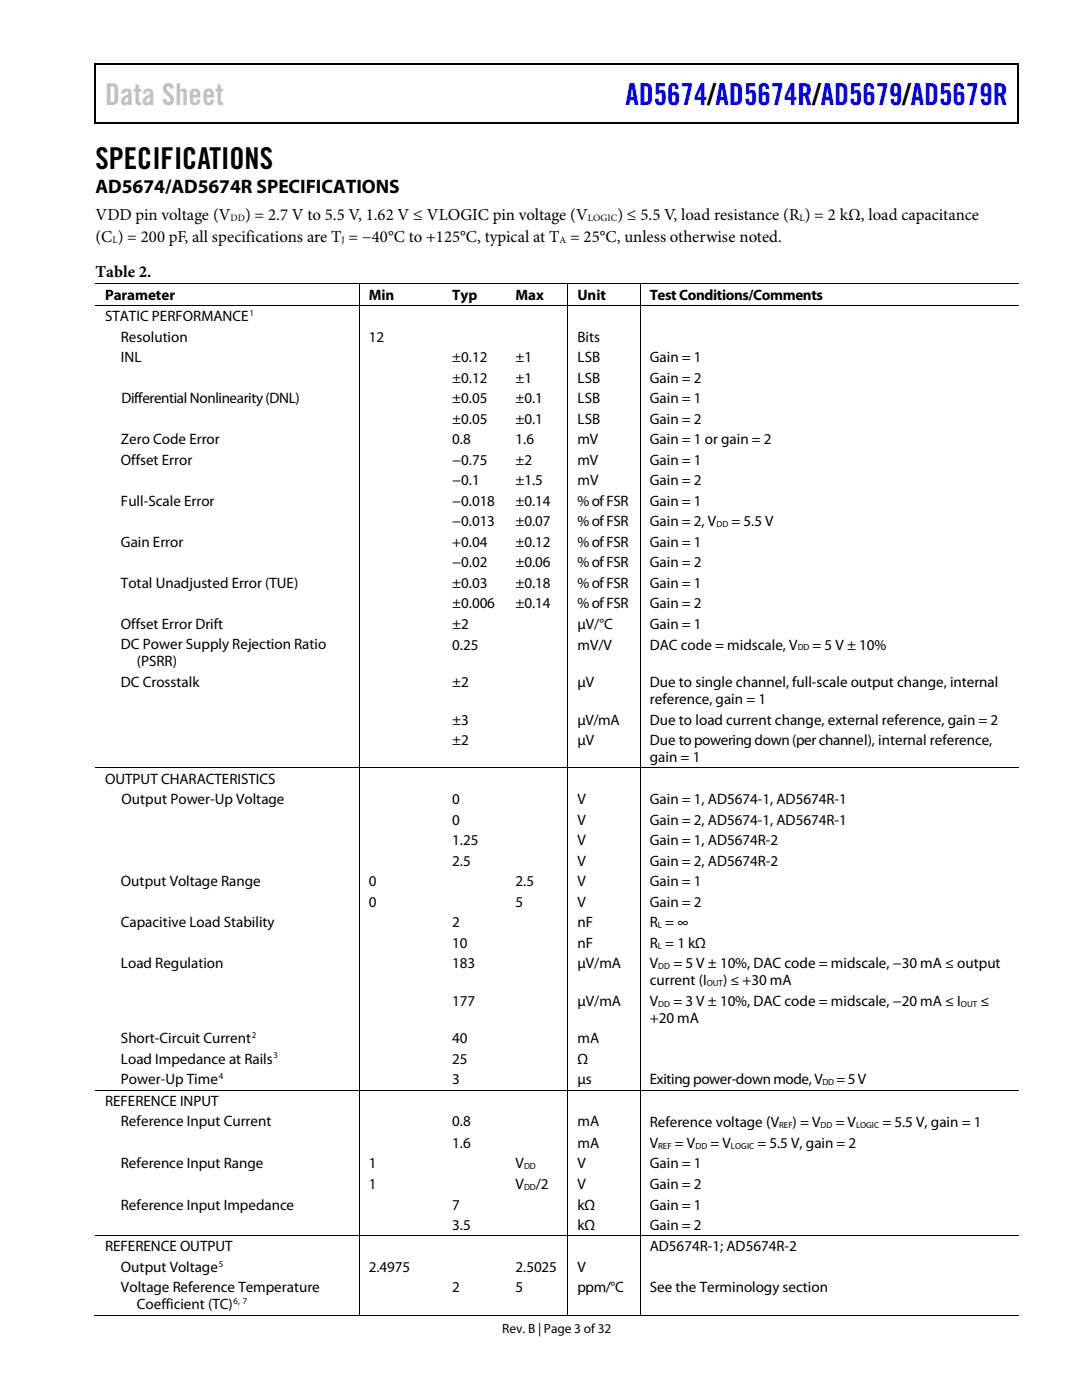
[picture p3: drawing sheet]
<svg xmlns="http://www.w3.org/2000/svg" width="216mm" height="279mm" viewBox="0 0 216 279" stroke-linecap="round" stroke-linejoin="round" font-family="sans-serif">
<defs><g id="words">
<text font-size="6" fill="#c1c1c1" x="21" y="21">Data Sheet</text>
<text font-size="6" fill="#00f" x="124.8" y="21">AD5674/AD5674R/AD5679/AD5679R</text>
<text font-size="6" x="19" y="33.7">SPECIFICATIONS</text>
<text font-size="3.9" x="19" y="38.5">AD5674/AD5674R SPECIFICATIONS</text>
<g font-size="3.3">
<text x="19" y="44">VDD pin voltage (V</text>
<text x="48.9" y="44">) = 2.7 V to 5.5 V, 1.62 V ≤ VLOGIC pin voltage (V</text>
<text x="123.2" y="44">) ≤ 5.5 V, load resistance (R ) = 2 kΩ, load capacitance</text>
<text x="19.1" y="48.3">(C ) = 200 pF, all specifications are T = −40°C to +125°C, typical at T = 25°C, unless otherwise noted.</text>
<text x="19.1" y="55.4">Table 2.</text>
</g>
<g font-size="3">
<text x="21" y="59.8">Parameter</text>
<text x="73.6" y="59.8">Min</text>
<text x="90.3" y="59.8">Typ</text>
<text x="102.9" y="59.8">Max</text>
<text x="115.2" y="59.8">Unit</text>
<text x="129.7" y="59.8">Test Conditions/Comments</text>
<text x="21" y="64.1">STATIC PERFORMANCE</text>
<text x="24.1" y="68.2">Resolution</text>
<text x="73.6" y="68.2">12</text>
<text x="115.2" y="68.2">Bits</text>
<text x="24.1" y="72.3">INL</text>
<text x="90.3" y="76.4">±0.12</text>
<text x="90.3" y="72.3">±0.12</text>
<text x="102.9" y="76.4">±1</text>
<text x="102.9" y="72.3">±1</text>
<text x="115.2" y="76.4">LSB</text>
<text x="115.2" y="72.3">LSB</text>
<text x="129.7" y="76.4">Gain = 2</text>
<text x="129.7" y="72.3">Gain = 1</text>
<text x="24.3" y="80.5">Differential Nonlinearity (DNL)</text>
<text x="90.3" y="80.5">±0.05</text>
<text x="102.9" y="80.5">±0.1</text>
<text x="115.2" y="80.5">LSB</text>
<text x="129.7" y="80.5">Gain = 1</text>
<text x="24.1" y="88.6">Zero Code Error</text>
<text x="90.3" y="88.6">0.8</text>
<text x="90.3" y="84.5">±0.05</text>
<text x="102.9" y="88.6">1.6</text>
<text x="102.9" y="84.5">±0.1</text>
<text x="115.2" y="88.6">mV</text>
<text x="115.2" y="84.5">LSB</text>
<text x="129.7" y="88.6">Gain = 1 or gain = 2</text>
<text x="129.7" y="84.5">Gain = 2</text>
<text x="24.1" y="92.8">Offset Error</text>
<text x="90.3" y="92.8">−0.75</text>
<text x="102.9" y="92.8">±2</text>
<text x="115.2" y="92.8">mV</text>
<text x="129.7" y="92.8">Gain = 1</text>
<text x="24.1" y="101">Full-Scale Error</text>
<text x="90.3" y="96.9">−0.1</text>
<text x="90.3" y="101">−0.018</text>
<text x="102.9" y="96.9">±1.5</text>
<text x="102.9" y="101">±0.14</text>
<text x="115.2" y="96.9">mV</text>
<text x="115.2" y="101">% of FSR</text>
<text x="129.7" y="96.9">Gain = 2</text>
<text x="129.7" y="101">Gain = 1</text>
<text x="90.3" y="105">−0.013</text>
<text x="102.9" y="105">±0.07</text>
<text x="115.2" y="105">% of FSR</text>
<text x="129.7" y="105">Gain = 2, V</text>
<text x="146" y="105">= 5.5 V</text>
<text x="24.1" y="109.1">Gain Error</text>
<text x="90.3" y="109.1">+0.04</text>
<text x="90.3" y="113.2">−0.02</text>
<text x="102.9" y="109.1">±0.12</text>
<text x="102.9" y="113.2">±0.06</text>
<text x="115.2" y="109.1">% of FSR</text>
<text x="115.2" y="113.2">% of FSR</text>
<text x="129.7" y="109.1">Gain = 1</text>
<text x="129.7" y="113.2">Gain = 2</text>
<text x="24.1" y="117.3">Total Unadjusted Error (TUE)</text>
<text x="90.3" y="117.3">±0.03</text>
<text x="102.9" y="117.3">±0.18</text>
<text x="115.2" y="117.3">% of FSR</text>
<text x="129.7" y="117.3">Gain = 1</text>
<text x="24.1" y="125.5">Offset Error Drift</text>
<text x="90.3" y="121.4">±0.006</text>
<text x="90.3" y="125.5">±2</text>
<text x="102.9" y="121.4">±0.14</text>
<text x="115.2" y="121.4">% of FSR</text>
<text x="115.2" y="125.5">µV/°C</text>
<text x="129.7" y="125.5">Gain = 1</text>
<text x="129.7" y="121.4">Gain = 2</text>
<text x="24.1" y="129.6">DC Power Supply Rejection Ratio</text>
<text x="90.3" y="129.6">0.25</text>
<text x="115.2" y="129.6">mV/V</text>
<text x="129.7" y="129.6">DAC code = midscale, V</text>
<text x="162.1" y="129.6">= 5 V ± 10%</text>
<text x="24.1" y="137.1">DC Crosstalk</text>
<text x="27.3" y="133">(PSRR)</text>
<text x="90.3" y="137.1">±2</text>
<text x="115.2" y="137.1">µV</text>
<text x="129.7" y="137.1">Due to single channel, full-scale output change, internal</text>
<text x="129.7" y="140.5">reference, gain = 1</text>
<text x="90.3" y="144.6">±3</text>
<text x="90.3" y="148.7">±2</text>
<text x="115.2" y="148.7">µV</text>
<text x="115.2" y="144.6">µV/mA</text>
<text x="129.7" y="148.7">Due to powering down (per channel), internal reference,</text>
<text x="129.7" y="144.6">Due to load current change, external reference, gain = 2</text>
<text x="129.7" y="152.1">gain = 1</text>
<text x="21" y="156.4">OUTPUT CHARACTERISTICS</text>
<text x="24.3" y="160.4">Output Power-Up Voltage</text>
<text x="90.3" y="160.4">0</text>
<text x="115.2" y="160.4">V</text>
<text x="129.7" y="160.4">Gain = 1, AD5674-1, AD5674R-1</text>
<text x="90.3" y="164.5">0</text>
<text x="115.2" y="164.5">V</text>
<text x="129.7" y="164.5">Gain = 2, AD5674-1, AD5674R-1</text>
<text x="90.3" y="168.7">1.25</text>
<text x="90.3" y="172.8">2.5</text>
<text x="115.2" y="168.7">V</text>
<text x="115.2" y="172.8">V</text>
<text x="129.7" y="168.7">Gain = 1, AD5674R-2</text>
<text x="129.7" y="172.8">Gain = 2, AD5674R-2</text>
<text x="24.1" y="176.9">Output Voltage Range</text>
<text x="73.6" y="176.9">0</text>
<text x="102.9" y="176.9">2.5</text>
<text x="115.2" y="176.9">V</text>
<text x="129.7" y="176.9">Gain = 1</text>
<text x="24.1" y="185">Capacitive Load Stability</text>
<text x="73.6" y="180.9">0</text>
<text x="90.3" y="185">2</text>
<text x="102.9" y="180.9">5</text>
<text x="115.2" y="180.9">V</text>
<text x="115.2" y="185">nF</text>
<text x="129.7" y="180.9">Gain = 2</text>
<text x="129.7" y="185">R = ∞</text>
<text x="90.3" y="189.1">10</text>
<text x="115.2" y="189.1">nF</text>
<text x="129.7" y="189.1">R = 1 kΩ</text>
<text x="24.1" y="193.3">Load Regulation</text>
<text x="90.3" y="193.3">183</text>
<text x="115.2" y="193.3">µV/mA</text>
<text x="129.7" y="196.6">current (I</text>
<text x="129.7" y="193.2">V</text>
<text x="134.4" y="193.2">= 5 V ± 10%, DAC code = midscale, −30 mA ≤ output</text>
<text x="144.3" y="196.6">) ≤ +30 mA</text>
<text x="90.3" y="200.7">177</text>
<text x="115.2" y="200.7">µV/mA</text>
<text x="129.7" y="200.7">V</text>
<text x="134.4" y="200.7">= 3 V ± 10%, DAC code = midscale, −20 mA ≤ I</text>
<text x="195.6" y="200.7">≤</text>
<text x="24.1" y="208.2">Short-Circuit Current</text>
<text x="90.3" y="208.2">40</text>
<text x="115.2" y="208.2">mA</text>
<text x="129.7" y="204.1">+20 mA</text>
<text x="24.1" y="212.3">Load Impedance at Rails</text>
<text x="90.3" y="212.3">25</text>
<text x="115.2" y="212.3">Ω</text>
<text x="21" y="220.7">REFERENCE INPUT</text>
<text x="24.1" y="216.4">Power-Up Time</text>
<text x="90.3" y="216.4">3</text>
<text x="115.2" y="216.4">µs</text>
<text x="129.7" y="216.4">Exiting power-down mode, V</text>
<text x="166.9" y="216.4">= 5 V</text>
<text x="24.1" y="224.8">Reference Input Current</text>
<text x="90.3" y="224.8">0.8</text>
<text x="115.2" y="224.8">mA</text>
<text x="129.7" y="224.9">Reference voltage (V</text>
<text x="158.2" y="224.9">) = V</text>
<text x="166.8" y="224.9">= V</text>
<text x="176.1" y="224.9">= 5.5 V, gain = 1</text>
<text x="24.1" y="233.2">Reference Input Range</text>
<text x="73.6" y="233.2">1</text>
<text x="90.3" y="229.1">1.6</text>
<text x="102.9" y="233.2">V</text>
<text x="115.2" y="229.1">mA</text>
<text x="115.2" y="233.2">V</text>
<text x="129.7" y="233.2">Gain = 1</text>
<text x="129.7" y="229.1">V</text>
<text x="134.7" y="229.1">= V</text>
<text x="141.8" y="229.1">= V</text>
<text x="151.1" y="229.1">= 5.5 V, gain = 2</text>
<text x="73.6" y="237.3">1</text>
<text x="102.9" y="237.3">V</text>
<text x="106.9" y="237.3">/2</text>
<text x="115.2" y="237.3">V</text>
<text x="129.7" y="237.3">Gain = 2</text>
<text x="24.1" y="241.4">Reference Input Impedance</text>
<text x="90.3" y="241.4">7</text>
<text x="90.3" y="245.4">3.5</text>
<text x="115.2" y="241.4">kΩ</text>
<text x="115.2" y="245.4">kΩ</text>
<text x="129.7" y="241.4">Gain = 1</text>
<text x="129.7" y="245.4">Gain = 2</text>
<text x="21" y="249.7">REFERENCE OUTPUT</text>
<text x="129.7" y="249.7">AD5674R-1; AD5674R-2</text>
<text x="24.1" y="253.8">Output Voltage</text>
<text x="24.1" y="257.9">Voltage Reference Temperature</text>
<text x="73.6" y="253.8">2.4975</text>
<text x="90.3" y="257.9">2</text>
<text x="102.9" y="257.9">5</text>
<text x="102.9" y="253.8">2.5025</text>
<text x="115.2" y="257.9">ppm/°C</text>
<text x="115.2" y="253.8">V</text>
<text x="129.7" y="257.9">See the Terminology section</text>
<text x="27.3" y="261.3">Coefficient (TC)</text>
</g>
<text font-size="2.7" x="100.2" y="266">Rev. B | Page 3 of32</text>
<g font-size="1.9">
<text x="46" y="44.2">DD</text>
<text x="117.3" y="44.2">LOGIC</text>
<text x="159.5" y="44.2">L</text>
<text x="22.4" y="48.4">L</text>
<text x="68.2" y="48.4">J</text>
<text x="111.6" y="48.4">A</text>
</g>
<g font-size="1.8">
<text x="49.8" y="63">1</text>
<text x="143" y="105.2">DD</text>
<text x="159.2" y="129.8">DD</text>
<text x="131.3" y="185.2">L</text>
<text x="131.3" y="189.3">L</text>
<text x="131.4" y="193.4">DD</text>
<text x="141" y="196.8">OUT</text>
<text x="131.4" y="200.9">DD</text>
<text x="191.7" y="200.9">OUT</text>
<text x="50.2" y="207.1">2</text>
<text x="43.6" y="215.3">4</text>
<text x="54.6" y="211.2">3</text>
<text x="164.1" y="216.6">DD</text>
<text x="155.4" y="225.1">REF</text>
<text x="163.7" y="225.1">DD</text>
<text x="170.8" y="225.1">LOGIC</text>
<text x="104.6" y="233.3">DD</text>
<text x="131.4" y="229.2">REF</text>
<text x="138.8" y="229.2">DD</text>
<text x="145.8" y="229.2">LOGIC</text>
<text x="104.6" y="237.4">DD</text>
<text x="43.6" y="252.8">5</text>
<text x="46.6" y="260.2">6, 7</text>
</g>
</g></defs>
<g fill="#000">
<path d="M18.9 12.7h.3v1h-.3zM18.9 12.7h.3v.3h-.3zM83.1 12.7h.3v.3h-.3zM202.9 12.7h.3v1h-.3zM202.9 12.7h.3v.3h-.3zM18.9 24.4h.3v.2h-.3zM82.9 24.4h.2v.2h-.2zM202.9 24.4h.3v.2h-.3zM71.6 56.6h.2v.1h-.2zM88.3 56.6h.2v.1h-.2zM101 56.6h.1v.1h-.1zM113.2 56.6h.2v.1h-.2z"/>
<path d="M127.7 56.6h.1v.1h-.1zM71.6 60.9h.2v.1h-.2zM88.3 60.9h.2v.1h-.2zM101 60.9h.1v.1h-.1zM113.2 60.9h.2v.1h-.2zM127.7 60.9h.1v.1h-.1zM71.6 153.2h.2v.1h-.2zM88.3 153.2h.2v.1h-.2zM101 153.2h.1v.1h-.1zM113.2 153.2h.2v.1h-.2zM127.7 153.2h.1v.1h-.1zM71.6 217.5h.2v.2h-.2z"/>
<path d="M88.3 217.5h.2v.2h-.2zM101 217.5h.1v.2h-.1zM113.2 217.5h.2v.2h-.2zM127.7 217.5h.1v.2h-.1zM71.6 246.5h.2v.2h-.2zM88.3 246.5h.2v.2h-.2zM101 246.5h.1v.2h-.1zM113.2 246.5h.2v.2h-.2zM127.7 246.5h.1v.2h-.1zM71.6 262.4h.2v.2h-.2zM88.1 262.4h.2v.2h-.2zM100.7 262.4h.2v.2h-.2z"/>
<path d="M113.2 262.4h.2v.2h-.2zM127.7 262.4h.1v.2h-.1z"/>
</g>
<path d="M19 13.7v10.7M19.2 12.8h63.9M83.4 12.8h119.5M203 13.7v10.7M19.2 24.5h183.7" fill="none" stroke="#000" stroke-width=".25"/>
<g fill="none" stroke="#000" stroke-width=".2">
<path d="M19 56.6h52.6M71.7 56.7v4.2M71.8 56.6h16.5M88.5 56.6h12.5M101.1 56.6h12.1M113.3 56.7v4.2M113.4 56.6h14.3M127.8 56.7v4.2M127.8 56.6h75.4M19 61h52.6M71.7 61v92.2M71.8 61h16.5"/>
<path d="M88.5 61h12.5M101.1 61h12.1M113.3 61v92.2M113.4 61h14.3M127.8 61v92.2M127.8 61h75.4M19 153.2h52.6M71.7 153.3v64.2M71.8 153.2h16.5M88.5 153.2h12.5M101.1 153.2h12.1M113.3 153.3v64.2"/>
<path d="M113.4 153.2h14.3M127.8 153.3v64.2M127.8 153.2h75.4M19 217.6h52.6M71.7 217.7v28.8M71.8 217.6h16.5M88.5 217.6h12.5M101.1 217.6h12.1M113.3 217.7v28.8M113.4 217.6h14.3M127.8 217.7v28.8M127.8 217.6h75.4"/>
<path d="M19 246.6h52.6M71.7 246.7v15.7M71.8 246.6h16.5M88.5 246.6h12.5M101.1 246.6h12.1M113.3 246.7v15.7M113.4 246.6h14.3M127.8 246.7v15.7M127.8 246.6h75.4M18.8 262.5h52.8M71.8 262.5h41.4M113.4 262.5h14.3"/>
<path d="M127.8 262.5h75.4"/>
</g>
<use href="#words"/>
</svg>
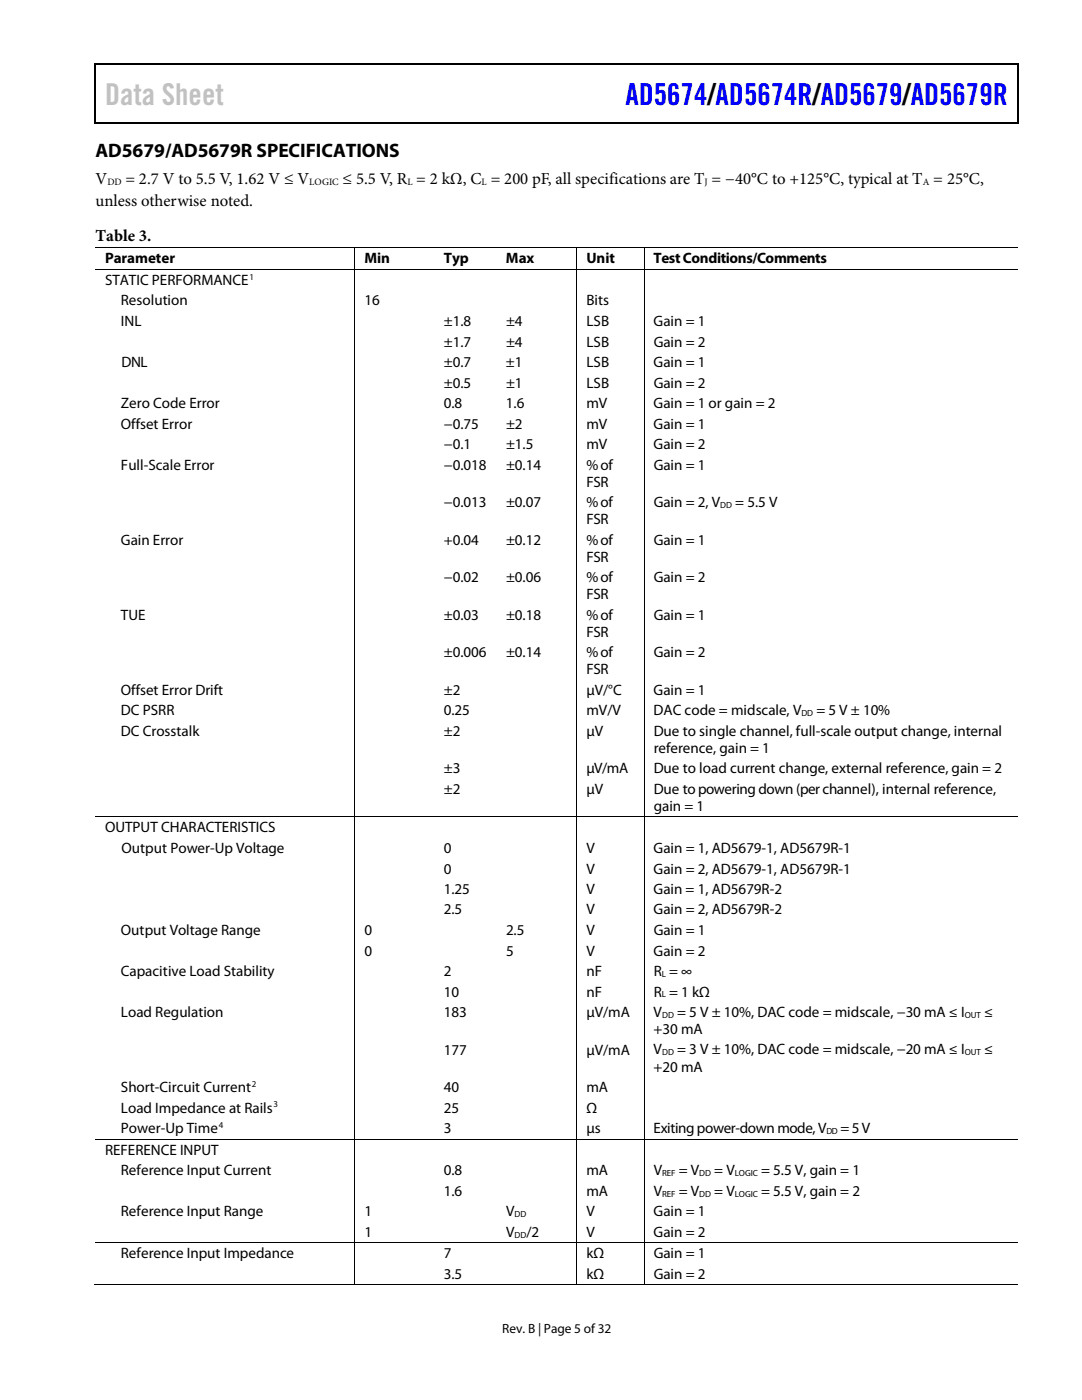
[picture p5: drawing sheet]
<svg xmlns="http://www.w3.org/2000/svg" width="216mm" height="279mm" viewBox="0 0 216 279" stroke-linecap="round" stroke-linejoin="round" font-family="sans-serif">
<defs><g id="words">
<text font-size="6" fill="#c1c1c1" x="21" y="21">Data Sheet</text>
<text font-size="6" fill="#00f" x="124.8" y="21">AD5674/AD5674R/AD5679/AD5679R</text>
<text font-size="3.9" x="19" y="31.3">AD5679/AD5679R SPECIFICATIONS</text>
<g font-size="3.3">
<text x="19" y="36.8">V</text>
<text x="19.1" y="41.1">unless otherwise noted.</text>
<text x="25.1" y="36.8">= 2.7 V to 5.5 V, 1.62 V ≤ V</text>
<text x="68.4" y="36.8">≤ 5.5 V, R = 2 kΩ, C = 200 pF, all specifications are T = −40°C to +125°C, typical at T = 25°C,</text>
<text x="19.1" y="48.2">Table 3.</text>
</g>
<g font-size="3">
<text x="21" y="52.6">Parameter</text>
<text x="72.7" y="52.6">Min</text>
<text x="88.6" y="52.6">Typ</text>
<text x="101" y="52.6">Max</text>
<text x="117" y="52.6">Unit</text>
<text x="130.4" y="52.6">Test Conditions/Comments</text>
<text x="21" y="56.9">STATIC PERFORMANCE</text>
<text x="24.1" y="61">Resolution</text>
<text x="24.1" y="65.1">INL</text>
<text x="72.7" y="61">16</text>
<text x="88.6" y="65.1">±1.8</text>
<text x="101" y="65.1">±4</text>
<text x="117" y="61">Bits</text>
<text x="117" y="65.1">LSB</text>
<text x="130.4" y="65.1">Gain = 1</text>
<text x="88.6" y="69.2">±1.7</text>
<text x="101" y="69.2">±4</text>
<text x="117" y="69.2">LSB</text>
<text x="130.4" y="69.2">Gain = 2</text>
<text x="24.3" y="73.3">DNL</text>
<text x="88.6" y="73.3">±0.7</text>
<text x="88.6" y="77.3">±0.5</text>
<text x="101" y="73.3">±1</text>
<text x="101" y="77.3">±1</text>
<text x="117" y="73.3">LSB</text>
<text x="117" y="77.3">LSB</text>
<text x="130.4" y="73.3">Gain = 1</text>
<text x="130.4" y="77.3">Gain = 2</text>
<text x="24.1" y="81.4">Zero Code Error</text>
<text x="88.6" y="81.4">0.8</text>
<text x="101" y="81.4">1.6</text>
<text x="117" y="81.4">mV</text>
<text x="130.4" y="81.4">Gain = 1 or gain = 2</text>
<text x="24.1" y="85.6">Offset Error</text>
<text x="88.6" y="85.6">−0.75</text>
<text x="88.6" y="89.7">−0.1</text>
<text x="101" y="85.6">±2</text>
<text x="101" y="89.7">±1.5</text>
<text x="117" y="89.7">mV</text>
<text x="117" y="85.6">mV</text>
<text x="130.4" y="89.7">Gain = 2</text>
<text x="130.4" y="85.6">Gain = 1</text>
<text x="24.1" y="93.8">Full-Scale Error</text>
<text x="88.6" y="93.8">−0.018</text>
<text x="101" y="93.8">±0.14</text>
<text x="117" y="93.7">% of</text>
<text x="130.4" y="93.8">Gain = 1</text>
<text x="88.6" y="101.2">−0.013</text>
<text x="101" y="101.2">±0.07</text>
<text x="117" y="97.1">FSR</text>
<text x="117" y="101.2">% of</text>
<text x="130.4" y="101.2">Gain = 2, V</text>
<text x="146.7" y="101.2">= 5.5 V</text>
<text x="117" y="104.6">FSR</text>
<text x="24.1" y="108.7">Gain Error</text>
<text x="88.6" y="108.7">+0.04</text>
<text x="101" y="108.7">±0.12</text>
<text x="117" y="108.7">% of</text>
<text x="117" y="112.1">FSR</text>
<text x="130.4" y="108.7">Gain = 1</text>
<text x="88.6" y="116.2">−0.02</text>
<text x="101" y="116.2">±0.06</text>
<text x="117" y="116.2">% of</text>
<text x="117" y="119.6">FSR</text>
<text x="130.4" y="116.2">Gain = 2</text>
<text x="24.1" y="123.7">TUE</text>
<text x="88.6" y="123.7">±0.03</text>
<text x="101" y="123.7">±0.18</text>
<text x="117" y="123.7">% of</text>
<text x="130.4" y="123.7">Gain = 1</text>
<text x="88.6" y="131.2">±0.006</text>
<text x="101" y="131.2">±0.14</text>
<text x="117" y="127.1">FSR</text>
<text x="117" y="131.1">% of</text>
<text x="130.4" y="131.2">Gain = 2</text>
<text x="117" y="134.5">FSR</text>
<text x="24.1" y="138.7">Offset Error Drift</text>
<text x="24.1" y="142.8">DC PSRR</text>
<text x="88.6" y="138.7">±2</text>
<text x="88.6" y="142.8">0.25</text>
<text x="117" y="142.8">mV/V</text>
<text x="117" y="138.7">µV/°C</text>
<text x="130.4" y="142.8">DAC code = midscale, V</text>
<text x="130.4" y="138.7">Gain = 1</text>
<text x="162.9" y="142.8">= 5 V ± 10%</text>
<text x="24.1" y="146.9">DC Crosstalk</text>
<text x="88.6" y="146.9">±2</text>
<text x="117" y="146.9">µV</text>
<text x="130.4" y="146.8">Due to single channel, full-scale output change, internal</text>
<text x="88.6" y="154.3">±3</text>
<text x="117" y="154.3">µV/mA</text>
<text x="130.4" y="154.3">Due to load current change, external reference, gain = 2</text>
<text x="130.4" y="150.2">reference, gain = 1</text>
<text x="88.6" y="158.5">±2</text>
<text x="117" y="158.5">µV</text>
<text x="130.4" y="158.4">Due to powering down (per channel), internal reference,</text>
<text x="130.4" y="161.8">gain = 1</text>
<text x="21" y="166.1">OUTPUT CHARACTERISTICS</text>
<text x="24.3" y="170.2">Output Power-Up Voltage</text>
<text x="88.6" y="170.2">0</text>
<text x="117" y="170.2">V</text>
<text x="130.4" y="170.2">Gain = 1, AD5679-1, AD5679R-1</text>
<text x="88.6" y="174.3">0</text>
<text x="88.6" y="178.4">1.25</text>
<text x="117" y="178.4">V</text>
<text x="117" y="174.3">V</text>
<text x="130.4" y="178.4">Gain = 1, AD5679R-2</text>
<text x="130.4" y="174.3">Gain = 2, AD5679-1, AD5679R-1</text>
<text x="88.6" y="182.5">2.5</text>
<text x="117" y="182.5">V</text>
<text x="130.4" y="182.5">Gain = 2, AD5679R-2</text>
<text x="24.1" y="186.6">Output Voltage Range</text>
<text x="72.7" y="186.6">0</text>
<text x="72.7" y="190.7">0</text>
<text x="101" y="186.6">2.5</text>
<text x="101" y="190.7">5</text>
<text x="117" y="186.6">V</text>
<text x="117" y="190.7">V</text>
<text x="130.4" y="190.7">Gain = 2</text>
<text x="130.4" y="186.6">Gain = 1</text>
<text x="24.1" y="194.8">Capacitive Load Stability</text>
<text x="88.6" y="194.8">2</text>
<text x="117" y="194.8">nF</text>
<text x="130.4" y="194.8">R = ∞</text>
<text x="24.1" y="203">Load Regulation</text>
<text x="88.6" y="198.9">10</text>
<text x="88.6" y="203">183</text>
<text x="117" y="198.9">nF</text>
<text x="117" y="203">µV/mA</text>
<text x="130.4" y="202.9">V</text>
<text x="130.4" y="198.9">R = 1 kΩ</text>
<text x="135.1" y="202.9">= 5 V ± 10%, DAC code = midscale, −30 mA ≤ I</text>
<text x="196.4" y="202.9">≤</text>
<text x="130.4" y="206.4">+30 mA</text>
<text x="88.6" y="210.5">177</text>
<text x="117" y="210.5">µV/mA</text>
<text x="130.4" y="213.9">+20 mA</text>
<text x="130.4" y="210.4">V</text>
<text x="135.1" y="210.4">= 3 V ± 10%, DAC code = midscale, −20 mA ≤ I</text>
<text x="196.4" y="210.4">≤</text>
<text x="24.1" y="218">Short-Circuit Current</text>
<text x="88.6" y="218">40</text>
<text x="117" y="218">mA</text>
<text x="24.1" y="222.1">Load Impedance at Rails</text>
<text x="24.1" y="226.2">Power-Up Time</text>
<text x="88.6" y="222.1">25</text>
<text x="88.6" y="226.2">3</text>
<text x="117" y="222.1">Ω</text>
<text x="117" y="226.2">µs</text>
<text x="130.4" y="226.2">Exiting power-down mode, V</text>
<text x="167.7" y="226.2">= 5 V</text>
<text x="21" y="230.5">REFERENCE INPUT</text>
<text x="24.1" y="234.5">Reference Input Current</text>
<text x="88.6" y="234.5">0.8</text>
<text x="88.6" y="238.6">1.6</text>
<text x="117" y="234.5">mA</text>
<text x="117" y="238.6">mA</text>
<text x="130.4" y="234.5">V</text>
<text x="130.4" y="238.6">V</text>
<text x="135.4" y="234.5">= V</text>
<text x="135.4" y="238.6">= V</text>
<text x="142.5" y="234.5">= V</text>
<text x="142.5" y="238.6">= V</text>
<text x="151.9" y="234.5">= 5.5 V, gain = 1</text>
<text x="151.9" y="238.6">= 5.5 V, gain = 2</text>
<text x="24.1" y="242.7">Reference Input Range</text>
<text x="72.7" y="242.7">1</text>
<text x="101" y="242.7">V</text>
<text x="117" y="242.7">V</text>
<text x="130.4" y="242.7">Gain = 1</text>
<text x="24.1" y="251.1">Reference Input Impedance</text>
<text x="72.7" y="246.8">1</text>
<text x="88.6" y="251.1">7</text>
<text x="101" y="246.8">V</text>
<text x="105" y="246.8">/2</text>
<text x="117" y="246.8">V</text>
<text x="117" y="251.1">kΩ</text>
<text x="130.4" y="246.8">Gain = 2</text>
<text x="130.4" y="251.1">Gain = 1</text>
<text x="88.6" y="255.2">3.5</text>
<text x="117" y="255.2">kΩ</text>
<text x="130.4" y="255.2">Gain = 2</text>
</g>
<text font-size="2.7" x="100.2" y="266">Rev. B | Page 5 of32</text>
<g font-size="1.9">
<text x="21.4" y="37">DD</text>
<text x="61.7" y="37">LOGIC</text>
<text x="81.3" y="37">L</text>
<text x="96.1" y="37">L</text>
<text x="140.6" y="37">J</text>
<text x="184.1" y="37">A</text>
</g>
<g font-size="1.8">
<text x="49.8" y="55.8">1</text>
<text x="143.7" y="101.4">DD</text>
<text x="159.9" y="143">DD</text>
<text x="132" y="195">L</text>
<text x="132" y="199.1">L</text>
<text x="132.1" y="203.1">DD</text>
<text x="192.5" y="203.1">OUT</text>
<text x="132.1" y="210.6">DD</text>
<text x="192.5" y="210.6">OUT</text>
<text x="50.2" y="216.9">2</text>
<text x="54.6" y="221">3</text>
<text x="43.6" y="225.1">4</text>
<text x="164.9" y="226.4">DD</text>
<text x="132.1" y="234.7">REF</text>
<text x="132.1" y="238.8">REF</text>
<text x="139.5" y="234.7">DD</text>
<text x="139.5" y="238.8">DD</text>
<text x="146.6" y="234.7">LOGIC</text>
<text x="146.6" y="238.8">LOGIC</text>
<text x="102.7" y="242.9">DD</text>
<text x="102.7" y="247">DD</text>
</g>
</g></defs>
<g fill="#000">
<path d="M18.9 12.7h.3v1h-.3zM18.9 12.7h.3v.3h-.3zM83.1 12.7h.3v.3h-.3zM202.9 12.7h.3v1h-.3zM202.9 12.7h.3v.3h-.3zM18.9 24.4h.3v.2h-.3zM82.9 24.4h.2v.2h-.2zM202.9 24.4h.3v.2h-.3zM70.7 49.4h.2v.1h-.2zM70.7 53.7h.2v.1h-.2zM86.7 49.4h.2v.1h-.2zM86.7 53.7h.2v.1h-.2z"/>
<path d="M99.1 49.4h.1v.1h-.1zM99.1 53.7h.1v.1h-.1zM115 49.4h.2v.1h-.2zM115 53.7h.2v.1h-.2zM128.4 49.4h.2v.1h-.2zM128.4 53.7h.2v.1h-.2zM70.7 162.9h.2v.2h-.2zM86.7 162.9h.2v.2h-.2zM99.1 162.9h.1v.2h-.1zM115 162.9h.2v.2h-.2zM128.4 162.9h.2v.2h-.2zM70.7 227.2h.2v.2h-.2z"/>
<path d="M86.7 227.2h.2v.2h-.2zM99.1 227.2h.1v.2h-.1zM115 227.2h.2v.2h-.2zM128.4 227.2h.2v.2h-.2zM70.7 247.9h.2v.2h-.2zM70.7 256.3h.2v.2h-.2zM86.4 256.3h.2v.2h-.2zM86.7 247.9h.2v.2h-.2zM98.8 256.3h.2v.2h-.2zM99.1 247.9h.1v.2h-.1zM115 247.9h.2v.2h-.2zM115 256.3h.2v.2h-.2z"/>
<path d="M128.4 247.9h.2v.2h-.2zM128.4 256.3h.2v.2h-.2z"/>
</g>
<path d="M19 13.7v10.7M19.2 12.8h63.9M83.4 12.8h119.5M203 13.7v10.7M19.2 24.5h183.7" fill="none" stroke="#000" stroke-width=".25"/>
<g fill="none" stroke="#000" stroke-width=".2">
<path d="M19 49.4h51.7M19 53.8h51.7M70.8 49.5v4.2M70.8 53.8v109.1M70.9 49.4h15.8M70.9 53.8h15.8M86.9 49.4h12.2M86.9 53.8h12.2M99.2 49.4h15.8M99.2 53.8h15.8M115.1 49.5v4.2M115.1 53.8v109.1"/>
<path d="M115.2 49.4h13.2M115.2 53.8h13.2M128.5 49.5v4.2M128.5 53.8v109.1M128.6 49.4h74.6M128.6 53.8h74.6M19 163h51.7M70.8 163.1v64.1M70.9 163h15.8M86.9 163h12.2M99.2 163h15.8M115.1 163.1v64.1"/>
<path d="M115.2 163h13.2M128.5 163.1v64.1M128.6 163h74.6M19 227.3h51.7M70.8 227.4v20.5M70.9 227.3h15.8M86.9 227.3h12.2M99.2 227.3h15.8M115.1 227.4v20.5M115.2 227.3h13.2M128.5 227.4v20.5M128.6 227.3h74.6"/>
<path d="M18.8 256.4h51.9M19 248h51.7M70.8 248.1v8.2M70.9 248h15.8M70.9 256.4h44.1M86.9 248h12.2M99.2 248h15.8M115.1 248.1v8.2M115.2 248h13.2M115.2 256.4h13.2M128.5 248.1v8.2M128.6 248h74.6"/>
<path d="M128.6 256.4h74.6"/>
</g>
<use href="#words"/>
</svg>
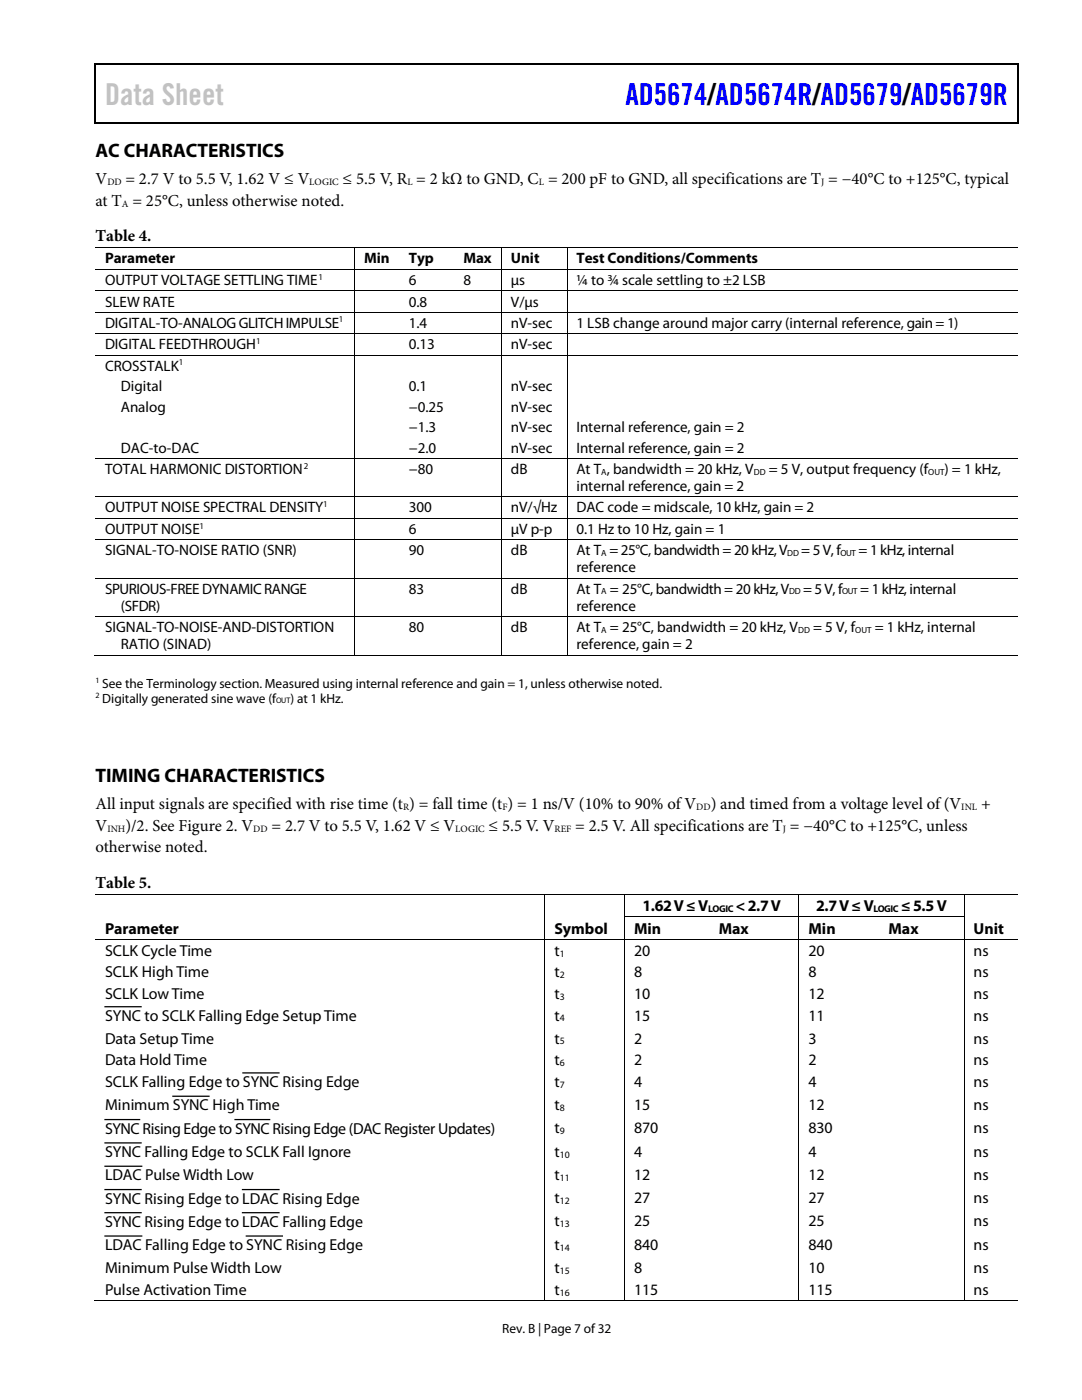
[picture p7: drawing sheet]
<svg xmlns="http://www.w3.org/2000/svg" width="216mm" height="279mm" viewBox="0 0 216 279" stroke-linecap="round" stroke-linejoin="round" font-family="sans-serif">
<defs><g id="words">
<text font-size="6" fill="#c1c1c1" x="21" y="21">Data Sheet</text>
<text font-size="6" fill="#00f" x="124.8" y="21">AD5674/AD5674R/AD5679/AD5679R</text>
<g font-size="3.9">
<text x="19" y="31.3">AC CHARACTERISTICS</text>
<text x="19" y="156.1">TIMING CHARACTERISTICS</text>
</g>
<g font-size="3.3">
<text x="19" y="36.8">V</text>
<text x="19.1" y="41.1">at T = 25°C, unless otherwise noted.</text>
<text x="25.1" y="36.8">= 2.7 V to 5.5 V, 1.62 V ≤ V</text>
<text x="68.4" y="36.8">≤ 5.5 V, R = 2 kΩ to GND, C = 200 pF to GND, all specifications are T = −40°C to +125°C, typical</text>
<text x="19" y="48.2">Table 4.</text>
<text x="19" y="161.5">All input signals are specified with rise time (t ) = fall time (t ) = 1 ns/V (10% to 90% of V</text>
<text x="141.8" y="161.5">) and timed from a voltage level of (V</text>
<text x="195.7" y="161.5">+</text>
<text x="19.1" y="165.8">V</text>
<text x="25" y="165.8">)/2. See Figure 2. V</text>
<text x="54.2" y="165.8">= 2.7 V to 5.5 V, 1.62 V ≤ V</text>
<text x="97.5" y="165.8">≤ 5.5 V. V</text>
<text x="114.8" y="165.8">= 2.5 V. All specifications are T = −40°C to +125°C, unless</text>
<text x="19.1" y="170.1">otherwise noted.</text>
<text x="19.1" y="177.2">Table 5.</text>
</g>
<g font-size="3.2">
<text x="128.2" y="181.8">1.62 V≤ V</text>
<text x="146.9" y="181.8">&lt;2.7 V</text>
<text x="162.9" y="181.8">2.7 V≤ V</text>
<text x="179.8" y="181.8">≤5.5V</text>
<text x="21" y="186.3">Parameter</text>
<text x="21" y="190.8">SCLK Cycle Time</text>
<text x="110.6" y="186.3">Symbol</text>
<text x="110.6" y="190.8">t</text>
<text x="126.5" y="186.3">Min</text>
<text x="126.5" y="190.8">20</text>
<text x="143.4" y="186.3">Max</text>
<text x="161.3" y="190.8">20</text>
<text x="161.3" y="186.3">Min</text>
<text x="177.3" y="186.3">Max</text>
<text x="194.3" y="186.3">Unit</text>
<text x="194.3" y="190.8">ns</text>
<text x="21" y="195.1">SCLK High Time</text>
<text x="110.6" y="195.1">t</text>
<text x="126.5" y="195.1">8</text>
<text x="161.3" y="195.1">8</text>
<text x="194.3" y="195.1">ns</text>
<text x="21" y="199.3">SCLK Low Time</text>
<text x="21" y="203.8">SYNC to SCLK Falling Edge Setup Time</text>
<text x="110.6" y="203.7">t</text>
<text x="110.6" y="199.3">t</text>
<text x="126.5" y="199.3">10</text>
<text x="126.5" y="203.7">15</text>
<text x="161.3" y="199.3">12</text>
<text x="161.3" y="203.7">11</text>
<text x="194.3" y="199.3">ns</text>
<text x="194.3" y="203.7">ns</text>
<text x="21" y="208.3">Data Setup Time</text>
<text x="110.6" y="208.3">t</text>
<text x="126.5" y="208.3">2</text>
<text x="161.3" y="208.3">3</text>
<text x="194.3" y="208.3">ns</text>
<text x="21" y="212.6">Data Hold Time</text>
<text x="110.6" y="212.6">t</text>
<text x="126.5" y="212.6">2</text>
<text x="161.3" y="212.6">2</text>
<text x="194.3" y="212.6">ns</text>
<text x="21" y="216.9">SCLK Falling Edge to SYNC Rising Edge</text>
<text x="21" y="221.6">Minimum SYNC High Time</text>
<text x="110.6" y="216.9">t</text>
<text x="110.6" y="221.5">t</text>
<text x="126.5" y="216.9">4</text>
<text x="126.5" y="221.5">15</text>
<text x="161.3" y="216.9">4</text>
<text x="161.3" y="221.5">12</text>
<text x="194.3" y="216.9">ns</text>
<text x="194.3" y="221.5">ns</text>
<text x="21" y="226.3">SYNC Rising Edge to SYNC Rising Edge (DAC Register Updates)</text>
<text x="110.6" y="226.2">t</text>
<text x="126.5" y="226.2">870</text>
<text x="161.3" y="226.2">830</text>
<text x="194.3" y="226.2">ns</text>
<text x="21" y="230.9">SYNC Falling Edge to SCLK Fall Ignore</text>
<text x="110.6" y="230.8">t</text>
<text x="126.5" y="230.8">4</text>
<text x="161.3" y="230.8">4</text>
<text x="194.3" y="230.8">ns</text>
<text x="21" y="235.6">LDAC Pulse Width Low</text>
<text x="110.6" y="235.5">t</text>
<text x="126.5" y="235.5">12</text>
<text x="161.3" y="235.5">12</text>
<text x="194.3" y="235.5">ns</text>
<text x="21" y="240.2">SYNC Rising Edge to LDAC Rising Edge</text>
<text x="21" y="244.9">SYNC Rising Edge to LDAC Falling Edge</text>
<text x="110.6" y="240.2">t</text>
<text x="110.6" y="244.8">t</text>
<text x="126.5" y="240.2">27</text>
<text x="126.5" y="244.8">25</text>
<text x="161.3" y="240.2">27</text>
<text x="161.3" y="244.8">25</text>
<text x="194.3" y="240.2">ns</text>
<text x="194.3" y="244.8">ns</text>
<text x="21" y="249.5">LDAC Falling Edge to SYNC Rising Edge</text>
<text x="110.6" y="249.4">t</text>
<text x="126.5" y="249.4">840</text>
<text x="161.3" y="249.4">840</text>
<text x="194.3" y="249.4">ns</text>
<text x="21" y="254.1">Minimum Pulse Width Low</text>
<text x="110.6" y="254.1">t</text>
<text x="126.5" y="254.1">8</text>
<text x="161.3" y="254.1">10</text>
<text x="194.3" y="254.1">ns</text>
<text x="21" y="258.4">Pulse Activation Time</text>
<text x="110.6" y="258.4">t</text>
<text x="126.5" y="258.4">115</text>
<text x="161.3" y="258.4">115</text>
<text x="194.3" y="258.4">ns</text>
</g>
<g font-size="3">
<text x="21" y="52.6">Parameter</text>
<text x="72.6" y="52.6">Min</text>
<text x="81.6" y="52.6">Typ</text>
<text x="92.5" y="52.6">Max</text>
<text x="101.9" y="52.6">Unit</text>
<text x="115" y="52.6">Test Conditions/Comments</text>
<text x="21" y="56.9">OUTPUT VOLTAGE SETTLING TIME</text>
<text x="81.6" y="56.9">6</text>
<text x="92.5" y="56.9">8</text>
<text x="101.9" y="56.9">µs</text>
<text x="115" y="56.9">¼ to ¾ scale settling to ±2 LSB</text>
<text x="21" y="61.2">SLEW RATE</text>
<text x="21" y="65.4">DIGITAL-TO-ANALOG GLITCH IMPULSE</text>
<text x="81.6" y="65.4">1.4</text>
<text x="81.6" y="61.2">0.8</text>
<text x="101.9" y="65.4">nV-sec</text>
<text x="101.9" y="61.2">V/µs</text>
<text x="115" y="65.4">1 LSB change around major carry (internal reference, gain = 1)</text>
<text x="21" y="69.7">DIGITAL FEEDTHROUGH</text>
<text x="81.6" y="69.7">0.13</text>
<text x="101.9" y="69.7">nV-sec</text>
<text x="21" y="74">CROSSTALK</text>
<text x="24.1" y="78.1">Digital</text>
<text x="24.1" y="82.2">Analog</text>
<text x="81.6" y="78.1">0.1</text>
<text x="81.6" y="82.2">−0.25</text>
<text x="101.9" y="78.1">nV-sec</text>
<text x="101.9" y="82.2">nV-sec</text>
<text x="81.6" y="86.3">−1.3</text>
<text x="101.9" y="86.3">nV-sec</text>
<text x="115" y="86.3">Internal reference, gain = 2</text>
<text x="21" y="94.6">TOTAL HARMONIC DISTORTION</text>
<text x="24.1" y="90.3">DAC-to-DAC</text>
<text x="81.6" y="94.6">−80</text>
<text x="81.6" y="90.3">−2.0</text>
<text x="101.9" y="94.6">dB</text>
<text x="101.9" y="90.3">nV-sec</text>
<text x="115" y="94.6">At T , bandwidth = 20 kHz, V</text>
<text x="115" y="90.3">Internal reference, gain = 2</text>
<text x="153.4" y="94.6">= 5 V, output frequency (f</text>
<text x="188.5" y="94.6">) = 1 kHz,</text>
<text x="115" y="98">internal reference, gain = 2</text>
<text x="21" y="102.3">OUTPUT NOISE SPECTRAL DENSITY</text>
<text x="21" y="106.6">OUTPUT NOISE</text>
<text x="81.6" y="102.3">300</text>
<text x="81.6" y="106.6">6</text>
<text x="101.9" y="102.3">nV/√Hz</text>
<text x="101.9" y="106.6">µV p-p</text>
<text x="115" y="102.3">DAC code = midscale, 10 kHz, gain = 2</text>
<text x="115" y="106.6">0.1 Hz to 10 Hz, gain = 1</text>
<text x="21" y="110.8">SIGNAL-TO-NOISE RATIO (SNR)</text>
<text x="81.6" y="110.8">90</text>
<text x="101.9" y="110.8">dB</text>
<text x="115" y="110.8">At T = 25°C, bandwidth = 20 kHz, V</text>
<text x="159.9" y="110.8">= 5 V, f</text>
<text x="171.3" y="110.8">= 1 kHz,internal</text>
<text x="21" y="118.4">SPURIOUS-FREE DYNAMIC RANGE</text>
<text x="81.6" y="118.5">83</text>
<text x="101.9" y="118.5">dB</text>
<text x="115" y="114.2">reference</text>
<text x="115" y="118.4">At T = 25°C, bandwidth = 20 kHz, V</text>
<text x="160.2" y="118.4">= 5 V, f</text>
<text x="171.7" y="118.4">= 1 kHz,internal</text>
<text x="24.1" y="121.9">(SFDR)</text>
<text x="115" y="121.9">reference</text>
<text x="21" y="126.1">SIGNAL-TO-NOISE-AND-DISTORTION</text>
<text x="24.1" y="129.5">RATIO (SINAD)</text>
<text x="81.6" y="126.2">80</text>
<text x="101.9" y="126.2">dB</text>
<text x="115" y="126.1">At T = 25°C, bandwidth = 20 kHz, V</text>
<text x="115" y="129.5">reference, gain = 2</text>
<text x="162.3" y="126.1">= 5 V, f</text>
<text x="174.5" y="126.1">= 1 kHz, internal</text>
</g>
<g font-size="2.7">
<text x="20.4" y="137.3">See the Terminology section. Measured using internal reference and gain = 1, unless otherwise noted.</text>
<text x="20.4" y="140.2">Digitally generated sine wave (f</text>
<text x="58" y="140.2">) at 1 kHz.</text>
<text x="100.2" y="266">Rev. B | Page 7 of32</text>
</g>
<g font-size="1.9">
<text x="21.4" y="37">DD</text>
<text x="24.3" y="41.2">A</text>
<text x="61.7" y="37">LOGIC</text>
<text x="81.3" y="37">L</text>
<text x="107.5" y="37">L</text>
<text x="163.9" y="37">J</text>
<text x="80.4" y="161.7">R</text>
<text x="100.2" y="161.7">F</text>
<text x="138.9" y="161.7">DD</text>
<text x="191.8" y="161.7">INL</text>
<text x="21.4" y="166">INH</text>
<text x="50.5" y="166">DD</text>
<text x="90.8" y="166">LOGIC</text>
<text x="110.7" y="166">REF</text>
<text x="156.2" y="166">J</text>
<text x="141.3" y="181.9">LOGIC</text>
<text x="174.3" y="181.9">LOGIC</text>
<text x="111.7" y="190.9">1</text>
<text x="111.7" y="195.2">2</text>
<text x="111.7" y="199.5">3</text>
<text x="111.7" y="203.8">4</text>
<text x="111.7" y="208.4">5</text>
<text x="111.7" y="212.8">6</text>
<text x="111.7" y="217">7</text>
<text x="111.7" y="221.7">8</text>
<text x="111.7" y="226.4">9</text>
<text x="111.7" y="231">10</text>
<text x="111.7" y="235.7">11</text>
<text x="111.7" y="240.3">12</text>
<text x="111.7" y="244.9">13</text>
<text x="111.7" y="249.6">14</text>
<text x="111.7" y="254.3">15</text>
<text x="111.7" y="258.6">16</text>
</g>
<g font-size="1.8">
<text x="63.5" y="55.8">1</text>
<text x="67.6" y="64.3">1</text>
<text x="51.1" y="68.6">1</text>
<text x="35.7" y="72.9">1</text>
<text x="60.6" y="93.6">2</text>
<text x="120" y="94.7">A</text>
<text x="150.4" y="94.7">DD</text>
<text x="185.2" y="94.7">OUT</text>
<text x="64.5" y="101.2">1</text>
<text x="39.8" y="105.5">1</text>
<text x="120" y="111">A</text>
<text x="157.1" y="111">DD</text>
<text x="167.7" y="111">OUT</text>
<text x="120" y="118.6">A</text>
<text x="157.5" y="118.6">DD</text>
<text x="168.1" y="118.6">OUT</text>
<text x="120" y="126.3">A</text>
<text x="159.3" y="126.3">DD</text>
<text x="170.6" y="126.3">OUT</text>
</g>
<g font-size="1.6">
<text x="19" y="136.4">1</text>
<text x="19" y="139.3">2</text>
<text x="55.1" y="140.4">OUT</text>
</g>
</g></defs>
<g fill="#000">
<path d="M18.9 12.7h.3v1h-.3zM18.9 12.7h.3v.3h-.3zM83.1 12.7h.3v.3h-.3zM202.9 12.7h.3v1h-.3zM202.9 12.7h.3v.3h-.3zM18.9 24.4h.3v.2h-.3zM82.9 24.4h.2v.2h-.2zM202.9 24.4h.3v.2h-.3zM70.7 49.4h.1v.1h-.1zM70.7 53.7h.1v.1h-.1zM70.7 58h.1v.1h-.1zM79.7 49.4h.2v.1h-.2z"/>
<path d="M79.7 53.7h.2v.1h-.2zM79.7 58h.2v.1h-.2zM90.6 49.4h.1v.1h-.1zM90.6 53.7h.1v.1h-.1zM90.6 58h.1v.1h-.1zM99.9 49.4h.2v.1h-.2zM99.9 53.7h.2v.1h-.2zM99.9 58h.2v.1h-.2zM113.1 49.4h.1v.1h-.1zM113.1 53.7h.1v.1h-.1zM113.1 58h.1v.1h-.1zM70.7 62.2h.1v.2h-.1z"/>
<path d="M70.7 66.5h.1v.2h-.1zM70.7 70.8h.1v.2h-.1zM79.7 62.2h.2v.2h-.2zM79.7 66.5h.2v.2h-.2zM79.7 70.8h.2v.2h-.2zM90.6 62.2h.1v.2h-.1zM90.6 66.5h.1v.2h-.1zM90.6 70.8h.1v.2h-.1zM99.9 62.2h.2v.2h-.2zM99.9 66.5h.2v.2h-.2zM99.9 70.8h.2v.2h-.2zM113.1 62.2h.1v.2h-.1z"/>
<path d="M113.1 66.5h.1v.2h-.1zM113.1 70.8h.1v.2h-.1zM70.7 91.4h.1v.2h-.1zM70.7 99.1h.1v.2h-.1zM79.7 91.4h.2v.2h-.2zM79.7 99.1h.2v.2h-.2zM90.6 91.4h.1v.2h-.1zM90.6 99.1h.1v.2h-.1zM99.9 91.4h.2v.2h-.2zM99.9 99.1h.2v.2h-.2zM113.1 91.4h.1v.2h-.1zM113.1 99.1h.1v.2h-.1z"/>
<path d="M70.7 103.4h.1v.1h-.1zM70.7 107.7h.1v.1h-.1zM70.7 115.3h.1v.2h-.1zM79.7 103.4h.2v.1h-.2zM79.7 107.7h.2v.1h-.2zM79.7 115.3h.2v.2h-.2zM90.6 103.4h.1v.1h-.1zM90.6 107.7h.1v.1h-.1zM90.6 115.3h.1v.2h-.1zM99.9 103.4h.2v.1h-.2zM99.9 107.7h.2v.1h-.2zM99.9 115.3h.2v.2h-.2z"/>
<path d="M113.1 103.4h.1v.1h-.1zM113.1 107.7h.1v.1h-.1zM113.1 115.3h.1v.2h-.1zM70.7 123h.1v.1h-.1zM70.7 130.7h.1v.2h-.1zM79.5 130.7h.1v.2h-.1zM79.7 123h.2v.1h-.2zM90.3 130.7h.2v.2h-.2zM90.6 123h.1v.1h-.1zM99.9 123h.2v.1h-.2zM99.9 130.7h.2v.2h-.2zM113.1 123h.1v.1h-.1z"/>
<path d="M113.1 130.7h.1v.2h-.1zM108.6 178.4h.2v.2h-.2zM124.5 178.4h.2v.2h-.2zM159.3 178.4h.2v.2h-.2zM192.3 178.4h.1v.2h-.1zM108.6 182.9h.2v.2h-.2zM108.6 187.5h.2v.1h-.2zM124.5 182.9h.2v.2h-.2zM124.5 187.5h.2v.1h-.2zM141.5 182.9h.2v.2h-.2zM141.5 187.5h.2v.1h-.2zM159.3 182.9h.2v.2h-.2z"/>
<path d="M159.3 187.5h.2v.1h-.2zM175.4 182.9h.2v.2h-.2zM175.4 187.5h.2v.1h-.2zM192.3 182.9h.1v.2h-.1zM192.3 187.5h.1v.1h-.1zM108.6 259.5h.2v.2h-.2zM124.5 259.5h.2v.2h-.2zM141.3 259.5h.1v.2h-.1zM159.3 259.5h.2v.2h-.2zM175.1 259.5h.2v.2h-.2zM192.3 259.5h.1v.2h-.1z"/>
</g>
<g fill="none" stroke="#000" stroke-width=".25">
<path d="M19 13.7v10.7M19.2 12.8h63.9M83.4 12.8h119.5M203 13.7v10.7M19.2 24.5h183.7M21 200.9h7.2M34.5 218.8h7.2M48.5 214.1h7.2M21 223.4h6.9M21 228.1h7.2M21 232.7h7.3M21 237.4h7.2"/>
<path d="M46.9 223.4h6.9M48.4 237.4h7.3M21 242h7.2M21 246.7h7.3M48.4 242h7.3M49.1 246.7h7.2"/>
</g>
<g fill="none" stroke="#000" stroke-width=".2">
<path d="M19 49.4h51.7M19 53.8h51.7M19 58h51.7M70.7 49.5v4.2M70.7 53.8v4.2M70.7 58.1v4.1M70.8 49.4h8.9M70.8 53.8h8.9M70.8 58h8.9M79.9 49.4h10.7M79.9 53.8h10.7M79.9 58h10.7"/>
<path d="M90.7 49.4h9.2M90.7 53.8h9.2M90.7 58h9.2M100 49.5v4.2M100 53.8v4.2M100 58.1v4.1M100.1 49.4h13M100.1 53.8h13M100.1 58h13M113.2 49.5v4.2M113.2 53.8v4.2M113.2 58.1v4.1"/>
<path d="M113.2 49.4h90M113.2 53.8h90M113.2 58h90M19 62.3h51.7M19 66.6h51.7M19 70.9h51.7M70.7 62.4v4.1M70.7 66.7v4.1M70.7 71v20.4M70.8 62.3h8.9M70.8 66.6h8.9M70.8 70.9h8.9"/>
<path d="M79.9 62.3h10.7M79.9 66.6h10.7M79.9 70.9h10.7M90.7 62.3h9.2M90.7 66.6h9.2M90.7 70.9h9.2M100 62.4v4.1M100 66.7v4.1M100 71v20.4M100.1 62.3h13M100.1 66.6h13M100.1 70.9h13"/>
<path d="M113.2 62.4v4.1M113.2 66.7v4.1M113.2 71v20.4M113.2 62.3h90M113.2 66.6h90M113.2 70.9h90M19 91.5h51.7M19 99.2h51.7M70.7 91.6v7.5M70.7 99.3v4.1M70.8 91.5h8.9M70.8 99.2h8.9"/>
<path d="M79.9 91.5h10.7M79.9 99.2h10.7M90.7 91.5h9.2M90.7 99.2h9.2M100 91.6v7.5M100 99.3v4.1M100.1 91.5h13M100.1 99.2h13M113.2 91.6v7.5M113.2 99.3v4.1M113.2 91.5h90M113.2 99.2h90"/>
<path d="M19 103.5h51.7M19 107.7h51.7M19 115.4h51.7M70.7 103.5v4.2M70.7 107.8v7.5M70.7 115.5v7.5M70.8 103.5h8.9M70.8 107.7h8.9M70.8 115.4h8.9M79.9 103.5h10.7M79.9 107.7h10.7M79.9 115.4h10.7"/>
<path d="M90.7 103.5h9.2M90.7 107.7h9.2M90.7 115.4h9.2M100 103.5v4.2M100 107.8v7.5M100 115.5v7.5M100.1 103.5h13M100.1 107.7h13M100.1 115.4h13M113.2 103.5v4.2M113.2 107.8v7.5M113.2 115.5v7.5"/>
<path d="M113.2 103.5h90M113.2 107.7h90M113.2 115.4h90M18.8 130.8h51.9M19 123.1h51.7M70.7 123.1v7.6M70.8 123.1h8.9M70.8 130.8h29.1M79.9 123.1h10.7M90.7 123.1h9.2M100 123.1v7.6M100.1 123.1h13"/>
<path d="M100.1 130.8h13M113.2 123.1v7.6M113.2 123.1h90M113.2 130.8h90M19 178.5h89.6M108.7 178.6v4.3M108.8 178.5h15.7M124.6 178.6v4.3M124.7 178.5h34.6M159.4 178.6v4.3M159.5 178.5h32.8M192.4 178.6v4.3"/>
<path d="M192.4 178.5h10.8M19 187.5h89.6M108.7 183.1v4.4M108.7 187.6v71.9M108.8 187.5h15.7M124.6 183.1v4.4M124.6 187.6v71.9M124.7 183h16.8M124.7 187.5h16.8M141.7 183h17.6M141.7 187.5h17.6M159.4 183.1v4.4"/>
<path d="M159.4 187.6v71.9M159.5 183h15.9M159.5 187.5h15.9M175.6 183h16.7M175.6 187.5h16.7M192.4 183.1v4.4M192.4 187.6v71.9M192.4 187.5h10.8M18.8 259.6h89.8M108.8 259.6h15.7M124.7 259.6h34.6M159.5 259.6h32.8"/>
<path d="M192.4 259.6h10.8"/>
</g>
<use href="#words"/>
</svg>
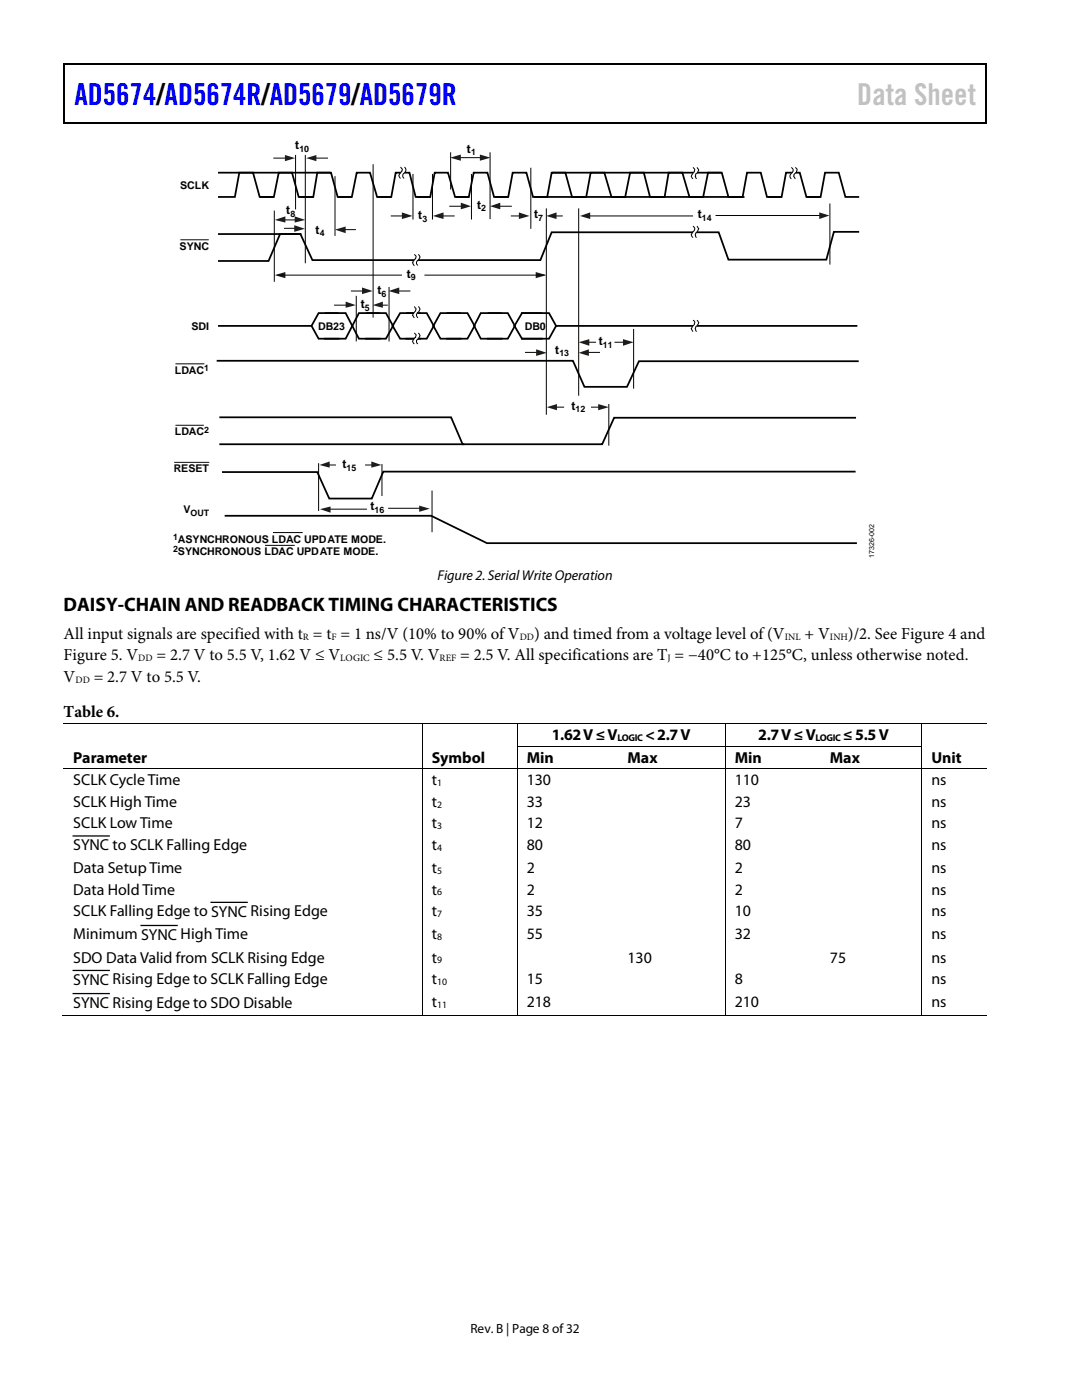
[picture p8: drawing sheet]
<svg xmlns="http://www.w3.org/2000/svg" width="216mm" height="279mm" viewBox="0 0 216 279" stroke-linecap="round" stroke-linejoin="round" font-family="sans-serif">
<defs><g id="words">
<text font-size="6" fill="#00f" x="14.9" y="21">AD5674/AD5674R/AD5679/AD5679R</text>
<text font-size="6" fill="#c1c1c1" x="171.1" y="21">Data Sheet</text>
<text font-size="3.9" x="12.7" y="122">DAISY-CHAIN AND READBACK TIMING CHARACTERISTICS</text>
<g font-size="3.3">
<text x="12.7" y="131.7">Figure 5. V</text>
<text x="12.7" y="127.5">All input signals are specified with t = t = 1 ns/V (10% to 90% of V</text>
<text x="31.2" y="131.7">= 2.7 V to 5.5 V, 1.62 V ≤ V</text>
<text x="74.5" y="131.7">≤ 5.5 V. V</text>
<text x="91.8" y="131.7">= 2.5 V. All specifications are T = −40°C to +125°C, unless otherwise noted.</text>
<text x="106.6" y="127.5">) and timed from a voltage level of (V</text>
<text x="160.5" y="127.5">+ V</text>
<text x="169.2" y="127.5">)/2. See Figure 4 and</text>
<text x="12.7" y="136.1">V</text>
<text x="18.7" y="136.1">= 2.7 V to 5.5 V.</text>
<text x="12.7" y="143.1">Table 6.</text>
</g>
<g font-size="3.2">
<text x="110.1" y="147.7">1.62 V≤V</text>
<text x="128.8" y="147.7">&lt;2.7 V</text>
<text x="151.3" y="147.7">2.7 V≤V</text>
<text x="168.3" y="147.7">≤5.5V</text>
<text x="14.6" y="152.2">Parameter</text>
<text x="86.1" y="152.2">Symbol</text>
<text x="105.1" y="152.2">Min</text>
<text x="125.2" y="152.2">Max</text>
<text x="146.6" y="152.2">Min</text>
<text x="165.6" y="152.2">Max</text>
<text x="185.8" y="152.2">Unit</text>
<text x="14.6" y="156.7">SCLK Cycle Time</text>
<text x="14.6" y="161">SCLK High Time</text>
<text x="86.2" y="156.7">t</text>
<text x="86.2" y="161">t</text>
<text x="105.1" y="156.7">130</text>
<text x="105.1" y="161">33</text>
<text x="146.6" y="156.7">110</text>
<text x="146.6" y="161">23</text>
<text x="185.8" y="156.7">ns</text>
<text x="185.8" y="161">ns</text>
<text x="14.6" y="165.3">SCLK Low Time</text>
<text x="86.2" y="165.3">t</text>
<text x="105.1" y="165.3">12</text>
<text x="146.6" y="165.3">7</text>
<text x="185.8" y="165.3">ns</text>
<text x="14.6" y="169.7">SYNC to SCLK Falling Edge</text>
<text x="86.1" y="169.6">t</text>
<text x="105.1" y="169.6">80</text>
<text x="146.6" y="169.6">80</text>
<text x="185.8" y="169.6">ns</text>
<text x="14.6" y="174.2">Data Setup Time</text>
<text x="14.6" y="178.5">Data Hold Time</text>
<text x="86.1" y="178.5">t</text>
<text x="86.1" y="174.2">t</text>
<text x="105.1" y="174.2">2</text>
<text x="105.1" y="178.5">2</text>
<text x="146.6" y="174.2">2</text>
<text x="146.6" y="178.5">2</text>
<text x="185.8" y="174.2">ns</text>
<text x="185.8" y="178.5">ns</text>
<text x="14.6" y="182.9">SCLK Falling Edge to SYNC Rising Edge</text>
<text x="86.1" y="182.8">t</text>
<text x="105.1" y="182.8">35</text>
<text x="146.6" y="182.8">10</text>
<text x="185.8" y="182.8">ns</text>
<text x="14.6" y="187.5">Minimum SYNC High Time</text>
<text x="86.1" y="187.5">t</text>
<text x="105.1" y="187.5">55</text>
<text x="146.6" y="187.5">32</text>
<text x="185.8" y="187.5">ns</text>
<text x="14.6" y="192.1">SDO Data Valid from SCLK Rising Edge</text>
<text x="14.6" y="196.5">SYNC Rising Edge to SCLK Falling Edge</text>
<text x="86.1" y="196.4">t</text>
<text x="86.1" y="192.1">t</text>
<text x="105.1" y="196.4">15</text>
<text x="125.2" y="192.1">130</text>
<text x="146.6" y="196.4">8</text>
<text x="165.6" y="192.1">75</text>
<text x="185.8" y="192.1">ns</text>
<text x="185.8" y="196.4">ns</text>
<text x="14.6" y="201.1">SYNC Rising Edge to SDO Disable</text>
<text x="86.1" y="201">t</text>
<text x="105.1" y="201">218</text>
<text x="146.6" y="201">210</text>
<text x="185.8" y="201">ns</text>
</g>
<text font-size="2.8" x="87.3" y="115.7">Figure 2. Serial Write Operation</text>
<text font-size="2.7" x="93.9" y="266">Rev. B | Page 8 of32</text>
<g font-size="2.5">
<text x="58.9" y="29.7">t</text>
<text x="93.2" y="30.5">t</text>
<text x="95.2" y="41.7">t</text>
<text x="57.1" y="42.7">t</text>
<text x="63" y="46.6">t</text>
<text x="83.5" y="43.7">t</text>
<text x="106.6" y="43.5">t</text>
<text x="139.2" y="43.5">t</text>
<text x="75.3" y="58.7">t</text>
<text x="81.1" y="55.4">t</text>
<text x="72" y="61.5">t</text>
<text x="110.8" y="70.6">t</text>
<text x="119.5" y="68.8">t</text>
<text x="114" y="81.8">t</text>
<text x="68.3" y="93.4">t</text>
<text x="73.9" y="101.9">t</text>
</g>
<g font-size="2.1">
<text x="36" y="37.8">SCLK</text>
<text x="35.8" y="49.8">SYNC</text>
<text x="38.2" y="65.8">SDI</text>
<text x="63.5" y="65.8">DB23</text>
<text x="104.7" y="65.9">DB0</text>
<text x="34.9" y="74.6">LDAC</text>
<text x="34.9" y="86.9">LDAC</text>
<text x="34.7" y="94.3">RESET</text>
<text x="36.6" y="102.4">V</text>
<text x="35.5" y="108.3">ASYNCHRONOUS LDAC UPDATE MODE.</text>
<text x="35.5" y="110.8">SYNCHRONOUS LDAC UPDATE MODE.</text>
</g>
<g font-size="1.9">
<text x="27.6" y="131.9">DD</text>
<text x="60.5" y="127.6">R</text>
<text x="66.2" y="127.6">F</text>
<text x="67.9" y="131.9">LOGIC</text>
<text x="87.7" y="131.9">REF</text>
<text x="103.7" y="127.6">DD</text>
<text x="133.2" y="131.9">J</text>
<text x="156.6" y="127.6">INL</text>
<text x="165.6" y="127.6">INH</text>
<text x="15.1" y="136.2">DD</text>
<text x="123.2" y="147.9">LOGIC</text>
<text x="162.7" y="147.9">LOGIC</text>
<text x="87.2" y="156.8">1</text>
<text x="87.2" y="161.2">2</text>
<text x="87.2" y="165.4">3</text>
<text x="87.2" y="169.8">4</text>
<text x="87.2" y="174.4">5</text>
<text x="87.2" y="178.7">6</text>
<text x="87.2" y="183">7</text>
<text x="87.2" y="187.6">8</text>
<text x="87.2" y="192.3">9</text>
<text x="87.2" y="196.6">10</text>
<text x="87.2" y="201.2">11</text>
</g>
<g font-size="1.8">
<text x="59.7" y="30.2">10</text>
<text x="94" y="31">1</text>
<text x="57.9" y="43.2">8</text>
<text x="63.8" y="47.1">4</text>
<text x="84.3" y="44.2">3</text>
<text x="96" y="42.2">2</text>
<text x="107.4" y="44.1">7</text>
<text x="140" y="44.1">14</text>
<text x="76.1" y="59.2">6</text>
<text x="82" y="55.9">9</text>
<text x="72.8" y="62">5</text>
<text x="111.6" y="71.1">13</text>
<text x="120.3" y="69.4">11</text>
<text x="40.8" y="74.1">1</text>
<text x="114.8" y="82.3">12</text>
<text x="40.8" y="86.3">2</text>
<text x="69.1" y="93.9">15</text>
<text x="34.5" y="107.8">1</text>
<text x="38" y="102.9">OUT</text>
<text x="74.7" y="102.4">16</text>
<text x="34.5" y="110.3">2</text>
</g>
<text font-size="1.4" x="174.4" y="111.3" transform="rotate(-90 174.4 111.3)">17326-002</text>
</g></defs>
<g fill="#000">
<path d="M12.7 12.7h.3v1h-.3zM12.7 12.7h.3v.3h-.3zM132.7 12.7h.2v.3h-.2zM196.6 12.7h.2v1h-.2zM196.6 12.7h.2v.3h-.2zM12.7 24.4h.3v.2h-.3zM132.4 24.4h.3v.2h-.3zM196.6 24.4h.2v.2h-.2zM84.2 144.3h.1v.2h-.1zM84.2 148.8h.1v.2h-.1zM84.2 153.4h.1v.1h-.1zM103.1 144.3h.2v.2h-.2z"/>
<path d="M103.1 148.8h.2v.2h-.2zM103.1 153.4h.2v.1h-.2zM123.3 148.8h.2v.2h-.2zM123.3 153.4h.2v.1h-.2zM144.6 144.3h.2v.2h-.2zM144.6 148.8h.2v.2h-.2zM144.6 153.4h.2v.1h-.2zM163.7 148.8h.2v.2h-.2zM163.7 153.4h.2v.1h-.2zM183.9 144.3h.1v.2h-.1zM183.9 148.8h.1v.2h-.1zM183.9 153.4h.1v.1h-.1z"/>
<path d="M84.2 202.6h.1v.1h-.1zM103.1 202.6h.2v.1h-.2zM123.1 202.6h.1v.1h-.1zM144.6 202.6h.2v.1h-.2zM163.4 202.6h.2v.1h-.2zM183.9 202.6h.1v.1h-.1z"/>
</g>
<path d="M12.8 13.7v10.7M13 12.8h119.7M132.9 12.8h63.7M196.7 13.7v10.7M13 24.5h183.6M14.6 166.8h7.2M14.6 193.7h7.2M14.6 198.3h7.2M28.2 184.7h7.1M42.1 180.1h7.2" fill="none" stroke="#000" stroke-width=".25"/>
<g fill="none" stroke="#000" stroke-width=".2">
<path d="M12.7 144.4h71.5M12.7 153.5h71.5M84.2 144.5v4.3M84.2 149v4.4M84.2 153.5v49.1M84.3 144.4h18.8M84.3 153.5h18.8M103.2 144.5v4.3M103.2 149v4.4M103.2 153.5v49.1M103.3 144.4h41.3M103.3 148.9h20"/>
<path d="M103.3 153.5h20M123.5 148.9h21.1M123.5 153.5h21.1M144.7 144.5v4.3M144.7 149v4.4M144.7 153.5v49.1M144.8 144.4h39.1M144.8 148.9h18.9M144.8 153.5h18.9M163.9 148.9h20M163.9 153.5h20M183.9 144.5v4.3"/>
<path d="M183.9 149v4.4M183.9 153.5v49.1M184 144.4h12.8M184 153.5h12.8M12.4 202.6h71.8M84.3 202.6h18.8M103.3 202.6h41.3M144.8 202.6h39.1M184 202.6h12.8"/>
</g>
<g fill="none" stroke="#000" stroke-width=".35">
<path d="M43.7 39.3h3.2l.8-4.8h2.8l1.3 4.8h2.7M43.7 34.5h22.1M52.1 39.3h2.5l1-4.8h2.7l1.3 4.8h2.7M59.9 39.3h2.6l.8-4.8h2.7l1.4 4.8h2.6M67.6 39.3h2.6l1-4.8h2.6l1.4 4.8h2.7M75.5 39.3h2.6l.9-4.8h2.7l1.2 4.8h2.8M83.3 39.3h2.6l.8-4.8h2.7l1.4 4.8h2.7M91.1 39.3h2.4l1-4.8h2.8l1.3 4.8h2.6M98.8 39.3h2.6l.9-4.8h2.7l1.4 4.8h2.6M106.7 39.3h2.5l.9-4.8h2.7l1.3 4.8h2.7M110.3 34.5h33.5M114.4 39.3h2.6l.9-4.8h2.7l1.4 4.8h2.6"/>
<path d="M122.2 39.3h2.6l.9-4.8h2.8l1.2 4.8h2.7M130.1 39.3h2.5l.8-4.8h2.8l1.4 4.8h2.5M137.7 39.3h2.6l1-4.8h2.7l1.4 4.8h2.6h-38.7M145.6 39.3h2.6l.9-4.8h2.7l1.2 4.8h2.8M153.4 39.3h2.6l.8-4.8h2.8l1.3 4.8h2.7M161.2 39.3h2.5l.9-4.8h2.8l1.3 4.8h2.6M43.7 46.7h16.2M107.8 51.9h-45.5l-2.4-5.2h-4l-2.3 5.4h-9.9M171.3 46.3h-4.9l-1.5 5.5h-19.5l-2-5.4h-33.3l-2.2 5.4M62.2 65l1.4 2.6h4M65 62.5h4l1.3 2.5M67.4 62.5h-3.8l-1.4 2.5h-18.5"/>
<path d="M70.3 65l-1.3 2.6h-4.2M70.3 65l1.3 2.6h4.2M73.2 62.5h3.8l1.4 2.5-1.4 2.6h-4M75.6 62.5h-4l-1.3 2.5M81.3 62.5h3.8l1.5 2.5-1.5 2.6h-4M83.7 62.5h-3.9l-1.5 2.5 1.5 2.6h4M89.3 62.5h4l1.4 2.5-1.4 2.6h-4.1M91.8 62.5h-3.9l-1.4 2.5 1.4 2.6h4M97.5 62.5h3.8l1.4 2.5-1.4 2.6h-4M99.9 62.5h-4l-1.3 2.5 1.3 2.6h4.2M104.2 62.5h5.3l1.5 2.5M108 62.5h-3.8l-1.5 2.5 1.5 2.6h3.9"/>
<path d="M170.9 65h-59.9l-1.5 2.6h-5.3"/>
</g>
<path d="M66.8 35.3v11.7M68.3 45.8h2.6" fill="none" stroke="#070200" stroke-width=".2"/>
<g fill="#1e1b18">
<path d="M66.8 45.8l2.2-.6v1.3z"/>
<path d="M54.8 54.9l2.1-.6v1.2z"/>
</g>
<path d="M60.9 31v21.4M74.4 32.9v30.4M86.3 34.8v8.9M89.9 30.5v7.2M97.8 30.5v13.1M54.7 42.1v14M71.1 59.1v8.9M89.7 41.2h2.7M109 41.7v41M115.5 41.7v37.2" fill="none" stroke="#070200" stroke-width=".2"/>
<path d="M92 40.5l2 .7-2 .6z" fill="#1e1b18"/>
<path d="M56.1 43.9h3.3" fill="none" stroke="#070200" stroke-width=".2"/>
<g fill="#1e1b18">
<path d="M54.8 43.9l2.1-.7v1.2z"/>
<path d="M58.8 43.2l2.1 .7-2.1 .5z"/>
</g>
<path d="M102 43.1h2" fill="none" stroke="#070200" stroke-width=".2"/>
<path d="M103.5 42.4l2.2 .7-2.2 .6z" fill="#1e1b18"/>
<path d="M99.4 41.2h2.6" fill="none" stroke="#070200" stroke-width=".2"/>
<path d="M97.8 41.2l2-.7v1.3z" fill="#1e1b18"/>
<path d="M88 43.1h2.6" fill="none" stroke="#070200" stroke-width=".2"/>
<path d="M86.4 43.1l2.1-.7v1.3z" fill="#1e1b18"/>
<path d="M78.1 43.1h2.4" fill="none" stroke="#070200" stroke-width=".2"/>
<g fill="#1e1b18">
<path d="M80.2 42.4l2.1 .7-2.1 .6z"/>
<path d="M106.9 54.3l2.1 .6-2.1 .6z"/>
</g>
<path d="M110.7 43.1h1.5M117.6 43.1h20.6" fill="none" stroke="#070200" stroke-width=".2"/>
<g fill="#1e1b18">
<path d="M109 43.1l2-.7v1.3z"/>
<path d="M115.7 43.1l2.1-.7v1.3z"/>
</g>
<path d="M142.9 43h20.7" fill="none" stroke="#070200" stroke-width=".2"/>
<path d="M163.5 42.4l2 .6-2 .7z" fill="#1e1b18"/>
<path d="M82.4 34.8v8.9M91.4 31.5h4.8M94.1 34.8v8.9" fill="none" stroke="#070200" stroke-width=".2"/>
<g fill="#1e1b18">
<path d="M89.8 31.5l2.2-.7v1.3z"/>
<path d="M95.8 30.8l2.1 .7-2.1 .6z"/>
</g>
<path d="M77.6 57.4v10.6M76 60.9h1.3" fill="none" stroke="#070200" stroke-width=".2"/>
<path d="M74.4 60.9l2-.7v1.2z" fill="#1e1b18"/>
<path d="M66.8 60.9h2.5" fill="none" stroke="#070200" stroke-width=".2"/>
<path d="M69 60.2l2 .7-2 .5z" fill="#1e1b18"/>
<path d="M70.1 58.1h2.7" fill="none" stroke="#070200" stroke-width=".2"/>
<path d="M72.2 57.4l2.2 .7-2.2 .6z" fill="#1e1b18"/>
<path d="M79.2 58.1h2.6" fill="none" stroke="#070200" stroke-width=".2"/>
<path d="M77.5 58.1l2.2-.7v1.3z" fill="#1e1b18"/>
<path d="M55.4 54.9h24.7M56.8 45.6h2.5M84.8 54.9h23.8" fill="none" stroke="#070200" stroke-width=".2"/>
<path d="M58.7 44.9l2.1 .8-2.1 .6z" fill="#1e1b18"/>
<path d="M59 31v10.7M62.7 31.6h2.6" fill="none" stroke="#070200" stroke-width=".2"/>
<path d="M61.1 31.6l2-.7v1.3z" fill="#1e1b18"/>
<path d="M54.6 31.6h2.7" fill="none" stroke="#070200" stroke-width=".2"/>
<path d="M56.9 30.9l2 .7-2 .6z" fill="#1e1b18"/>
<path d="M105.9 33.6v12M165.6 40.7v12M122.7 68.3h2.4M126.4 65.7v11.8" fill="none" stroke="#070200" stroke-width=".2"/>
<path d="M43.4 72h70.9l2.3 5.2h8.5l2.4-5.1h43.7" fill="none" stroke="#000" stroke-width=".35"/>
<path d="M124.3 67.7l2.1 .6-2.1 .7z" fill="#1e1b18"/>
<path d="M117.1 68.3h1.7" fill="none" stroke="#070200" stroke-width=".2"/>
<path d="M115.5 68.3l2.1-.6v1.3z" fill="#1e1b18"/>
<path d="M43.9 83.3h46.1l2.3 5.4h27.9l2.3-5.3h48.1" fill="none" stroke="#000" stroke-width=".35"/>
<path d="M118 81.3h2.2M121.5 80.7v8.1" fill="none" stroke="#070200" stroke-width=".2"/>
<path d="M119.4 80.6l2.1 .7-2.1 .6z" fill="#1e1b18"/>
<path d="M110.5 81.3h2" fill="none" stroke="#070200" stroke-width=".2"/>
<path d="M109.1 81.3l2-.7v1.3z" fill="#1e1b18"/>
<path d="M43.9 88.7h48.6" fill="none" stroke="#000" stroke-width=".35"/>
<path d="M117.1 70.3h2.5" fill="none" stroke="#070200" stroke-width=".2"/>
<path d="M115.5 70.4l2-.7v1.3z" fill="#1e1b18"/>
<path d="M104.9 70.3h2.4" fill="none" stroke="#070200" stroke-width=".2"/>
<path d="M107 69.7l2.1 .7-2.1 .6z" fill="#1e1b18"/>
<path d="M170.5 94.1h-94l-2.3 5.4h-8.5l-2.4-5.3h-18.8" fill="none" stroke="#000" stroke-width=".35"/>
<path d="M65.3 92.8h1.6" fill="none" stroke="#070200" stroke-width=".2"/>
<path d="M63.8 92.8l2-.7v1.2z" fill="#1e1b18"/>
<path d="M72.9 92.8h1.6" fill="none" stroke="#070200" stroke-width=".2"/>
<path d="M74.1 92.1l2 .7-2 .5z" fill="#1e1b18"/>
<path d="M63.6 92.5v9.4M86.2 98v8.1M65.5 101.6h7.6" fill="none" stroke="#070200" stroke-width=".2"/>
<path d="M45 102.9h41l11.2 5.5h73.6" fill="none" stroke="#000" stroke-width=".35"/>
<path d="M63.8 101.6l2.2-.5v1.2z" fill="#1e1b18"/>
<path d="M76.2 92.7v6.2M77.5 101.4h6.6" fill="none" stroke="#070200" stroke-width=".2"/>
<path d="M83.6 100.9l2.2 .6-2.2 .6z" fill="#1e1b18"/>
<path d="M36 47.9h5.6M35 72.6h5.8M34.8 92.3h6.9M35 84.9h5.7" fill="none" stroke="#1e1b18" stroke-width=".2"/>
<path d="M36 47.9h5.6M35 72.6h5.8M34.8 92.3h6.9M35 84.9h5.7" fill="none" stroke="#1a1818" stroke-width=".2"/>
<path d="M80.4 33.3l.1 .3a.96 .96 0 0 1-.4 1.1l-.1 .6 .3 .3M138.7 33.4l.2 .3a.96 .96 0 0 1-.4 1.1l-.1 .5 .2 .4M158.3 33.4a.85 .85 0 0 1-.2 1.4l-.1 .5 .3 .4M83.1 50.8a.72 .72 0 0 1-.2 1.2l-.1 .6 .2 .5M138.7 45.1l.2 .3a.96 .96 0 0 1-.4 1.1l-.1 .6 .2 .3M83.1 61.2a.72 .72 0 0 1-.2 1.2l-.1 .6 .2 .5M83.1 66.5a.72 .72 0 0 1-.2 1.2l-.1 .6 .2 .4M138.7 63.9a.72 .72 0 0 1-.2 1.2l-.1 .6 .2 .5" fill="none" stroke="#fff" stroke-width=".62" stroke-linecap="butt"/>
<g fill="none" stroke="#000" stroke-width=".2">
<path d="M79.9 33.3l.2 .3a.77 .77 0 0 1-.4 1.1l-.1 .4 .3 .5M80.7 33.3a.85 .85 0 0 1-.2 1.4l-.1 .6 .2 .3M138.3 33.4l.2 .3a.96 .96 0 0 1-.4 1.1 .52 .52 0 0 0 .2 .9M139.1 33.4a.72 .72 0 0 1-.2 1.2l-.2 .6 .3 .5M157.9 33.4l.3 .3a.96 .96 0 0 1-.5 1.1l-.1 .5 .3 .4M158.7 33.4l.3 .3a.89 .89 0 0 1-.6 1.1l-.1 .4 .4 .5M82.7 50.8l.3 .3-.1 .5a.81 .81 0 0 0-.2 1.5M83.5 50.8a.72 .72 0 0 1-.2 1.2l-.2 .6 .3 .4M138.3 45.1a.88 .88 0 0 1-.2 1.4 .52 .52 0 0 0 .2 .9M139.1 45.1a.85 .85 0 0 1-.3 1.4l-.1 .4 .3 .5M82.7 61.2l.1 .2a.77 .77 0 0 1-.4 1.2l-.1 .3 .4 .6M82.7 66.5l.3 .3-.1 .5a.75 .75 0 0 0-.5 .6 .75 .75 0 0 0 .3 .8"/>
<path d="M83.5 61.2a.72 .72 0 0 1-.2 1.2l-.2 .6 .3 .5M83.5 66.5a.72 .72 0 0 1-.2 1.2l-.2 .6 .3 .4M138.3 63.9l.2 .2a1.02 1.02 0 0 1-.4 1.2 .35 .35 0 0 0 0 .6l.2 .3M139.1 63.9a.72 .72 0 0 1-.2 1.2l-.2 .5 .3 .6M52.9 108.8h5.9M54.5 106.3h5.9"/>
</g>
<use href="#words"/>
</svg>
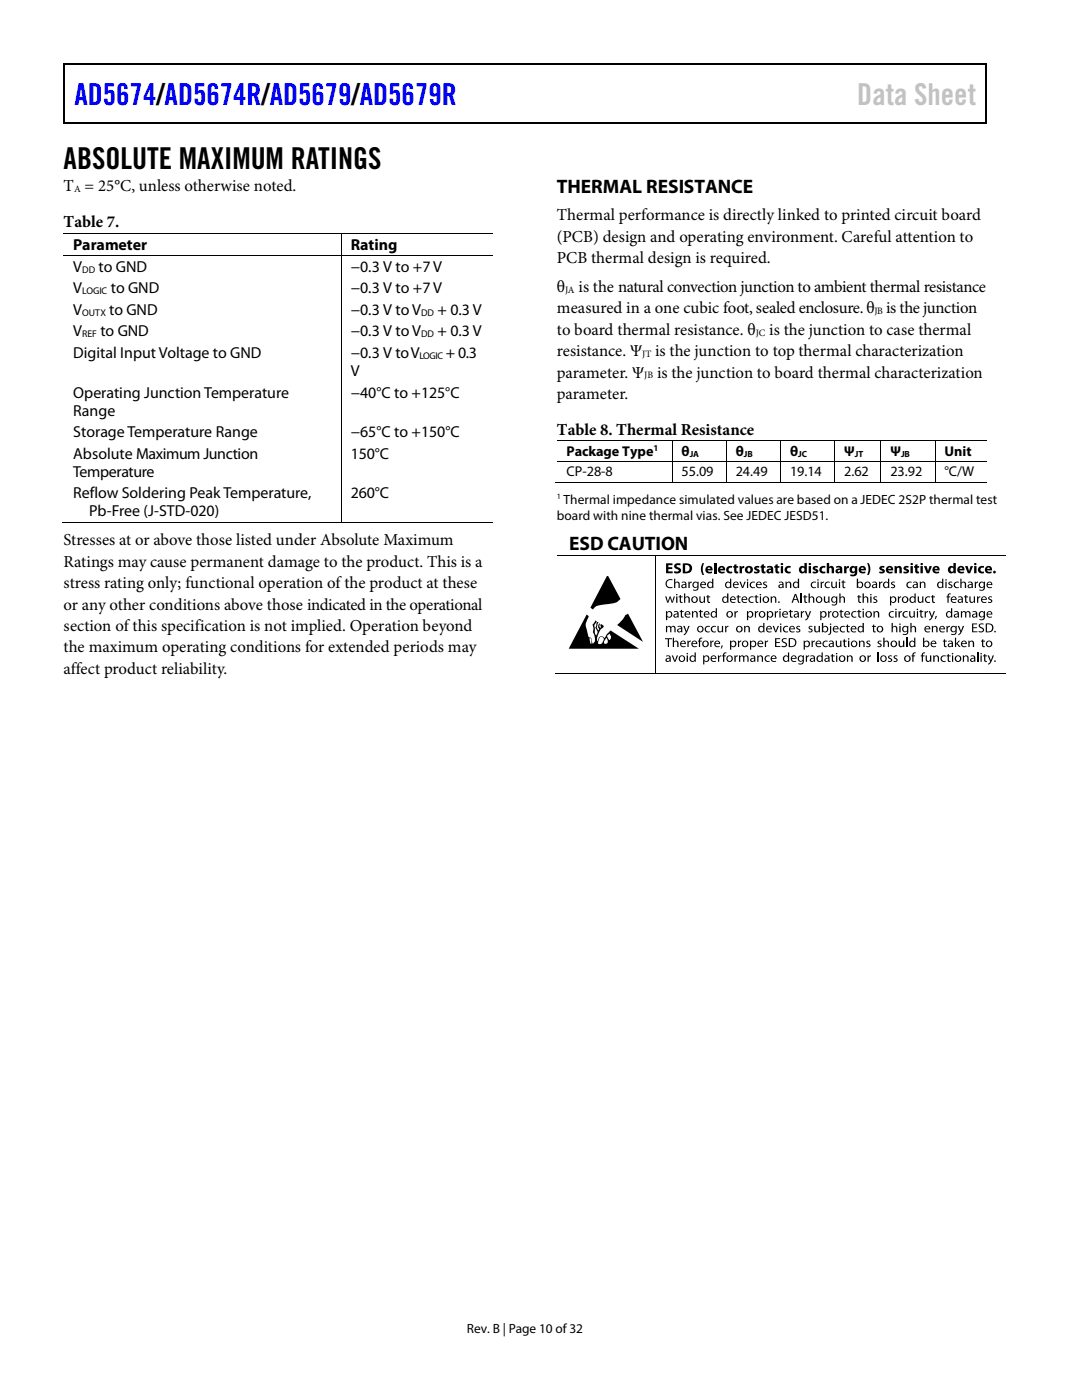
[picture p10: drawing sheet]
<svg xmlns="http://www.w3.org/2000/svg" width="216mm" height="279mm" viewBox="0 0 216 279" stroke-linecap="round" stroke-linejoin="round" font-family="sans-serif">
<defs><g id="words">
<text font-size="6" fill="#00f" x="14.9" y="21">AD5674/AD5674R/AD5679/AD5679R</text>
<text font-size="6" fill="#c1c1c1" x="171.1" y="21">Data Sheet</text>
<text font-size="6" x="12.7" y="33.7">ABSOLUTE MAXIMUM RATINGS</text>
<g font-size="3.9">
<text x="111.1" y="38.5">THERMAL RESISTANCE</text>
<text x="113.6" y="109.7">ESD CAUTION</text>
</g>
<g font-size="3.3">
<text x="12.7" y="38.1">T = 25°C, unless otherwise noted.</text>
<text x="12.7" y="45.2">Table 7.</text>
<text x="111.1" y="44">Thermal performance is directly linked to printed circuit board</text>
<text x="111.1" y="48.3">(PCB) design and operating environment. Careful attention to</text>
<text x="111.1" y="52.6">PCB thermal design is required.</text>
<text x="111.1" y="58.2">θ</text>
<text x="115.4" y="58.3">is the natural convection junction to ambient thermal resistance</text>
<text x="111.1" y="62.5">measured in a one cubic foot, sealed enclosure. θ is the junction</text>
<text x="111.1" y="71.1">resistance. Ψ</text>
<text x="111.1" y="66.8">to board thermal resistance. θ</text>
<text x="130.7" y="71.1">is the junction to top thermal characterization</text>
<text x="153.5" y="66.8">is the junction to case thermal</text>
<text x="111.1" y="75.4">parameter. Ψ</text>
<text x="131.1" y="75.4">is the junction to board thermal characterization</text>
<text x="111.1" y="79.6">parameter.</text>
<text x="111.1" y="86.7">Table 8. Thermal Resistance</text>
<text x="12.7" y="108.8">Stresses at or above those listed under Absolute Maximum</text>
<text x="12.7" y="113.1">Ratings may cause permanent damage to the product. This is a</text>
<text x="12.7" y="117.4">stress rating only; functional operation of the product at these</text>
<text x="12.7" y="121.7">or any other conditions above those indicated in the operational</text>
<text x="12.7" y="125.9">section of this specification is not implied. Operation beyond</text>
<text x="12.7" y="130.2">the maximum operating conditions for extended periods may</text>
<text x="12.7" y="134.5">affect product reliability.</text>
</g>
<g font-size="3.2">
<text x="14.6" y="49.8">Parameter</text>
<text x="70" y="49.8">Rating</text>
<text x="14.6" y="54.3">V</text>
<text x="14.6" y="58.5">V</text>
<text x="19.6" y="54.3">to GND</text>
<text x="22.1" y="58.5">to GND</text>
<text x="70" y="54.3">−0.3 V to +7 V</text>
<text x="70" y="58.5">−0.3 V to +7 V</text>
<text x="14.6" y="62.9">V</text>
<text x="21.8" y="62.9">to GND</text>
<text x="70" y="62.9">−0.3 V to V</text>
<text x="87.3" y="62.9">+ 0.3 V</text>
<text x="14.6" y="67.1">V</text>
<text x="14.6" y="71.5">Digital Input Voltage to GND</text>
<text x="20" y="67.1">to GND</text>
<text x="70" y="67.1">−0.3 V to V</text>
<text x="70" y="71.5">−0.3 V to V</text>
<text x="87.3" y="67.1">+ 0.3 V</text>
<text x="88.9" y="71.5">+ 0.3</text>
<text x="70" y="75.1">V</text>
<text x="14.6" y="79.3">Operating Junction Temperature</text>
<text x="14.6" y="82.9">Range</text>
<text x="70" y="79.3">−40°C to +125°C</text>
<text x="14.6" y="87.2">Storage Temperature Range</text>
<text x="70" y="87.2">−65°C to +150°C</text>
<text x="14.6" y="91.5">Absolute Maximum Junction</text>
<text x="14.6" y="95.1">Temperature</text>
<text x="70" y="91.5">150°C</text>
<text x="14.6" y="99.4">Reflow Soldering Peak Temperature,</text>
<text x="70" y="99.4">260°C</text>
<text x="17.8" y="103">Pb-Free (J-STD-020)</text>
</g>
<g font-size="2.8">
<text x="113" y="91">Package Type</text>
<text x="113" y="95.1">CP-28-8</text>
<text x="136" y="95.1">55.09</text>
<text x="136" y="91">θ</text>
<text x="146.8" y="95.1">24.49</text>
<text x="146.8" y="91">θ</text>
<text x="157.6" y="95.1">19.14</text>
<text x="157.6" y="91">θ</text>
<text x="168.4" y="95.1">2.62</text>
<text x="168.4" y="91">Ψ</text>
<text x="177.7" y="95.1">23.92</text>
<text x="177.7" y="91">Ψ</text>
<text x="188.5" y="95.1">°C/W</text>
<text x="188.5" y="91">Unit</text>
</g>
<g font-size="2.7">
<text x="112.5" y="100.5">Thermal impedance simulated values are based on a JEDEC 2S2P thermal test</text>
<text x="111.1" y="103.7">board with nine thermal vias. See JEDEC JESD51.</text>
<text x="93.2" y="266">Rev. B | Page 10 of32</text>
</g>
<g font-size="1.9">
<text x="14.8" y="38.3">A</text>
<text x="16.4" y="54.4">DD</text>
<text x="16.4" y="58.7">LOGIC</text>
<text x="112.8" y="58.4">JA</text>
<text x="16.4" y="63">OUTX</text>
<text x="84" y="63">DD</text>
<text x="174.5" y="62.7">JB</text>
<text x="16.4" y="67.3">REF</text>
<text x="83.7" y="71.6">LOGIC</text>
<text x="84" y="67.3">DD</text>
<text x="128.1" y="71.2">JT</text>
<text x="150.8" y="67">JC</text>
<text x="128.6" y="75.5">JB</text>
</g>
<g font-size="1.8">
<text x="130.4" y="90.1">1</text>
<text x="137.6" y="91.1">JA</text>
<text x="148.4" y="91.1">JB</text>
<text x="159.3" y="91.1">JC</text>
<text x="170.6" y="91.1">JT</text>
<text x="179.8" y="91.1">JB</text>
</g>
<text font-size="1.6" x="111.1" y="99.6">1</text>
</g></defs>
<g fill="#000">
<path d="M12.7 12.7h.3v1h-.3zM12.7 12.7h.3v.3h-.3zM132.7 12.7h.2v.3h-.2zM196.6 12.7h.2v1h-.2zM196.6 12.7h.2v.3h-.2zM12.7 24.4h.3v.2h-.3zM132.4 24.4h.3v.2h-.3zM196.6 24.4h.2v.2h-.2zM68 46.4h.2v.2h-.2zM68 51h.2v.1h-.2zM134 87.9h.2v.2h-.2zM134 92.1h.2v.1h-.2z"/>
<path d="M134 96.1h.2v.2h-.2zM144.8 87.9h.2v.2h-.2zM144.8 92.1h.2v.1h-.2zM144.8 96.1h.2v.2h-.2zM155.7 87.9h.1v.2h-.1zM155.7 92.1h.1v.1h-.1zM155.7 96.1h.1v.2h-.1zM166.5 87.9h.1v.2h-.1zM166.5 92.1h.1v.1h-.1zM166.5 96.1h.1v.2h-.1zM175.7 87.9h.2v.2h-.2zM175.7 92.1h.2v.1h-.2z"/>
<path d="M175.7 96.1h.2v.2h-.2zM186.5 87.9h.2v.2h-.2zM186.5 92.1h.2v.1h-.2zM186.5 96.1h.2v.2h-.2zM68 104.2h.2v.2h-.2zM121.2 115l2.6 4.5-.2 .3a3.3 3.3 0 0 1-2.6 .8l-.6 .1a2.09 2.09 0 0 0-2.1 .9l-.5-.3 2.8-5.4zM130.7 110.8h.2v.2h-.2zM132.9 112.4h1.3v.4h-.8v.4h.7v.4h-.7v.4h.8v.4h-1.3zM132.7 119h.3l.3 1.1 .3-1.1h.2l.3 1.1 .3-1.1h.3l-.5 1.3h-.2l-.3-1-.3 1h-.3zM133.1 115.8l.7-.2 .4 .1-.1 .1a.74 .74 0 0 0-1.1 .7 .74 .74 0 0 0 1.2 .6v.2a.95 .95 0 0 1-1.2-.2 .95 .95 0 0 1 .1-1.3zM134.5 115.5h.2v.8l.5-.2 .4 .2v1.1h-.2v-1a.32 .32 0 0 0-.4-.1 .32 .32 0 0 0-.3 .3v.8h-.2zM134.7 112.6l.6-.2 .5 .1-.1 .4-.6-.1-.1 .2 .1 .1a.67 .67 0 0 1 .8 .7 .67 .67 0 0 1-.8 .6l-.6-.1 .1-.3 .7 .1 .1-.2-.1-.2a.77 .77 0 0 1-.7-.9z"/>
<path d="M135.6 118.8l.3-.1v.3h.3v.2h-.3v.9h.3v.2h-.4l-.2-.2v-.9h-.2v-.2h.2zM136.5 118.4h.2v.8l.5-.2 .4 .2v1.1h-.2v-.7a.33 .33 0 0 0-.3-.4 .33 .33 0 0 0-.4 .3v.8h-.2zM137.4 116.1h.2v.2l.4-.2v.2h-.2l-.2 .3v.8h-.2zM140.2 112.4h.3a2.47 2.47 0 0 0 0 2.4 .69 .69 0 0 1-.6-.8v-.8zM139.5 119h.3v.9l.3 .2 .3-.2v-.9h.3v1.3h-.2v-.2l-.1 .1a.49 .49 0 0 1-.8-.1zM141.1 118.8l.3-.1v.3h.3v.2h-.3v.9h.3v.2h-.4l-.2-.2v-.9h-.2zM142.5 112.3h.4v2.1h-.4zM145.1 113.2l.9-.2h.1l-.1 .3a.43 .43 0 0 0-.6 .4 .43 .43 0 0 0 .7 .3v.4a.8 .8 0 0 1-1-.2 .8 .8 0 0 1 0-1zM146.5 112.7l.4-.1v.4h.4v.3h-.4l.1 .7 .3 .1v.3h-.5l-.2-.2-.1-.9h-.2v-.3h.2zM147.2 118.8l.2-.1v.3h.4v.2h-.4l.1 .9h.2v.2h-.3l-.2-.2v-.9h-.2v-.2h.2zM147.6 113h.4v.2l.3-.2h.2v.4h-.3l-.1 .2v.8h-.5zM147.6 116.1h.2l.4 1 .3-1h.3l-.5 1.3h-.2z"/>
<path d="M150.6 113.2l.5-.3 .4 .1-.1 .3h-.4v.2a.51 .51 0 0 1 .6 .5 .51 .51 0 0 1-.7 .4l-.5-.1 .1-.3 .4 .1 .2-.1-.6-.4zM149.8 116.3l.5-.2h.3v.2a.49 .49 0 0 0-.8 .4 .49 .49 0 0 0 .8 .4v.2a.69 .69 0 0 1-.9-.1 .69 .69 0 0 1 .1-.9zM150.8 118.8l.2-.1v.3h.3v.2h-.3v.9h.3v.2h-.3l-.2-.2v-.9h-.3v-.2h.3zM152.3 116.2l.4-.1h.3v.2h-.5v.2l.2 .1a.38 .38 0 0 1 .4 .3 .38 .38 0 0 1-.2 .4h-.7l.1-.2 .3 .1 .3-.2-.6-.4zM151.9 112.7l.5-.1v.4h.3v.3h-.3l.1 .7 .2 .1v.3h-.5l-.2-.2-.1-.9h-.1v-.3h.1zM153.8 119h.2v.3l.1-.2a.5 .5 0 0 1 .7 .1l.1 1.1h-.2v-.7a.33 .33 0 0 0-.3-.4 .33 .33 0 0 0-.4 .3v.8h-.2zM154.7 112.7l.5-.1v.4h.3v.3h-.3v.7l.3 .1v.3h-.5l-.2-.2-.1-.9h-.2v-.3h.2zM156.7 116.1h.2l.1 .2 .1-.1a.51 .51 0 0 1 .7 .1l.1 1.1h-.3v-.8a.33 .33 0 0 0-.3-.3 .33 .33 0 0 0-.3 .3v.8h-.3zM156.8 113.2l.8-.2h.2l-.1 .3a.44 .44 0 0 0-.7 .4 .44 .44 0 0 0 .7 .3l.1 .4a.8 .8 0 0 1-1-.2 .8 .8 0 0 1 0-1zM159.8 118.4h.2v1.9h-.2zM160.5 118.8l.2-.1v.3h.4v.2h-.4l.1 .9h.3v.2h-.4l-.2-.2v-.9h-.2v-.2h.2zM161.3 118.4h.3v.8l.4-.2 .4 .2 .1 1.1h-.3v-.9l-.3-.2-.3 .2v.9h-.3z"/>
<path d="M162.2 113.2l.6-.3 .4 .1-.1 .3h-.4v.2a.51 .51 0 0 1 .6 .5 .51 .51 0 0 1-.7 .4l-.5-.1 .1-.3 .4 .1 .2-.1-.6-.4zM162 116.3l.5-.2h.3v.2a.5 .5 0 0 0-.8 .4 .5 .5 0 0 0 .8 .4v.2a.68 .68 0 0 1-.9-.1 .68 .68 0 0 1 .1-.9zM163.7 116.1h.3v.2l.4-.2v.2h-.2l-.2 .3v.8h-.2zM163.7 113.2l.8-.2h.2l-.1 .3a.44 .44 0 0 0-.6 .4 .44 .44 0 0 0 .6 .3l.1 .4a.8 .8 0 0 1-1-.2 .8 .8 0 0 1 0-1zM165 112.3h.4v.8a.55 .55 0 0 1 .7-.1 .55 .55 0 0 1 .3 .6v.8h-.5v-.9l-.2-.2-.2 .2-.1 .9h-.4zM164.4 119h.2l.1 .9 .2 .2 .4-.2v-.9h.2v1.3h-.2v-.2l-.1 .1a.49 .49 0 0 1-.7-.1zM164.7 116.3l.6-.2h.3l-.1 .2a.49 .49 0 0 0-.7 .4 .49 .49 0 0 0 .7 .4l.1 .2a.68 .68 0 0 1-.9-.1 .68 .68 0 0 1 0-.9zM165.9 116.1h.2v.9l.3 .2 .3-.3v-.8h.3v1.3h-.2v-.3l-.1 .2a.48 .48 0 0 1-.8-.1zM167.5 118.4h.2v.8l.5-.2 .3 .2 .1 1.1h-.2l-.1-.9-.2-.2-.4 .3v.8h-.2zM168.1 115.9l.2-.1v.3h.4v.2h-.4l.1 .8 .3 .1v.2h-.4l-.2-.3v-.8h-.2v-.2h.2zM168.4 113h.4l.1 .2 .2-.2h.3v.4h-.3l-.2 .2v.8h-.5zM171.2 118.8l.3-.1v.3h.4v.2h-.4v.9h.3v.2h-.3l-.2-.2-.1-.9h-.1z"/>
<path d="M172.1 118.4h.3v.8l.4-.2 .4 .2 .1 1.1h-.3v-.9l-.3-.2-.3 .2v.9h-.3zM173 112.4a.69 .69 0 0 1 .6 .8v.8a.69 .69 0 0 1-.6 .8 2.47 2.47 0 0 0 0-2.4zM175.4 116.1h.2v.2l.5-.2v.2h-.3l-.1 .3-.1 .8h-.2zM175.5 113.2l.6-.3 .4 .1-.1 .3-.5 .1 .3 .1a.46 .46 0 0 1 .3 .7l-.3 .2-.8-.1 .1-.3 .4 .1 .2-.1-.6-.4zM177.8 116.2l.5-.1h.3l-.1 .2h-.4v.2l.2 .1a.38 .38 0 0 1 .3 .3 .38 .38 0 0 1-.2 .4h-.6v-.2l.3 .1 .3-.2-.6-.4zM178.5 113h.4v.2l.3-.2a.55 .55 0 0 1 .7 .6v.8h-.4l-.1-1-.2-.1-.2 .2v.9h-.5zM179.1 119h.3v.3l.4-.3v.2l-.2 .1-.2 .3v.7h-.2zM180.3 113.2l.6-.3 .4 .1-.1 .3h-.4v.2h.2a.46 .46 0 0 1 .4 .7l-.4 .2-.8-.1 .1-.3 .4 .1 .2-.1-.6-.4zM181.1 116.3l.5-.2h.3v.2a.49 .49 0 0 0-.8 .4 .49 .49 0 0 0 .8 .4v.2a.68 .68 0 0 1-.9-.1 .68 .68 0 0 1 .1-.9zM182.6 112.7l.5-.1v.4h.3v.3h-.3v.7l.3 .1v.3h-.5l-.2-.2-.1-.9h-.2v-.3h.2zM183.5 116.1h.2l.1 .2v-.1a.5 .5 0 0 1 .8 .1l.1 1.1h-.3v-.8a.33 .33 0 0 0-.3-.3 .33 .33 0 0 0-.3 .3v.8h-.3zM183.1 119h.3v.9l.3 .2 .3-.2v-.9h.2v1.3h-.2v-.2l-.1 .1a.48 .48 0 0 1-.7-.1z"/>
<path d="M184.4 113h.5l.3 1 .3-1h.5l-.6 1.4h-.5zM186 118.8l.2-.1v.3h.4v.2h-.4l.1 .9h.2l.1 .2h-.4l-.2-.2v-.9h-.2v-.2h.2zM189.3 116.2l.4-.1h.3v.2h-.5v.2l.2 .1a.38 .38 0 0 1 .4 .3 .38 .38 0 0 1-.3 .4h-.6v-.2l.4 .1 .2-.2-.5-.4zM190.5 116.3l.5-.2h.3v.2a.49 .49 0 0 0-.8 .4 .49 .49 0 0 0 .8 .4v.2a.69 .69 0 0 1-.9-.1 .69 .69 0 0 1 .1-.9zM191.6 115.5h.3v.8l.4-.2 .4 .2 .1 1.1h-.3v-.8a.33 .33 0 0 0-.3-.3 .33 .33 0 0 0-.3 .3v.8h-.3zM192.6 118.8l.2-.1v.3h.4v.2h-.4l.1 .9h.2v.2h-.3l-.2-.2v-.9h-.2v-.2h.2zM192.6 113h.5l.3 1 .3-1h.5l-.6 1.4h-.5zM194.5 116.1h.2v.2l.5-.2v.2l-.5 .3v.8h-.2zM193.4 119h.3v.9l.3 .2 .3-.2v-.9h.2l.1 1.3h-.2l-.1-.2-.1 .1a.48 .48 0 0 1-.7-.1zM194.9 119h.3v.3l.4-.3v.2l-.2 .1-.2 .3v.7h-.2zM195.4 113.2l.8-.2h.2l-.1 .3a.43 .43 0 0 0-.7 .4 .43 .43 0 0 0 .7 .3l.1 .4a.8 .8 0 0 1-1-.2 .8 .8 0 0 1 0-1zM124.7 122.8l.6-.3 3 5.6-5.2-3.4 1.1-1z"/>
<path d="M130.7 134.2h.2v.2h-.2zM132.9 124.9h.2v.2l.2-.2h.4l.2 .2 .3-.2h.4l.2 .5v.8h-.2l-.1-.9-.2-.2-.3 .2v.9h-.3v-1l-.3-.1-.3 .2v.9h-.2zM132.7 127.4h1.4v.2h-.6v1.5h-.2v-1.5h-.6zM134.2 127.3h.3v.8l.4-.3 .4 .2 .1 1.1h-.3v-.7a.33 .33 0 0 0-.3-.4 .33 .33 0 0 0-.3 .4v.7h-.3zM134 130.8h.3l.4 1 .3-1h.3l-.5 1.3h-.3zM135.8 121.7h.3v.3h.3v.2h-.3v.8l.3 .1v.1l-.4 .1-.1-.3-.1-.8h-.2v-.2h.2zM136.3 124.9h.3l.4 1 .3-1h.3l-.7 1.6-.4 .3-.1-.2 .4-.5zM137.2 127.9h.2v.2l.4-.3v.3h-.2l-.2 .3v.7h-.2zM138.1 122h.2v.2l.1-.1a.51 .51 0 0 1 .7 .1l.1 1h-.2v-.7a.33 .33 0 0 0-.3-.4 .33 .33 0 0 0-.4 .4v.7h-.2zM139.6 127.4l.6-.1-.1 .2-.4 .1v.3h.3v.1h-.3v1.1h-.2v-1.1h-.2v-.1h.2zM139.7 121.7h.2v.3h.3v.2h-.3v.8l.3 .1v.1l-.3 .1-.2-.3v-.8h-.3v-.2h.3zM140.8 125.1l.5-.2 .4 .1-.1 .1a.5 .5 0 0 0-.8 .5 .5 .5 0 0 0 .8 .4v.1a.68 .68 0 0 1-.9-.1 .68 .68 0 0 1 .1-.9z"/>
<path d="M141.7 127.9h.2v.2l.5-.3v.3l-.4 .3v.7h-.3zM142 125.1l.6-.2 .3 .1-.1 .1a.49 .49 0 0 0-.7 .5 .49 .49 0 0 0 .7 .4l.1 .1a.69 .69 0 0 1-.9-.1 .69 .69 0 0 1 0-.9zM143.2 130.8h.3v.3l.4-.3v.2h-.2l-.2 .3v.8h-.2zM144 128.8h.2l-.2 .6-.2 .1zM144.4 130.3l.6-.1-.1 .2h-.3l-.1 .2v.2h.3v.2h-.3v1.1h-.2v-1.1h-.2v-.2h.2zM143.2 124.9h.2v.9l.3 .2 .3-.2v-.9h.3v1.3h-.2v-.2l-.1 .1a.49 .49 0 0 1-.8-.1zM144.7 124.9h.2v.3l.4-.3v.2l-.4 .3v.8h-.2zM146.5 130.8h.3v.3l.4-.3v.2h-.2l-.2 .3v.8h-.3zM146.5 122h.3v.2l.4-.2v.2h-.2l-.2 .3v.7h-.2zM147.2 127.9h.2l.1 .2 .4-.3v.3l-.4 .3v.7h-.2zM147.4 130.8h.3v.2l.2-.2h.4l.2 .2 .3-.2h.3l.3 .5v.8h-.3v-1l-.2-.1-.4 .2v.9h-.2v-1l-.3-.1-.3 .3v.8h-.2zM148.5 124.9h.2v.2l.1-.1a.52 .52 0 0 1 .7 .1l.1 1.1h-.2v-.7a.33 .33 0 0 0-.3-.4 .33 .33 0 0 0-.4 .3v.8h-.2z"/>
<path d="M149.5 119.2l.5-.2 .4 .1-.1 .2a.49 .49 0 0 0-.7 .4 .49 .49 0 0 0 .7 .4l.1 .2a.68 .68 0 0 1-.9-.2 .68 .68 0 0 1 0-.9zM150.6 122h.2v.2l.5-.2v.2h-.2l-.2 .3v.7h-.3zM151.1 130.8h.2v.2l.1-.1a.51 .51 0 0 1 .8 .1v1.1h-.2v-.7a.34 .34 0 0 0-.3-.4 .34 .34 0 0 0-.4 .3v.8h-.2zM152.6 127.9h.2v.2l.5-.3v.3h-.3l-.1 .3v.7h-.3zM152.7 131l.6-.2h.3l-.1 .2a.49 .49 0 0 0-.7 .4 .49 .49 0 0 0 .7 .5l.1 .1a.68 .68 0 0 1-.9-.1 .68 .68 0 0 1 0-.9zM154.2 124.9h.2l.4 1.1 .4-1.1h.2l-.5 1.3h-.2zM154.6 122h.2v.2l.5-.2v.2h-.3l-.2 .3v.7h-.2zM155.3 120.1h.2v.2h-.2zM154.7 127.4h1v.2h-.8v.5h.7v.2h-.7v.6h.8v.2h-1zM156 127.6l.6-.3 .4 .1-.1 .2-.3-.1-.4 .2 .2 .3a.57 .57 0 0 1 .6 .4 .57 .57 0 0 1-.3 .7h-.6l-.2-.1 .1-.1a.4 .4 0 0 0 .6 .1 .4 .4 0 0 0 .1-.6l-.2-.1a.51 .51 0 0 1-.5-.7zM156.4 125.1l.5-.2 .4 .1-.1 .1a.49 .49 0 0 0-.7 .5 .49 .49 0 0 0 .7 .4l.1 .1a.68 .68 0 0 1-.9-.1 .68 .68 0 0 1 0-.9zM157.6 121.7h.3v.3h.3v.2h-.3v.8l.3 .1v.1l-.4 .1-.2-.3v-.8h-.2v-.2h.2z"/>
<path d="M158.9 125.1l.4-.2 .3 .1v.1h-.4v.3h.1a.39 .39 0 0 1 .4 .6l-.5 .2-.4-.1 .1-.1h.3l.3-.1-.6-.5zM159.8 122h.2v.2l.5-.2v.2h-.3l-.1 .3-.1 .7h-.2zM160.8 130.8h.2v.3l.5-.3v.2h-.3l-.2 .3v.8h-.2zM160.6 122h.3l.3 1 .4-1h.3l-.7 1.5-.5 .3v-.2a.43 .43 0 0 0 .4-.5zM161.4 125.1l.4-.2 .3 .1v.1h-.5v.3h.2a.38 .38 0 0 1 .3 .4 .38 .38 0 0 1-.2 .4l-.6-.1 .1-.1h.3l.2-.1-.5-.5zM161.9 127.9h.2l.1 .2 .4-.3v.3h-.2l-.2 .3v.7h-.3zM162.5 124.9h.2v.9l.3 .2 .3-.2v-.9h.3v1.3h-.2v-.2l-.1 .1a.49 .49 0 0 1-.8-.1zM164.3 128l.5-.2 .4 .1-.1 .2a.5 .5 0 0 0-.8 .4 .5 .5 0 0 0 .8 .4l.1 .2a.69 .69 0 0 1-.9-.1 .69 .69 0 0 1 0-1zM165.2 122h.2l.1 .2 .4-.2v.2h-.2l-.2 .3v.7h-.2zM166 130.6l.2-.1v.3h.4v.2h-.4v.8l.3 .1v.2h-.3l-.2-.2v-.9h-.3v-.2h.3zM166.8 127.9h.2v.9l.3 .2 .4-.3v-.8h.2v1.2h-.2v-.2l-.1 .1a.48 .48 0 0 1-.8 0zM167.7 121.7h.2v.3h.4v.2h-.4l.1 .8 .3 .1v.1l-.4 .1-.2-.3v-.8h-.2v-.2h.2z"/>
<path d="M168.3 127.6h.3v.3h.4v.1h-.4v.9l.3 .1v.1h-.3l-.2-.2-.1-.9h-.1zM167.7 125.1l.6-.2 .3 .1-.1 .1a.5 .5 0 0 0-.7 .5 .5 .5 0 0 0 .8 .4v.1a.69 .69 0 0 1-.9-.1 .69 .69 0 0 1 0-.9zM169 130.8h.2v.2l.1-.1a.52 .52 0 0 1 .8 .1v1.1h-.2v-.7a.33 .33 0 0 0-.3-.4 .33 .33 0 0 0-.4 .3v.8h-.2zM169 124.7l.2-.1v.3h.4v.2h-.4l.1 .9h.2v.2h-.3l-.2-.2v-.9h-.2v-.2h.2zM170 122.1l.6-.1h.3l-.1 .2a.49 .49 0 0 0-.7 .4 .49 .49 0 0 0 .7 .4l.1 .2a.68 .68 0 0 1-.9-.1 .68 .68 0 0 1 0-1zM171.4 127.9h.2v.2l.1-.1a.5 .5 0 0 1 .7 0l.1 1.1h-.2v-.9a.32 .32 0 0 0-.4-.2 .32 .32 0 0 0-.3 .4v.7h-.2zM171.3 121.7h.2v.3h.4v.2h-.4v.8l.3 .1v.1l-.3 .1-.2-.3v-.8h-.2v-.2h.2zM172.9 128l.4-.2 .3 .1v.2h-.4v.2l.2 .1a.38 .38 0 0 1 .3 .3 .38 .38 0 0 1-.2 .4h-.7l.1-.2 .3 .1 .3-.2-.6-.5zM173.1 130.8h.2v.3l.5-.3v.2h-.3l-.1 .3-.1 .8h-.2zM174.3 119.2l.4-.2 .3 .1v.2l-.5-.1v.3l.2 .1a.38 .38 0 0 1 .4 .3 .38 .38 0 0 1-.2 .4l-.7-.1 .1-.1 .3 .1 .3-.2-.6-.5zM174.3 122h.2v.2l.1-.1a.52 .52 0 0 1 .8 .1v1h-.2v-.7a.33 .33 0 0 0-.3-.4 .33 .33 0 0 0-.4 .4v.7h-.2zM174.2 124.7l.2-.1v.3h.4v.2h-.4l.1 .9h.3v.2h-.4l-.2-.2v-.9h-.2v-.2h.2z"/>
<path d="M175.1 130.2h.2v1.9h-.2zM175.2 128l.4-.2 .3 .1-.1 .2h-.4v.2l.2 .1a.38 .38 0 0 1 .3 .3 .38 .38 0 0 1-.2 .4h-.6v-.2l.3 .1 .3-.2-.6-.5zM176.2 127.3h.3v.8l.4-.3 .4 .2 .1 1.1h-.2l-.1-.9a.32 .32 0 0 0-.3-.2 .32 .32 0 0 0-.3 .4v.7h-.3zM177.3 131l.3-.2 .4 .1-.1 .1h-.4v.2l.2 .1a.39 .39 0 0 1 .3 .6l-.5 .2-.3-.1v-.2l.3 .1 .3-.2-.6-.4zM177.9 124.3h.2v.8l.5-.2 .4 .2 .1 1.1h-.3v-.7a.34 .34 0 0 0-.3-.4 .34 .34 0 0 0-.4 .3v.8h-.2zM178.4 131l.4-.2 .3 .1-.1 .1h-.4v.2l.2 .1a.38 .38 0 0 1 .3 .4 .38 .38 0 0 1-.2 .4l-.6-.1v-.2l.3 .1 .3-.2-.6-.4zM177.5 122.1l.5-.1h.4l-.1 .2a.49 .49 0 0 0-.7 .4 .49 .49 0 0 0 .7 .4l.1 .2a.68 .68 0 0 1-.9-.1 .68 .68 0 0 1 0-1zM179.3 122h.2v.2l.5-.2v.2h-.3l-.1 .3v.7h-.3zM179.3 127.9h.3v.9l.2 .2 .4-.3v-.8h.2v1.2h-.2v-.2l-.1 .1a.49 .49 0 0 1-.7 0zM180.8 127.3h.3v1.8h-.3zM180.3 122.1l.5-.1h.3v.2a.49 .49 0 0 0-.8 .4 .49 .49 0 0 0 .8 .4v.2a.68 .68 0 0 1-.9-.1 .68 .68 0 0 1 .1-1zM181.7 124.3h.2v.8l.4-.2 .4 .2 .1 1.1h-.3v-.7a.33 .33 0 0 0-.3-.4 .33 .33 0 0 0-.3 .3v.8h-.2z"/>
<path d="M182.2 130.3l.5-.1v.2h-.3l-.1 .2v.2h.3v.2h-.3v1.1h-.3v-1.1h-.1v-.2h.1zM181.4 122h.3v.9l.3 .2 .3-.2v-.9h.2l.1 1.2h-.3v-.2l-.1 .1a.48 .48 0 0 1-.7 0zM183.6 121.7h.3v.3h.3v.2h-.3v.8l.3 .1v.1l-.3 .1-.2-.3-.1-.8h-.2zM184.1 130.3l.5-.1v.2h-.3l-.1 .2v.2h.3v.2h-.3v1.1h-.3v-1.1h-.2v-.2h.2zM184.5 122h.2v.2l.5-.2v.2h-.3l-.1 .3-.1 .7h-.2zM185.3 122h.3l.4 1 .3-1h.3l-.7 1.5-.5 .3v-.2a.43 .43 0 0 0 .4-.5zM184.7 119.2l.6-.2 .3 .1-.1 .2a.5 .5 0 0 0-.7 .4 .5 .5 0 0 0 .8 .4v.2a.69 .69 0 0 1-.9-.2 .69 .69 0 0 1 0-.9zM184.7 130.8h.2l.1 .9 .2 .2 .4-.2v-.9h.2v1.3h-.2v-.2l-.1 .1a.48 .48 0 0 1-.7-.1zM185.9 124.9h.2l.1 .2 .1-.1a.51 .51 0 0 1 .7 .1l.1 1.1h-.3v-.7a.33 .33 0 0 0-.3-.4 .33 .33 0 0 0-.3 .3v.8h-.3zM186.2 130.8h.2l.1 .2v-.1a.5 .5 0 0 1 .8 .1l.1 1.1h-.3v-.9a.32 .32 0 0 0-.4-.2 .32 .32 0 0 0-.2 .3v.8h-.3zM186.7 122.9h.3l-.3 .6-.2 .1zM188.3 127.6h.3v.3h.3v.1h-.3v.9l.3 .1v.1h-.4l-.1-.2-.1-.9h-.2z"/>
<path d="M187.9 131l.5-.2h.3v.2a.5 .5 0 0 0-.8 .5 .5 .5 0 0 0 .8 .4v.1a.69 .69 0 0 1-.9-.1 .69 .69 0 0 1 .1-.9zM188.9 124.9h.2v.3l.4-.3v.2l-.2 .1-.2 .2v.8h-.2zM189.2 118.5h.5v.1l-.4 .2v.2h.3v.2h-.3v1.1h-.2v-1.1h-.2v-.2h.2zM189.1 130.6l.2-.1v.3h.4v.2h-.4l.1 .8 .3 .1v.2h-.4l-.2-.2v-.9h-.2v-.2h.2zM190.5 127.3h.3v1.2l.5-.6h.3l-.5 .5 .6 .7h-.3l-.5-.6-.1 .2v.4h-.3zM191.1 124.9h.3l.4 1 .3-1h.3l-.5 1.3-.6 .6-.1-.2 .4-.5zM191.7 122h.3v.2l.2-.2h.3l.3 .2 .2-.2h.4l.3 .5v.7h-.3v-.9l-.3-.2-.3 .3v.8h-.2l-.1-.9-.2-.2-.3 .3v.8h-.3zM192.1 130.8h.2v.2l.1-.1a.5 .5 0 0 1 .8 .1l.1 1.1h-.3v-.7a.34 .34 0 0 0-.3-.4 .34 .34 0 0 0-.3 .3v.8h-.3zM193.2 127.9h.2v.2l.1-.1a.52 .52 0 0 1 .8 0l.1 1.1h-.3v-.7a.33 .33 0 0 0-.3-.4 .33 .33 0 0 0-.3 .4v.7h-.3zM194 124.4h1v.2h-.8v.6h.7v.2h-.7v.6h.8v.2h-1zM195 130.2h.2v1.9h-.2zM195.4 124.6l.5-.2 .4 .1-.1 .2-.3-.1-.3 .1 .1 .4a.57 .57 0 0 1 .6 .4 .57 .57 0 0 1-.3 .7h-.6l-.2-.1 .1-.2a.4 .4 0 0 0 .6 .1 .4 .4 0 0 0 .1-.5l-.2-.1a.51 .51 0 0 1-.4-.8z"/>
<path d="M196 127.6h.2v.3h.3v.1h-.3v.9l.3 .1v.1h-.3l-.2-.2v-.9h-.3v-.1h.3zM196.4 130.6l.2-.1v.3h.4v.2h-.4v.8l.3 .1v.2h-.3l-.2-.2v-.9h-.3v-.2h.3zM197.2 119.2l.4-.2 .4 .1-.1 .2-.4-.1v.3l.2 .1a.38 .38 0 0 1 .3 .3 .38 .38 0 0 1-.2 .4l-.7-.1 .1-.1 .3 .1 .3-.2-.6-.5zM197.1 130.8h.2l.4 1 .4-1h.2l-.5 1.3-.6 .6-.1-.2 .5-.5zM198.4 131.8h.3v.3h-.3zM198.4 125.9h.3v.3h-.3z"/>
<path d="M134.9 118.7a.15 .15 0 0 1 .3 0 .15 .15 0 0 1-.3 0zM134.9 119h.3v1.3h-.3z"/>
<path d="M136.2 112.5a1.56 1.56 0 0 1 1.9 .6 1.23 1.23 0 0 1-1.7 1.3h-.2zM136.7 112.8v1.3a.69 .69 0 0 0 .9-.7 .69 .69 0 0 0-.9-.6z"/>
<path d="M136 116.2l.5-.1 .4 .2 .1 1.1h-.2v-.2a.42 .42 0 0 1-.7 .1 .42 .42 0 0 1 0-.6l.6-.1v-.2l-.3-.2-.3 .1zM136.3 116.8l-.1 .4h.4l.1-.2v-.3z"/>
<path d="M138.3 116.2l.5-.1 .4 .2v-.2h.2v.3a1.51 1.51 0 0 1-.2 1.4l-.5 .1-.4-.1v-.2l.2 .1a.47 .47 0 0 0 .5-.1 .47 .47 0 0 0 .2-.5 .61 .61 0 0 1-.9 0 .61 .61 0 0 1 0-.9zM138.6 116.3a.47 .47 0 0 0-.2 .6 .47 .47 0 0 0 .5 .3 .46 .46 0 0 0 .3-.6 .46 .46 0 0 0-.6-.3z"/>
<path d="M139.9 116.3a.57 .57 0 0 1 .7-.2 .57 .57 0 0 1 .3 .7h-1a.51 .51 0 0 0 .9 .3v.2a.71 .71 0 0 1-.9-.1 .71 .71 0 0 1 0-.9zM140.1 116.3l-.2 .3h.8l-.2-.3z"/>
<path d="M140.9 113.2a.71 .71 0 0 1 .9-.2 .71 .71 0 0 1 .4 .8h-1l.2 .3 .6-.1 .1 .3a.84 .84 0 0 1-1.1 0 .84 .84 0 0 1-.1-1.1zM141.3 113.3l-.1 .2h.6l-.2-.2z"/>
<path d="M141.3 116.2l.4-.1 .4 .1v-.7h.2l.1 1.9h-.3v-.3a.63 .63 0 0 1-.9 .1 .63 .63 0 0 1 .1-1zM141.5 116.3a.48 .48 0 0 0-.2 .6 .48 .48 0 0 0 .6 .3l.1-.1a.47 .47 0 0 0 .1-.6 .47 .47 0 0 0-.6-.2z"/>
<path d="M143.4 113.2a.71 .71 0 0 1 .9-.2 .71 .71 0 0 1 .4 .8h-1l.2 .3 .6-.1 .1 .3a.84 .84 0 0 1-1.1 0 .84 .84 0 0 1-.1-1.1zM143.8 113.3l-.1 .2h.5l-.1-.2z"/>
<path d="M144.3 119.2l.4-.2 .4 .2v-.8h.2v1.9h-.2v-.2a.63 .63 0 0 1-.9 0 .63 .63 0 0 1 .1-.9zM144.5 119.3a.48 .48 0 0 0-.2 .5 .48 .48 0 0 0 .6 .3 .47 .47 0 0 0 .2-.6 .47 .47 0 0 0-.6-.2z"/>
<path d="M145.8 119.2a.57 .57 0 0 1 .7-.1 .57 .57 0 0 1 .3 .6h-.9a.51 .51 0 0 0 .8 .4l.1 .2a.71 .71 0 0 1-1-.2 .71 .71 0 0 1 0-.9zM146.1 119.2l-.2 .3h.7l-.1-.3z"/>
<path d="M144.8 116.2l.5-.1 .4 .1v-.7h.2v1.9h-.2v-.3a.63 .63 0 0 1-.9 .1 .63 .63 0 0 1 0-1zM145.1 116.3a.48 .48 0 0 0-.2 .6 .48 .48 0 0 0 .6 .3 .47 .47 0 0 0 .2-.6 .47 .47 0 0 0-.6-.3z"/>
<path d="M146.4 116.3a.57 .57 0 0 1 .7-.2 .57 .57 0 0 1 .3 .7h-.9a.51 .51 0 0 0 .3 .4 .51 .51 0 0 0 .5-.1v.2a.71 .71 0 0 1-.9-.1 .71 .71 0 0 1 0-.9zM146.6 116.3l-.1 .3h.7l-.1-.3z"/>
<path d="M148.1 119.2a.57 .57 0 0 1 .7-.1 .57 .57 0 0 1 .3 .6h-.9a.53 .53 0 0 0 .8 .4v.2a.71 .71 0 0 1-.9-.2 .71 .71 0 0 1 0-.9zM148.3 119.2l-.1 .3h.7l-.2-.3z"/>
<path d="M149 115.6h.3v.2h-.3zM149 116.1h.3v1.3h-.3z"/>
<path d="M148.6 113.7a.8 .8 0 0 1 1.6 0 .8 .8 0 0 1-1.6 0zM149.3 113.3l-.1 .2a.44 .44 0 0 0 .2 .6 .41 .41 0 0 0 .3-.5 .41 .41 0 0 0-.4-.3z"/>
<path d="M151 116.3a.57 .57 0 0 1 .7-.2 .57 .57 0 0 1 .3 .7h-.9a.51 .51 0 0 0 .8 .3v.2a.71 .71 0 0 1-.9-.1 .71 .71 0 0 1 0-.9zM151.2 116.3l-.1 .3h.7l-.2-.3z"/>
<path d="M151.6 118.7a.15 .15 0 0 1 .3 0 .15 .15 0 0 1-.3 0zM151.6 119h.3v1.3h-.3z"/>
<path d="M153 113.1l.4-.1a.65 .65 0 0 1 .9 .6v.8h-.4v-.1a.49 .49 0 0 1-.8 0 .49 .49 0 0 1 .1-.7l.6-.2-.3-.2-.4 .2zM153.5 113.8l-.1 .2 .2 .1 .2-.1v-.3z"/>
<path d="M155.8 112.4h.4v.3h-.4zM155.8 113h.5v1.4h-.5z"/>
<path d="M155.4 116.2l.4-.1 .5 .2 .1 1.1h-.2l-.1-.2a.42 .42 0 0 1-.6 .1 .42 .42 0 0 1 0-.6l.6-.1v-.2l-.3-.2-.3 .1zM155.6 116.8v.4l.4-.1 .1-.1v-.3z"/>
<path d="M158.6 118.5h.3l.6 1.8h-.2l-.3-.6h-.6l-.2 .6h-.3zM158.7 118.7l-.3 .9h.6z"/>
<path d="M158.4 116.2l.4-.1 .4 .1v-.7h.3v1.9h-.3v-.3a.63 .63 0 0 1-.9 .1 .63 .63 0 0 1 .1-1zM158.6 116.3a.48 .48 0 0 0-.2 .6 .48 .48 0 0 0 .6 .3 .47 .47 0 0 0 .2-.6 .47 .47 0 0 0-.6-.3z"/>
<path d="M159.6 113.1l.5-.2 .4 .2v-.8h.5v2.1h-.4v-.2a.71 .71 0 0 1-1.1 0 .71 .71 0 0 1 .1-1.1zM160 113.3a.39 .39 0 0 0-.1 .6 .39 .39 0 0 0 .5 .1 .4 .4 0 0 0 .1-.5 .4 .4 0 0 0-.5-.2z"/>
<path d="M161.4 112.4h.4v.3h-.4zM161.4 113h.4v1.4h-.4z"/>
<path d="M163.1 115.7a.15 .15 0 0 1 .3 0 .15 .15 0 0 1-.3 0zM163.1 116.1h.2v1.3h-.2z"/>
<path d="M167.4 115.6h.2v.2h-.2zM167.4 116.1h.2v1.3h-.2z"/>
<path d="M166.8 113.1l.3-.1a.66 .66 0 0 1 1 .6v.8h-.4l-.1-.1a.49 .49 0 0 1-.7 0 .49 .49 0 0 1 0-.7l.7-.2-.3-.2-.4 .2zM167.2 113.8v.3h.2l.2-.1v-.3z"/>
<path d="M171 115.5h.2v.8a.61 .61 0 0 1 .9 0 .61 .61 0 0 1-.1 .9 .61 .61 0 0 1-.8-.1v.3h-.2zM171.3 116.4a.47 .47 0 0 0-.1 .6 .47 .47 0 0 0 .6 .1 .48 .48 0 0 0 .2-.5 .48 .48 0 0 0-.6-.3z"/>
<path d="M169.7 113.1a.6 .6 0 0 1 .9 0v-.1h.5v.4a1.59 1.59 0 0 1-.3 1.5l-.6 .1-.6-.1 .1-.3 .3 .1a.41 .41 0 0 0 .6-.5 .69 .69 0 0 1-1-.1 .69 .69 0 0 1 .1-1zM170.1 113.3l-.1 .2a.41 .41 0 0 0 .3 .6 .38 .38 0 0 0 .3-.5 .38 .38 0 0 0-.5-.3z"/>
<path d="M171.5 113.2a.71 .71 0 0 1 .9-.2 .71 .71 0 0 1 .4 .8h-1l.2 .3 .6-.1 .1 .3a.84 .84 0 0 1-1.1 0 .84 .84 0 0 1-.1-1.1zM171.9 113.3l-.1 .2h.5v-.2z"/>
<path d="M172.4 116.7a.7 .7 0 0 1 1.4 0 .7 .7 0 0 1-1.4 0zM172.7 116.8a.45 .45 0 0 0 .9 0 .45 .45 0 0 0-.9 0z"/>
<path d="M173.6 118.7a.15 .15 0 0 1 .3 0 .15 .15 0 0 1-.3 0zM173.6 119h.3v1.3h-.3z"/>
<path d="M174.1 116.2l.4-.1 .5 .2v1.1h-.2v-.2a.42 .42 0 0 1-.7 .1 .42 .42 0 0 1 .1-.6l.6-.1v-.2l-.3-.2-.4 .1zM174.3 116.8v.4h.3l.2-.2v-.3z"/>
<path d="M177 113.2a.71 .71 0 0 1 .8-.2 .71 .71 0 0 1 .4 .8h-1l.2 .3 .7-.1v.3a.84 .84 0 0 1-1 0 .84 .84 0 0 1-.1-1.1zM177.4 113.3l-.2 .2h.6l-.1-.2z"/>
<path d="M176.4 116.2l.4-.1 .4 .1v-.7h.2l.1 1.9h-.3v-.3a.63 .63 0 0 1-.9 .1 .63 .63 0 0 1 .1-1zM176.6 116.3a.48 .48 0 0 0-.2 .6 .48 .48 0 0 0 .6 .3 .47 .47 0 0 0 .2-.6 .47 .47 0 0 0-.6-.3z"/>
<path d="M177.6 119h.2v.3a.62 .62 0 0 1 .9-.1 .62 .62 0 0 1 0 .9 .62 .62 0 0 1-.9 0v.7h-.2zM177.9 119.3a.42 .42 0 0 0 0 .6 .42 .42 0 0 0 .5 .1 .42 .42 0 0 0 .2-.6l-.4-.2z"/>
<path d="M181.7 112.4h.4v.3h-.4zM181.7 113h.5v1.4h-.5z"/>
<path d="M181.6 119.2l.5-.2 .4 .2v-.8h.2v1.9h-.2v-.2a.63 .63 0 0 1-.9 0 .63 .63 0 0 1 0-.9zM181.9 119.3a.48 .48 0 0 0-.2 .5 .48 .48 0 0 0 .6 .3l.1-.1a.47 .47 0 0 0 0-.6 .47 .47 0 0 0-.5-.1z"/>
<path d="M182.2 116.2l.4-.1 .5 .2 .1 1.1h-.3v-.2a.42 .42 0 0 1-.6 .1 .42 .42 0 0 1 0-.6l.6-.1v-.2l-.3-.2-.4 .1zM182.4 116.8v.4l.4-.1 .1-.1v-.3z"/>
<path d="M183.7 112.4h.4v.3h-.4zM183.7 113h.4v1.4h-.4z"/>
<path d="M186.2 113.2a.71 .71 0 0 1 .9-.2 .71 .71 0 0 1 .4 .8h-1l.2 .3 .6-.1 .1 .3a.84 .84 0 0 1-1.1 0 .84 .84 0 0 1-.1-1.1zM186.6 113.3l-.1 .2h.6l-.1-.2z"/>
<path d="M187.2 116.2l.4-.1 .4 .1v-.7h.2l.1 1.9h-.3v-.3a.63 .63 0 0 1-.9 .1 .63 .63 0 0 1 .1-1zM187.4 116.3a.48 .48 0 0 0-.2 .6 .48 .48 0 0 0 .6 .3 .47 .47 0 0 0 .2-.6 .47 .47 0 0 0-.6-.3z"/>
<path d="M188.7 115.6h.2v.2h-.2zM188.6 116.1h.3v1.3h-.3z"/>
<path d="M189.9 119.2a.57 .57 0 0 1 .7-.2 .57 .57 0 0 1 .3 .7h-1a.51 .51 0 0 0 .9 .4v.2a.71 .71 0 0 1-.9-.2 .71 .71 0 0 1 0-.9zM190.1 119.2l-.2 .3h.8l-.2-.3z"/>
<path d="M189.3 113.1l.5-.2 .4 .2v-.8h.5v2.1h-.4v-.2a.71 .71 0 0 1-1.1 0 .71 .71 0 0 1 .1-1.1zM189.8 113.3l-.1 .2a.41 .41 0 0 0 .3 .6 .39 .39 0 0 0 .2-.5 .39 .39 0 0 0-.4-.3z"/>
<path d="M191.2 113.2a.71 .71 0 0 1 .9-.2 .71 .71 0 0 1 .3 .8h-.9l.2 .3 .6-.1 .1 .3a.84 .84 0 0 1-1.1 0 .84 .84 0 0 1-.1-1.1zM191.6 113.3l-.1 .2h.5l-.1-.2z"/>
<path d="M191.2 119.1l.4-.1 .5 .3v1h-.2v-.1a.42 .42 0 0 1-.6 .1 .42 .42 0 0 1 0-.7l.6-.1v-.1l-.3-.2-.4 .1zM191.4 119.8v.3l.5-.2v-.2z"/>
<path d="M193.2 116.2l.4-.1 .5 .2v1.1h-.2v-.2a.42 .42 0 0 1-.7 .1 .42 .42 0 0 1 .1-.6l.6-.1-.1-.2-.2-.2-.4 .1zM193.4 116.8v.4l.3-.1 .2-.1v-.3z"/>
<path d="M194.4 112.4h.4v.3h-.4zM194.4 113h.5v1.4h-.5z"/>
<path d="M195.9 119.2a.57 .57 0 0 1 .7-.1 .57 .57 0 0 1 .3 .6h-.9a.51 .51 0 0 0 .8 .4v.2a.71 .71 0 0 1-.9-.2 .71 .71 0 0 1 0-.9zM196.1 119.2l-.1 .3h.7l-.1-.3z"/>
<path d="M195.5 116.2l.4-.1 .4 .2v-.2h.2v.3a1.51 1.51 0 0 1-.2 1.4l-.5 .1-.4-.1 .1-.2 .1 .1a.46 .46 0 0 0 .5-.1 .46 .46 0 0 0 .2-.5 .61 .61 0 0 1-.9 0 .61 .61 0 0 1 .1-.9zM195.7 116.3a.47 .47 0 0 0-.2 .6 .47 .47 0 0 0 .6 .3 .46 .46 0 0 0 .2-.6 .46 .46 0 0 0-.6-.3z"/>
<path d="M196.7 113.2a.72 .72 0 0 1 .9-.2 .72 .72 0 0 1 .3 .8h-.9l.2 .3 .6-.1 .1 .3a.84 .84 0 0 1-1.1 0 .84 .84 0 0 1-.1-1.1zM197.1 113.3l-.1 .2h.5l-.1-.2z"/>
<path d="M197 116.3a.57 .57 0 0 1 .7-.2 .57 .57 0 0 1 .3 .7h-.9a.51 .51 0 0 0 .3 .4 .51 .51 0 0 0 .5-.1v.2a.71 .71 0 0 1-.9-.1 .71 .71 0 0 1 0-.9zM197.2 116.3l-.1 .3h.7l-.1-.3z"/>
<path d="M117.1 122.6l-3.6 6.9h14l-5.7-3.7-.7 .7-.5 .9a.69 .69 0 0 0-.8-.4 .69 .69 0 0 0-.5 .7l-.1 .3a3.1 3.1 0 0 1 1.2-2.9l.1-.2-.6-.4v.7l-.2 .2-.1-.4v-.6l-.2 .3-.1 .5 .3 .4-.2 .2-.1-.2a.73 .73 0 0 1-.1-.9l.3-.4-.3-.2-.4 1.1a.98 .98 0 0 1 .1 1.6l-.2-.4v-1a.88 .88 0 0 1 .3-1.1l.1-.3-.3-.2-.3 .5a.48 .48 0 0 0-.1 .8l-.1 1.1 .3 .8a1.12 1.12 0 0 1-.4 1.5l-.3-1.2a.81 .81 0 0 1-.7-1l-.1-.5a2.37 2.37 0 0 1 .3-2.5 .44 .44 0 0 0-.3-.7zM117.6 127.4l.2-.1 .2 .4v.6l-.1 .3zM119.8 127.1a.6 .6 0 0 1 .7 .4 .6 .6 0 0 1-.3 .7 .55 .55 0 0 1-.9 .2zM120.9 127.4a.52 .52 0 0 1 .4 .7 .52 .52 0 0 1-.8 .2zM121.2 126.8l.4-.3a.75 .75 0 0 1 0 1.2l-.5-.7z"/>
<path d="M132.9 122h.2v.2a.61 .61 0 0 1 .9 0 .61 .61 0 0 1 0 .8 .61 .61 0 0 1-.9 .1v.7h-.2zM133.2 122.3a.44 .44 0 0 0 0 .6 .44 .44 0 0 0 .7 0 .46 .46 0 0 0-.1-.6 .46 .46 0 0 0-.4-.1z"/>
<path d="M132.9 130.9l.4-.1 .5 .3 .1 1h-.3v-.2a.42 .42 0 0 1-.6 .1 .42 .42 0 0 1 0-.6l.6-.1v-.2l-.3-.2-.4 .1zM133.1 131.5v.4h.4l.1-.2v-.3z"/>
<path d="M134.5 122.1l.4-.1 .5 .2v1h-.2v-.1a.42 .42 0 0 1-.6 .1 .42 .42 0 0 1 0-.6l.6-.2-.1-.1-.2-.2-.4 .1zM134.7 122.7v.3h.3l.2-.1v-.3z"/>
<path d="M135.9 128a.57 .57 0 0 1 .7-.1 .57 .57 0 0 1 .3 .6h-1a.53 .53 0 0 0 .9 .4v.2a.71 .71 0 0 1-.9-.1 .71 .71 0 0 1 0-1zM136.1 128.1l-.2 .3h.7l-.1-.3z"/>
<path d="M135.4 131.5a.66 .66 0 0 1 1.3 0 .66 .66 0 0 1-1.3 0zM135.6 131.5a.45 .45 0 0 0 .9 0 .45 .45 0 0 0-.9 0z"/>
<path d="M135.2 125l.4-.1 .5 .3 .1 1h-.3v-.2a.42 .42 0 0 1-.6 .2 .42 .42 0 0 1 0-.7l.6-.1v-.2l-.3-.1-.4 .1zM135.4 125.6v.4h.4l.1-.2v-.3z"/>
<path d="M136.8 122.2a.58 .58 0 0 1 .7-.2 .58 .58 0 0 1 .3 .6h-1a.53 .53 0 0 0 .9 .4v.2a.71 .71 0 0 1-.9-.1 .71 .71 0 0 1 0-.9zM137 122.2l-.2 .3h.7l-.1-.3z"/>
<path d="M137 130.5a.15 .15 0 0 1 .3 0 .15 .15 0 0 1-.3 0zM137 130.8h.3v1.3h-.3z"/>
<path d="M138.1 128a.58 .58 0 0 1 .7-.1 .58 .58 0 0 1 .3 .6h-.9a.51 .51 0 0 0 .8 .4l.1 .2a.71 .71 0 0 1-1-.1 .71 .71 0 0 1 0-1zM138.4 128.1l-.2 .3h.7l-.1-.3z"/>
<path d="M137.9 119.7a.7 .7 0 0 1 1.4 0 .7 .7 0 0 1-1.4 0zM138.1 119.7a.45 .45 0 0 0 .9 0 .45 .45 0 0 0-.9 0z"/>
<path d="M137.8 131l.4-.2 .4 .2v-.8h.2v1.9h-.2v-.2a.63 .63 0 0 1-.9 0 .63 .63 0 0 1 .1-.9zM138 131a.48 .48 0 0 0-.2 .6 .48 .48 0 0 0 .6 .3 .47 .47 0 0 0 .2-.6 .47 .47 0 0 0-.6-.3z"/>
<path d="M139.1 125.6a.67 .67 0 0 1 1.3 0 .67 .67 0 0 1-1.3 0zM139.3 125.6a.45 .45 0 0 0 .9 0 .45 .45 0 0 0-.9 0z"/>
<path d="M140.3 130.8h.2v.2a.61 .61 0 0 1 .9 0 .61 .61 0 0 1 0 .9 .61 .61 0 0 1-.9 0v.7h-.2zM140.6 131.1a.44 .44 0 0 0 0 .7 .44 .44 0 0 0 .7-.1 .46 .46 0 0 0 0-.5 .46 .46 0 0 0-.5-.2z"/>
<path d="M140.6 122.2a.57 .57 0 0 1 .7-.2 .57 .57 0 0 1 .3 .6h-.9a.51 .51 0 0 0 .2 .5 .51 .51 0 0 0 .6-.1v.2a.71 .71 0 0 1-.9-.1 .71 .71 0 0 1 0-.9zM140.8 122.2l-.1 .3h.6l-.1-.3z"/>
<path d="M140.1 128.5a.67 .67 0 0 1 1.3 0 .67 .67 0 0 1-1.3 0zM140.3 128.5a.45 .45 0 0 0 .9 0 .45 .45 0 0 0-.9 0z"/>
<path d="M141.9 131a.57 .57 0 0 1 .7-.2 .57 .57 0 0 1 .3 .7h-.9a.51 .51 0 0 0 .8 .4l.1 .1a.71 .71 0 0 1-.9-.1 .71 .71 0 0 1-.1-.9zM142.2 131l-.2 .3h.7l-.1-.3z"/>
<path d="M142.7 128a.57 .57 0 0 1 .7-.1 .57 .57 0 0 1 .3 .6h-.9a.51 .51 0 0 0 .8 .4v.2a.71 .71 0 0 1-.9-.1 .71 .71 0 0 1 0-1zM142.9 128.1l-.1 .3h.7l-.2-.3z"/>
<path d="M142 122.1l.4-.1 .4 .1v-.7h.3v1.8h-.3v-.2a.63 .63 0 0 1-.9 .1 .63 .63 0 0 1 .1-1zM142.2 122.2a.48 .48 0 0 0-.2 .6 .48 .48 0 0 0 .6 .3 .47 .47 0 0 0 .2-.6 .47 .47 0 0 0-.6-.3z"/>
<path d="M144.9 131.4a.7 .7 0 0 1 1.4 0 .7 .7 0 0 1-1.4 0zM145.1 131.5a.45 .45 0 0 0 .9 0 .45 .45 0 0 0-.9 0z"/>
<path d="M144.9 122.6a.7 .7 0 0 1 1.4 0 .7 .7 0 0 1-1.4 0zM145.1 122.6a.45 .45 0 0 0 .9 0 .45 .45 0 0 0-.9 0z"/>
<path d="M145.6 127.9h.3v.2a.62 .62 0 0 1 .9 0 .62 .62 0 0 1 0 .8 .62 .62 0 0 1-.9 .1v.7h-.2zM146 128.2a.42 .42 0 0 0 .1 .7 .42 .42 0 0 0 .6-.4l-.2-.4z"/>
<path d="M146.9 125.6a.67 .67 0 0 1 1.3 0 .67 .67 0 0 1-1.3 0zM147.1 125.6a.45 .45 0 0 0 .9 0 .45 .45 0 0 0-.9 0z"/>
<path d="M148 128.5a.7 .7 0 0 1 1.4 0 .7 .7 0 0 1-1.4 0zM148.2 128.5a.45 .45 0 0 0 .9 0 .45 .45 0 0 0-.9 0z"/>
<path d="M149 122h.3v.2a.62 .62 0 0 1 .8 0 .62 .62 0 0 1 .1 .9 .62 .62 0 0 1-.9 0v.7h-.3zM149.4 122.3a.42 .42 0 0 0 .1 .7 .42 .42 0 0 0 .6-.4l-.2-.4z"/>
<path d="M149.6 127.9h.2l.1 .2a.61 .61 0 0 1 .8 0 .61 .61 0 0 1 0 .8 .61 .61 0 0 1-.8 .1v.7h-.2zM150 128.2a.44 .44 0 0 0 0 .6 .44 .44 0 0 0 .6-.1 .46 .46 0 0 0 0-.5 .46 .46 0 0 0-.5-.1z"/>
<path d="M149.8 130.9l.4-.1 .5 .3v1h-.2v-.2a.41 .41 0 0 1-.6 .1 .41 .41 0 0 1 0-.6l.6-.1v-.2l-.3-.2-.4 .1zM150 131.5l-.1 .2a.29 .29 0 0 0 .3 .2 .29 .29 0 0 0 .3-.3v-.2z"/>
<path d="M151.3 128a.57 .57 0 0 1 .7-.1 .57 .57 0 0 1 .3 .6h-.9a.51 .51 0 0 0 .8 .4v.2a.71 .71 0 0 1-.9-.1 .71 .71 0 0 1 0-1zM151.5 128.1l-.1 .3h.7l-.2-.3z"/>
<path d="M151.4 122.6a.67 .67 0 0 1 1.3 0 .67 .67 0 0 1-1.3 0zM151.6 122.6a.45 .45 0 0 0 .9 0 .45 .45 0 0 0-.9 0z"/>
<path d="M151.5 125.1l.4-.2 .4 .2v-.8h.2l.1 1.9h-.3v-.2a.63 .63 0 0 1-.9 0 .63 .63 0 0 1 .1-.9zM151.7 125.1a.48 .48 0 0 0-.2 .6 .48 .48 0 0 0 .6 .3 .47 .47 0 0 0 .2-.6 .47 .47 0 0 0-.6-.3z"/>
<path d="M152.2 119.7a.67 .67 0 0 1 1.3 0 .67 .67 0 0 1-1.3 0zM152.4 119.7a.45 .45 0 0 0 .9 0 .45 .45 0 0 0-.9 0z"/>
<path d="M153 122h.2v.2a.62 .62 0 0 1 .9 0 .62 .62 0 0 1 0 .9 .62 .62 0 0 1-.8 0v.7h-.3zM153.4 122.3a.42 .42 0 0 0 0 .7 .42 .42 0 0 0 .6-.4l-.1-.4z"/>
<path d="M153 125.1a.57 .57 0 0 1 .7-.2 .57 .57 0 0 1 .3 .7h-.9a.53 .53 0 0 0 .8 .4l.1 .1a.71 .71 0 0 1-1-.1 .71 .71 0 0 1 0-.9zM153.3 125.1l-.2 .3h.7l-.1-.3z"/>
<path d="M153.9 131a.58 .58 0 0 1 .7-.2 .58 .58 0 0 1 .4 .7h-1a.51 .51 0 0 0 .8 .4l.1 .1a.71 .71 0 0 1-.9-.1 .71 .71 0 0 1-.1-.9zM154.2 131l-.2 .3h.7l-.1-.3z"/>
<path d="M155.5 121.5h.3v.2h-.3zM155.5 122h.3v1.2h-.3z"/>
<path d="M155.7 124.5h.2v.2h-.2zM155.7 124.9h.2v1.3h-.2z"/>
<path d="M156.2 122.2a.58 .58 0 0 1 .7-.2 .58 .58 0 0 1 .3 .6h-.9a.53 .53 0 0 0 .8 .4l.1 .2a.71 .71 0 0 1-.9-.1 .71 .71 0 0 1-.1-.9zM156.5 122.2l-.2 .3h.7l-.1-.3z"/>
<path d="M157.4 127.4a1.02 1.02 0 0 1 1.2 .1 1.02 1.02 0 0 1 .2 1.2 1.39 1.39 0 0 1-1.4 .4zM157.6 127.6v1.4a.76 .76 0 0 0 1.1-.7 .76 .76 0 0 0-1.1-.7z"/>
<path d="M156.4 131l.4-.2 .4 .2v-.8h.3v1.9h-.2l-.1-.2a.63 .63 0 0 1-.9 0 .63 .63 0 0 1 .1-.9zM156.7 131a.48 .48 0 0 0-.2 .6 .48 .48 0 0 0 .5 .3 .47 .47 0 0 0 .2-.6 .47 .47 0 0 0-.5-.3z"/>
<path d="M157.6 125.1a.57 .57 0 0 1 .7-.2 .57 .57 0 0 1 .3 .7h-.9a.51 .51 0 0 0 .8 .4v.1a.71 .71 0 0 1-.9-.1 .71 .71 0 0 1 0-.9zM157.9 125.1l-.2 .3h.7l-.1-.3z"/>
<path d="M158 131a.57 .57 0 0 1 .7-.2 .57 .57 0 0 1 .3 .7h-1a.53 .53 0 0 0 .8 .4l.1 .1a.71 .71 0 0 1-.9-.1 .71 .71 0 0 1 0-.9zM158.2 131l-.2 .3h.7l-.1-.3z"/>
<path d="M158.5 122.1l.4-.1 .5 .2v1h-.2v-.1a.41 .41 0 0 1-.6 .1 .41 .41 0 0 1 0-.6l.6-.2v-.1l-.3-.2-.4 .1zM158.7 122.7v.3l.3 .1 .2-.2v-.3z"/>
<path d="M160.3 127.9h.3v.2a.62 .62 0 0 1 .8 0 .62 .62 0 0 1 .1 .8 .62 .62 0 0 1-.9 .1v.7h-.2zM160.7 128.2a.42 .42 0 0 0 .1 .7 .42 .42 0 0 0 .6-.4l-.2-.4z"/>
<path d="M159.4 131l.4-.2 .4 .2v-.2h.2v.4a1.51 1.51 0 0 1-.2 1.3l-.5 .1-.4-.1v-.2l.2 .1a.46 .46 0 0 0 .5 0 .46 .46 0 0 0 .2-.5 .61 .61 0 0 1-.9 0 .61 .61 0 0 1 .1-.9zM159.6 131a.46 .46 0 0 0-.2 .6 .46 .46 0 0 0 .5 .3 .46 .46 0 0 0 .3-.6 .46 .46 0 0 0-.6-.3z"/>
<path d="M161.7 130.9l.4-.1 .5 .3 .1 1h-.3v-.2a.42 .42 0 0 1-.6 .1 .42 .42 0 0 1 0-.6l.6-.1v-.2l-.3-.2-.4 .1zM161.9 131.5v.4h.4l.1-.2v-.3z"/>
<path d="M162.9 128a.57 .57 0 0 1 .7-.1 .57 .57 0 0 1 .3 .6h-.9a.51 .51 0 0 0 .3 .5 .51 .51 0 0 0 .5-.1v.2a.71 .71 0 0 1-.9-.1 .71 .71 0 0 1 0-1zM163.1 128.1l-.1 .3h.7l-.2-.3z"/>
<path d="M162.8 119.7a.67 .67 0 0 1 1.3 0 .67 .67 0 0 1-1.3 0zM163 119.7a.45 .45 0 0 0 .9 0 .45 .45 0 0 0-.9 0z"/>
<path d="M163.7 122h.2v.2a.62 .62 0 0 1 .9 0 .62 .62 0 0 1 0 .9 .62 .62 0 0 1-.9 0v.7h-.2zM164 122.3a.42 .42 0 0 0 .1 .7 .42 .42 0 0 0 .6-.4l-.2-.4z"/>
<path d="M164 124.3h.3v.8a.61 .61 0 0 1 .8 .1 .61 .61 0 0 1 0 .8 .61 .61 0 0 1-.9 0v.2h-.2zM164.3 125.2a.47 .47 0 0 0 0 .6 .47 .47 0 0 0 .5 .2 .48 .48 0 0 0 .2-.6 .48 .48 0 0 0-.5-.3z"/>
<path d="M163.1 131l.4-.2 .4 .2v-.8h.3v1.9h-.2v-.2a.63 .63 0 0 1-1 0 .63 .63 0 0 1 .1-.9zM163.4 131a.48 .48 0 0 0-.2 .6 .48 .48 0 0 0 .5 .3 .47 .47 0 0 0 .2-.6 .47 .47 0 0 0-.5-.3z"/>
<path d="M165.6 124.9h.3l-.1 1.4-.1 .3-.4 .1v-.1l.2-.1 .1-.3zM165.6 124.5h.2v.2h-.2z"/>
<path d="M164.6 130.9l.4-.1 .5 .3 .1 1h-.3v-.2a.42 .42 0 0 1-.6 .1 .42 .42 0 0 1 0-.6l.6-.1v-.2l-.3-.2-.4 .1zM164.8 131.5v.4h.4l.1-.2v-.3z"/>
<path d="M165.4 127.9l.5-.1 .4 .3 .1 1h-.2v-.1a.42 .42 0 0 1-.7 .1 .42 .42 0 0 1 0-.6l.6-.2v-.1l-.3-.2-.3 .1zM165.7 128.6l-.1 .3 .5-.1v-.3z"/>
<path d="M166.3 125.1a.57 .57 0 0 1 .7-.2 .57 .57 0 0 1 .3 .7h-.9a.51 .51 0 0 0 .8 .4l.1 .1a.71 .71 0 0 1-1-.1 .71 .71 0 0 1 0-.9zM166.6 125.1l-.2 .3h.7l-.1-.3z"/>
<path d="M166 122.6a.66 .66 0 0 1 1.3 0 .66 .66 0 0 1-1.3 0zM166.2 122.6a.45 .45 0 0 0 .9 0 .45 .45 0 0 0-.9 0z"/>
<path d="M166.8 130.5a.15 .15 0 0 1 .3 0 .15 .15 0 0 1-.3 0zM166.8 130.8h.3v1.3h-.3z"/>
<path d="M166 119.2l.4-.2 .5 .2v-.2h.2v.4a1.51 1.51 0 0 1-.2 1.3l-.5 .1-.5-.1 .1-.1h.2a.46 .46 0 0 0 .5 0 .46 .46 0 0 0 .1-.5 .61 .61 0 0 1-.9 0 .61 .61 0 0 1 .1-.9zM166.3 119.2a.46 .46 0 0 0-.2 .6 .46 .46 0 0 0 .5 .3 .46 .46 0 0 0 .2-.6 .46 .46 0 0 0-.5-.3z"/>
<path d="M167.4 131.4a.67 .67 0 0 1 1.3 0 .67 .67 0 0 1-1.3 0zM167.6 131.5a.45 .45 0 0 0 .9 0 .45 .45 0 0 0-.9 0z"/>
<path d="M168.6 122.2a.57 .57 0 0 1 .7-.2 .57 .57 0 0 1 .3 .6h-.9a.53 .53 0 0 0 .8 .4l.1 .2a.71 .71 0 0 1-1-.1 .71 .71 0 0 1 0-.9zM168.8 122.2l-.1 .3h.7l-.1-.3z"/>
<path d="M169.2 127.5a.15 .15 0 0 1 .3 0 .15 .15 0 0 1-.3 0zM169.2 127.9h.3v1.2h-.3z"/>
<path d="M169.9 125.1a.57 .57 0 0 1 .7-.2 .57 .57 0 0 1 .3 .7h-1a.53 .53 0 0 0 .9 .4v.1a.71 .71 0 0 1-.9-.1 .71 .71 0 0 1 0-.9zM170.1 125.1l-.1 .3h.7l-.2-.3z"/>
<path d="M169.8 128.5a.66 .66 0 0 1 1.3 0 .66 .66 0 0 1-1.3 0zM170 128.5a.45 .45 0 0 0 .9 0 .45 .45 0 0 0-.9 0z"/>
<path d="M171.5 131.4a.67 .67 0 0 1 1.3 0 .67 .67 0 0 1-1.3 0zM171.7 131.5a.45 .45 0 0 0 .9 0 .45 .45 0 0 0-.9 0z"/>
<path d="M172.1 121.6a.15 .15 0 0 1 .3 0 .15 .15 0 0 1-.3 0zM172.1 122h.3v1.2h-.3z"/>
<path d="M171.3 125.1l.4-.2 .4 .2v-.8h.3v1.9h-.2v-.2a.63 .63 0 0 1-1 0 .63 .63 0 0 1 .1-.9zM171.5 125.1a.48 .48 0 0 0-.1 .6 .48 .48 0 0 0 .5 .3 .47 .47 0 0 0 .2-.6 .47 .47 0 0 0-.6-.3z"/>
<path d="M172.7 122.6a.67 .67 0 0 1 1.3 0 .67 .67 0 0 1-1.3 0zM172.9 122.6a.45 .45 0 0 0 .9 0 .45 .45 0 0 0-.9 0z"/>
<path d="M174.9 125.6a.7 .7 0 0 1 1.4 0 .7 .7 0 0 1-1.4 0zM175.1 125.6a.45 .45 0 0 0 .9 0 .45 .45 0 0 0-.9 0z"/>
<path d="M175.6 131.5a.7 .7 0 0 1 1.4 0 .7 .7 0 0 1-1.4 0zM175.8 131.5a.45 .45 0 0 0 .9 0 .45 .45 0 0 0-.9 0z"/>
<path d="M177.7 128.5a.67 .67 0 0 1 1.3 0 .67 .67 0 0 1-1.3 0zM177.9 128.5a.45 .45 0 0 0 .9 0 .45 .45 0 0 0-.9 0z"/>
<path d="M178.6 121.6a.15 .15 0 0 1 .3 0 .15 .15 0 0 1-.3 0zM178.6 122h.3v1.2h-.3z"/>
<path d="M179.4 124.6a.15 .15 0 0 1 .3 0 .15 .15 0 0 1-.3 0zM179.4 124.9h.3v1.3h-.3z"/>
<path d="M179.9 119.7a.7 .7 0 0 1 1.4 0 .7 .7 0 0 1-1.4 0zM180.2 119.7a.45 .45 0 0 0 .8 0 .45 .45 0 0 0-.8 0z"/>
<path d="M180.4 131.4a.67 .67 0 0 1 1.3 0 .67 .67 0 0 1-1.3 0zM180.6 131.5a.45 .45 0 0 0 .9 0 .45 .45 0 0 0-.9 0z"/>
<path d="M180.2 125.1l.4-.2 .4 .2v-.2h.3l-.1 .4a1.51 1.51 0 0 1-.2 1.3l-.4 .1-.5-.1 .1-.2 .1 .1a.46 .46 0 0 0 .6 0 .46 .46 0 0 0 .1-.5 .61 .61 0 0 1-.9 0 .61 .61 0 0 1 .1-.9zM180.4 125.1a.46 .46 0 0 0-.1 .6 .46 .46 0 0 0 .5 .3 .46 .46 0 0 0 .2-.6 .46 .46 0 0 0-.6-.3z"/>
<path d="M181.6 128l.4-.2 .4 .2v-.7h.2l.1 1.8h-.3v-.2a.63 .63 0 0 1-.9 .1 .63 .63 0 0 1 .1-1zM181.8 128.1a.48 .48 0 0 0-.2 .6 .48 .48 0 0 0 .6 .3 .47 .47 0 0 0 .2-.6 .47 .47 0 0 0-.6-.3z"/>
<path d="M183 121.5h.2v.2h-.2zM183 122h.2v1.2h-.2z"/>
<path d="M184.2 127.3h.2v.8a.62 .62 0 0 1 .9 0 .62 .62 0 0 1 0 .9 .62 .62 0 0 1-.9-.1v.2h-.2zM184.5 128.2a.44 .44 0 0 0 0 .6 .44 .44 0 0 0 .7-.1 .46 .46 0 0 0 0-.5 .46 .46 0 0 0-.6-.1z"/>
<path d="M184.6 125.1a.58 .58 0 0 1 .7-.2 .58 .58 0 0 1 .3 .7h-.9a.51 .51 0 0 0 .8 .4l.1 .1a.72 .72 0 0 1-1-.1 .72 .72 0 0 1 0-.9zM184.9 125.1l-.2 .3h.7l-.1-.3z"/>
<path d="M185.8 128a.57 .57 0 0 1 .7-.1 .57 .57 0 0 1 .3 .6h-.9a.53 .53 0 0 0 .8 .4l.1 .2a.71 .71 0 0 1-.9-.1 .71 .71 0 0 1-.1-1zM186.1 128.1l-.2 .3h.7l-.1-.3z"/>
<path d="M187.6 125.1a.57 .57 0 0 1 .7-.2 .57 .57 0 0 1 .3 .7h-1a.53 .53 0 0 0 .8 .4l.1 .1a.71 .71 0 0 1-.9-.1 .71 .71 0 0 1 0-.9zM187.8 125.1l-.2 .3h.7l-.1-.3z"/>
<path d="M188.9 122.1l.5-.1 .4 .1v-.7h.2v1.8h-.2v-.2a.63 .63 0 0 1-1 .1 .63 .63 0 0 1 .1-1zM189.2 122.2a.48 .48 0 0 0-.2 .6 .48 .48 0 0 0 .5 .3 .47 .47 0 0 0 .3-.6 .47 .47 0 0 0-.6-.3z"/>
<path d="M190 130.4h.2v.2h-.2zM190 130.8h.2v1.3h-.2z"/>
<path d="M189.2 127.9l.4-.1 .5 .3 .1 1h-.3v-.1a.42 .42 0 0 1-.6 .1 .42 .42 0 0 1 0-.6l.6-.2v-.1l-.3-.2-.4 .1zM189.4 128.6v.3h.4l.1-.2v-.2z"/>
<path d="M189.8 125.1l.5-.2 .4 .2v-.2h.2v.4a1.51 1.51 0 0 1-.2 1.3l-.5 .1-.4-.1v-.2l.2 .1a.47 .47 0 0 0 .5 0 .47 .47 0 0 0 .2-.5 .62 .62 0 0 1-1 0 .62 .62 0 0 1 .1-.9zM190.1 125.1a.46 .46 0 0 0-.2 .6 .46 .46 0 0 0 .5 .3 .46 .46 0 0 0 .2-.6 .46 .46 0 0 0-.5-.3z"/>
<path d="M190.5 131.4a.67 .67 0 0 1 1.3 0 .67 .67 0 0 1-1.3 0zM190.7 131.5a.45 .45 0 0 0 .9 0 .45 .45 0 0 0-.9 0z"/>
<path d="M190.4 122.1l.4-.1 .5 .2 .1 1h-.2l-.1-.1a.41 .41 0 0 1-.6 .1 .41 .41 0 0 1 0-.6l.6-.2v-.1l-.3-.2-.3 .1zM190.6 122.7v.3l.3 .1 .2-.2v-.3z"/>
<path d="M191.9 128a.58 .58 0 0 1 .7-.1 .58 .58 0 0 1 .3 .6h-.9a.51 .51 0 0 0 .8 .4v.2a.71 .71 0 0 1-.9-.1 .71 .71 0 0 1 0-1zM192.2 128.1l-.2 .3h.7l-.1-.3z"/>
<path d="M193.7 130.9l.4-.1 .5 .3v1h-.2v-.2a.42 .42 0 0 1-.6 .1 .42 .42 0 0 1 0-.6l.6-.1-.1-.2-.2-.2-.4 .1zM193.9 131.5v.4h.3l.2-.2v-.3z"/>
<path d="M194 122.1l.5-.1 .5 .2v1h-.2v-.1a.42 .42 0 0 1-.7 .1 .42 .42 0 0 1 0-.6l.6-.2v-.1l-.3-.2-.3 .1zM194.3 122.7v.3l.4-.1 .1-.3z"/>
<path d="M195.7 130.4h.2v.2h-.2zM195.7 130.8h.2v1.3h-.2z"/>
<path d="M195.5 122.1l.4-.1 .4 .2v-.2h.2v.3a1.51 1.51 0 0 1-.2 1.3l-.5 .2-.4-.1 .1-.2 .1 .1a.46 .46 0 0 0 .5-.1 .46 .46 0 0 0 .2-.5 .61 .61 0 0 1-.9 0 .61 .61 0 0 1 .1-.9zM195.7 122.2a.47 .47 0 0 0-.1 .6 .47 .47 0 0 0 .5 .2 .46 .46 0 0 0 .2-.5 .46 .46 0 0 0-.6-.3z"/>
<path d="M196.7 124.4a1.02 1.02 0 0 1 1.2 .2 1.02 1.02 0 0 1 .2 1.2 1.4 1.4 0 0 1-1.4 .4zM196.9 124.6v1.4a.76 .76 0 0 0 1.1-.7 .76 .76 0 0 0-1.1-.7z"/>
<path d="M197 122.2a.57 .57 0 0 1 .7-.2 .57 .57 0 0 1 .3 .6h-.9a.51 .51 0 0 0 .3 .5 .51 .51 0 0 0 .5-.1v.2a.71 .71 0 0 1-.9-.1 .71 .71 0 0 1 0-.9zM197.2 122.2l-.1 .3h.7l-.1-.3z"/>
<path d="M196.7 128.5a.67 .67 0 0 1 1.3 0 .67 .67 0 0 1-1.3 0zM196.9 128.5a.45 .45 0 0 0 .9 0 .45 .45 0 0 0-.9 0z"/>
<circle cx="198.4" cy="114.2" r=".27"/>
</g>
<path d="M12.8 13.7v10.7M13 12.8h119.7M132.9 12.8h63.7M196.7 13.7v10.7M13 24.5h183.6" fill="none" stroke="#000" stroke-width=".25"/>
<g fill="none" stroke="#000" stroke-width=".2">
<path d="M12.7 46.5h55.3M12.7 51.1h55.3M68.1 46.6v4.4M68.1 51.1v53.1M68.2 46.5h30.2M68.2 51.1h30.2M110.9 96.2h23.1M111.1 88h22.9M111.1 92.2h22.9M134.1 88.1v4M134.1 92.2v3.9M134.2 88h10.6"/>
<path d="M134.2 92.2h10.6M134.2 96.2h10.6M144.9 88.1v4M144.9 92.2v3.9M145 88h10.7M145 92.2h10.7M145 96.2h10.7M155.7 88.1v4M155.7 92.2v3.9M155.8 88h10.7M155.8 92.2h10.7M155.8 96.2h10.7"/>
<path d="M166.5 88.1v4M166.5 92.2v3.9M166.6 88h9.1M166.6 92.2h9.1M166.6 96.2h9.1M175.8 88.1v4M175.8 92.2v3.9M175.9 88h10.6M175.9 92.2h10.6M175.9 96.2h10.6M186.6 88.1v4M186.6 92.2v3.9"/>
<path d="M186.7 88h10.1M186.7 92.2h10.1M186.7 96.2h10.1M12.4 104.3h55.6M68.2 104.3h30.2M111.1 110.9h19.6M130.8 111v23.2M130.9 110.9h69.8M110.9 134.3h19.8M130.9 134.3h69.8"/>
</g>
<use href="#words"/>
</svg>
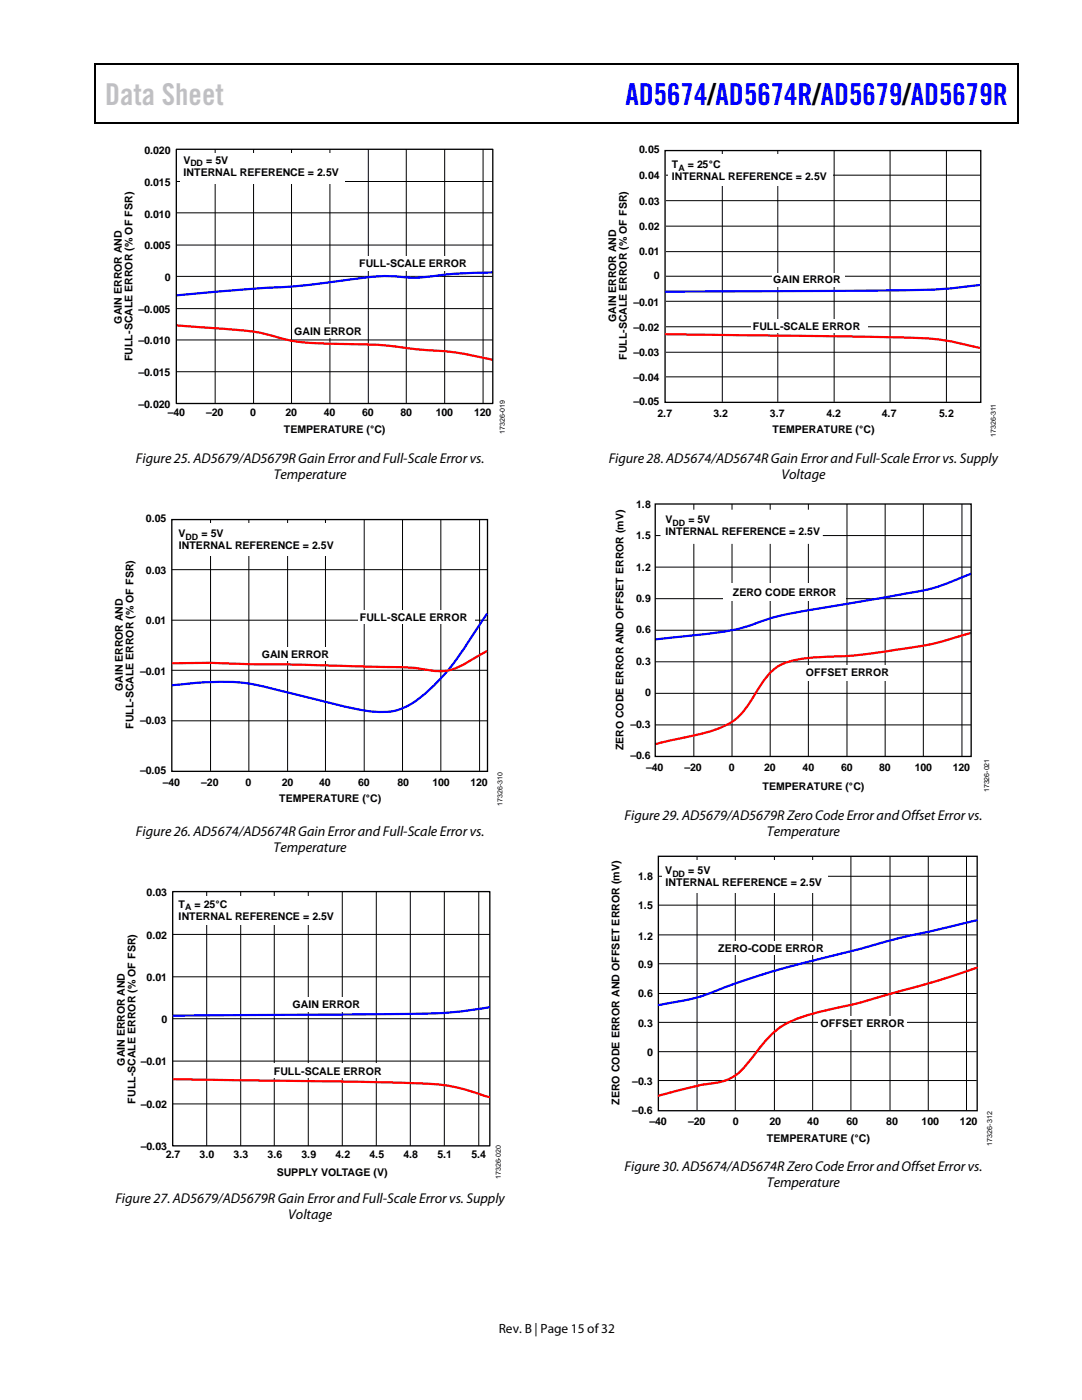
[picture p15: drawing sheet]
<svg xmlns="http://www.w3.org/2000/svg" width="216mm" height="279mm" viewBox="0 0 216 279" stroke-linecap="round" stroke-linejoin="round" font-family="sans-serif">
<defs><g id="words">
<text font-size="6" fill="#c1c1c1" x="21" y="21">Data Sheet</text>
<text font-size="6" fill="#00f" x="124.8" y="21">AD5674/AD5674R/AD5679/AD5679R</text>
<g font-size="2.8">
<text x="27.1" y="92.3">Figure 25. AD5679/AD5679RGain Error and Full-Scale Error vs.</text>
<text x="54.6" y="95.5">Temperature</text>
<text x="121.5" y="92.3">Figure 28. AD5674/AD5674RGain Error and Full-Scale Error vs. Supply</text>
<text x="156" y="95.5">Voltage</text>
<text x="27.1" y="166.9">Figure 26. AD5674/AD5674RGain Error and Full-Scale Error vs.</text>
<text x="124.6" y="163.7">Figure 29. AD5679/AD5679R Zero Code Error and Offset Error vs.</text>
<text x="153" y="166.9">Temperature</text>
<text x="54.6" y="170.1">Temperature</text>
<text x="124.6" y="233.7">Figure 30. AD5674/AD5674R Zero Code Error and Offset Error vs.</text>
<text x="153" y="236.9">Temperature</text>
<text x="23" y="240.1">Figure 27. AD5679/AD5679RGain Error and Full-Scale Error vs. Supply</text>
<text x="57.5" y="243.2">Voltage</text>
</g>
<text font-size="2.7" x="99.5" y="266">Rev. B | Page 15 of32</text>
<g font-size="2.1">
<text x="28.8" y="30.8">0.020</text>
<text x="36.6" y="32.7">V</text>
<text x="36.6" y="35.1">INTERNAL REFERENCE = 2.5V</text>
<text x="41.2" y="32.7">= 5V</text>
<text x="127.5" y="30.5">0.05</text>
<text x="127.5" y="35.7">0.04</text>
<text x="134.1" y="33.5">T</text>
<text x="137.2" y="33.5">= 25°C</text>
<text x="28.8" y="37.1">0.015</text>
<text x="127.5" y="40.9">0.03</text>
<text x="134.1" y="36">INTERNAL</text>
<text x="145.3" y="36">REFERENCE = 2.5V</text>
<text x="28.8" y="43.4">0.010</text>
<text x="127.5" y="45.9">0.02</text>
<text x="28.8" y="49.7">0.005</text>
<text x="71.7" y="53.3">FULL-SCALE ERROR</text>
<text x="127.5" y="50.9">0.01</text>
<text x="32.9" y="56.1">0</text>
<text x="130.5" y="55.7">0</text>
<text x="154.3" y="56.5">GAIN ERROR</text>
<text x="24.3" y="64.6" transform="rotate(-90 24.3 64.6)">GAIN ERROR AND</text>
<text x="27.6" y="62.4">–0.005</text>
<text x="122.9" y="64.3" transform="rotate(-90 122.9 64.3)">GAIN ERROR AND</text>
<text x="126.4" y="61.1">–0.01</text>
<text x="150.2" y="65.8">FULL-SCALE ERROR</text>
<text x="27.6" y="68.7">–0.010</text>
<text x="58.7" y="66.8">GAIN ERROR</text>
<text x="125" y="71.8" transform="rotate(-90 125 71.8)">FULL-SCALE ERROR (% OF FSR)</text>
<text x="126.4" y="71.1">–0.03</text>
<text x="126.4" y="66.1">–0.02</text>
<text x="26.5" y="72.1" transform="rotate(-90 26.5 72.1)">FULL-SCALE ERROR (% OF FSR)</text>
<text x="27.6" y="75">–0.015</text>
<text x="126.4" y="75.9">–0.04</text>
<text x="27.6" y="81.4">–0.020</text>
<text x="33.5" y="83">–40</text>
<text x="41.1" y="83">–20</text>
<text x="49.9" y="83">0</text>
<text x="57" y="83">20</text>
<text x="64.6" y="83">40</text>
<text x="72.3" y="83">60</text>
<text x="79.9" y="83">80</text>
<text x="87" y="83">100</text>
<text x="94.6" y="83">120</text>
<text x="126.4" y="80.9">–0.05</text>
<text x="131.2" y="83.2">2.7</text>
<text x="142.4" y="83.2">3.2</text>
<text x="153.6" y="83.2">3.7</text>
<text x="164.9" y="83.2">4.2</text>
<text x="176" y="83.2">4.7</text>
<text x="187.4" y="83.2">5.2</text>
<text x="56.6" y="86.5">TEMPERATURE (°C)</text>
<text x="154.1" y="86.5">TEMPERATURE (°C)</text>
<text x="127" y="101.3">1.8</text>
<text x="29.1" y="104.1">0.05</text>
<text x="35.6" y="107.2">V</text>
<text x="40.2" y="107.2">= 5V</text>
<text x="127" y="107.6">1.5</text>
<text x="132.8" y="106.8">INTERNAL REFERENCE = 2.5V</text>
<text x="132.8" y="104.4">V</text>
<text x="137.4" y="104.4">= 5V</text>
<text x="35.7" y="109.6">INTERNAL REFERENCE = 2.5V</text>
<text x="127" y="113.9">1.2</text>
<text x="29.1" y="114.5">0.03</text>
<text x="146.2" y="118.9">ZERO CODE ERROR</text>
<text x="29.1" y="124.6">0.01</text>
<text x="71.8" y="124">FULL-SCALE ERROR</text>
<text x="127" y="120.1">0.9</text>
<text x="52.2" y="131.2">GAIN ERROR</text>
<text x="127" y="126.4">0.6</text>
<text x="24.5" y="138" transform="rotate(-90 24.5 138)">GAIN ERROR AND</text>
<text x="28" y="134.8">–0.01</text>
<text x="127" y="132.7">0.3</text>
<text x="160.8" y="134.8">OFFSET ERROR</text>
<text x="128.7" y="139">0</text>
<text x="26.6" y="145.5" transform="rotate(-90 26.6 145.5)">FULL-SCALE ERROR (% OF FSR)</text>
<text x="28" y="144.6">–0.03</text>
<text x="124.4" y="149.8" transform="rotate(-90 124.4 149.8)">ZERO CODE ERROR AND OFFSET ERROR (mV)</text>
<text x="125.8" y="145.3">–0.3</text>
<text x="28" y="154.5">–0.05</text>
<text x="125.8" y="151.5">–0.6</text>
<text x="128.9" y="153.9">–40</text>
<text x="136.6" y="153.9">–20</text>
<text x="145.4" y="153.9">0</text>
<text x="152.5" y="153.9">20</text>
<text x="160.2" y="153.9">40</text>
<text x="167.8" y="153.9">60</text>
<text x="175.4" y="153.9">80</text>
<text x="182.6" y="153.9">100</text>
<text x="190.1" y="153.9">120</text>
<text x="32.5" y="156.8">–40</text>
<text x="40.2" y="156.8">–20</text>
<text x="49" y="156.8">0</text>
<text x="55.7" y="160.1">TEMPERATURE (°C)</text>
<text x="56.2" y="156.8">20</text>
<text x="63.7" y="156.8">40</text>
<text x="71.4" y="156.8">60</text>
<text x="79.3" y="156.8">80</text>
<text x="86.3" y="156.8">100</text>
<text x="93.9" y="156.8">120</text>
<text x="152.2" y="157.7">TEMPERATURE (°C)</text>
<text x="29.3" y="178.9">0.03</text>
<text x="127.3" y="175.6">1.8</text>
<text x="132.7" y="174.4">V</text>
<text x="132.8" y="176.9">INTERNAL REFERENCE = 2.5V</text>
<text x="137.3" y="174.4">= 5V</text>
<text x="35.6" y="183.6">INTERNAL REFERENCE = 2.5V</text>
<text x="35.6" y="181.1">T</text>
<text x="38.8" y="181.1">= 2</text>
<text x="41.8" y="181.1">5°C</text>
<text x="127.3" y="181.5">1.5</text>
<text x="29.3" y="187.3">0.02</text>
<text x="127.3" y="187.5">1.2</text>
<text x="143.3" y="190.1">ZERO-CODE ERROR</text>
<text x="29.3" y="195.8">0.01</text>
<text x="127.3" y="193.2">0.9</text>
<text x="58.4" y="201.2">GAIN ERROR</text>
<text x="127.3" y="199">0.6</text>
<text x="32.2" y="204.2">0</text>
<text x="127.3" y="204.9">0.3</text>
<text x="163.7" y="205">OFFSET ERROR</text>
<text x="24.9" y="212.7" transform="rotate(-90 24.9 212.7)">GAIN ERROR AND</text>
<text x="28.1" y="212.6">–0.01</text>
<text x="54.6" y="214.6">FULL-SCALE ERROR</text>
<text x="129.1" y="210.7">0</text>
<text x="27" y="220.3" transform="rotate(-90 27 220.3)">FULL-SCALE ERROR (% OF FSR)</text>
<text x="28.1" y="221.1">–0.02</text>
<text x="123.6" y="220.5" transform="rotate(-90 123.6 220.5)">ZERO CODE ERROR AND OFFSET ERROR (mV)</text>
<text x="126.2" y="216.5">–0.3</text>
<text x="126.2" y="222.3">–0.6</text>
<text x="129.6" y="224.6">–40</text>
<text x="137.3" y="224.6">–20</text>
<text x="146.2" y="224.6">0</text>
<text x="153" y="227.9">TEMPERATURE (°C)</text>
<text x="153.5" y="224.6">20</text>
<text x="161.1" y="224.6">40</text>
<text x="168.9" y="224.6">60</text>
<text x="176.8" y="224.6">80</text>
<text x="183.9" y="224.6">100</text>
<text x="191.6" y="224.6">120</text>
<text x="28.1" y="229.5">–0.03</text>
<text x="33.1" y="231.2">2.7</text>
<text x="39.8" y="231.2">3.0</text>
<text x="46.6" y="231.2">3.3</text>
<text x="53.4" y="231.2">3.6</text>
<text x="60.2" y="231.2">3.9</text>
<text x="67" y="231.2">4.2</text>
<text x="73.7" y="231.2">4.5</text>
<text x="80.5" y="231.2">4.8</text>
<text x="87.3" y="231.2">5.1</text>
<text x="94.1" y="231.2">5.4</text>
<text x="55.2" y="234.7">SUPPLY VOLTAGE (V)</text>
</g>
<g font-size="1.8">
<text x="38" y="33.2">DD</text>
<text x="135.4" y="34.1">A</text>
<text x="37" y="107.7">DD</text>
<text x="134.2" y="175">DD</text>
<text x="36.9" y="181.7">A</text>
</g>
<text font-size="1.7" x="134.2" y="104.9">DD</text>
<g font-size="1.4">
<text x="100.7" y="86.6" transform="rotate(-90 100.7 86.6)">17326-019</text>
<text x="198.7" y="87.2" transform="rotate(-90 198.7 87.2)">17326-311</text>
<text x="100.3" y="160.8" transform="rotate(-90 100.3 160.8)">17326-310</text>
<text x="197.4" y="158.1" transform="rotate(-90 197.4 158.1)">17326-021</text>
<text x="198" y="228.6" transform="rotate(-90 198 228.6)">17326-312</text>
<text x="100" y="235.4" transform="rotate(-90 100 235.4)">17326-020</text>
</g>
</g></defs>
<path d="M18.9 12.7h.3v1h-.3zM18.9 12.7h.3v.3h-.3zM83.1 12.7h.3v.3h-.3zM202.9 12.7h.3v1h-.3zM202.9 12.7h.3v.3h-.3zM18.9 24.4h.3v.2h-.3zM82.9 24.4h.2v.2h-.2zM202.9 24.4h.3v.2h-.3z" fill="#000"/>
<path d="M19 13.7v10.7M19.2 12.8h63.9M83.4 12.8h119.5M203 13.7v10.7M19.2 24.5h183.7" fill="none" stroke="#000" stroke-width=".25"/>
<g fill="none" stroke="#000" stroke-width=".2">
<path d="M35.2 36.2h63.1M42.9 29.8v50.7M50.6 29.8v50.7M58.2 29.8v50.7M65.8 29.8v50.7M73.5 29.8v50.7M81.1 29.8v50.7M88.7 29.8v50.7M96.4 29.8v50.7M35.2 55.2h63.1M35.2 42.5h63.1M35.2 48.9h63.1"/>
<path d="M35.2 61.6h63.1M35.2 67.8h63.1M35.2 74.2h63.1"/>
</g>
<path d="M98.3 54.4a99.4 99.4 0 0 0-14.4 1h-2.4a37.5 37.5 0 0 0-12.2 .5 164.5 164.5 0 0 1-19.9 1.8l-14.2 1.2" fill="none" stroke="#00f" stroke-width=".44"/>
<path d="M35.2 64.9l8 .6a48.7 48.7 0 0 1 12.1 1.8 37.2 37.2 0 0 0 11.1 1.3 97.3 97.3 0 0 1 17.5 1.2 64.1 64.1 0 0 1 14.4 2" fill="none" stroke="#f00" stroke-width=".44"/>
<g fill="#fff">
<path d="M71.4 51.1h23.2v2.8h-23.2z" fill-rule="evenodd"/>
<path d="M58.4 64.8h14.6v2.7h-14.6z" fill-rule="evenodd"/>
<path d="M36 30.5h32.8v6.2h-32.8z" fill-rule="evenodd"/>
</g>
<path d="M35.2 29.8h63.1v50.7h-63.1zM34.3 103.7h63v50.2h-63z" fill="none" stroke="#000" stroke-width=".26"/>
<path d="M42 103.7v50.2M49.7 103.7v50.2M57.4 103.7v50.2M64.9 103.7v50.2M72.7 103.7v50.2M80.3 103.7v50.2M88 103.7v50.2M95.7 103.7v50.2" fill="none" stroke="#000" stroke-width=".2"/>
<path d="M35 104.4h32.8v6.6h-32.8z" fill="#fff"/>
<path d="M34.3 113.7h63.1M34.3 123.8h63.1M34.3 133.8h63.1M34.3 143.9h63.1" fill="none" stroke="#000" stroke-width=".2"/>
<path d="M97.2 122.5l-2.6 3.8a46.3 46.3 0 0 1-11.1 13.2 11.5 11.5 0 0 1-9.2 2.5 168.1 168.1 0 0 1-16.4-3.7l-2.2-.5a41.1 41.1 0 0 0-17.2-1.5l-4.2 .5" fill="none" stroke="#00f" stroke-width=".44"/>
<path d="M97.2 129.9l-.9 .5a26.5 26.5 0 0 1-6.8 3.4 19.4 19.4 0 0 1-6.7-.5l-23.7-.7-10.5-.1a154.8 154.8 0 0 0-14.3-.1" fill="none" stroke="#f00" stroke-width=".44"/>
<g fill="#fff">
<path d="M71.5 121.8h23.2v2.8h-23.2z" fill-rule="evenodd"/>
<path d="M52 129.1h14.5v2.7h-14.5z" fill-rule="evenodd"/>
</g>
<g fill="none" stroke="#000" stroke-width=".2">
<path d="M41.2 177.9v50.8M48 177.9v50.8M54.7 177.9v50.8M61.5 177.9v50.8M68.3 177.9v50.8M75.1 177.9v50.8M81.9 177.9v50.8M88.7 177.9v50.8M95.5 177.9v50.8M34.5 186.5h63.2M34.5 194.9h63.2M34.5 203.3h63.2"/>
<path d="M34.5 211.8h63.2M34.5 220.3h63.2"/>
</g>
<path d="M34.5 177.9h63.2v50.8h-63.2z" fill="none" stroke="#000" stroke-width=".26"/>
<path d="M97.7 201l-2 .3a87.7 87.7 0 0 1-16.2 1.1l-45 .3" fill="none" stroke="#00f" stroke-width=".44"/>
<path d="M34.5 215.4l15.2 .2a868.7 868.7 0 0 1 38.3 .9 53.3 53.3 0 0 1 9.7 2.5" fill="none" stroke="#f00" stroke-width=".44"/>
<g fill="#fff">
<path d="M35 178.8h32.9v5.7h-32.9z" fill-rule="evenodd"/>
<path d="M57.7 199h15v2.9h-15z" fill-rule="evenodd"/>
<path d="M54.1 212.2h22.7v2.9h-22.7z" fill-rule="evenodd"/>
</g>
<g fill="none" stroke="#000" stroke-width=".2">
<path d="M132.9 35h62.7M144.1 30.1v50.1M155.2 30.1v50.1M166.4 30.1v50.1M177.6 30.1v50.1M188.8 30.1v50.1M132.9 50.2h62.7M132.9 45.1h62.7M132.9 40h62.7M132.9 55.1h62.7M132.9 75.2h62.7M132.9 70.3h62.7"/>
<path d="M132.9 65.2h62.7M132.9 60.1h62.7"/>
</g>
<path d="M132.7 30h63v50.3h-63z" fill="none" stroke="#000" stroke-width=".26"/>
<g fill="#fff">
<path d="M133.4 30.8h32.8v6.2h-32.8z"/>
<path d="M149.9 63.6h23.2v2.8h-23.2z"/>
<path d="M154.1 54.4h14.5v2.7h-14.5z"/>
</g>
<path d="M195.4 56.9l-2.8 .3a128.7 128.7 0 0 1-17.3 .8l-42.4 .2M193.8 114.5l-.9 .3a42 42 0 0 1-13.5 3.9l-16 2.7a60.1 60.1 0 0 0-15.2 3.9 120.6 120.6 0 0 1-16.2 2.2l-1.3 .1" fill="none" stroke="#00f" stroke-width=".44"/>
<path d="M132.9 66.7l42.4 .5a100.7 100.7 0 0 1 14.3 .9l5.8 1.3M193.8 126.3a75 75 0 0 1-16.8 3.7l-3 .4a102.8 102.8 0 0 1-12 .8 14.4 14.4 0 0 0-7.3 2.2 21.9 21.9 0 0 0-4.8 6.4 12.1 12.1 0 0 1-8.1 6.1l-11.1 2.6" fill="none" stroke="#f00" stroke-width=".44"/>
<g fill="none" stroke="#000" stroke-width=".2">
<path d="M130.7 119.5h63.1M130.7 113.2h63.1M130.7 106.9h63.1M138.4 100.6v50.4M146.1 100.6v50.4M153.7 100.6v50.4M161.3 100.6v50.4M169 100.6v50.4M176.6 100.6v50.4M184.2 100.6v50.4M191.9 100.6v50.4M130.7 132.1h63.1"/>
<path d="M130.7 125.8h63.1M130.7 138.4h63.1M130.7 144.7h63.1"/>
</g>
<g fill="#fff">
<path d="M144.3 116.3h24.5v3.6h-24.5z"/>
<path d="M157.6 132.7h21v3h-21z"/>
</g>
<path d="M131.8 100.9v.8h32.4v6.8h-32.4z" fill-rule="evenodd" fill="#fff"/>
<path d="M130.7 100.6h63.1v50.4h-63.1z" fill="none" stroke="#000" stroke-width=".26"/>
<g fill="none" stroke="#000" stroke-width=".2">
<path d="M131.5 174.9h63.4M139.1 171v50.6M146.7 171v50.6M154.5 171v50.6M162.2 171v50.6M169.8 171v50.6M177.6 171v50.6M185.2 171v50.6M192.9 171v50.6M131.5 198.3h63.4M131.5 192.3h63.4M131.5 186.6h63.4"/>
<path d="M131.5 180.6h63.4M131.5 215.6h63.4M131.5 204h63.4M131.5 209.9h63.4"/>
</g>
<path d="M131.4 170.9h63.6v50.8h-63.6z" fill="none" stroke="#000" stroke-width=".27"/>
<path d="M132.1 171.6h33.1v6.6h-33.1z" fill="#fff"/>
<path d="M194.9 183.7l-7.7 1.8a157.4 157.4 0 0 0-16.4 4.1 207.6 207.6 0 0 0-25.8 7.3l-.9 .3a41.4 41.4 0 0 1-11.8 3.2l-.8 .2" fill="none" stroke="#00f" stroke-width=".44"/>
<path d="M194.9 193.1a373.9 373.9 0 0 1-25.1 7.4 60.5 60.5 0 0 0-12.4 3.5 19.8 19.8 0 0 0-7 6.7l-.7 .9a9.9 9.9 0 0 1-8.1 4.7l-2.5 .4-7.6 2" fill="none" stroke="#f00" stroke-width=".44"/>
<g fill="#fff">
<path d="M142.8 187.9h21.9v2.8h-21.9z" fill-rule="evenodd"/>
<path d="M163.3 202.9h17.7v2.7h-17.7z" fill-rule="evenodd"/>
</g>
<use href="#words"/>
</svg>
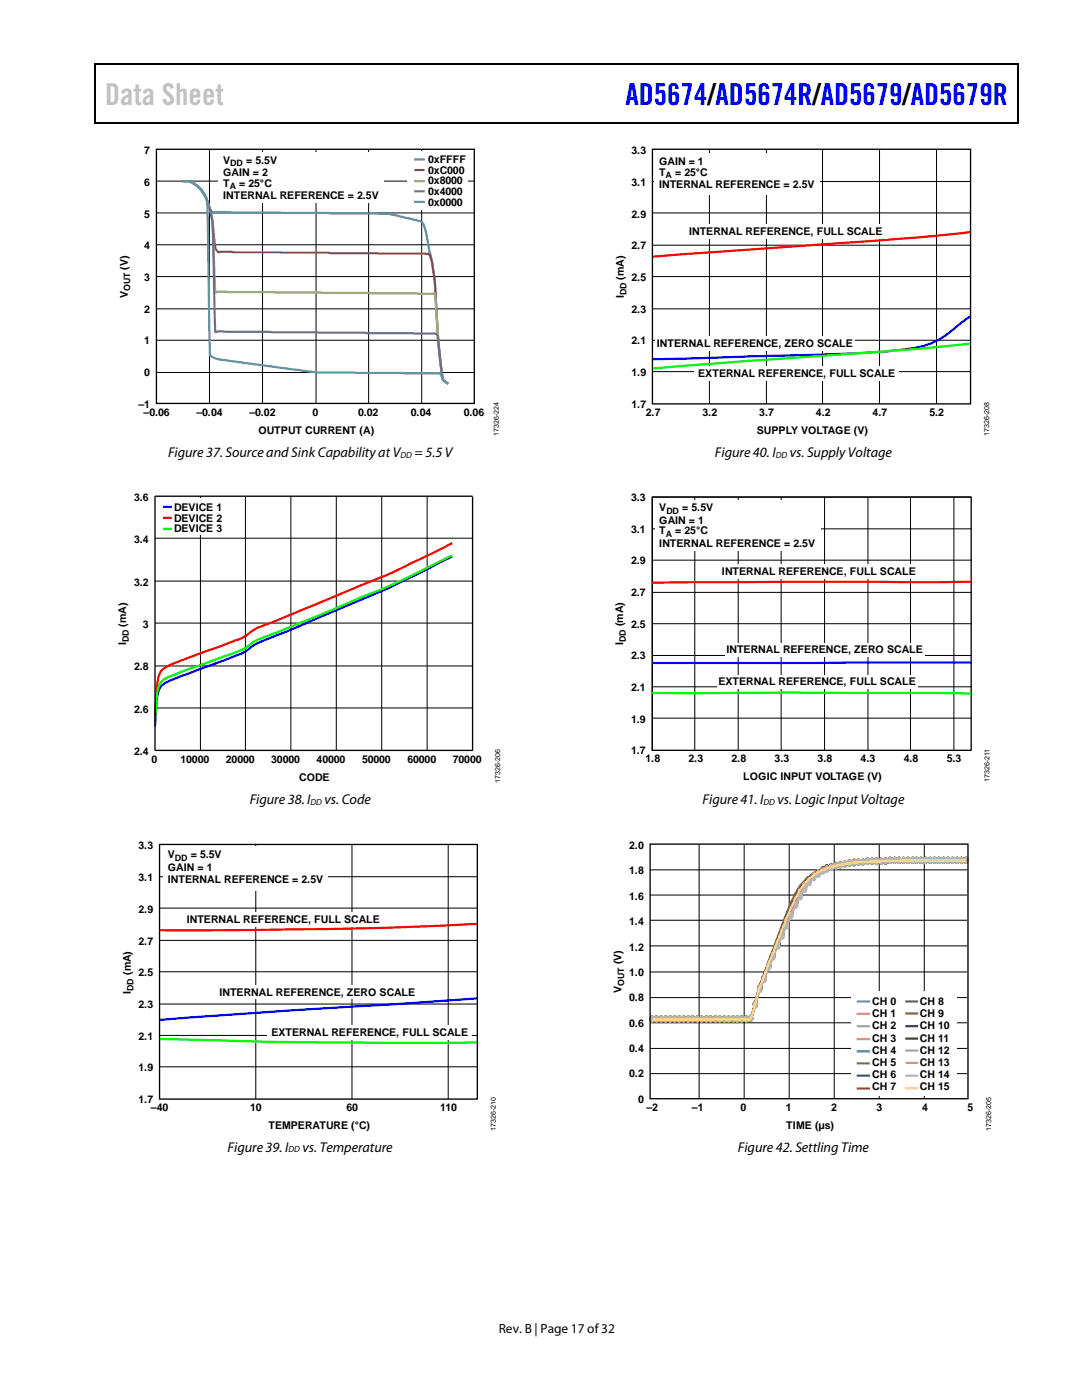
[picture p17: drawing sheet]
<svg xmlns="http://www.w3.org/2000/svg" width="216mm" height="279mm" viewBox="0 0 216 279" stroke-linecap="round" stroke-linejoin="round" font-family="sans-serif">
<defs><g id="words">
<text font-size="6" fill="#c1c1c1" x="21" y="21">Data Sheet</text>
<text font-size="6" fill="#00f" x="124.8" y="21">AD5674/AD5674R/AD5679/AD5679R</text>
<g font-size="2.8">
<text x="33.5" y="91.2">Figure 37. Source and Sink Capabilityat V</text>
<text x="82.7" y="91.2">= 5.5 V</text>
<text x="142.7" y="91.2">Figure 40. I</text>
<text x="157.6" y="91.2">vs. Supply Voltage</text>
<text x="49.8" y="160.5">Figure 38. I</text>
<text x="64.8" y="160.5">vs. Code</text>
<text x="140.2" y="160.5">Figure 41. I</text>
<text x="155.2" y="160.5">vs. Logic Input Voltage</text>
<text x="45.4" y="229.8">Figure 39. I</text>
<text x="60.4" y="229.8">vs. Temperature</text>
<text x="147.2" y="229.9">Figure 42. Settling Time</text>
</g>
<text font-size="2.7" x="99.5" y="266">Rev. B | Page 17 of32</text>
<g font-size="2.1">
<text x="28.8" y="30.7">7</text>
<text x="44.5" y="35.1">GAIN = 2</text>
<text x="44.5" y="32.6">V</text>
<text x="49.1" y="32.6">= 5.5V</text>
<text x="85.4" y="32.6">0xFFFF</text>
<text x="85.4" y="34.7">0xC000</text>
<text x="126" y="30.7">3.3</text>
<text x="131.5" y="33">GAIN = 1</text>
<text x="131.5" y="35.1">T</text>
<text x="134.7" y="35.1">= 25°C</text>
<text x="28.8" y="37.1">6</text>
<text x="44.5" y="39.7">INTERNAL REFERENCE = 2.5V</text>
<text x="44.5" y="37.2">T</text>
<text x="47.7" y="37.2">= 25°C</text>
<text x="85.4" y="36.8">0x8000</text>
<text x="85.4" y="38.9">0x4000</text>
<text x="85.4" y="41">0x0000</text>
<text x="126" y="37.1">3.1</text>
<text x="131.5" y="37.6">INTERNAL REFERENCE = 2.5V</text>
<text x="28.8" y="43.4">5</text>
<text x="126" y="43.4">2.9</text>
<text x="137.5" y="46.8">INTERNAL REFERENCE, FULL SCALE</text>
<text x="25.5" y="53.8" transform="rotate(-90 25.5 53.8)">(V)</text>
<text x="28.8" y="49.7">4</text>
<text x="126" y="49.7">2.7</text>
<text x="25.5" y="59.6" transform="rotate(-90 25.5 59.6)">V</text>
<text x="28.8" y="56.1">3</text>
<text x="124.5" y="55.8" transform="rotate(-90 124.5 55.8)">(mA)</text>
<text x="124.5" y="59.6" transform="rotate(-90 124.5 59.6)">I</text>
<text x="126" y="56.1">2.5</text>
<text x="28.8" y="62.4">2</text>
<text x="126" y="62.4">2.3</text>
<text x="28.8" y="68.7">1</text>
<text x="126" y="68.7">2.1</text>
<text x="131.1" y="69.2">INTERNAL</text>
<text x="142.3" y="69.2">REFERENCE, ZERO SCALE</text>
<text x="28.8" y="75.1">0</text>
<text x="126" y="75.1">1.9</text>
<text x="139.3" y="75.3">EXTERNAL REFERENCE, FULL SCALE</text>
<text x="27.6" y="81.4">–1</text>
<text x="28.7" y="83">–0.06</text>
<text x="39.2" y="83">–0.04</text>
<text x="49.8" y="83">–0.02</text>
<text x="62.4" y="83">0</text>
<text x="71.4" y="83">0.02</text>
<text x="82" y="83">0.04</text>
<text x="92.5" y="83">0.06</text>
<text x="126" y="81.4">1.7</text>
<text x="128.9" y="83">2.7</text>
<text x="140.2" y="83">3.2</text>
<text x="151.5" y="83">3.7</text>
<text x="162.8" y="83">4.2</text>
<text x="174.1" y="83">4.7</text>
<text x="185.4" y="83">5.2</text>
<text x="51.6" y="86.6">OUTPUT CURRENT (A)</text>
<text x="151" y="86.6">SUPPLY VOLTAGE (V)</text>
<text x="26.7" y="100">3.6</text>
<text x="34.7" y="102">DEVICE 1</text>
<text x="125.9" y="100">3.3</text>
<text x="34.7" y="104.1">DEVICE 2</text>
<text x="34.7" y="106.2">DEVICE 3</text>
<text x="125.9" y="106.3">3.1</text>
<text x="131.5" y="104.5">GAIN = 1</text>
<text x="131.5" y="106.6">T</text>
<text x="131.5" y="102.1">V</text>
<text x="134.7" y="106.6">= 25°C</text>
<text x="136.1" y="102.1">= 5.5V</text>
<text x="26.7" y="108.4">3.4</text>
<text x="125.9" y="112.6">2.9</text>
<text x="131.5" y="109.1">INTERNAL REFERENCE = 2.5V</text>
<text x="26.7" y="116.9">3.2</text>
<text x="125.9" y="118.9">2.7</text>
<text x="144.1" y="114.7">INTERNAL REFERENCE, FUL</text>
<text x="173.7" y="114.7">L SCALE</text>
<text x="25.2" y="125" transform="rotate(-90 25.2 125)">(mA)</text>
<text x="28.5" y="125.3">3</text>
<text x="124.4" y="125" transform="rotate(-90 124.4 125)">(mA)</text>
<text x="125.9" y="125.2">2.5</text>
<text x="25.2" y="128.8" transform="rotate(-90 25.2 128.8)">I</text>
<text x="124.4" y="128.7" transform="rotate(-90 124.4 128.7)">I</text>
<text x="125.9" y="131.6">2.3</text>
<text x="144.9" y="130.4">INTERNAL</text>
<text x="156.2" y="130.4">REFERENCE, ZERO SCALE</text>
<text x="26.7" y="133.8">2.8</text>
<text x="125.9" y="137.9">2.1</text>
<text x="143.3" y="136.8">EXTERNAL REFERENCE, FUL</text>
<text x="173.7" y="136.8">L SCALE</text>
<text x="26.7" y="142.2">2.6</text>
<text x="125.9" y="144.2">1.9</text>
<text x="26.7" y="150.7">2.4</text>
<text x="30.2" y="152.3">0</text>
<text x="36" y="152.3">10000</text>
<text x="45.1" y="152.3">20000</text>
<text x="54.1" y="152.3">30000</text>
<text x="59.7" y="155.8">CODE</text>
<text x="63.2" y="152.3">40000</text>
<text x="72.2" y="152.3">50000</text>
<text x="81.3" y="152.3">60000</text>
<text x="90.4" y="152.3">70000</text>
<text x="125.9" y="150.5">1.7</text>
<text x="128.8" y="152.1">1.8</text>
<text x="137.4" y="152.1">2.3</text>
<text x="146" y="152.1">2.8</text>
<text x="148.3" y="155.7">LOGIC INPUT VOLTAGE (V)</text>
<text x="154.6" y="152.1">3.3</text>
<text x="163.1" y="152.1">3.8</text>
<text x="171.7" y="152.1">4.3</text>
<text x="180.3" y="152.1">4.8</text>
<text x="188.9" y="152.1">5.3</text>
<text x="27.6" y="169.5">3.3</text>
<text x="33.5" y="173.7">GAIN = 1</text>
<text x="33.5" y="171.3">V</text>
<text x="38.1" y="171.3">= 5.5V</text>
<text x="125.6" y="169.4">2.0</text>
<text x="27.6" y="175.8">3.1</text>
<text x="33.5" y="176.2">INTERNAL REFERENCE = 2.5V</text>
<text x="125.6" y="179.6">1.6</text>
<text x="125.6" y="174.5">1.8</text>
<text x="27.6" y="182.2">2.9</text>
<text x="37.3" y="184.2">INTERNAL REFERENCE, FULL SCALE</text>
<text x="125.6" y="184.6">1.4</text>
<text x="27.6" y="188.5">2.7</text>
<text x="125.6" y="189.7">1.2</text>
<text x="26.1" y="194.6" transform="rotate(-90 26.1 194.6)">(mA)</text>
<text x="27.6" y="194.8">2.5</text>
<text x="124" y="192.5" transform="rotate(-90 124 192.5)">(V)</text>
<text x="125.6" y="194.8">1.0</text>
<text x="26.1" y="198.3" transform="rotate(-90 26.1 198.3)">I</text>
<text x="27.6" y="201.2">2.3</text>
<text x="43.8" y="198.7">INTERNAL REFERENCE, ZERO SCALE</text>
<text x="124" y="198.2" transform="rotate(-90 124 198.2)">V</text>
<text x="125.6" y="199.8">0.8</text>
<text x="174.1" y="200.6">CH 0</text>
<text x="174.1" y="203">CH 1</text>
<text x="183.6" y="200.6">CH 8</text>
<text x="183.6" y="203">CH 9</text>
<text x="27.6" y="207.5">2.1</text>
<text x="54.2" y="206.8">EXTERNAL REFERENCE, FULL SCALE</text>
<text x="125.6" y="210">0.4</text>
<text x="125.6" y="204.9">0.6</text>
<text x="174.1" y="205.4">CH 2</text>
<text x="174.1" y="207.9">CH 3</text>
<text x="183.6" y="205.4">CH 10</text>
<text x="183.6" y="207.9">CH 11</text>
<text x="27.6" y="213.8">1.9</text>
<text x="125.6" y="215">0.2</text>
<text x="174.1" y="210.3">CH 4</text>
<text x="174.1" y="212.8">CH 5</text>
<text x="174.1" y="215.2">CH 6</text>
<text x="183.6" y="210.3">CH 12</text>
<text x="183.6" y="212.8">CH 13</text>
<text x="183.6" y="215.2">CH 14</text>
<text x="27.6" y="220.2">1.7</text>
<text x="30.1" y="221.8">–40</text>
<text x="49.9" y="221.8">10</text>
<text x="69.1" y="221.8">60</text>
<text x="87.8" y="221.8">110</text>
<text x="127.3" y="220.1">0</text>
<text x="129" y="221.7">–2</text>
<text x="138.1" y="221.7">–1</text>
<text x="147.7" y="221.7">0</text>
<text x="156.8" y="221.7">1</text>
<text x="165.9" y="221.7">2</text>
<text x="174.1" y="217.6">CH 7</text>
<text x="174.9" y="221.7">3</text>
<text x="183.6" y="217.6">CH 15</text>
<text x="184" y="221.7">4</text>
<text x="193.1" y="221.7">5</text>
<text x="53.6" y="225.3">TEMPERATURE (°C)</text>
<text x="156.9" y="225.2">TIME (µs)</text>
</g>
<g font-size="1.8">
<text x="46" y="33.2">DD</text>
<text x="132.8" y="35.6">A</text>
<text x="45.8" y="37.8">A</text>
<text x="26" y="58.1" transform="rotate(-90 26 58.1)">OUT</text>
<text x="125" y="59" transform="rotate(-90 125 59)">DD</text>
<text x="79.9" y="91.4">DD</text>
<text x="154.8" y="91.4">DD</text>
<text x="132.8" y="107.2">A</text>
<text x="133" y="102.6">DD</text>
<text x="25.7" y="128.2" transform="rotate(-90 25.7 128.2)">DD</text>
<text x="124.9" y="128.1" transform="rotate(-90 124.9 128.1)">DD</text>
<text x="62" y="160.7">DD</text>
<text x="152.4" y="160.7">DD</text>
<text x="34.9" y="171.8">DD</text>
<text x="26.6" y="197.7" transform="rotate(-90 26.6 197.7)">DD</text>
<text x="124.5" y="196.8" transform="rotate(-90 124.5 196.8)">OUT</text>
<text x="57.6" y="230">DD</text>
</g>
<g font-size="1.4">
<text x="99.5" y="87" transform="rotate(-90 99.5 87)">17326-224</text>
<text x="197.3" y="87" transform="rotate(-90 197.3 87)">17326-208</text>
<text x="99.8" y="156.2" transform="rotate(-90 99.8 156.2)">17326-206</text>
<text x="197.4" y="156.1" transform="rotate(-90 197.4 156.1)">17326-211</text>
<text x="98.9" y="225.7" transform="rotate(-90 98.9 225.7)">17326-210</text>
<text x="197.8" y="225.7" transform="rotate(-90 197.8 225.7)">17326-205</text>
</g>
</g></defs>
<path d="M18.9 12.7h.3v1h-.3zM18.9 12.7h.3v.3h-.3zM83.1 12.7h.3v.3h-.3zM202.9 12.7h.3v1h-.3zM202.9 12.7h.3v.3h-.3zM18.9 24.4h.3v.2h-.3zM82.9 24.4h.2v.2h-.2zM202.9 24.4h.3v.2h-.3z" fill="#000"/>
<path d="M19 13.7v10.7M19.2 12.8h63.9M83.4 12.8h119.5M203 13.7v10.7M19.2 24.5h183.7" fill="none" stroke="#000" stroke-width=".25"/>
<path d="M31.3 36.1h63.4M41.8 29.8v50.8M52.4 29.8v50.8M63.1 29.8v50.8M73.6 29.8v50.8M84.1 29.8v50.8M31.3 55.2h63.4M31.3 48.8h63.4M31.3 42.5h63.4M31.3 67.9h63.4M31.3 61.6h63.4M31.3 74.3h63.4" fill="none" stroke="#000" stroke-width=".2"/>
<path d="M36.5 36.1a3.9 3.9 0 0 1 3.2 1.4l.5 .5 1 1.9a6.1 6.1 0 0 0 1.2 2.4l32.7 .3a17.1 17.1 0 0 1 5.4 .8l2.5 .5a1.8 1.8 0 0 1 1.8 1.7l.7 3.3a60.5 60.5 0 0 1 1.7 14.5 107.9 107.9 0 0 0 1.2 12.3l.1 .3 .9 .5" fill="none" stroke="#4a7ebb" stroke-width=".44"/>
<path d="M36.5 36.1a3.3 3.3 0 0 1 3 1.1 9.9 9.9 0 0 1 2.7 5.9l.3 1.9a19.9 19.9 0 0 0 .7 4.9l.5 .4 41.6 .4a.61 .61 0 0 1 .6 .6 45 45 0 0 1 1.2 11.1 106.8 106.8 0 0 0 1.3 13.3l.1 .3 .9 .5" fill="none" stroke="#be4b48" stroke-width=".44"/>
<path d="M36.5 36.1a3.9 3.9 0 0 1 3.4 1.5 12.9 12.9 0 0 1 2.6 7.6l.4 11.4v1.6l.2 .2 .4-.2h1.6l41.5 .4 .2 .1v.5l.7 9.3 .7 6.2a1.44 1.44 0 0 0 .7 1.5l.5 .3" fill="none" stroke="#98b954" stroke-width=".44"/>
<path d="M36.5 36.1a3.9 3.9 0 0 1 3.4 1.5 10.9 10.9 0 0 1 2.3 5.5 105.4 105.4 0 0 1 .5 12.4l.2 9.7v.9l.2 .2 .4-.2h1l42.1 .4 .5 .2 .2 .3 .9 7.7a1.45 1.45 0 0 0 .7 1.5l.5 .3" fill="none" stroke="#7d60a0" stroke-width=".44"/>
<path d="M36.5 36.1a3.9 3.9 0 0 1 3.4 1.5l1 1.4a3.3 3.3 0 0 1 .5 2.3l.5 29.4a2.69 2.69 0 0 0 1.9 1l17.5 2.4a75.5 75.5 0 0 0 9.6 .3l16.4 .1a.6 .6 0 0 1 .8 .6 2.41 2.41 0 0 0 1.3 1.4" fill="none" stroke="#46aac5" stroke-width=".44"/>
<path d="M31.2 29.8h63.4v50.7h-63.4z" fill="none" stroke="#000" stroke-width=".26"/>
<path d="M81.2 30.1h12.1v11.7h-12.1z" fill="#fff"/>
<path d="M82.6 31.8h2.2" fill="none" stroke="#4a7ebb" stroke-width=".44"/>
<path d="M82.6 33.9h2.2" fill="none" stroke="#be4b48" stroke-width=".44"/>
<path d="M82.6 36.1h2.2" fill="none" stroke="#98b954" stroke-width=".44"/>
<path d="M82.6 38.2h2.2" fill="none" stroke="#7d60a0" stroke-width=".44"/>
<path d="M82.6 40.3h2.2" fill="none" stroke="#46aac5" stroke-width=".44"/>
<path d="M43.7 30.3h32.9v10.2h-32.9z" fill="#fff"/>
<path d="M40 99.1v50.7M49 99.1v50.7M58 99.1v50.7M67.1 99.1v50.7M76.2 99.1v50.7M85.2 99.1v50.7M30.9 116h63.4M30.9 107.4h63.4M30.9 132.9h63.4M30.9 124.4h63.4M30.9 141.3h63.4" fill="none" stroke="#000" stroke-width=".2"/>
<path d="M90.2 111l-4.3 2.2a191.3 191.3 0 0 1-19.4 8.8l-12.7 5.4a12.3 12.3 0 0 0-4.7 2.6l-4.8 1.9-7.9 3a15 15 0 0 0-4.2 2 6.7 6.7 0 0 0-1 3.9l-.3 4.2" fill="none" stroke="#00f" stroke-width=".44"/>
<path d="M90.2 108.4l-4.3 2.2a156.4 156.4 0 0 1-14.3 6.4l-17.6 7.3a11.6 11.6 0 0 0-4.9 2.6l-1.4 .7-11.3 4.1a12.5 12.5 0 0 0-4.1 2.1 10.4 10.4 0 0 0-1.1 5.2l-.3 3.7" fill="none" stroke="#f00" stroke-width=".44"/>
<path d="M90.2 110.9l-7.8 3.8a112.1 112.1 0 0 1-11.1 4.8l-6.3 2.8-11.2 4.4a11.4 11.4 0 0 0-4.7 2.6l-6.4 2.4a75 75 0 0 0-10 4 5.7 5.7 0 0 0-1.5 4.2l-.3 4.2" fill="none" stroke="#0f0" stroke-width=".44"/>
<path d="M94.3 99.1v50.7M94.3 99h-63.4v50.8h63.4" fill="none" stroke="#000" stroke-width=".26"/>
<path d="M31.4 99.6h14.1v7.2h-14.1z" fill="#fff"/>
<path d="M32.5 101.1h1.8M95.2 199.2l-16.3 1.2-20.3 1.2-26.8 2" fill="none" stroke="#00f" stroke-width=".44"/>
<path d="M32.5 103.4h1.8" fill="none" stroke="#f00" stroke-width=".44"/>
<path d="M32.5 105.6h1.8M31.8 207.3l30.2 .7 18.9 .1h14.3" fill="none" stroke="#0f0" stroke-width=".44"/>
<path d="M31.8 175h63.4M51 168.5v50.8M70.2 168.5v50.8M89.4 168.5v50.8M31.8 181.2h63.4M31.8 187.7h63.4M31.8 193.9h63.4M31.8 200.4h63.4M31.8 206.6h63.4M31.8 212.9h63.4" fill="none" stroke="#000" stroke-width=".2"/>
<path d="M31.8 168.5h63.4v50.8h-63.4z" fill="none" stroke="#000" stroke-width=".26"/>
<g fill="#fff">
<path d="M37 182.1h39.7v2.8h-39.7z"/>
<path d="M43.6 196.7h39.6v2.7h-39.6z"/>
<path d="M53.4 204.6h40.8v2.8h-40.8z"/>
</g>
<path d="M95.2 184.4l-15.4 .7-12 .3-26.5 .3-9.5-.1" fill="none" stroke="#f00" stroke-width=".44"/>
<path d="M32.6 168.9h32.9v8.8h-32.9z" fill="#fff"/>
<path d="M130.2 36.2h63.5M141.6 29.8v50.8M152.9 29.8v50.8M164.1 29.8v50.8M175.5 29.8v50.8M186.9 29.8v50.8M130.2 55.2h63.5M130.2 48.9h63.5M130.2 42.5h63.5M130.2 61.6h63.5M130.2 74.2h63.5M130.2 67.9h63.5" fill="none" stroke="#000" stroke-width=".2"/>
<path d="M193.7 63.1l-2.2 1.6a17.1 17.1 0 0 1-11.1 5 311.4 311.4 0 0 1-26 1.3l-24.2 .7" fill="none" stroke="#00f" stroke-width=".44"/>
<path d="M193.7 46.3l-11.4 1.1-52.1 3.8" fill="none" stroke="#f00" stroke-width=".44"/>
<path d="M193.7 68.6l-11.4 1.1-36 2.5-16.1 1.3" fill="none" stroke="#0f0" stroke-width=".44"/>
<path d="M130.2 29.8h63.5v50.8h-63.5z" fill="none" stroke="#000" stroke-width=".26"/>
<g fill="#fff">
<path d="M130.6 30.6h33v8.3h-33z"/>
<path d="M137.2 44.7h39.8v2.8h-39.8z"/>
<path d="M130.8 67.1h39.8v2.8h-39.8z"/>
<path d="M138.6 73.1h40.8v2.8h-40.8z"/>
</g>
<g fill="none" stroke="#000" stroke-width=".2">
<path d="M138.6 99.2v50.5M147.3 99.2v50.5M155.9 99.2v50.5M164.5 99.2v50.5M173.2 99.2v50.5M181.7 99.2v50.5M190.3 99.2v50.5M193.8 99.2h-63.6v50.5M130.2 118.2h63.6M130.2 111.8h63.6M130.2 105.5h63.6M130.2 137.1h63.6"/>
<path d="M130.2 130.8h63.6M130.2 124.5h63.6M130.2 143.3h63.6"/>
</g>
<path d="M130.2 99.2h63.6v50.5h-63.6z" fill="none" stroke="#000" stroke-width=".26"/>
<path d="M193.8 132.2l-63.6 .1" fill="none" stroke="#00f" stroke-width=".44"/>
<path d="M193.8 116.1h-37.3l-26.3 .2" fill="none" stroke="#f00" stroke-width=".44"/>
<path d="M130.2 138.3l27.3-.1 36.3 .2" fill="none" stroke="#0f0" stroke-width=".44"/>
<g fill="#fff">
<path d="M130.7 99.7h32.9v10.2h-32.9z"/>
<path d="M143.9 112.6h39.7v2.8h-39.7z"/>
<path d="M144.7 128.3h39.8v2.8h-39.8z"/>
<path d="M143.1 134.7h40v2.7h-40z"/>
</g>
<g fill="none" stroke="#000" stroke-width=".2">
<path d="M129.7 178.6h63.3M129.7 173.6h63.3M139.5 168.6v50.6M148.5 168.6v50.6M157.5 168.6v50.6M166.5 168.6v50.6M175.4 168.6v50.6M184.4 168.6v50.6M129.7 188.8h63.3M129.7 183.7h63.3M129.7 199.1h63.3M129.7 194h63.3"/>
<path d="M129.7 209.2h63.3M129.7 204.1h63.3M129.7 214.3h63.3"/>
</g>
<path d="M192.7 171.7l-16.4 .1-4.1 .2-3.6 .5a11.2 11.2 0 0 0-8.5 4.4l-1.4 2.4-.9 2-4.6 11.5a59.9 59.9 0 0 0-3.3 10.1 1.1 1.1 0 0 1-1.6 .6l-18.1 .1" fill="none" stroke="#5b9bd5" stroke-width=".44"/>
<path d="M192.7 171.7l-17 .1-7.1 .6a13.5 13.5 0 0 0-7.2 2.7 13.3 13.3 0 0 0-3.7 6l-4.5 11.6a62.3 62.3 0 0 0-3.3 10.2l-.1 .3a.65 .65 0 0 1-.9 .3h-18.7" fill="none" stroke="#ed7d31" stroke-width=".44"/>
<path d="M192.7 171.7l-17 .1-3.5 .2-4.5 .5a11.4 11.4 0 0 0-6.9 3.5 24.2 24.2 0 0 0-3.9 7.5l-3.7 9.5a59.8 59.8 0 0 0-3.3 9.9 1.1 1.1 0 0 1-1.6 .6h-18.1" fill="none" stroke="#a6a6a6" stroke-width=".44"/>
<path d="M192.7 171.7l-16.4 .1-5.1 .3-2.3 .3a13 13 0 0 0-6.8 2.5 14.2 14.2 0 0 0-4.1 6.2l-4.8 12a62.2 62.2 0 0 0-3.3 9.8 .69 .69 0 0 1-1 .6h-18.7" fill="none" stroke="#ffc000" stroke-width=".44"/>
<path d="M192.7 171.7l-16.4 .1-5.1 .3-1.7 .3a11.7 11.7 0 0 0-9.4 5.1l-1.4 2.5-1.4 3.3-4.1 10.1a54.9 54.9 0 0 0-3.3 9.5 .91 .91 0 0 1-1.3 .6h-18.4" fill="none" stroke="#4472c4" stroke-width=".44"/>
<path d="M129.9 202.9l.2-.1a.59 .59 0 0 1 .4 .6 .59 .59 0 0 1-.4 .5 .64 .64 0 0 1-.2-1z" fill="#4472c4"/>
<path d="M129.9 202.9l.2-.1a.59 .59 0 0 1 .4 .6 .59 .59 0 0 1-.4 .5 .64 .64 0 0 1-.2-1z" fill="none" stroke="#4472c4" stroke-width=".26"/>
<path d="M130.8 202.9l.2-.1a.64 .64 0 0 1 .4 .6 .64 .64 0 0 1-.4 .5 .6 .6 0 0 1-.4-.4 .6 .6 0 0 1 .2-.6z" fill="#4472c4"/>
<path d="M130.8 202.9l.2-.1a.64 .64 0 0 1 .4 .6 .64 .64 0 0 1-.4 .5 .6 .6 0 0 1-.4-.4 .6 .6 0 0 1 .2-.6z" fill="none" stroke="#4472c4" stroke-width=".26"/>
<path d="M131.8 202.9l.1-.1a.64 .64 0 0 1 .4 .6 .64 .64 0 0 1-.4 .5 .64 .64 0 0 1-.1-1z" fill="#4472c4"/>
<path d="M131.8 202.9l.1-.1a.64 .64 0 0 1 .4 .6 .64 .64 0 0 1-.4 .5 .64 .64 0 0 1-.1-1z" fill="none" stroke="#4472c4" stroke-width=".26"/>
<path d="M132.6 202.9l.2-.1a.59 .59 0 0 1 .5 .6 .59 .59 0 0 1-.5 .5 .64 .64 0 0 1-.2-1z" fill="#4472c4"/>
<path d="M132.6 202.9l.2-.1a.59 .59 0 0 1 .5 .6 .59 .59 0 0 1-.5 .5 .64 .64 0 0 1-.2-1z" fill="none" stroke="#4472c4" stroke-width=".26"/>
<path d="M133.5 202.9l.2-.1a.59 .59 0 0 1 .4 .6 .59 .59 0 0 1-.4 .5 .64 .64 0 0 1-.2-1z" fill="#4472c4"/>
<path d="M133.5 202.9l.2-.1a.59 .59 0 0 1 .4 .6 .59 .59 0 0 1-.4 .5 .64 .64 0 0 1-.2-1z" fill="none" stroke="#4472c4" stroke-width=".26"/>
<path d="M134.4 202.9l.3-.1a.64 .64 0 0 1 .3 .6 .64 .64 0 0 1-.3 .5 .6 .6 0 0 1-.5-.4 .6 .6 0 0 1 .2-.6z" fill="#4472c4"/>
<path d="M134.4 202.9l.3-.1a.64 .64 0 0 1 .3 .6 .64 .64 0 0 1-.3 .5 .6 .6 0 0 1-.5-.4 .6 .6 0 0 1 .2-.6z" fill="none" stroke="#4472c4" stroke-width=".26"/>
<path d="M135.3 202.9l.2-.1a.64 .64 0 0 1 .4 .6 .64 .64 0 0 1-.4 .5 .6 .6 0 0 1-.4-.4 .6 .6 0 0 1 .2-.6z" fill="#4472c4"/>
<path d="M135.3 202.9l.2-.1a.64 .64 0 0 1 .4 .6 .64 .64 0 0 1-.4 .5 .6 .6 0 0 1-.4-.4 .6 .6 0 0 1 .2-.6z" fill="none" stroke="#4472c4" stroke-width=".26"/>
<path d="M136.3 202.9l.1-.1a.64 .64 0 0 1 .4 .6 .64 .64 0 0 1-.4 .5 .64 .64 0 0 1-.1-1z" fill="#4472c4"/>
<path d="M136.3 202.9l.1-.1a.64 .64 0 0 1 .4 .6 .64 .64 0 0 1-.4 .5 .64 .64 0 0 1-.1-1z" fill="none" stroke="#4472c4" stroke-width=".26"/>
<path d="M137.1 202.9l.2-.1a.59 .59 0 0 1 .4 .6 .59 .59 0 0 1-.4 .5 .64 .64 0 0 1-.2-1z" fill="#4472c4"/>
<path d="M137.1 202.9l.2-.1a.59 .59 0 0 1 .4 .6 .59 .59 0 0 1-.4 .5 .64 .64 0 0 1-.2-1z" fill="none" stroke="#4472c4" stroke-width=".26"/>
<path d="M138 202.9l.2-.1a.59 .59 0 0 1 .4 .6 .59 .59 0 0 1-.4 .5 .64 .64 0 0 1-.2-1z" fill="#4472c4"/>
<path d="M138 202.9l.2-.1a.59 .59 0 0 1 .4 .6 .59 .59 0 0 1-.4 .5 .64 .64 0 0 1-.2-1z" fill="none" stroke="#4472c4" stroke-width=".26"/>
<path d="M138.9 202.9l.3-.1a.64 .64 0 0 1 .3 .6 .64 .64 0 0 1-.3 .5 .6 .6 0 0 1-.5-.4 .6 .6 0 0 1 .2-.6z" fill="#4472c4"/>
<path d="M138.9 202.9l.3-.1a.64 .64 0 0 1 .3 .6 .64 .64 0 0 1-.3 .5 .6 .6 0 0 1-.5-.4 .6 .6 0 0 1 .2-.6z" fill="none" stroke="#4472c4" stroke-width=".26"/>
<path d="M139.9 202.9l.1-.1a.64 .64 0 0 1 .4 .6 .64 .64 0 0 1-.4 .5 .64 .64 0 0 1-.1-1z" fill="#4472c4"/>
<path d="M139.9 202.9l.1-.1a.64 .64 0 0 1 .4 .6 .64 .64 0 0 1-.4 .5 .64 .64 0 0 1-.1-1z" fill="none" stroke="#4472c4" stroke-width=".26"/>
<path d="M140.7 202.9l.2-.1a.59 .59 0 0 1 .5 .6 .59 .59 0 0 1-.5 .5 .64 .64 0 0 1-.2-1z" fill="#4472c4"/>
<path d="M140.7 202.9l.2-.1a.59 .59 0 0 1 .5 .6 .59 .59 0 0 1-.5 .5 .64 .64 0 0 1-.2-1z" fill="none" stroke="#4472c4" stroke-width=".26"/>
<path d="M141.6 202.9l.2-.1a.59 .59 0 0 1 .4 .6 .59 .59 0 0 1-.4 .5 .64 .64 0 0 1-.2-1z" fill="#4472c4"/>
<path d="M141.6 202.9l.2-.1a.59 .59 0 0 1 .4 .6 .59 .59 0 0 1-.4 .5 .64 .64 0 0 1-.2-1z" fill="none" stroke="#4472c4" stroke-width=".26"/>
<path d="M142.5 202.9l.3-.1a.64 .64 0 0 1 .3 .6 .64 .64 0 0 1-.3 .5 .6 .6 0 0 1-.5-.4 .6 .6 0 0 1 .2-.6z" fill="#4472c4"/>
<path d="M142.5 202.9l.3-.1a.64 .64 0 0 1 .3 .6 .64 .64 0 0 1-.3 .5 .6 .6 0 0 1-.5-.4 .6 .6 0 0 1 .2-.6z" fill="none" stroke="#4472c4" stroke-width=".26"/>
<path d="M143.4 202.9l.2-.1a.64 .64 0 0 1 .4 .6 .64 .64 0 0 1-.4 .5 .6 .6 0 0 1-.4-.4 .6 .6 0 0 1 .2-.6z" fill="#4472c4"/>
<path d="M143.4 202.9l.2-.1a.64 .64 0 0 1 .4 .6 .64 .64 0 0 1-.4 .5 .6 .6 0 0 1-.4-.4 .6 .6 0 0 1 .2-.6z" fill="none" stroke="#4472c4" stroke-width=".26"/>
<path d="M144.4 202.9l.1-.1a.64 .64 0 0 1 .4 .6 .64 .64 0 0 1-.4 .5 .64 .64 0 0 1-.1-1z" fill="#4472c4"/>
<path d="M144.4 202.9l.1-.1a.64 .64 0 0 1 .4 .6 .64 .64 0 0 1-.4 .5 .64 .64 0 0 1-.1-1z" fill="none" stroke="#4472c4" stroke-width=".26"/>
<path d="M145.2 202.9l.2-.1a.59 .59 0 0 1 .4 .6 .59 .59 0 0 1-.4 .5 .64 .64 0 0 1-.2-1z" fill="#4472c4"/>
<path d="M145.2 202.9l.2-.1a.59 .59 0 0 1 .4 .6 .59 .59 0 0 1-.4 .5 .64 .64 0 0 1-.2-1z" fill="none" stroke="#4472c4" stroke-width=".26"/>
<path d="M146.1 202.9l.2-.1a.59 .59 0 0 1 .4 .6 .59 .59 0 0 1-.4 .5 .64 .64 0 0 1-.2-1z" fill="#4472c4"/>
<path d="M146.1 202.9l.2-.1a.59 .59 0 0 1 .4 .6 .59 .59 0 0 1-.4 .5 .64 .64 0 0 1-.2-1z" fill="none" stroke="#4472c4" stroke-width=".26"/>
<path d="M146.9 202.9l.2-.1a.59 .59 0 0 1 .4 .6 .59 .59 0 0 1-.4 .5 .64 .64 0 0 1-.2-1z" fill="#4472c4"/>
<path d="M146.9 202.9l.2-.1a.59 .59 0 0 1 .4 .6 .59 .59 0 0 1-.4 .5 .64 .64 0 0 1-.2-1z" fill="none" stroke="#4472c4" stroke-width=".26"/>
<path d="M147.8 202.9l.2-.1a.59 .59 0 0 1 .4 .6 .59 .59 0 0 1-.4 .5 .64 .64 0 0 1-.2-1z" fill="#4472c4"/>
<path d="M147.8 202.9l.2-.1a.59 .59 0 0 1 .4 .6 .59 .59 0 0 1-.4 .5 .64 .64 0 0 1-.2-1z" fill="none" stroke="#4472c4" stroke-width=".26"/>
<path d="M148.7 202.9l.2-.1a.64 .64 0 0 1 .4 .6 .64 .64 0 0 1-.4 .5 .6 .6 0 0 1-.4-.4 .6 .6 0 0 1 .2-.6z" fill="#4472c4"/>
<path d="M148.7 202.9l.2-.1a.64 .64 0 0 1 .4 .6 .64 .64 0 0 1-.4 .5 .6 .6 0 0 1-.4-.4 .6 .6 0 0 1 .2-.6z" fill="none" stroke="#4472c4" stroke-width=".26"/>
<path d="M149.6 202.7l.2-.1a.64 .64 0 0 1 .4 .6 .64 .64 0 0 1-.4 .6 .64 .64 0 0 1-.2-1.1z" fill="#4472c4"/>
<path d="M149.6 202.7l.2-.1a.64 .64 0 0 1 .4 .6 .64 .64 0 0 1-.4 .6 .64 .64 0 0 1-.2-1.1z" fill="none" stroke="#4472c4" stroke-width=".26"/>
<path d="M150.5 199.9l.2-.1a.59 .59 0 0 1 .4 .6 .59 .59 0 0 1-.4 .5 .64 .64 0 0 1-.2-1z" fill="#4472c4"/>
<path d="M150.5 199.9l.2-.1a.59 .59 0 0 1 .4 .6 .59 .59 0 0 1-.4 .5 .64 .64 0 0 1-.2-1z" fill="none" stroke="#4472c4" stroke-width=".26"/>
<path d="M151.4 196.9l.2-.1a.59 .59 0 0 1 .4 .6 .59 .59 0 0 1-.4 .5 .64 .64 0 0 1-.2-1z" fill="#4472c4"/>
<path d="M151.4 196.9l.2-.1a.59 .59 0 0 1 .4 .6 .59 .59 0 0 1-.4 .5 .64 .64 0 0 1-.2-1z" fill="none" stroke="#4472c4" stroke-width=".26"/>
<path d="M152.3 194.7l.2-.1a.64 .64 0 0 1 .4 .6 .64 .64 0 0 1-.4 .5 .61 .61 0 0 1-.4-.4 .61 .61 0 0 1 .2-.6z" fill="#4472c4"/>
<path d="M152.3 194.7l.2-.1a.64 .64 0 0 1 .4 .6 .64 .64 0 0 1-.4 .5 .61 .61 0 0 1-.4-.4 .61 .61 0 0 1 .2-.6z" fill="none" stroke="#4472c4" stroke-width=".26"/>
<path d="M153.2 192.4l.2-.1a.64 .64 0 0 1 .4 .6 .64 .64 0 0 1-.4 .5 .6 .6 0 0 1-.4-.4 .6 .6 0 0 1 .2-.6z" fill="#4472c4"/>
<path d="M153.2 192.4l.2-.1a.64 .64 0 0 1 .4 .6 .64 .64 0 0 1-.4 .5 .6 .6 0 0 1-.4-.4 .6 .6 0 0 1 .2-.6z" fill="none" stroke="#4472c4" stroke-width=".26"/>
<path d="M154.1 190.2l.2-.1a.64 .64 0 0 1 .4 .6 .64 .64 0 0 1-.4 .5 .66 .66 0 0 1-.2-1z" fill="#4472c4"/>
<path d="M154.1 190.2l.2-.1a.64 .64 0 0 1 .4 .6 .64 .64 0 0 1-.4 .5 .66 .66 0 0 1-.2-1z" fill="none" stroke="#4472c4" stroke-width=".26"/>
<path d="M155 187.9l.2-.1a.59 .59 0 0 1 .4 .6 .59 .59 0 0 1-.4 .5 .64 .64 0 0 1-.2-1z" fill="#4472c4"/>
<path d="M155 187.9l.2-.1a.59 .59 0 0 1 .4 .6 .59 .59 0 0 1-.4 .5 .64 .64 0 0 1-.2-1z" fill="none" stroke="#4472c4" stroke-width=".26"/>
<path d="M155.9 185.7l.2-.1a.54 .54 0 0 1 .4 .6 .54 .54 0 0 1-.6 .5 .75 .75 0 0 1 0-1z" fill="#4472c4"/>
<path d="M155.9 185.7l.2-.1a.54 .54 0 0 1 .4 .6 .54 .54 0 0 1-.6 .5 .75 .75 0 0 1 0-1z" fill="none" stroke="#4472c4" stroke-width=".26"/>
<path d="M156.8 183.6l.2-.1a.64 .64 0 0 1 .4 .6 .64 .64 0 0 1-.4 .5 .6 .6 0 0 1-.4-.4 .6 .6 0 0 1 .2-.6z" fill="#4472c4"/>
<path d="M156.8 183.6l.2-.1a.64 .64 0 0 1 .4 .6 .64 .64 0 0 1-.4 .5 .6 .6 0 0 1-.4-.4 .6 .6 0 0 1 .2-.6z" fill="none" stroke="#4472c4" stroke-width=".26"/>
<path d="M157.7 181.5l.2-.1a.64 .64 0 0 1 .4 .6 .64 .64 0 0 1-.4 .6 .66 .66 0 0 1-.2-1.1z" fill="#4472c4"/>
<path d="M157.7 181.5l.2-.1a.64 .64 0 0 1 .4 .6 .64 .64 0 0 1-.4 .6 .66 .66 0 0 1-.2-1.1z" fill="none" stroke="#4472c4" stroke-width=".26"/>
<path d="M158.6 179.5a.49 .49 0 0 1 .6 .4 .49 .49 0 0 1-.6 .5 .7 .7 0 0 1 0-.9z" fill="#4472c4"/>
<path d="M158.6 179.5a.49 .49 0 0 1 .6 .4 .49 .49 0 0 1-.6 .5 .7 .7 0 0 1 0-.9z" fill="none" stroke="#4472c4" stroke-width=".26"/>
<path d="M159.5 177.7h.2a.59 .59 0 0 1 .4 .5 .59 .59 0 0 1-.4 .6 .64 .64 0 0 1-.2-1.1z" fill="#4472c4"/>
<path d="M159.5 177.7h.2a.59 .59 0 0 1 .4 .5 .59 .59 0 0 1-.4 .6 .64 .64 0 0 1-.2-1.1z" fill="none" stroke="#4472c4" stroke-width=".26"/>
<path d="M160.4 176.2h.2a.64 .64 0 0 1 .4 .5 .64 .64 0 0 1-.4 .6 .6 .6 0 0 1-.4-.5 .6 .6 0 0 1 .2-.6z" fill="#4472c4"/>
<path d="M160.4 176.2h.2a.64 .64 0 0 1 .4 .5 .64 .64 0 0 1-.4 .6 .6 .6 0 0 1-.4-.5 .6 .6 0 0 1 .2-.6z" fill="none" stroke="#4472c4" stroke-width=".26"/>
<path d="M161.3 175.4l.2-.1a.64 .64 0 0 1 .4 .5 .64 .64 0 0 1-.4 .6 .61 .61 0 0 1-.4-.4 .61 .61 0 0 1 .2-.6z" fill="#4472c4"/>
<path d="M161.3 175.4l.2-.1a.64 .64 0 0 1 .4 .5 .64 .64 0 0 1-.4 .6 .61 .61 0 0 1-.4-.4 .61 .61 0 0 1 .2-.6z" fill="none" stroke="#4472c4" stroke-width=".26"/>
<path d="M162.2 174.4l.2-.1a.64 .64 0 0 1 .4 .6 .64 .64 0 0 1-.4 .5 .64 .64 0 0 1-.2-1z" fill="#4472c4"/>
<path d="M162.2 174.4l.2-.1a.64 .64 0 0 1 .4 .6 .64 .64 0 0 1-.4 .5 .64 .64 0 0 1-.2-1z" fill="none" stroke="#4472c4" stroke-width=".26"/>
<path d="M163.1 173.9l.2-.1a.54 .54 0 0 1 .4 .6 .54 .54 0 0 1-.6 .4 .75 .75 0 0 1 0-.9z" fill="#4472c4"/>
<path d="M163.1 173.9l.2-.1a.54 .54 0 0 1 .4 .6 .54 .54 0 0 1-.6 .4 .75 .75 0 0 1 0-.9z" fill="none" stroke="#4472c4" stroke-width=".26"/>
<path d="M164 173.2h.3a.64 .64 0 0 1 .3 .5 .64 .64 0 0 1-.3 .6 .6 .6 0 0 1-.5-.5 .6 .6 0 0 1 .2-.6z" fill="#4472c4"/>
<path d="M164 173.2h.3a.64 .64 0 0 1 .3 .5 .64 .64 0 0 1-.3 .6 .6 .6 0 0 1-.5-.5 .6 .6 0 0 1 .2-.6z" fill="none" stroke="#4472c4" stroke-width=".26"/>
<path d="M164.8 172.9l.2-.1a.59 .59 0 0 1 .4 .6 .59 .59 0 0 1-.4 .6 .64 .64 0 0 1-.2-1.1z" fill="#4472c4"/>
<path d="M164.8 172.9l.2-.1a.59 .59 0 0 1 .4 .6 .59 .59 0 0 1-.4 .6 .64 .64 0 0 1-.2-1.1z" fill="none" stroke="#4472c4" stroke-width=".26"/>
<path d="M165.7 172.5h.1a.54 .54 0 0 1 .5 .6 .54 .54 0 0 1-.6 .4 .75 .75 0 0 1 0-1z" fill="#4472c4"/>
<path d="M165.7 172.5h.1a.54 .54 0 0 1 .5 .6 .54 .54 0 0 1-.6 .4 .75 .75 0 0 1 0-1z" fill="none" stroke="#4472c4" stroke-width=".26"/>
<path d="M166.6 172.4l.2-.1a.64 .64 0 0 1 .4 .5 .64 .64 0 0 1-.4 .6 .61 .61 0 0 1-.4-.4 .61 .61 0 0 1 .2-.6z" fill="#4472c4"/>
<path d="M166.6 172.4l.2-.1a.64 .64 0 0 1 .4 .5 .64 .64 0 0 1-.4 .6 .61 .61 0 0 1-.4-.4 .61 .61 0 0 1 .2-.6z" fill="none" stroke="#4472c4" stroke-width=".26"/>
<path d="M167.5 172.2l.2-.1a.51 .51 0 0 1 .3 .6 .51 .51 0 0 1-.5 .4 .67 .67 0 0 1 0-.9z" fill="#4472c4"/>
<path d="M167.5 172.2l.2-.1a.51 .51 0 0 1 .3 .6 .51 .51 0 0 1-.5 .4 .67 .67 0 0 1 0-.9z" fill="none" stroke="#4472c4" stroke-width=".26"/>
<path d="M168.4 172h.4a.57 .57 0 0 1 .2 .6 .57 .57 0 0 1-.4 .4 .6 .6 0 0 1-.2-1z" fill="#4472c4"/>
<path d="M168.4 172h.4a.57 .57 0 0 1 .2 .6 .57 .57 0 0 1-.4 .4 .6 .6 0 0 1-.2-1z" fill="none" stroke="#4472c4" stroke-width=".26"/>
<path d="M169.3 171.7h.2a.59 .59 0 0 1 .4 .5 .59 .59 0 0 1-.4 .6 .64 .64 0 0 1-.2-1.1z" fill="#4472c4"/>
<path d="M169.3 171.7h.2a.59 .59 0 0 1 .4 .5 .59 .59 0 0 1-.4 .6 .64 .64 0 0 1-.2-1.1z" fill="none" stroke="#4472c4" stroke-width=".26"/>
<path d="M170.2 171.7h.2a.64 .64 0 0 1 .4 .5 .64 .64 0 0 1-.4 .6 .6 .6 0 0 1-.4-.5 .6 .6 0 0 1 .2-.6z" fill="#4472c4"/>
<path d="M170.2 171.7h.2a.64 .64 0 0 1 .4 .5 .64 .64 0 0 1-.4 .6 .6 .6 0 0 1-.4-.5 .6 .6 0 0 1 .2-.6z" fill="none" stroke="#4472c4" stroke-width=".26"/>
<path d="M171.1 171.6l.2-.1a.64 .64 0 0 1 .4 .6 .64 .64 0 0 1-.4 .5 .6 .6 0 0 1-.5-.4 .6 .6 0 0 1 .3-.6z" fill="#4472c4"/>
<path d="M171.1 171.6l.2-.1a.64 .64 0 0 1 .4 .6 .64 .64 0 0 1-.4 .5 .6 .6 0 0 1-.5-.4 .6 .6 0 0 1 .3-.6z" fill="none" stroke="#4472c4" stroke-width=".26"/>
<path d="M172 171.6l.2-.1a.64 .64 0 0 1 .3 .6 .64 .64 0 0 1-.3 .5 .64 .64 0 0 1-.2-1z" fill="#4472c4"/>
<path d="M172 171.6l.2-.1a.64 .64 0 0 1 .3 .6 .64 .64 0 0 1-.3 .5 .64 .64 0 0 1-.2-1z" fill="none" stroke="#4472c4" stroke-width=".26"/>
<path d="M172.9 171.4l.2-.1a.59 .59 0 0 1 .4 .6 .59 .59 0 0 1-.4 .6 .64 .64 0 0 1-.2-1.1z" fill="#4472c4"/>
<path d="M172.9 171.4l.2-.1a.59 .59 0 0 1 .4 .6 .59 .59 0 0 1-.4 .6 .64 .64 0 0 1-.2-1.1z" fill="none" stroke="#4472c4" stroke-width=".26"/>
<path d="M173.8 171.4l.1-.1a.59 .59 0 0 1 .5 .6 .59 .59 0 0 1-.5 .6 .64 .64 0 0 1-.1-1.1z" fill="#4472c4"/>
<path d="M173.8 171.4l.1-.1a.59 .59 0 0 1 .5 .6 .59 .59 0 0 1-.5 .6 .64 .64 0 0 1-.1-1.1z" fill="none" stroke="#4472c4" stroke-width=".26"/>
<path d="M174.7 171.4l.2-.1a.64 .64 0 0 1 .4 .6 .64 .64 0 0 1-.4 .6 .6 .6 0 0 1-.4-.5 .6 .6 0 0 1 .2-.6z" fill="#4472c4"/>
<path d="M174.7 171.4l.2-.1a.64 .64 0 0 1 .4 .6 .64 .64 0 0 1-.4 .6 .6 .6 0 0 1-.4-.5 .6 .6 0 0 1 .2-.6z" fill="none" stroke="#4472c4" stroke-width=".26"/>
<path d="M175.6 171.4l.2-.1a.64 .64 0 0 1 .4 .6 .64 .64 0 0 1-.4 .5 .64 .64 0 0 1-.2-1z" fill="#4472c4"/>
<path d="M175.6 171.4l.2-.1a.64 .64 0 0 1 .4 .6 .64 .64 0 0 1-.4 .5 .64 .64 0 0 1-.2-1z" fill="none" stroke="#4472c4" stroke-width=".26"/>
<path d="M176.5 171.4l.2-.1a.59 .59 0 0 1 .4 .6 .59 .59 0 0 1-.4 .5 .64 .64 0 0 1-.2-1z" fill="#4472c4"/>
<path d="M176.5 171.4l.2-.1a.59 .59 0 0 1 .4 .6 .59 .59 0 0 1-.4 .5 .64 .64 0 0 1-.2-1z" fill="none" stroke="#4472c4" stroke-width=".26"/>
<path d="M177.4 171.2l.2-.1a.54 .54 0 0 1 .4 .6 .54 .54 0 0 1-.6 .5 .75 .75 0 0 1 0-1z" fill="#4472c4"/>
<path d="M177.4 171.2l.2-.1a.54 .54 0 0 1 .4 .6 .54 .54 0 0 1-.6 .5 .75 .75 0 0 1 0-1z" fill="none" stroke="#4472c4" stroke-width=".26"/>
<path d="M178.3 171.2l.2-.1a.64 .64 0 0 1 .4 .6 .64 .64 0 0 1-.4 .6 .61 .61 0 0 1-.4-.5 .61 .61 0 0 1 .2-.6z" fill="#4472c4"/>
<path d="M178.3 171.2l.2-.1a.64 .64 0 0 1 .4 .6 .64 .64 0 0 1-.4 .6 .61 .61 0 0 1-.4-.5 .61 .61 0 0 1 .2-.6z" fill="none" stroke="#4472c4" stroke-width=".26"/>
<path d="M179.2 171.2l.2-.1a.64 .64 0 0 1 .4 .6 .64 .64 0 0 1-.4 .6 .61 .61 0 0 1-.4-.5 .61 .61 0 0 1 .2-.6z" fill="#4472c4"/>
<path d="M179.2 171.2l.2-.1a.64 .64 0 0 1 .4 .6 .64 .64 0 0 1-.4 .6 .61 .61 0 0 1-.4-.5 .61 .61 0 0 1 .2-.6z" fill="none" stroke="#4472c4" stroke-width=".26"/>
<path d="M180.1 171.2l.2-.1a.64 .64 0 0 1 .3 .6 .64 .64 0 0 1-.3 .6 .66 .66 0 0 1-.2-1.1z" fill="#4472c4"/>
<path d="M180.1 171.2l.2-.1a.64 .64 0 0 1 .3 .6 .64 .64 0 0 1-.3 .6 .66 .66 0 0 1-.2-1.1z" fill="none" stroke="#4472c4" stroke-width=".26"/>
<path d="M181 171.2l.2-.1a.54 .54 0 0 1 .4 .6 .54 .54 0 0 1-.6 .5 .75 .75 0 0 1 0-1z" fill="#4472c4"/>
<path d="M181 171.2l.2-.1a.54 .54 0 0 1 .4 .6 .54 .54 0 0 1-.6 .5 .75 .75 0 0 1 0-1z" fill="none" stroke="#4472c4" stroke-width=".26"/>
<path d="M181.9 171.2l.2-.1a.64 .64 0 0 1 .4 .6 .64 .64 0 0 1-.4 .6 .61 .61 0 0 1-.4-.5 .61 .61 0 0 1 .2-.6z" fill="#4472c4"/>
<path d="M181.9 171.2l.2-.1a.64 .64 0 0 1 .4 .6 .64 .64 0 0 1-.4 .6 .61 .61 0 0 1-.4-.5 .61 .61 0 0 1 .2-.6z" fill="none" stroke="#4472c4" stroke-width=".26"/>
<path d="M182.7 171.2l.1-.1a.54 .54 0 0 1 .5 .6 .54 .54 0 0 1-.6 .5 .75 .75 0 0 1 0-1z" fill="#4472c4"/>
<path d="M182.7 171.2l.1-.1a.54 .54 0 0 1 .5 .6 .54 .54 0 0 1-.6 .5 .75 .75 0 0 1 0-1z" fill="none" stroke="#4472c4" stroke-width=".26"/>
<path d="M183.6 171.2l.1-.1a.54 .54 0 0 1 .5 .6 .54 .54 0 0 1-.6 .5 .75 .75 0 0 1 0-1z" fill="#4472c4"/>
<path d="M183.6 171.2l.1-.1a.54 .54 0 0 1 .5 .6 .54 .54 0 0 1-.6 .5 .75 .75 0 0 1 0-1z" fill="none" stroke="#4472c4" stroke-width=".26"/>
<path d="M184.5 171.2l.2-.1a.64 .64 0 0 1 .3 .6 .64 .64 0 0 1-.3 .6 .61 .61 0 0 1-.5-.5 .61 .61 0 0 1 .3-.6z" fill="#4472c4"/>
<path d="M184.5 171.2l.2-.1a.64 .64 0 0 1 .3 .6 .64 .64 0 0 1-.3 .6 .61 .61 0 0 1-.5-.5 .61 .61 0 0 1 .3-.6z" fill="none" stroke="#4472c4" stroke-width=".26"/>
<path d="M185.4 171.2l.2-.1a.64 .64 0 0 1 .3 .6 .64 .64 0 0 1-.3 .6 .66 .66 0 0 1-.2-1.1z" fill="#4472c4"/>
<path d="M185.4 171.2l.2-.1a.64 .64 0 0 1 .3 .6 .64 .64 0 0 1-.3 .6 .66 .66 0 0 1-.2-1.1z" fill="none" stroke="#4472c4" stroke-width=".26"/>
<path d="M186.3 171.2l.2-.1a.54 .54 0 0 1 .4 .6 .54 .54 0 0 1-.6 .5 .75 .75 0 0 1 0-1z" fill="#4472c4"/>
<path d="M186.3 171.2l.2-.1a.54 .54 0 0 1 .4 .6 .54 .54 0 0 1-.6 .5 .75 .75 0 0 1 0-1z" fill="none" stroke="#4472c4" stroke-width=".26"/>
<path d="M187.2 171.2l.1-.1a.54 .54 0 0 1 .5 .6 .54 .54 0 0 1-.6 .5 .75 .75 0 0 1 0-1z" fill="#4472c4"/>
<path d="M187.2 171.2l.1-.1a.54 .54 0 0 1 .5 .6 .54 .54 0 0 1-.6 .5 .75 .75 0 0 1 0-1z" fill="none" stroke="#4472c4" stroke-width=".26"/>
<path d="M188.1 171.2l.2-.1a.64 .64 0 0 1 .4 .6 .64 .64 0 0 1-.4 .6 .61 .61 0 0 1-.4-.5 .61 .61 0 0 1 .2-.6z" fill="#4472c4"/>
<path d="M188.1 171.2l.2-.1a.64 .64 0 0 1 .4 .6 .64 .64 0 0 1-.4 .6 .61 .61 0 0 1-.4-.5 .61 .61 0 0 1 .2-.6z" fill="none" stroke="#4472c4" stroke-width=".26"/>
<path d="M189 171.2l.2-.1a.64 .64 0 0 1 .3 .6 .64 .64 0 0 1-.3 .6 .61 .61 0 0 1-.5-.5 .61 .61 0 0 1 .3-.6z" fill="#4472c4"/>
<path d="M189 171.2l.2-.1a.64 .64 0 0 1 .3 .6 .64 .64 0 0 1-.3 .6 .61 .61 0 0 1-.5-.5 .61 .61 0 0 1 .3-.6z" fill="none" stroke="#4472c4" stroke-width=".26"/>
<path d="M189.9 171.2l.2-.1a.64 .64 0 0 1 .3 .6 .64 .64 0 0 1-.3 .6 .66 .66 0 0 1-.2-1.1z" fill="#4472c4"/>
<path d="M189.9 171.2l.2-.1a.64 .64 0 0 1 .3 .6 .64 .64 0 0 1-.3 .6 .66 .66 0 0 1-.2-1.1z" fill="none" stroke="#4472c4" stroke-width=".26"/>
<path d="M190.8 171.2l.1-.1a.54 .54 0 0 1 .5 .6 .54 .54 0 0 1-.6 .5 .75 .75 0 0 1 0-1z" fill="#4472c4"/>
<path d="M190.8 171.2l.1-.1a.54 .54 0 0 1 .5 .6 .54 .54 0 0 1-.6 .5 .75 .75 0 0 1 0-1z" fill="none" stroke="#4472c4" stroke-width=".26"/>
<path d="M191.7 171.2l.1-.1a.54 .54 0 0 1 .5 .6 .54 .54 0 0 1-.6 .5 .75 .75 0 0 1 0-1z" fill="#4472c4"/>
<path d="M191.7 171.2l.1-.1a.54 .54 0 0 1 .5 .6 .54 .54 0 0 1-.6 .5 .75 .75 0 0 1 0-1z" fill="none" stroke="#4472c4" stroke-width=".26"/>
<path d="M192.6 171.2l.2-.1a.64 .64 0 0 1 .4 .6 .64 .64 0 0 1-.4 .6 .61 .61 0 0 1-.4-.5 .61 .61 0 0 1 .2-.6z" fill="#4472c4"/>
<path d="M192.6 171.2l.2-.1a.64 .64 0 0 1 .4 .6 .64 .64 0 0 1-.4 .6 .61 .61 0 0 1-.4-.5 .61 .61 0 0 1 .2-.6z" fill="none" stroke="#4472c4" stroke-width=".26"/>
<path d="M192.7 171.7l-17 .1-6.5 .5a12.2 12.2 0 0 0-7.8 3.2 27.2 27.2 0 0 0-4.5 8.4l-3.7 9.4a57.5 57.5 0 0 0-3.3 9.6 .9 .9 0 0 1-1.3 .6h-18.4" fill="none" stroke="#70ad47" stroke-width=".44"/>
<path d="M129.9 202.9l.2-.1a.59 .59 0 0 1 .4 .6 .59 .59 0 0 1-.4 .5 .64 .64 0 0 1-.2-1z" fill="#70ad47"/>
<path d="M129.9 202.9l.2-.1a.59 .59 0 0 1 .4 .6 .59 .59 0 0 1-.4 .5 .64 .64 0 0 1-.2-1z" fill="none" stroke="#70ad47" stroke-width=".26"/>
<path d="M130.8 202.9l.2-.1a.64 .64 0 0 1 .4 .6 .64 .64 0 0 1-.4 .5 .6 .6 0 0 1-.4-.4 .6 .6 0 0 1 .2-.6z" fill="#70ad47"/>
<path d="M130.8 202.9l.2-.1a.64 .64 0 0 1 .4 .6 .64 .64 0 0 1-.4 .5 .6 .6 0 0 1-.4-.4 .6 .6 0 0 1 .2-.6z" fill="none" stroke="#70ad47" stroke-width=".26"/>
<path d="M131.8 202.9l.1-.1a.64 .64 0 0 1 .4 .6 .64 .64 0 0 1-.4 .5 .64 .64 0 0 1-.1-1z" fill="#70ad47"/>
<path d="M131.8 202.9l.1-.1a.64 .64 0 0 1 .4 .6 .64 .64 0 0 1-.4 .5 .64 .64 0 0 1-.1-1z" fill="none" stroke="#70ad47" stroke-width=".26"/>
<path d="M132.6 202.9l.2-.1a.59 .59 0 0 1 .4 .6 .59 .59 0 0 1-.4 .5 .64 .64 0 0 1-.2-1z" fill="#70ad47"/>
<path d="M132.6 202.9l.2-.1a.59 .59 0 0 1 .4 .6 .59 .59 0 0 1-.4 .5 .64 .64 0 0 1-.2-1z" fill="none" stroke="#70ad47" stroke-width=".26"/>
<path d="M133.5 202.9l.2-.1a.59 .59 0 0 1 .4 .6 .59 .59 0 0 1-.4 .5 .64 .64 0 0 1-.2-1z" fill="#70ad47"/>
<path d="M133.5 202.9l.2-.1a.59 .59 0 0 1 .4 .6 .59 .59 0 0 1-.4 .5 .64 .64 0 0 1-.2-1z" fill="none" stroke="#70ad47" stroke-width=".26"/>
<path d="M134.4 202.9l.3-.1a.64 .64 0 0 1 .3 .6 .64 .64 0 0 1-.3 .5 .6 .6 0 0 1-.5-.4 .6 .6 0 0 1 .2-.6z" fill="#70ad47"/>
<path d="M134.4 202.9l.3-.1a.64 .64 0 0 1 .3 .6 .64 .64 0 0 1-.3 .5 .6 .6 0 0 1-.5-.4 .6 .6 0 0 1 .2-.6z" fill="none" stroke="#70ad47" stroke-width=".26"/>
<path d="M135.3 202.9l.2-.1a.64 .64 0 0 1 .4 .6 .64 .64 0 0 1-.4 .5 .6 .6 0 0 1-.4-.4 .6 .6 0 0 1 .2-.6z" fill="#70ad47"/>
<path d="M135.3 202.9l.2-.1a.64 .64 0 0 1 .4 .6 .64 .64 0 0 1-.4 .5 .6 .6 0 0 1-.4-.4 .6 .6 0 0 1 .2-.6z" fill="none" stroke="#70ad47" stroke-width=".26"/>
<path d="M136.2 202.9l.2-.1a.64 .64 0 0 1 .4 .6 .64 .64 0 0 1-.4 .5 .64 .64 0 0 1-.2-1z" fill="#70ad47"/>
<path d="M136.2 202.9l.2-.1a.64 .64 0 0 1 .4 .6 .64 .64 0 0 1-.4 .5 .64 .64 0 0 1-.2-1z" fill="none" stroke="#70ad47" stroke-width=".26"/>
<path d="M137.1 202.9l.2-.1a.59 .59 0 0 1 .4 .6 .59 .59 0 0 1-.4 .5 .64 .64 0 0 1-.2-1z" fill="#70ad47"/>
<path d="M137.1 202.9l.2-.1a.59 .59 0 0 1 .4 .6 .59 .59 0 0 1-.4 .5 .64 .64 0 0 1-.2-1z" fill="none" stroke="#70ad47" stroke-width=".26"/>
<path d="M138 202.9l.2-.1a.59 .59 0 0 1 .4 .6 .59 .59 0 0 1-.4 .5 .64 .64 0 0 1-.2-1z" fill="#70ad47"/>
<path d="M138 202.9l.2-.1a.59 .59 0 0 1 .4 .6 .59 .59 0 0 1-.4 .5 .64 .64 0 0 1-.2-1z" fill="none" stroke="#70ad47" stroke-width=".26"/>
<path d="M138.9 202.9l.3-.1a.64 .64 0 0 1 .3 .6 .64 .64 0 0 1-.3 .5 .6 .6 0 0 1-.5-.4 .6 .6 0 0 1 .2-.6z" fill="#70ad47"/>
<path d="M138.9 202.9l.3-.1a.64 .64 0 0 1 .3 .6 .64 .64 0 0 1-.3 .5 .6 .6 0 0 1-.5-.4 .6 .6 0 0 1 .2-.6z" fill="none" stroke="#70ad47" stroke-width=".26"/>
<path d="M139.9 202.9l.1-.1a.64 .64 0 0 1 .4 .6 .64 .64 0 0 1-.4 .5 .64 .64 0 0 1-.1-1z" fill="#70ad47"/>
<path d="M139.9 202.9l.1-.1a.64 .64 0 0 1 .4 .6 .64 .64 0 0 1-.4 .5 .64 .64 0 0 1-.1-1z" fill="none" stroke="#70ad47" stroke-width=".26"/>
<path d="M140.7 202.9l.2-.1a.59 .59 0 0 1 .5 .6 .59 .59 0 0 1-.5 .5 .64 .64 0 0 1-.2-1z" fill="#70ad47"/>
<path d="M140.7 202.9l.2-.1a.59 .59 0 0 1 .5 .6 .59 .59 0 0 1-.5 .5 .64 .64 0 0 1-.2-1z" fill="none" stroke="#70ad47" stroke-width=".26"/>
<path d="M141.6 202.9l.2-.1a.59 .59 0 0 1 .4 .6 .59 .59 0 0 1-.4 .5 .64 .64 0 0 1-.2-1z" fill="#70ad47"/>
<path d="M141.6 202.9l.2-.1a.59 .59 0 0 1 .4 .6 .59 .59 0 0 1-.4 .5 .64 .64 0 0 1-.2-1z" fill="none" stroke="#70ad47" stroke-width=".26"/>
<path d="M142.5 202.9l.3-.1a.64 .64 0 0 1 .3 .6 .64 .64 0 0 1-.3 .5 .6 .6 0 0 1-.5-.4 .6 .6 0 0 1 .2-.6z" fill="#70ad47"/>
<path d="M142.5 202.9l.3-.1a.64 .64 0 0 1 .3 .6 .64 .64 0 0 1-.3 .5 .6 .6 0 0 1-.5-.4 .6 .6 0 0 1 .2-.6z" fill="none" stroke="#70ad47" stroke-width=".26"/>
<path d="M143.4 202.9l.2-.1a.64 .64 0 0 1 .4 .6 .64 .64 0 0 1-.4 .5 .6 .6 0 0 1-.4-.4 .6 .6 0 0 1 .2-.6z" fill="#70ad47"/>
<path d="M143.4 202.9l.2-.1a.64 .64 0 0 1 .4 .6 .64 .64 0 0 1-.4 .5 .6 .6 0 0 1-.4-.4 .6 .6 0 0 1 .2-.6z" fill="none" stroke="#70ad47" stroke-width=".26"/>
<path d="M144.4 202.9l.1-.1a.64 .64 0 0 1 .4 .6 .64 .64 0 0 1-.4 .5 .64 .64 0 0 1-.1-1z" fill="#70ad47"/>
<path d="M144.4 202.9l.1-.1a.64 .64 0 0 1 .4 .6 .64 .64 0 0 1-.4 .5 .64 .64 0 0 1-.1-1z" fill="none" stroke="#70ad47" stroke-width=".26"/>
<path d="M145.2 202.9l.2-.1a.59 .59 0 0 1 .4 .6 .59 .59 0 0 1-.4 .5 .64 .64 0 0 1-.2-1z" fill="#70ad47"/>
<path d="M145.2 202.9l.2-.1a.59 .59 0 0 1 .4 .6 .59 .59 0 0 1-.4 .5 .64 .64 0 0 1-.2-1z" fill="none" stroke="#70ad47" stroke-width=".26"/>
<path d="M146.1 202.9l.2-.1a.59 .59 0 0 1 .4 .6 .59 .59 0 0 1-.4 .5 .64 .64 0 0 1-.2-1z" fill="#70ad47"/>
<path d="M146.1 202.9l.2-.1a.59 .59 0 0 1 .4 .6 .59 .59 0 0 1-.4 .5 .64 .64 0 0 1-.2-1z" fill="none" stroke="#70ad47" stroke-width=".26"/>
<path d="M146.9 202.9l.2-.1a.59 .59 0 0 1 .4 .6 .59 .59 0 0 1-.4 .5 .64 .64 0 0 1-.2-1z" fill="#70ad47"/>
<path d="M146.9 202.9l.2-.1a.59 .59 0 0 1 .4 .6 .59 .59 0 0 1-.4 .5 .64 .64 0 0 1-.2-1z" fill="none" stroke="#70ad47" stroke-width=".26"/>
<path d="M147.8 202.9l.2-.1a.59 .59 0 0 1 .4 .6 .59 .59 0 0 1-.4 .5 .64 .64 0 0 1-.2-1z" fill="#70ad47"/>
<path d="M147.8 202.9l.2-.1a.59 .59 0 0 1 .4 .6 .59 .59 0 0 1-.4 .5 .64 .64 0 0 1-.2-1z" fill="none" stroke="#70ad47" stroke-width=".26"/>
<path d="M148.7 202.9l.2-.1a.64 .64 0 0 1 .4 .6 .64 .64 0 0 1-.4 .5 .6 .6 0 0 1-.4-.4 .6 .6 0 0 1 .2-.6z" fill="#70ad47"/>
<path d="M148.7 202.9l.2-.1a.64 .64 0 0 1 .4 .6 .64 .64 0 0 1-.4 .5 .6 .6 0 0 1-.4-.4 .6 .6 0 0 1 .2-.6z" fill="none" stroke="#70ad47" stroke-width=".26"/>
<path d="M149.6 202.7l.2-.1a.64 .64 0 0 1 .4 .6 .64 .64 0 0 1-.4 .6 .64 .64 0 0 1-.2-1.1z" fill="#70ad47"/>
<path d="M149.6 202.7l.2-.1a.64 .64 0 0 1 .4 .6 .64 .64 0 0 1-.4 .6 .64 .64 0 0 1-.2-1.1z" fill="none" stroke="#70ad47" stroke-width=".26"/>
<path d="M150.5 199.9l.2-.1a.59 .59 0 0 1 .4 .6 .59 .59 0 0 1-.4 .5 .64 .64 0 0 1-.2-1z" fill="#70ad47"/>
<path d="M150.5 199.9l.2-.1a.59 .59 0 0 1 .4 .6 .59 .59 0 0 1-.4 .5 .64 .64 0 0 1-.2-1z" fill="none" stroke="#70ad47" stroke-width=".26"/>
<path d="M151.4 196.9l.2-.1a.59 .59 0 0 1 .4 .6 .59 .59 0 0 1-.4 .5 .64 .64 0 0 1-.2-1z" fill="#70ad47"/>
<path d="M151.4 196.9l.2-.1a.59 .59 0 0 1 .4 .6 .59 .59 0 0 1-.4 .5 .64 .64 0 0 1-.2-1z" fill="none" stroke="#70ad47" stroke-width=".26"/>
<path d="M152.3 194.7l.2-.1a.64 .64 0 0 1 .4 .6 .64 .64 0 0 1-.4 .5 .61 .61 0 0 1-.4-.4 .61 .61 0 0 1 .2-.6z" fill="#70ad47"/>
<path d="M152.3 194.7l.2-.1a.64 .64 0 0 1 .4 .6 .64 .64 0 0 1-.4 .5 .61 .61 0 0 1-.4-.4 .61 .61 0 0 1 .2-.6z" fill="none" stroke="#70ad47" stroke-width=".26"/>
<path d="M153.2 192.4l.2-.1a.64 .64 0 0 1 .4 .6 .64 .64 0 0 1-.4 .5 .6 .6 0 0 1-.4-.4 .6 .6 0 0 1 .2-.6z" fill="#70ad47"/>
<path d="M153.2 192.4l.2-.1a.64 .64 0 0 1 .4 .6 .64 .64 0 0 1-.4 .5 .6 .6 0 0 1-.4-.4 .6 .6 0 0 1 .2-.6z" fill="none" stroke="#70ad47" stroke-width=".26"/>
<path d="M154.1 190.2l.2-.1a.64 .64 0 0 1 .4 .6 .64 .64 0 0 1-.4 .5 .66 .66 0 0 1-.2-1z" fill="#70ad47"/>
<path d="M154.1 190.2l.2-.1a.64 .64 0 0 1 .4 .6 .64 .64 0 0 1-.4 .5 .66 .66 0 0 1-.2-1z" fill="none" stroke="#70ad47" stroke-width=".26"/>
<path d="M155 187.9l.2-.1a.59 .59 0 0 1 .4 .6 .59 .59 0 0 1-.4 .5 .64 .64 0 0 1-.2-1z" fill="#70ad47"/>
<path d="M155 187.9l.2-.1a.59 .59 0 0 1 .4 .6 .59 .59 0 0 1-.4 .5 .64 .64 0 0 1-.2-1z" fill="none" stroke="#70ad47" stroke-width=".26"/>
<path d="M155.9 185.7l.2-.1a.54 .54 0 0 1 .4 .6 .54 .54 0 0 1-.6 .5 .75 .75 0 0 1 0-1z" fill="#70ad47"/>
<path d="M155.9 185.7l.2-.1a.54 .54 0 0 1 .4 .6 .54 .54 0 0 1-.6 .5 .75 .75 0 0 1 0-1z" fill="none" stroke="#70ad47" stroke-width=".26"/>
<path d="M156.8 183.4l.2-.1a.64 .64 0 0 1 .4 .6 .64 .64 0 0 1-.4 .5 .6 .6 0 0 1-.4-.4 .6 .6 0 0 1 .2-.6z" fill="#70ad47"/>
<path d="M156.8 183.4l.2-.1a.64 .64 0 0 1 .4 .6 .64 .64 0 0 1-.4 .5 .6 .6 0 0 1-.4-.4 .6 .6 0 0 1 .2-.6z" fill="none" stroke="#70ad47" stroke-width=".26"/>
<path d="M157.7 181.2l.2-.1a.51 .51 0 0 1 .4 .6 .51 .51 0 0 1-.6 .4 .67 .67 0 0 1 0-.9z" fill="#70ad47"/>
<path d="M157.7 181.2l.2-.1a.51 .51 0 0 1 .4 .6 .51 .51 0 0 1-.6 .4 .67 .67 0 0 1 0-.9z" fill="none" stroke="#70ad47" stroke-width=".26"/>
<path d="M158.6 179.2h.2a.59 .59 0 0 1 .4 .5 .59 .59 0 0 1-.4 .6 .64 .64 0 0 1-.2-1.1z" fill="#70ad47"/>
<path d="M158.6 179.2h.2a.59 .59 0 0 1 .4 .5 .59 .59 0 0 1-.4 .6 .64 .64 0 0 1-.2-1.1z" fill="none" stroke="#70ad47" stroke-width=".26"/>
<path d="M159.5 177.4l.2-.1a.59 .59 0 0 1 .4 .6 .59 .59 0 0 1-.4 .5 .64 .64 0 0 1-.2-1z" fill="#70ad47"/>
<path d="M159.5 177.4l.2-.1a.59 .59 0 0 1 .4 .6 .59 .59 0 0 1-.4 .5 .64 .64 0 0 1-.2-1z" fill="none" stroke="#70ad47" stroke-width=".26"/>
<path d="M160.4 176.1l.2-.1a.64 .64 0 0 1 .4 .5 .64 .64 0 0 1-.4 .6 .6 .6 0 0 1-.4-.4 .6 .6 0 0 1 .2-.6z" fill="#70ad47"/>
<path d="M160.4 176.1l.2-.1a.64 .64 0 0 1 .4 .5 .64 .64 0 0 1-.4 .6 .6 .6 0 0 1-.4-.4 .6 .6 0 0 1 .2-.6z" fill="none" stroke="#70ad47" stroke-width=".26"/>
<path d="M161.3 175l.2-.1a.5 .5 0 0 1 .4 .6 .5 .5 0 0 1-.6 .4 .61 .61 0 0 1 0-.9z" fill="#70ad47"/>
<path d="M161.3 175l.2-.1a.5 .5 0 0 1 .4 .6 .5 .5 0 0 1-.6 .4 .61 .61 0 0 1 0-.9z" fill="none" stroke="#70ad47" stroke-width=".26"/>
<path d="M162.2 174.2l.2-.1a.64 .64 0 0 1 .4 .6 .64 .64 0 0 1-.4 .6 .66 .66 0 0 1-.2-1.1z" fill="#70ad47"/>
<path d="M162.2 174.2l.2-.1a.64 .64 0 0 1 .4 .6 .64 .64 0 0 1-.4 .6 .66 .66 0 0 1-.2-1.1z" fill="none" stroke="#70ad47" stroke-width=".26"/>
<path d="M163.1 173.7l.2-.1a.51 .51 0 0 1 .4 .6 .51 .51 0 0 1-.6 .4 .67 .67 0 0 1 0-.9z" fill="#70ad47"/>
<path d="M163.1 173.7l.2-.1a.51 .51 0 0 1 .4 .6 .51 .51 0 0 1-.6 .4 .67 .67 0 0 1 0-.9z" fill="none" stroke="#70ad47" stroke-width=".26"/>
<path d="M164 173.1l.3-.1a.64 .64 0 0 1 .3 .6 .64 .64 0 0 1-.3 .5 .6 .6 0 0 1-.5-.4 .6 .6 0 0 1 .2-.6z" fill="#70ad47"/>
<path d="M164 173.1l.3-.1a.64 .64 0 0 1 .3 .6 .64 .64 0 0 1-.3 .5 .6 .6 0 0 1-.5-.4 .6 .6 0 0 1 .2-.6z" fill="none" stroke="#70ad47" stroke-width=".26"/>
<path d="M164.8 172.7l.2-.1a.54 .54 0 0 1 .4 .6 .54 .54 0 0 1-.6 .5 .75 .75 0 0 1 0-1z" fill="#70ad47"/>
<path d="M164.8 172.7l.2-.1a.54 .54 0 0 1 .4 .6 .54 .54 0 0 1-.6 .5 .75 .75 0 0 1 0-1z" fill="none" stroke="#70ad47" stroke-width=".26"/>
<path d="M165.7 172.5l.1-.1a.54 .54 0 0 1 .5 .7 .54 .54 0 0 1-.6 .4 .75 .75 0 0 1 0-1z" fill="#70ad47"/>
<path d="M165.7 172.5l.1-.1a.54 .54 0 0 1 .5 .7 .54 .54 0 0 1-.6 .4 .75 .75 0 0 1 0-1z" fill="none" stroke="#70ad47" stroke-width=".26"/>
<path d="M166.6 172.2l.2-.1a.52 .52 0 0 1 .4 .6 .52 .52 0 0 1-.6 .4 .61 .61 0 0 1 0-.9z" fill="#70ad47"/>
<path d="M166.6 172.2l.2-.1a.52 .52 0 0 1 .4 .6 .52 .52 0 0 1-.6 .4 .61 .61 0 0 1 0-.9z" fill="none" stroke="#70ad47" stroke-width=".26"/>
<path d="M167.5 172l.2-.1a.57 .57 0 0 1 .3 .5 .57 .57 0 0 1-.3 .6 .6 .6 0 0 1-.2-1z" fill="#70ad47"/>
<path d="M167.5 172l.2-.1a.57 .57 0 0 1 .3 .5 .57 .57 0 0 1-.3 .6 .6 .6 0 0 1-.2-1z" fill="none" stroke="#70ad47" stroke-width=".26"/>
<path d="M168.4 172h.4a.57 .57 0 0 1 .2 .5 .57 .57 0 0 1-.4 .5 .6 .6 0 0 1-.2-1z" fill="#70ad47"/>
<path d="M168.4 172h.4a.57 .57 0 0 1 .2 .5 .57 .57 0 0 1-.4 .5 .6 .6 0 0 1-.2-1z" fill="none" stroke="#70ad47" stroke-width=".26"/>
<path d="M169.3 171.7h.2a.59 .59 0 0 1 .4 .5 .59 .59 0 0 1-.4 .6 .64 .64 0 0 1-.2-1.1z" fill="#70ad47"/>
<path d="M169.3 171.7h.2a.59 .59 0 0 1 .4 .5 .59 .59 0 0 1-.4 .6 .64 .64 0 0 1-.2-1.1z" fill="none" stroke="#70ad47" stroke-width=".26"/>
<path d="M170.2 171.6l.2-.1a.64 .64 0 0 1 .4 .6 .64 .64 0 0 1-.4 .5 .6 .6 0 0 1-.4-.4 .6 .6 0 0 1 .2-.6z" fill="#70ad47"/>
<path d="M170.2 171.6l.2-.1a.64 .64 0 0 1 .4 .6 .64 .64 0 0 1-.4 .5 .6 .6 0 0 1-.4-.4 .6 .6 0 0 1 .2-.6z" fill="none" stroke="#70ad47" stroke-width=".26"/>
<path d="M171.1 171.6l.2-.1a.64 .64 0 0 1 .4 .6 .64 .64 0 0 1-.4 .5 .6 .6 0 0 1-.5-.4 .6 .6 0 0 1 .3-.6z" fill="#70ad47"/>
<path d="M171.1 171.6l.2-.1a.64 .64 0 0 1 .4 .6 .64 .64 0 0 1-.4 .5 .6 .6 0 0 1-.5-.4 .6 .6 0 0 1 .3-.6z" fill="none" stroke="#70ad47" stroke-width=".26"/>
<path d="M172 171.6l.2-.1a.64 .64 0 0 1 .3 .6 .64 .64 0 0 1-.3 .5 .64 .64 0 0 1-.2-1z" fill="#70ad47"/>
<path d="M172 171.6l.2-.1a.64 .64 0 0 1 .3 .6 .64 .64 0 0 1-.3 .5 .64 .64 0 0 1-.2-1z" fill="none" stroke="#70ad47" stroke-width=".26"/>
<path d="M172.9 171.4l.2-.1a.59 .59 0 0 1 .4 .6 .59 .59 0 0 1-.4 .5 .64 .64 0 0 1-.2-1z" fill="#70ad47"/>
<path d="M172.9 171.4l.2-.1a.59 .59 0 0 1 .4 .6 .59 .59 0 0 1-.4 .5 .64 .64 0 0 1-.2-1z" fill="none" stroke="#70ad47" stroke-width=".26"/>
<path d="M173.8 171.4l.1-.1a.59 .59 0 0 1 .5 .6 .59 .59 0 0 1-.5 .5 .64 .64 0 0 1-.1-1z" fill="#70ad47"/>
<path d="M173.8 171.4l.1-.1a.59 .59 0 0 1 .5 .6 .59 .59 0 0 1-.5 .5 .64 .64 0 0 1-.1-1z" fill="none" stroke="#70ad47" stroke-width=".26"/>
<path d="M174.7 171.4l.2-.1a.64 .64 0 0 1 .4 .6 .64 .64 0 0 1-.4 .5 .6 .6 0 0 1-.4-.4 .6 .6 0 0 1 .2-.6z" fill="#70ad47"/>
<path d="M174.7 171.4l.2-.1a.64 .64 0 0 1 .4 .6 .64 .64 0 0 1-.4 .5 .6 .6 0 0 1-.4-.4 .6 .6 0 0 1 .2-.6z" fill="none" stroke="#70ad47" stroke-width=".26"/>
<path d="M175.6 171.4l.2-.1a.64 .64 0 0 1 .4 .6 .64 .64 0 0 1-.4 .5 .64 .64 0 0 1-.2-1z" fill="#70ad47"/>
<path d="M175.6 171.4l.2-.1a.64 .64 0 0 1 .4 .6 .64 .64 0 0 1-.4 .5 .64 .64 0 0 1-.2-1z" fill="none" stroke="#70ad47" stroke-width=".26"/>
<path d="M176.5 171.4l.2-.1a.59 .59 0 0 1 .4 .6 .59 .59 0 0 1-.4 .5 .64 .64 0 0 1-.2-1z" fill="#70ad47"/>
<path d="M176.5 171.4l.2-.1a.59 .59 0 0 1 .4 .6 .59 .59 0 0 1-.4 .5 .64 .64 0 0 1-.2-1z" fill="none" stroke="#70ad47" stroke-width=".26"/>
<path d="M177.4 171.2l.2-.1a.54 .54 0 0 1 .4 .6 .54 .54 0 0 1-.6 .5 .75 .75 0 0 1 0-1z" fill="#70ad47"/>
<path d="M177.4 171.2l.2-.1a.54 .54 0 0 1 .4 .6 .54 .54 0 0 1-.6 .5 .75 .75 0 0 1 0-1z" fill="none" stroke="#70ad47" stroke-width=".26"/>
<path d="M178.3 171.2l.2-.1a.64 .64 0 0 1 .4 .6 .64 .64 0 0 1-.4 .6 .61 .61 0 0 1-.4-.5 .61 .61 0 0 1 .2-.6z" fill="#70ad47"/>
<path d="M178.3 171.2l.2-.1a.64 .64 0 0 1 .4 .6 .64 .64 0 0 1-.4 .6 .61 .61 0 0 1-.4-.5 .61 .61 0 0 1 .2-.6z" fill="none" stroke="#70ad47" stroke-width=".26"/>
<path d="M179.2 171.2l.2-.1a.64 .64 0 0 1 .4 .6 .64 .64 0 0 1-.4 .6 .61 .61 0 0 1-.4-.5 .61 .61 0 0 1 .2-.6z" fill="#70ad47"/>
<path d="M179.2 171.2l.2-.1a.64 .64 0 0 1 .4 .6 .64 .64 0 0 1-.4 .6 .61 .61 0 0 1-.4-.5 .61 .61 0 0 1 .2-.6z" fill="none" stroke="#70ad47" stroke-width=".26"/>
<path d="M180.1 171.2l.2-.1a.64 .64 0 0 1 .3 .6 .64 .64 0 0 1-.3 .6 .66 .66 0 0 1-.2-1.1z" fill="#70ad47"/>
<path d="M180.1 171.2l.2-.1a.64 .64 0 0 1 .3 .6 .64 .64 0 0 1-.3 .6 .66 .66 0 0 1-.2-1.1z" fill="none" stroke="#70ad47" stroke-width=".26"/>
<path d="M181 171.2l.2-.1a.54 .54 0 0 1 .4 .6 .54 .54 0 0 1-.6 .5 .75 .75 0 0 1 0-1z" fill="#70ad47"/>
<path d="M181 171.2l.2-.1a.54 .54 0 0 1 .4 .6 .54 .54 0 0 1-.6 .5 .75 .75 0 0 1 0-1z" fill="none" stroke="#70ad47" stroke-width=".26"/>
<path d="M181.9 171.2l.2-.1a.64 .64 0 0 1 .4 .6 .64 .64 0 0 1-.4 .6 .61 .61 0 0 1-.4-.5 .61 .61 0 0 1 .2-.6z" fill="#70ad47"/>
<path d="M181.9 171.2l.2-.1a.64 .64 0 0 1 .4 .6 .64 .64 0 0 1-.4 .6 .61 .61 0 0 1-.4-.5 .61 .61 0 0 1 .2-.6z" fill="none" stroke="#70ad47" stroke-width=".26"/>
<path d="M182.7 171.2l.1-.1a.54 .54 0 0 1 .5 .6 .54 .54 0 0 1-.6 .5 .75 .75 0 0 1 0-1z" fill="#70ad47"/>
<path d="M182.7 171.2l.1-.1a.54 .54 0 0 1 .5 .6 .54 .54 0 0 1-.6 .5 .75 .75 0 0 1 0-1z" fill="none" stroke="#70ad47" stroke-width=".26"/>
<path d="M183.6 171.2l.1-.1a.54 .54 0 0 1 .5 .6 .54 .54 0 0 1-.6 .5 .75 .75 0 0 1 0-1z" fill="#70ad47"/>
<path d="M183.6 171.2l.1-.1a.54 .54 0 0 1 .5 .6 .54 .54 0 0 1-.6 .5 .75 .75 0 0 1 0-1z" fill="none" stroke="#70ad47" stroke-width=".26"/>
<path d="M184.5 171.2l.2-.1a.64 .64 0 0 1 .3 .6 .64 .64 0 0 1-.3 .6 .61 .61 0 0 1-.5-.5 .61 .61 0 0 1 .3-.6z" fill="#70ad47"/>
<path d="M184.5 171.2l.2-.1a.64 .64 0 0 1 .3 .6 .64 .64 0 0 1-.3 .6 .61 .61 0 0 1-.5-.5 .61 .61 0 0 1 .3-.6z" fill="none" stroke="#70ad47" stroke-width=".26"/>
<path d="M185.4 171.2l.2-.1a.64 .64 0 0 1 .3 .6 .64 .64 0 0 1-.3 .6 .66 .66 0 0 1-.2-1.1z" fill="#70ad47"/>
<path d="M185.4 171.2l.2-.1a.64 .64 0 0 1 .3 .6 .64 .64 0 0 1-.3 .6 .66 .66 0 0 1-.2-1.1z" fill="none" stroke="#70ad47" stroke-width=".26"/>
<path d="M186.3 171.2l.2-.1a.54 .54 0 0 1 .4 .6 .54 .54 0 0 1-.6 .5 .75 .75 0 0 1 0-1z" fill="#70ad47"/>
<path d="M186.3 171.2l.2-.1a.54 .54 0 0 1 .4 .6 .54 .54 0 0 1-.6 .5 .75 .75 0 0 1 0-1z" fill="none" stroke="#70ad47" stroke-width=".26"/>
<path d="M187.2 171.2l.1-.1a.54 .54 0 0 1 .5 .6 .54 .54 0 0 1-.6 .5 .75 .75 0 0 1 0-1z" fill="#70ad47"/>
<path d="M187.2 171.2l.1-.1a.54 .54 0 0 1 .5 .6 .54 .54 0 0 1-.6 .5 .75 .75 0 0 1 0-1z" fill="none" stroke="#70ad47" stroke-width=".26"/>
<path d="M188.1 171.2l.2-.1a.64 .64 0 0 1 .4 .6 .64 .64 0 0 1-.4 .6 .61 .61 0 0 1-.4-.5 .61 .61 0 0 1 .2-.6z" fill="#70ad47"/>
<path d="M188.1 171.2l.2-.1a.64 .64 0 0 1 .4 .6 .64 .64 0 0 1-.4 .6 .61 .61 0 0 1-.4-.5 .61 .61 0 0 1 .2-.6z" fill="none" stroke="#70ad47" stroke-width=".26"/>
<path d="M189 171.2l.2-.1a.64 .64 0 0 1 .3 .6 .64 .64 0 0 1-.3 .6 .61 .61 0 0 1-.5-.5 .61 .61 0 0 1 .3-.6z" fill="#70ad47"/>
<path d="M189 171.2l.2-.1a.64 .64 0 0 1 .3 .6 .64 .64 0 0 1-.3 .6 .61 .61 0 0 1-.5-.5 .61 .61 0 0 1 .3-.6z" fill="none" stroke="#70ad47" stroke-width=".26"/>
<path d="M189.9 171.2l.2-.1a.64 .64 0 0 1 .3 .6 .64 .64 0 0 1-.3 .6 .66 .66 0 0 1-.2-1.1z" fill="#70ad47"/>
<path d="M189.9 171.2l.2-.1a.64 .64 0 0 1 .3 .6 .64 .64 0 0 1-.3 .6 .66 .66 0 0 1-.2-1.1z" fill="none" stroke="#70ad47" stroke-width=".26"/>
<path d="M190.8 171.2l.1-.1a.54 .54 0 0 1 .5 .6 .54 .54 0 0 1-.6 .5 .75 .75 0 0 1 0-1z" fill="#70ad47"/>
<path d="M190.8 171.2l.1-.1a.54 .54 0 0 1 .5 .6 .54 .54 0 0 1-.6 .5 .75 .75 0 0 1 0-1z" fill="none" stroke="#70ad47" stroke-width=".26"/>
<path d="M191.7 171.2l.1-.1a.54 .54 0 0 1 .5 .6 .54 .54 0 0 1-.6 .5 .75 .75 0 0 1 0-1z" fill="#70ad47"/>
<path d="M191.7 171.2l.1-.1a.54 .54 0 0 1 .5 .6 .54 .54 0 0 1-.6 .5 .75 .75 0 0 1 0-1z" fill="none" stroke="#70ad47" stroke-width=".26"/>
<path d="M192.6 171.2l.2-.1a.64 .64 0 0 1 .4 .6 .64 .64 0 0 1-.4 .6 .61 .61 0 0 1-.4-.5 .61 .61 0 0 1 .2-.6z" fill="#70ad47"/>
<path d="M192.6 171.2l.2-.1a.64 .64 0 0 1 .4 .6 .64 .64 0 0 1-.4 .6 .61 .61 0 0 1-.4-.5 .61 .61 0 0 1 .2-.6z" fill="none" stroke="#70ad47" stroke-width=".26"/>
<path d="M192.7 171.7l-16.4 .1-4.1 .2-3.6 .4a11.8 11.8 0 0 0-9 4.9l-.9 1.6-1.6 3.5-3.9 10.3a62.2 62.2 0 0 0-3.3 10.2l-.1 .3a.65 .65 0 0 1-.9 .3h-18.7" fill="none" stroke="#255e91" stroke-width=".44"/>
<path d="M192.7 171.7l-16.4 .1-5.1 .3-2 .3a11.5 11.5 0 0 0-8.9 4.7 60.5 60.5 0 0 0-4.2 9l-2.9 7.1a55.6 55.6 0 0 0-3.3 9.7 .69 .69 0 0 1-1 .6h-18.7" fill="none" stroke="#9e480e" stroke-width=".44"/>
<path d="M129.9 202.9l.2-.1a.59 .59 0 0 1 .4 .6 .59 .59 0 0 1-.4 .5 .64 .64 0 0 1-.2-1z" fill="#9e480e"/>
<path d="M129.9 202.9l.2-.1a.59 .59 0 0 1 .4 .6 .59 .59 0 0 1-.4 .5 .64 .64 0 0 1-.2-1z" fill="none" stroke="#9e480e" stroke-width=".26"/>
<path d="M130.8 202.9l.2-.1a.64 .64 0 0 1 .4 .6 .64 .64 0 0 1-.4 .5 .6 .6 0 0 1-.4-.4 .6 .6 0 0 1 .2-.6z" fill="#9e480e"/>
<path d="M130.8 202.9l.2-.1a.64 .64 0 0 1 .4 .6 .64 .64 0 0 1-.4 .5 .6 .6 0 0 1-.4-.4 .6 .6 0 0 1 .2-.6z" fill="none" stroke="#9e480e" stroke-width=".26"/>
<path d="M131.8 202.9l.1-.1a.64 .64 0 0 1 .4 .6 .64 .64 0 0 1-.4 .5 .64 .64 0 0 1-.1-1z" fill="#9e480e"/>
<path d="M131.8 202.9l.1-.1a.64 .64 0 0 1 .4 .6 .64 .64 0 0 1-.4 .5 .64 .64 0 0 1-.1-1z" fill="none" stroke="#9e480e" stroke-width=".26"/>
<path d="M132.6 202.9l.2-.1a.59 .59 0 0 1 .4 .6 .59 .59 0 0 1-.4 .5 .64 .64 0 0 1-.2-1z" fill="#9e480e"/>
<path d="M132.6 202.9l.2-.1a.59 .59 0 0 1 .4 .6 .59 .59 0 0 1-.4 .5 .64 .64 0 0 1-.2-1z" fill="none" stroke="#9e480e" stroke-width=".26"/>
<path d="M133.5 202.9l.2-.1a.59 .59 0 0 1 .4 .6 .59 .59 0 0 1-.4 .5 .64 .64 0 0 1-.2-1z" fill="#9e480e"/>
<path d="M133.5 202.9l.2-.1a.59 .59 0 0 1 .4 .6 .59 .59 0 0 1-.4 .5 .64 .64 0 0 1-.2-1z" fill="none" stroke="#9e480e" stroke-width=".26"/>
<path d="M134.4 202.9l.3-.1a.64 .64 0 0 1 .3 .6 .64 .64 0 0 1-.3 .5 .6 .6 0 0 1-.5-.4 .6 .6 0 0 1 .2-.6z" fill="#9e480e"/>
<path d="M134.4 202.9l.3-.1a.64 .64 0 0 1 .3 .6 .64 .64 0 0 1-.3 .5 .6 .6 0 0 1-.5-.4 .6 .6 0 0 1 .2-.6z" fill="none" stroke="#9e480e" stroke-width=".26"/>
<path d="M135.3 202.9l.2-.1a.64 .64 0 0 1 .4 .6 .64 .64 0 0 1-.4 .5 .6 .6 0 0 1-.4-.4 .6 .6 0 0 1 .2-.6z" fill="#9e480e"/>
<path d="M135.3 202.9l.2-.1a.64 .64 0 0 1 .4 .6 .64 .64 0 0 1-.4 .5 .6 .6 0 0 1-.4-.4 .6 .6 0 0 1 .2-.6z" fill="none" stroke="#9e480e" stroke-width=".26"/>
<path d="M136.2 202.9l.2-.1a.64 .64 0 0 1 .4 .6 .64 .64 0 0 1-.4 .5 .64 .64 0 0 1-.2-1z" fill="#9e480e"/>
<path d="M136.2 202.9l.2-.1a.64 .64 0 0 1 .4 .6 .64 .64 0 0 1-.4 .5 .64 .64 0 0 1-.2-1z" fill="none" stroke="#9e480e" stroke-width=".26"/>
<path d="M137.1 202.9l.2-.1a.59 .59 0 0 1 .4 .6 .59 .59 0 0 1-.4 .5 .64 .64 0 0 1-.2-1z" fill="#9e480e"/>
<path d="M137.1 202.9l.2-.1a.59 .59 0 0 1 .4 .6 .59 .59 0 0 1-.4 .5 .64 .64 0 0 1-.2-1z" fill="none" stroke="#9e480e" stroke-width=".26"/>
<path d="M138 202.9l.2-.1a.59 .59 0 0 1 .4 .6 .59 .59 0 0 1-.4 .5 .64 .64 0 0 1-.2-1z" fill="#9e480e"/>
<path d="M138 202.9l.2-.1a.59 .59 0 0 1 .4 .6 .59 .59 0 0 1-.4 .5 .64 .64 0 0 1-.2-1z" fill="none" stroke="#9e480e" stroke-width=".26"/>
<path d="M138.9 202.9l.2-.1a.64 .64 0 0 1 .4 .6 .64 .64 0 0 1-.4 .5 .6 .6 0 0 1-.4-.4 .6 .6 0 0 1 .2-.6z" fill="#9e480e"/>
<path d="M138.9 202.9l.2-.1a.64 .64 0 0 1 .4 .6 .64 .64 0 0 1-.4 .5 .6 .6 0 0 1-.4-.4 .6 .6 0 0 1 .2-.6z" fill="none" stroke="#9e480e" stroke-width=".26"/>
<path d="M139.9 202.9l.1-.1a.64 .64 0 0 1 .4 .6 .64 .64 0 0 1-.4 .5 .64 .64 0 0 1-.1-1z" fill="#9e480e"/>
<path d="M139.9 202.9l.1-.1a.64 .64 0 0 1 .4 .6 .64 .64 0 0 1-.4 .5 .64 .64 0 0 1-.1-1z" fill="none" stroke="#9e480e" stroke-width=".26"/>
<path d="M140.7 202.9l.2-.1a.59 .59 0 0 1 .5 .6 .59 .59 0 0 1-.5 .5 .64 .64 0 0 1-.2-1z" fill="#9e480e"/>
<path d="M140.7 202.9l.2-.1a.59 .59 0 0 1 .5 .6 .59 .59 0 0 1-.5 .5 .64 .64 0 0 1-.2-1z" fill="none" stroke="#9e480e" stroke-width=".26"/>
<path d="M141.6 202.9l.2-.1a.59 .59 0 0 1 .4 .6 .59 .59 0 0 1-.4 .5 .64 .64 0 0 1-.2-1z" fill="#9e480e"/>
<path d="M141.6 202.9l.2-.1a.59 .59 0 0 1 .4 .6 .59 .59 0 0 1-.4 .5 .64 .64 0 0 1-.2-1z" fill="none" stroke="#9e480e" stroke-width=".26"/>
<path d="M142.5 202.9l.3-.1a.64 .64 0 0 1 .3 .6 .64 .64 0 0 1-.3 .5 .6 .6 0 0 1-.5-.4 .6 .6 0 0 1 .2-.6z" fill="#9e480e"/>
<path d="M142.5 202.9l.3-.1a.64 .64 0 0 1 .3 .6 .64 .64 0 0 1-.3 .5 .6 .6 0 0 1-.5-.4 .6 .6 0 0 1 .2-.6z" fill="none" stroke="#9e480e" stroke-width=".26"/>
<path d="M143.4 202.9l.2-.1a.64 .64 0 0 1 .4 .6 .64 .64 0 0 1-.4 .5 .6 .6 0 0 1-.4-.4 .6 .6 0 0 1 .2-.6z" fill="#9e480e"/>
<path d="M143.4 202.9l.2-.1a.64 .64 0 0 1 .4 .6 .64 .64 0 0 1-.4 .5 .6 .6 0 0 1-.4-.4 .6 .6 0 0 1 .2-.6z" fill="none" stroke="#9e480e" stroke-width=".26"/>
<path d="M144.4 202.9l.1-.1a.64 .64 0 0 1 .4 .6 .64 .64 0 0 1-.4 .5 .64 .64 0 0 1-.1-1z" fill="#9e480e"/>
<path d="M144.4 202.9l.1-.1a.64 .64 0 0 1 .4 .6 .64 .64 0 0 1-.4 .5 .64 .64 0 0 1-.1-1z" fill="none" stroke="#9e480e" stroke-width=".26"/>
<path d="M145.2 202.9l.2-.1a.59 .59 0 0 1 .4 .6 .59 .59 0 0 1-.4 .5 .64 .64 0 0 1-.2-1z" fill="#9e480e"/>
<path d="M145.2 202.9l.2-.1a.59 .59 0 0 1 .4 .6 .59 .59 0 0 1-.4 .5 .64 .64 0 0 1-.2-1z" fill="none" stroke="#9e480e" stroke-width=".26"/>
<path d="M146.1 202.9l.2-.1a.59 .59 0 0 1 .4 .6 .59 .59 0 0 1-.4 .5 .64 .64 0 0 1-.2-1z" fill="#9e480e"/>
<path d="M146.1 202.9l.2-.1a.59 .59 0 0 1 .4 .6 .59 .59 0 0 1-.4 .5 .64 .64 0 0 1-.2-1z" fill="none" stroke="#9e480e" stroke-width=".26"/>
<path d="M146.9 202.9l.2-.1a.59 .59 0 0 1 .4 .6 .59 .59 0 0 1-.4 .5 .64 .64 0 0 1-.2-1z" fill="#9e480e"/>
<path d="M146.9 202.9l.2-.1a.59 .59 0 0 1 .4 .6 .59 .59 0 0 1-.4 .5 .64 .64 0 0 1-.2-1z" fill="none" stroke="#9e480e" stroke-width=".26"/>
<path d="M147.8 202.9l.2-.1a.59 .59 0 0 1 .4 .6 .59 .59 0 0 1-.4 .5 .64 .64 0 0 1-.2-1z" fill="#9e480e"/>
<path d="M147.8 202.9l.2-.1a.59 .59 0 0 1 .4 .6 .59 .59 0 0 1-.4 .5 .64 .64 0 0 1-.2-1z" fill="none" stroke="#9e480e" stroke-width=".26"/>
<path d="M148.7 202.9l.2-.1a.64 .64 0 0 1 .4 .6 .64 .64 0 0 1-.4 .5 .6 .6 0 0 1-.4-.4 .6 .6 0 0 1 .2-.6z" fill="#9e480e"/>
<path d="M148.7 202.9l.2-.1a.64 .64 0 0 1 .4 .6 .64 .64 0 0 1-.4 .5 .6 .6 0 0 1-.4-.4 .6 .6 0 0 1 .2-.6z" fill="none" stroke="#9e480e" stroke-width=".26"/>
<path d="M149.6 202.7l.2-.1a.64 .64 0 0 1 .4 .6 .64 .64 0 0 1-.4 .6 .64 .64 0 0 1-.2-1.1z" fill="#9e480e"/>
<path d="M149.6 202.7l.2-.1a.64 .64 0 0 1 .4 .6 .64 .64 0 0 1-.4 .6 .64 .64 0 0 1-.2-1.1z" fill="none" stroke="#9e480e" stroke-width=".26"/>
<path d="M150.5 199.9l.2-.1a.59 .59 0 0 1 .4 .6 .59 .59 0 0 1-.4 .5 .64 .64 0 0 1-.2-1z" fill="#9e480e"/>
<path d="M150.5 199.9l.2-.1a.59 .59 0 0 1 .4 .6 .59 .59 0 0 1-.4 .5 .64 .64 0 0 1-.2-1z" fill="none" stroke="#9e480e" stroke-width=".26"/>
<path d="M151.4 196.7l.2-.1a.59 .59 0 0 1 .4 .6 .59 .59 0 0 1-.4 .6 .64 .64 0 0 1-.2-1.1z" fill="#9e480e"/>
<path d="M151.4 196.7l.2-.1a.59 .59 0 0 1 .4 .6 .59 .59 0 0 1-.4 .6 .64 .64 0 0 1-.2-1.1z" fill="none" stroke="#9e480e" stroke-width=".26"/>
<path d="M152.3 194.7l.2-.1a.64 .64 0 0 1 .4 .6 .64 .64 0 0 1-.4 .5 .61 .61 0 0 1-.4-.4 .61 .61 0 0 1 .2-.6z" fill="#9e480e"/>
<path d="M152.3 194.7l.2-.1a.64 .64 0 0 1 .4 .6 .64 .64 0 0 1-.4 .5 .61 .61 0 0 1-.4-.4 .61 .61 0 0 1 .2-.6z" fill="none" stroke="#9e480e" stroke-width=".26"/>
<path d="M153.2 192.2l.2-.1a.64 .64 0 0 1 .4 .6 .64 .64 0 0 1-.4 .6 .6 .6 0 0 1-.4-.5 .6 .6 0 0 1 .2-.6z" fill="#9e480e"/>
<path d="M153.2 192.2l.2-.1a.64 .64 0 0 1 .4 .6 .64 .64 0 0 1-.4 .6 .6 .6 0 0 1-.4-.5 .6 .6 0 0 1 .2-.6z" fill="none" stroke="#9e480e" stroke-width=".26"/>
<path d="M154.1 190l.2-.1a.51 .51 0 0 1 .3 .6 .51 .51 0 0 1-.5 .4 .7 .7 0 0 1 0-.9z" fill="#9e480e"/>
<path d="M154.1 190l.2-.1a.51 .51 0 0 1 .3 .6 .51 .51 0 0 1-.5 .4 .7 .7 0 0 1 0-.9z" fill="none" stroke="#9e480e" stroke-width=".26"/>
<path d="M155 187.7l.2-.1a.59 .59 0 0 1 .4 .6 .59 .59 0 0 1-.4 .6 .64 .64 0 0 1-.2-1.1z" fill="#9e480e"/>
<path d="M155 187.7l.2-.1a.59 .59 0 0 1 .4 .6 .59 .59 0 0 1-.4 .6 .64 .64 0 0 1-.2-1.1z" fill="none" stroke="#9e480e" stroke-width=".26"/>
<path d="M155.9 185.7l.2-.1a.54 .54 0 0 1 .4 .6 .54 .54 0 0 1-.6 .5 .75 .75 0 0 1 0-1z" fill="#9e480e"/>
<path d="M155.9 185.7l.2-.1a.54 .54 0 0 1 .4 .6 .54 .54 0 0 1-.6 .5 .75 .75 0 0 1 0-1z" fill="none" stroke="#9e480e" stroke-width=".26"/>
<path d="M156.8 183.4l.2-.1a.64 .64 0 0 1 .4 .6 .64 .64 0 0 1-.4 .5 .6 .6 0 0 1-.4-.4 .6 .6 0 0 1 .2-.6z" fill="#9e480e"/>
<path d="M156.8 183.4l.2-.1a.64 .64 0 0 1 .4 .6 .64 .64 0 0 1-.4 .5 .6 .6 0 0 1-.4-.4 .6 .6 0 0 1 .2-.6z" fill="none" stroke="#9e480e" stroke-width=".26"/>
<path d="M157.7 181.3h.2a.64 .64 0 0 1 .4 .5 .64 .64 0 0 1-.4 .6 .66 .66 0 0 1-.2-1.1z" fill="#9e480e"/>
<path d="M157.7 181.3h.2a.64 .64 0 0 1 .4 .5 .64 .64 0 0 1-.4 .6 .66 .66 0 0 1-.2-1.1z" fill="none" stroke="#9e480e" stroke-width=".26"/>
<path d="M158.6 179.5a.49 .49 0 0 1 .6 .4 .49 .49 0 0 1-.6 .5 .7 .7 0 0 1 0-.9z" fill="#9e480e"/>
<path d="M158.6 179.5a.49 .49 0 0 1 .6 .4 .49 .49 0 0 1-.6 .5 .7 .7 0 0 1 0-.9z" fill="none" stroke="#9e480e" stroke-width=".26"/>
<path d="M159.5 177.6l.2-.1a.59 .59 0 0 1 .4 .5 .59 .59 0 0 1-.4 .6 .64 .64 0 0 1-.2-1z" fill="#9e480e"/>
<path d="M159.5 177.6l.2-.1a.59 .59 0 0 1 .4 .5 .59 .59 0 0 1-.4 .6 .64 .64 0 0 1-.2-1z" fill="none" stroke="#9e480e" stroke-width=".26"/>
<path d="M160.4 176.2l.2-.1a.64 .64 0 0 1 .4 .6 .64 .64 0 0 1-.4 .6 .6 .6 0 0 1-.4-.5 .6 .6 0 0 1 .2-.6z" fill="#9e480e"/>
<path d="M160.4 176.2l.2-.1a.64 .64 0 0 1 .4 .6 .64 .64 0 0 1-.4 .6 .6 .6 0 0 1-.4-.5 .6 .6 0 0 1 .2-.6z" fill="none" stroke="#9e480e" stroke-width=".26"/>
<path d="M161.3 175.2l.2-.1a.52 .52 0 0 1 .4 .6 .52 .52 0 0 1-.6 .4 .61 .61 0 0 1 0-.9z" fill="#9e480e"/>
<path d="M161.3 175.2l.2-.1a.52 .52 0 0 1 .4 .6 .52 .52 0 0 1-.6 .4 .61 .61 0 0 1 0-.9z" fill="none" stroke="#9e480e" stroke-width=".26"/>
<path d="M162.2 174.4l.2-.1a.64 .64 0 0 1 .4 .6 .64 .64 0 0 1-.4 .5 .64 .64 0 0 1-.2-1z" fill="#9e480e"/>
<path d="M162.2 174.4l.2-.1a.64 .64 0 0 1 .4 .6 .64 .64 0 0 1-.4 .5 .64 .64 0 0 1-.2-1z" fill="none" stroke="#9e480e" stroke-width=".26"/>
<path d="M163.1 173.7l.2-.1a.51 .51 0 0 1 .4 .6 .51 .51 0 0 1-.6 .4 .67 .67 0 0 1 0-.9z" fill="#9e480e"/>
<path d="M163.1 173.7l.2-.1a.51 .51 0 0 1 .4 .6 .51 .51 0 0 1-.6 .4 .67 .67 0 0 1 0-.9z" fill="none" stroke="#9e480e" stroke-width=".26"/>
<path d="M164 173.2h.3a.64 .64 0 0 1 .3 .5 .64 .64 0 0 1-.3 .6 .6 .6 0 0 1-.5-.5 .6 .6 0 0 1 .2-.6z" fill="#9e480e"/>
<path d="M164 173.2h.3a.64 .64 0 0 1 .3 .5 .64 .64 0 0 1-.3 .6 .6 .6 0 0 1-.5-.5 .6 .6 0 0 1 .2-.6z" fill="none" stroke="#9e480e" stroke-width=".26"/>
<path d="M164.8 172.9l.2-.1a.59 .59 0 0 1 .4 .6 .59 .59 0 0 1-.4 .5 .64 .64 0 0 1-.2-1z" fill="#9e480e"/>
<path d="M164.8 172.9l.2-.1a.59 .59 0 0 1 .4 .6 .59 .59 0 0 1-.4 .5 .64 .64 0 0 1-.2-1z" fill="none" stroke="#9e480e" stroke-width=".26"/>
<path d="M165.7 172.5l.1-.1a.54 .54 0 0 1 .5 .7 .54 .54 0 0 1-.6 .4 .75 .75 0 0 1 0-1z" fill="#9e480e"/>
<path d="M165.7 172.5l.1-.1a.54 .54 0 0 1 .5 .7 .54 .54 0 0 1-.6 .4 .75 .75 0 0 1 0-1z" fill="none" stroke="#9e480e" stroke-width=".26"/>
<path d="M166.6 172.3h.2a.64 .64 0 0 1 .4 .5 .64 .64 0 0 1-.4 .6 .61 .61 0 0 1-.4-.4 .61 .61 0 0 1 .2-.7z" fill="#9e480e"/>
<path d="M166.6 172.3h.2a.64 .64 0 0 1 .4 .5 .64 .64 0 0 1-.4 .6 .61 .61 0 0 1-.4-.4 .61 .61 0 0 1 .2-.7z" fill="none" stroke="#9e480e" stroke-width=".26"/>
<path d="M167.5 172.2l.2-.1a.51 .51 0 0 1 .3 .6 .51 .51 0 0 1-.5 .4 .67 .67 0 0 1 0-.9z" fill="#9e480e"/>
<path d="M167.5 172.2l.2-.1a.51 .51 0 0 1 .3 .6 .51 .51 0 0 1-.5 .4 .67 .67 0 0 1 0-.9z" fill="none" stroke="#9e480e" stroke-width=".26"/>
<path d="M168.4 172h.4a.57 .57 0 0 1 .2 .5 .57 .57 0 0 1-.4 .5 .6 .6 0 0 1-.2-1z" fill="#9e480e"/>
<path d="M168.4 172h.4a.57 .57 0 0 1 .2 .5 .57 .57 0 0 1-.4 .5 .6 .6 0 0 1-.2-1z" fill="none" stroke="#9e480e" stroke-width=".26"/>
<path d="M169.3 171.7h.2a.59 .59 0 0 1 .4 .5 .59 .59 0 0 1-.4 .6 .64 .64 0 0 1-.2-1.1z" fill="#9e480e"/>
<path d="M169.3 171.7h.2a.59 .59 0 0 1 .4 .5 .59 .59 0 0 1-.4 .6 .64 .64 0 0 1-.2-1.1z" fill="none" stroke="#9e480e" stroke-width=".26"/>
<path d="M170.2 171.6l.2-.1a.64 .64 0 0 1 .4 .5 .64 .64 0 0 1-.4 .6 .6 .6 0 0 1-.4-.4 .6 .6 0 0 1 .2-.6z" fill="#9e480e"/>
<path d="M170.2 171.6l.2-.1a.64 .64 0 0 1 .4 .5 .64 .64 0 0 1-.4 .6 .6 .6 0 0 1-.4-.4 .6 .6 0 0 1 .2-.6z" fill="none" stroke="#9e480e" stroke-width=".26"/>
<path d="M171.1 171.6l.2-.1a.64 .64 0 0 1 .4 .5 .64 .64 0 0 1-.4 .6 .6 .6 0 0 1-.5-.4 .6 .6 0 0 1 .3-.6z" fill="#9e480e"/>
<path d="M171.1 171.6l.2-.1a.64 .64 0 0 1 .4 .5 .64 .64 0 0 1-.4 .6 .6 .6 0 0 1-.5-.4 .6 .6 0 0 1 .3-.6z" fill="none" stroke="#9e480e" stroke-width=".26"/>
<path d="M172 171.6l.2-.1a.64 .64 0 0 1 .3 .5 .64 .64 0 0 1-.3 .6 .64 .64 0 0 1-.2-1z" fill="#9e480e"/>
<path d="M172 171.6l.2-.1a.64 .64 0 0 1 .3 .5 .64 .64 0 0 1-.3 .6 .64 .64 0 0 1-.2-1z" fill="none" stroke="#9e480e" stroke-width=".26"/>
<path d="M172.9 171.4l.2-.1a.59 .59 0 0 1 .4 .6 .59 .59 0 0 1-.4 .5 .64 .64 0 0 1-.2-1z" fill="#9e480e"/>
<path d="M172.9 171.4l.2-.1a.59 .59 0 0 1 .4 .6 .59 .59 0 0 1-.4 .5 .64 .64 0 0 1-.2-1z" fill="none" stroke="#9e480e" stroke-width=".26"/>
<path d="M173.8 171.4l.1-.1a.59 .59 0 0 1 .5 .6 .59 .59 0 0 1-.5 .5 .64 .64 0 0 1-.1-1z" fill="#9e480e"/>
<path d="M173.8 171.4l.1-.1a.59 .59 0 0 1 .5 .6 .59 .59 0 0 1-.5 .5 .64 .64 0 0 1-.1-1z" fill="none" stroke="#9e480e" stroke-width=".26"/>
<path d="M174.7 171.4l.2-.1a.64 .64 0 0 1 .4 .6 .64 .64 0 0 1-.4 .5 .6 .6 0 0 1-.4-.4 .6 .6 0 0 1 .2-.6z" fill="#9e480e"/>
<path d="M174.7 171.4l.2-.1a.64 .64 0 0 1 .4 .6 .64 .64 0 0 1-.4 .5 .6 .6 0 0 1-.4-.4 .6 .6 0 0 1 .2-.6z" fill="none" stroke="#9e480e" stroke-width=".26"/>
<path d="M175.6 171.4l.2-.1a.64 .64 0 0 1 .3 .6 .64 .64 0 0 1-.3 .5 .64 .64 0 0 1-.2-1z" fill="#9e480e"/>
<path d="M175.6 171.4l.2-.1a.64 .64 0 0 1 .3 .6 .64 .64 0 0 1-.3 .5 .64 .64 0 0 1-.2-1z" fill="none" stroke="#9e480e" stroke-width=".26"/>
<path d="M176.5 171.4l.2-.1a.59 .59 0 0 1 .4 .6 .59 .59 0 0 1-.4 .5 .64 .64 0 0 1-.2-1z" fill="#9e480e"/>
<path d="M176.5 171.4l.2-.1a.59 .59 0 0 1 .4 .6 .59 .59 0 0 1-.4 .5 .64 .64 0 0 1-.2-1z" fill="none" stroke="#9e480e" stroke-width=".26"/>
<path d="M177.4 171.2l.2-.1a.54 .54 0 0 1 .4 .6 .54 .54 0 0 1-.6 .5 .75 .75 0 0 1 0-1z" fill="#9e480e"/>
<path d="M177.4 171.2l.2-.1a.54 .54 0 0 1 .4 .6 .54 .54 0 0 1-.6 .5 .75 .75 0 0 1 0-1z" fill="none" stroke="#9e480e" stroke-width=".26"/>
<path d="M178.3 171.2l.2-.1a.64 .64 0 0 1 .4 .6 .64 .64 0 0 1-.4 .6 .61 .61 0 0 1-.4-.5 .61 .61 0 0 1 .2-.6z" fill="#9e480e"/>
<path d="M178.3 171.2l.2-.1a.64 .64 0 0 1 .4 .6 .64 .64 0 0 1-.4 .6 .61 .61 0 0 1-.4-.5 .61 .61 0 0 1 .2-.6z" fill="none" stroke="#9e480e" stroke-width=".26"/>
<path d="M179.2 171.2l.2-.1a.64 .64 0 0 1 .4 .6 .64 .64 0 0 1-.4 .6 .61 .61 0 0 1-.4-.5 .61 .61 0 0 1 .2-.6z" fill="#9e480e"/>
<path d="M179.2 171.2l.2-.1a.64 .64 0 0 1 .4 .6 .64 .64 0 0 1-.4 .6 .61 .61 0 0 1-.4-.5 .61 .61 0 0 1 .2-.6z" fill="none" stroke="#9e480e" stroke-width=".26"/>
<path d="M180.1 171.2l.2-.1a.64 .64 0 0 1 .3 .6 .64 .64 0 0 1-.3 .6 .66 .66 0 0 1-.2-1.1z" fill="#9e480e"/>
<path d="M180.1 171.2l.2-.1a.64 .64 0 0 1 .3 .6 .64 .64 0 0 1-.3 .6 .66 .66 0 0 1-.2-1.1z" fill="none" stroke="#9e480e" stroke-width=".26"/>
<path d="M181 171.2l.2-.1a.54 .54 0 0 1 .4 .6 .54 .54 0 0 1-.6 .5 .75 .75 0 0 1 0-1z" fill="#9e480e"/>
<path d="M181 171.2l.2-.1a.54 .54 0 0 1 .4 .6 .54 .54 0 0 1-.6 .5 .75 .75 0 0 1 0-1z" fill="none" stroke="#9e480e" stroke-width=".26"/>
<path d="M181.9 171.2l.2-.1a.64 .64 0 0 1 .4 .6 .64 .64 0 0 1-.4 .6 .61 .61 0 0 1-.4-.5 .61 .61 0 0 1 .2-.6z" fill="#9e480e"/>
<path d="M181.9 171.2l.2-.1a.64 .64 0 0 1 .4 .6 .64 .64 0 0 1-.4 .6 .61 .61 0 0 1-.4-.5 .61 .61 0 0 1 .2-.6z" fill="none" stroke="#9e480e" stroke-width=".26"/>
<path d="M182.7 171.2l.1-.1a.54 .54 0 0 1 .5 .6 .54 .54 0 0 1-.6 .5 .75 .75 0 0 1 0-1z" fill="#9e480e"/>
<path d="M182.7 171.2l.1-.1a.54 .54 0 0 1 .5 .6 .54 .54 0 0 1-.6 .5 .75 .75 0 0 1 0-1z" fill="none" stroke="#9e480e" stroke-width=".26"/>
<path d="M183.6 171.2l.1-.1a.54 .54 0 0 1 .5 .6 .54 .54 0 0 1-.6 .5 .75 .75 0 0 1 0-1z" fill="#9e480e"/>
<path d="M183.6 171.2l.1-.1a.54 .54 0 0 1 .5 .6 .54 .54 0 0 1-.6 .5 .75 .75 0 0 1 0-1z" fill="none" stroke="#9e480e" stroke-width=".26"/>
<path d="M184.5 171.2l.2-.1a.64 .64 0 0 1 .3 .6 .64 .64 0 0 1-.3 .6 .61 .61 0 0 1-.5-.5 .61 .61 0 0 1 .3-.6z" fill="#9e480e"/>
<path d="M184.5 171.2l.2-.1a.64 .64 0 0 1 .3 .6 .64 .64 0 0 1-.3 .6 .61 .61 0 0 1-.5-.5 .61 .61 0 0 1 .3-.6z" fill="none" stroke="#9e480e" stroke-width=".26"/>
<path d="M185.4 171.2l.2-.1a.64 .64 0 0 1 .3 .6 .64 .64 0 0 1-.3 .6 .66 .66 0 0 1-.2-1.1z" fill="#9e480e"/>
<path d="M185.4 171.2l.2-.1a.64 .64 0 0 1 .3 .6 .64 .64 0 0 1-.3 .6 .66 .66 0 0 1-.2-1.1z" fill="none" stroke="#9e480e" stroke-width=".26"/>
<path d="M186.3 171.2l.2-.1a.54 .54 0 0 1 .4 .6 .54 .54 0 0 1-.6 .5 .75 .75 0 0 1 0-1z" fill="#9e480e"/>
<path d="M186.3 171.2l.2-.1a.54 .54 0 0 1 .4 .6 .54 .54 0 0 1-.6 .5 .75 .75 0 0 1 0-1z" fill="none" stroke="#9e480e" stroke-width=".26"/>
<path d="M187.2 171.2l.1-.1a.54 .54 0 0 1 .5 .6 .54 .54 0 0 1-.6 .5 .75 .75 0 0 1 0-1z" fill="#9e480e"/>
<path d="M187.2 171.2l.1-.1a.54 .54 0 0 1 .5 .6 .54 .54 0 0 1-.6 .5 .75 .75 0 0 1 0-1z" fill="none" stroke="#9e480e" stroke-width=".26"/>
<path d="M188.1 171.2l.2-.1a.64 .64 0 0 1 .4 .6 .64 .64 0 0 1-.4 .6 .61 .61 0 0 1-.4-.5 .61 .61 0 0 1 .2-.6z" fill="#9e480e"/>
<path d="M188.1 171.2l.2-.1a.64 .64 0 0 1 .4 .6 .64 .64 0 0 1-.4 .6 .61 .61 0 0 1-.4-.5 .61 .61 0 0 1 .2-.6z" fill="none" stroke="#9e480e" stroke-width=".26"/>
<path d="M189 171.2l.2-.1a.64 .64 0 0 1 .3 .6 .64 .64 0 0 1-.3 .6 .61 .61 0 0 1-.5-.5 .61 .61 0 0 1 .3-.6z" fill="#9e480e"/>
<path d="M189 171.2l.2-.1a.64 .64 0 0 1 .3 .6 .64 .64 0 0 1-.3 .6 .61 .61 0 0 1-.5-.5 .61 .61 0 0 1 .3-.6z" fill="none" stroke="#9e480e" stroke-width=".26"/>
<path d="M189.9 171.2l.2-.1a.64 .64 0 0 1 .3 .6 .64 .64 0 0 1-.3 .6 .66 .66 0 0 1-.2-1.1z" fill="#9e480e"/>
<path d="M189.9 171.2l.2-.1a.64 .64 0 0 1 .3 .6 .64 .64 0 0 1-.3 .6 .66 .66 0 0 1-.2-1.1z" fill="none" stroke="#9e480e" stroke-width=".26"/>
<path d="M190.8 171.2l.1-.1a.54 .54 0 0 1 .5 .6 .54 .54 0 0 1-.6 .5 .75 .75 0 0 1 0-1z" fill="#9e480e"/>
<path d="M190.8 171.2l.1-.1a.54 .54 0 0 1 .5 .6 .54 .54 0 0 1-.6 .5 .75 .75 0 0 1 0-1z" fill="none" stroke="#9e480e" stroke-width=".26"/>
<path d="M191.7 171.2l.1-.1a.54 .54 0 0 1 .5 .6 .54 .54 0 0 1-.6 .5 .75 .75 0 0 1 0-1z" fill="#9e480e"/>
<path d="M191.7 171.2l.1-.1a.54 .54 0 0 1 .5 .6 .54 .54 0 0 1-.6 .5 .75 .75 0 0 1 0-1z" fill="none" stroke="#9e480e" stroke-width=".26"/>
<path d="M192.6 171.2l.2-.1a.64 .64 0 0 1 .4 .6 .64 .64 0 0 1-.4 .6 .61 .61 0 0 1-.4-.5 .61 .61 0 0 1 .2-.6z" fill="#9e480e"/>
<path d="M192.6 171.2l.2-.1a.64 .64 0 0 1 .4 .6 .64 .64 0 0 1-.4 .6 .61 .61 0 0 1-.4-.5 .61 .61 0 0 1 .2-.6z" fill="none" stroke="#9e480e" stroke-width=".26"/>
<path d="M192.7 171.7l-17 .1-3.5 .2-3.6 .4a11.6 11.6 0 0 0-7.4 3.5 37.1 37.1 0 0 0-4.8 9.4l-3.2 8a48.5 48.5 0 0 0-3.1 9.2 .94 .94 0 0 1-1 1h-18.9" fill="none" stroke="#626262" stroke-width=".44"/>
<path d="M129.9 202.9l.2-.1a.59 .59 0 0 1 .4 .6 .59 .59 0 0 1-.4 .5 .64 .64 0 0 1-.2-1z" fill="#626262"/>
<path d="M129.9 202.9l.2-.1a.59 .59 0 0 1 .4 .6 .59 .59 0 0 1-.4 .5 .64 .64 0 0 1-.2-1z" fill="none" stroke="#626262" stroke-width=".26"/>
<path d="M130.8 202.9l.2-.1a.64 .64 0 0 1 .4 .6 .64 .64 0 0 1-.4 .5 .6 .6 0 0 1-.4-.4 .6 .6 0 0 1 .2-.6z" fill="#626262"/>
<path d="M130.8 202.9l.2-.1a.64 .64 0 0 1 .4 .6 .64 .64 0 0 1-.4 .5 .6 .6 0 0 1-.4-.4 .6 .6 0 0 1 .2-.6z" fill="none" stroke="#626262" stroke-width=".26"/>
<path d="M131.8 202.9l.1-.1a.64 .64 0 0 1 .4 .6 .64 .64 0 0 1-.4 .5 .64 .64 0 0 1-.1-1z" fill="#626262"/>
<path d="M131.8 202.9l.1-.1a.64 .64 0 0 1 .4 .6 .64 .64 0 0 1-.4 .5 .64 .64 0 0 1-.1-1z" fill="none" stroke="#626262" stroke-width=".26"/>
<path d="M132.6 202.9l.2-.1a.59 .59 0 0 1 .4 .6 .59 .59 0 0 1-.4 .5 .64 .64 0 0 1-.2-1z" fill="#626262"/>
<path d="M132.6 202.9l.2-.1a.59 .59 0 0 1 .4 .6 .59 .59 0 0 1-.4 .5 .64 .64 0 0 1-.2-1z" fill="none" stroke="#626262" stroke-width=".26"/>
<path d="M133.5 202.9l.2-.1a.59 .59 0 0 1 .4 .6 .59 .59 0 0 1-.4 .5 .64 .64 0 0 1-.2-1z" fill="#626262"/>
<path d="M133.5 202.9l.2-.1a.59 .59 0 0 1 .4 .6 .59 .59 0 0 1-.4 .5 .64 .64 0 0 1-.2-1z" fill="none" stroke="#626262" stroke-width=".26"/>
<path d="M134.4 202.9l.3-.1a.64 .64 0 0 1 .3 .6 .64 .64 0 0 1-.3 .5 .6 .6 0 0 1-.5-.4 .6 .6 0 0 1 .2-.6z" fill="#626262"/>
<path d="M134.4 202.9l.3-.1a.64 .64 0 0 1 .3 .6 .64 .64 0 0 1-.3 .5 .6 .6 0 0 1-.5-.4 .6 .6 0 0 1 .2-.6z" fill="none" stroke="#626262" stroke-width=".26"/>
<path d="M135.3 202.9l.2-.1a.64 .64 0 0 1 .4 .6 .64 .64 0 0 1-.4 .5 .6 .6 0 0 1-.4-.4 .6 .6 0 0 1 .2-.6z" fill="#626262"/>
<path d="M135.3 202.9l.2-.1a.64 .64 0 0 1 .4 .6 .64 .64 0 0 1-.4 .5 .6 .6 0 0 1-.4-.4 .6 .6 0 0 1 .2-.6z" fill="none" stroke="#626262" stroke-width=".26"/>
<path d="M136.2 202.9l.2-.1a.64 .64 0 0 1 .4 .6 .64 .64 0 0 1-.4 .5 .64 .64 0 0 1-.2-1z" fill="#626262"/>
<path d="M136.2 202.9l.2-.1a.64 .64 0 0 1 .4 .6 .64 .64 0 0 1-.4 .5 .64 .64 0 0 1-.2-1z" fill="none" stroke="#626262" stroke-width=".26"/>
<path d="M137.1 202.9l.2-.1a.59 .59 0 0 1 .4 .6 .59 .59 0 0 1-.4 .5 .64 .64 0 0 1-.2-1z" fill="#626262"/>
<path d="M137.1 202.9l.2-.1a.59 .59 0 0 1 .4 .6 .59 .59 0 0 1-.4 .5 .64 .64 0 0 1-.2-1z" fill="none" stroke="#626262" stroke-width=".26"/>
<path d="M138 202.9l.2-.1a.59 .59 0 0 1 .4 .6 .59 .59 0 0 1-.4 .5 .64 .64 0 0 1-.2-1z" fill="#626262"/>
<path d="M138 202.9l.2-.1a.59 .59 0 0 1 .4 .6 .59 .59 0 0 1-.4 .5 .64 .64 0 0 1-.2-1z" fill="none" stroke="#626262" stroke-width=".26"/>
<path d="M138.9 202.9l.2-.1a.64 .64 0 0 1 .4 .6 .64 .64 0 0 1-.4 .5 .6 .6 0 0 1-.4-.4 .6 .6 0 0 1 .2-.6z" fill="#626262"/>
<path d="M138.9 202.9l.2-.1a.64 .64 0 0 1 .4 .6 .64 .64 0 0 1-.4 .5 .6 .6 0 0 1-.4-.4 .6 .6 0 0 1 .2-.6z" fill="none" stroke="#626262" stroke-width=".26"/>
<path d="M139.9 202.9l.1-.1a.64 .64 0 0 1 .4 .6 .64 .64 0 0 1-.4 .5 .64 .64 0 0 1-.1-1z" fill="#626262"/>
<path d="M139.9 202.9l.1-.1a.64 .64 0 0 1 .4 .6 .64 .64 0 0 1-.4 .5 .64 .64 0 0 1-.1-1z" fill="none" stroke="#626262" stroke-width=".26"/>
<path d="M140.7 202.9l.2-.1a.59 .59 0 0 1 .5 .6 .59 .59 0 0 1-.5 .5 .64 .64 0 0 1-.2-1z" fill="#626262"/>
<path d="M140.7 202.9l.2-.1a.59 .59 0 0 1 .5 .6 .59 .59 0 0 1-.5 .5 .64 .64 0 0 1-.2-1z" fill="none" stroke="#626262" stroke-width=".26"/>
<path d="M141.6 202.9l.2-.1a.59 .59 0 0 1 .4 .6 .59 .59 0 0 1-.4 .5 .64 .64 0 0 1-.2-1z" fill="#626262"/>
<path d="M141.6 202.9l.2-.1a.59 .59 0 0 1 .4 .6 .59 .59 0 0 1-.4 .5 .64 .64 0 0 1-.2-1z" fill="none" stroke="#626262" stroke-width=".26"/>
<path d="M142.5 202.9l.3-.1a.64 .64 0 0 1 .3 .6 .64 .64 0 0 1-.3 .5 .6 .6 0 0 1-.5-.4 .6 .6 0 0 1 .2-.6z" fill="#626262"/>
<path d="M142.5 202.9l.3-.1a.64 .64 0 0 1 .3 .6 .64 .64 0 0 1-.3 .5 .6 .6 0 0 1-.5-.4 .6 .6 0 0 1 .2-.6z" fill="none" stroke="#626262" stroke-width=".26"/>
<path d="M143.4 202.9l.2-.1a.64 .64 0 0 1 .4 .6 .64 .64 0 0 1-.4 .5 .6 .6 0 0 1-.4-.4 .6 .6 0 0 1 .2-.6z" fill="#626262"/>
<path d="M143.4 202.9l.2-.1a.64 .64 0 0 1 .4 .6 .64 .64 0 0 1-.4 .5 .6 .6 0 0 1-.4-.4 .6 .6 0 0 1 .2-.6z" fill="none" stroke="#626262" stroke-width=".26"/>
<path d="M144.4 202.9l.1-.1a.64 .64 0 0 1 .4 .6 .64 .64 0 0 1-.4 .5 .64 .64 0 0 1-.1-1z" fill="#626262"/>
<path d="M144.4 202.9l.1-.1a.64 .64 0 0 1 .4 .6 .64 .64 0 0 1-.4 .5 .64 .64 0 0 1-.1-1z" fill="none" stroke="#626262" stroke-width=".26"/>
<path d="M145.2 202.9l.2-.1a.59 .59 0 0 1 .4 .6 .59 .59 0 0 1-.4 .5 .64 .64 0 0 1-.2-1z" fill="#626262"/>
<path d="M145.2 202.9l.2-.1a.59 .59 0 0 1 .4 .6 .59 .59 0 0 1-.4 .5 .64 .64 0 0 1-.2-1z" fill="none" stroke="#626262" stroke-width=".26"/>
<path d="M146.1 202.9l.2-.1a.59 .59 0 0 1 .4 .6 .59 .59 0 0 1-.4 .5 .64 .64 0 0 1-.2-1z" fill="#626262"/>
<path d="M146.1 202.9l.2-.1a.59 .59 0 0 1 .4 .6 .59 .59 0 0 1-.4 .5 .64 .64 0 0 1-.2-1z" fill="none" stroke="#626262" stroke-width=".26"/>
<path d="M146.9 202.9l.2-.1a.59 .59 0 0 1 .4 .6 .59 .59 0 0 1-.4 .5 .64 .64 0 0 1-.2-1z" fill="#626262"/>
<path d="M146.9 202.9l.2-.1a.59 .59 0 0 1 .4 .6 .59 .59 0 0 1-.4 .5 .64 .64 0 0 1-.2-1z" fill="none" stroke="#626262" stroke-width=".26"/>
<path d="M147.8 202.9l.2-.1a.59 .59 0 0 1 .4 .6 .59 .59 0 0 1-.4 .5 .64 .64 0 0 1-.2-1z" fill="#626262"/>
<path d="M147.8 202.9l.2-.1a.59 .59 0 0 1 .4 .6 .59 .59 0 0 1-.4 .5 .64 .64 0 0 1-.2-1z" fill="none" stroke="#626262" stroke-width=".26"/>
<path d="M148.7 202.9l.2-.1a.64 .64 0 0 1 .4 .6 .64 .64 0 0 1-.4 .5 .6 .6 0 0 1-.4-.4 .6 .6 0 0 1 .2-.6z" fill="#626262"/>
<path d="M148.7 202.9l.2-.1a.64 .64 0 0 1 .4 .6 .64 .64 0 0 1-.4 .5 .6 .6 0 0 1-.4-.4 .6 .6 0 0 1 .2-.6z" fill="none" stroke="#626262" stroke-width=".26"/>
<path d="M149.6 202.7l.2-.1a.64 .64 0 0 1 .4 .6 .64 .64 0 0 1-.4 .6 .64 .64 0 0 1-.2-1.1z" fill="#626262"/>
<path d="M149.6 202.7l.2-.1a.64 .64 0 0 1 .4 .6 .64 .64 0 0 1-.4 .6 .64 .64 0 0 1-.2-1.1z" fill="none" stroke="#626262" stroke-width=".26"/>
<path d="M150.5 199.9l.2-.1a.59 .59 0 0 1 .4 .6 .59 .59 0 0 1-.4 .5 .64 .64 0 0 1-.2-1z" fill="#626262"/>
<path d="M150.5 199.9l.2-.1a.59 .59 0 0 1 .4 .6 .59 .59 0 0 1-.4 .5 .64 .64 0 0 1-.2-1z" fill="none" stroke="#626262" stroke-width=".26"/>
<path d="M151.4 196.7l.2-.1a.59 .59 0 0 1 .4 .6 .59 .59 0 0 1-.4 .6 .64 .64 0 0 1-.2-1.1z" fill="#626262"/>
<path d="M151.4 196.7l.2-.1a.59 .59 0 0 1 .4 .6 .59 .59 0 0 1-.4 .6 .64 .64 0 0 1-.2-1.1z" fill="none" stroke="#626262" stroke-width=".26"/>
<path d="M152.3 194.7l.2-.1a.64 .64 0 0 1 .4 .6 .64 .64 0 0 1-.4 .5 .61 .61 0 0 1-.4-.4 .61 .61 0 0 1 .2-.6z" fill="#626262"/>
<path d="M152.3 194.7l.2-.1a.64 .64 0 0 1 .4 .6 .64 .64 0 0 1-.4 .5 .61 .61 0 0 1-.4-.4 .61 .61 0 0 1 .2-.6z" fill="none" stroke="#626262" stroke-width=".26"/>
<path d="M153.2 192.2l.2-.1a.64 .64 0 0 1 .4 .6 .64 .64 0 0 1-.4 .6 .6 .6 0 0 1-.4-.5 .6 .6 0 0 1 .2-.6z" fill="#626262"/>
<path d="M153.2 192.2l.2-.1a.64 .64 0 0 1 .4 .6 .64 .64 0 0 1-.4 .6 .6 .6 0 0 1-.4-.5 .6 .6 0 0 1 .2-.6z" fill="none" stroke="#626262" stroke-width=".26"/>
<path d="M154.1 190.2l.2-.1a.64 .64 0 0 1 .4 .6 .64 .64 0 0 1-.4 .5 .66 .66 0 0 1-.2-1z" fill="#626262"/>
<path d="M154.1 190.2l.2-.1a.64 .64 0 0 1 .4 .6 .64 .64 0 0 1-.4 .5 .66 .66 0 0 1-.2-1z" fill="none" stroke="#626262" stroke-width=".26"/>
<path d="M155 187.9l.2-.1a.59 .59 0 0 1 .4 .6 .59 .59 0 0 1-.4 .5 .64 .64 0 0 1-.2-1z" fill="#626262"/>
<path d="M155 187.9l.2-.1a.59 .59 0 0 1 .4 .6 .59 .59 0 0 1-.4 .5 .64 .64 0 0 1-.2-1z" fill="none" stroke="#626262" stroke-width=".26"/>
<path d="M155.9 185.7l.2-.1a.54 .54 0 0 1 .4 .6 .54 .54 0 0 1-.6 .5 .75 .75 0 0 1 0-1z" fill="#626262"/>
<path d="M155.9 185.7l.2-.1a.54 .54 0 0 1 .4 .6 .54 .54 0 0 1-.6 .5 .75 .75 0 0 1 0-1z" fill="none" stroke="#626262" stroke-width=".26"/>
<path d="M156.8 183.4l.2-.1a.64 .64 0 0 1 .4 .6 .64 .64 0 0 1-.4 .5 .6 .6 0 0 1-.4-.4 .6 .6 0 0 1 .2-.6z" fill="#626262"/>
<path d="M156.8 183.4l.2-.1a.64 .64 0 0 1 .4 .6 .64 .64 0 0 1-.4 .5 .6 .6 0 0 1-.4-.4 .6 .6 0 0 1 .2-.6z" fill="none" stroke="#626262" stroke-width=".26"/>
<path d="M157.7 181.3h.2a.64 .64 0 0 1 .4 .5 .64 .64 0 0 1-.4 .6 .66 .66 0 0 1-.2-1.1z" fill="#626262"/>
<path d="M157.7 181.3h.2a.64 .64 0 0 1 .4 .5 .64 .64 0 0 1-.4 .6 .66 .66 0 0 1-.2-1.1z" fill="none" stroke="#626262" stroke-width=".26"/>
<path d="M158.6 179.5a.49 .49 0 0 1 .6 .4 .49 .49 0 0 1-.6 .5 .7 .7 0 0 1 0-.9z" fill="#626262"/>
<path d="M158.6 179.5a.49 .49 0 0 1 .6 .4 .49 .49 0 0 1-.6 .5 .7 .7 0 0 1 0-.9z" fill="none" stroke="#626262" stroke-width=".26"/>
<path d="M159.5 177.6l.2-.1a.59 .59 0 0 1 .4 .5 .59 .59 0 0 1-.4 .6 .64 .64 0 0 1-.2-1z" fill="#626262"/>
<path d="M159.5 177.6l.2-.1a.59 .59 0 0 1 .4 .5 .59 .59 0 0 1-.4 .6 .64 .64 0 0 1-.2-1z" fill="none" stroke="#626262" stroke-width=".26"/>
<path d="M160.4 176.2l.2-.1a.64 .64 0 0 1 .4 .6 .64 .64 0 0 1-.4 .6 .6 .6 0 0 1-.4-.5 .6 .6 0 0 1 .2-.6z" fill="#626262"/>
<path d="M160.4 176.2l.2-.1a.64 .64 0 0 1 .4 .6 .64 .64 0 0 1-.4 .6 .6 .6 0 0 1-.4-.5 .6 .6 0 0 1 .2-.6z" fill="none" stroke="#626262" stroke-width=".26"/>
<path d="M161.3 175.2l.2-.1a.52 .52 0 0 1 .4 .6 .52 .52 0 0 1-.6 .4 .61 .61 0 0 1 0-.9z" fill="#626262"/>
<path d="M161.3 175.2l.2-.1a.52 .52 0 0 1 .4 .6 .52 .52 0 0 1-.6 .4 .61 .61 0 0 1 0-.9z" fill="none" stroke="#626262" stroke-width=".26"/>
<path d="M162.2 174.4l.2-.1a.64 .64 0 0 1 .4 .6 .64 .64 0 0 1-.4 .5 .64 .64 0 0 1-.2-1z" fill="#626262"/>
<path d="M162.2 174.4l.2-.1a.64 .64 0 0 1 .4 .6 .64 .64 0 0 1-.4 .5 .64 .64 0 0 1-.2-1z" fill="none" stroke="#626262" stroke-width=".26"/>
<path d="M163.1 173.7l.2-.1a.51 .51 0 0 1 .4 .6 .51 .51 0 0 1-.6 .4 .67 .67 0 0 1 0-.9z" fill="#626262"/>
<path d="M163.1 173.7l.2-.1a.51 .51 0 0 1 .4 .6 .51 .51 0 0 1-.6 .4 .67 .67 0 0 1 0-.9z" fill="none" stroke="#626262" stroke-width=".26"/>
<path d="M164 173.2l.3-.1a.64 .64 0 0 1 .3 .6 .64 .64 0 0 1-.3 .6 .6 .6 0 0 1-.5-.5 .6 .6 0 0 1 .2-.6z" fill="#626262"/>
<path d="M164 173.2l.3-.1a.64 .64 0 0 1 .3 .6 .64 .64 0 0 1-.3 .6 .6 .6 0 0 1-.5-.5 .6 .6 0 0 1 .2-.6z" fill="none" stroke="#626262" stroke-width=".26"/>
<path d="M164.8 172.7l.2-.1a.54 .54 0 0 1 .4 .6 .54 .54 0 0 1-.6 .5 .75 .75 0 0 1 0-1z" fill="#626262"/>
<path d="M164.8 172.7l.2-.1a.54 .54 0 0 1 .4 .6 .54 .54 0 0 1-.6 .5 .75 .75 0 0 1 0-1z" fill="none" stroke="#626262" stroke-width=".26"/>
<path d="M165.7 172.5l.1-.1a.54 .54 0 0 1 .5 .7 .54 .54 0 0 1-.6 .4 .75 .75 0 0 1 0-1z" fill="#626262"/>
<path d="M165.7 172.5l.1-.1a.54 .54 0 0 1 .5 .7 .54 .54 0 0 1-.6 .4 .75 .75 0 0 1 0-1z" fill="none" stroke="#626262" stroke-width=".26"/>
<path d="M166.6 172.3h.2a.64 .64 0 0 1 .4 .5 .64 .64 0 0 1-.4 .6 .61 .61 0 0 1-.4-.5 .61 .61 0 0 1 .2-.6z" fill="#626262"/>
<path d="M166.6 172.3h.2a.64 .64 0 0 1 .4 .5 .64 .64 0 0 1-.4 .6 .61 .61 0 0 1-.4-.5 .61 .61 0 0 1 .2-.6z" fill="none" stroke="#626262" stroke-width=".26"/>
<path d="M167.5 172.2l.2-.1a.51 .51 0 0 1 .3 .6 .51 .51 0 0 1-.5 .4 .67 .67 0 0 1 0-.9z" fill="#626262"/>
<path d="M167.5 172.2l.2-.1a.51 .51 0 0 1 .3 .6 .51 .51 0 0 1-.5 .4 .67 .67 0 0 1 0-.9z" fill="none" stroke="#626262" stroke-width=".26"/>
<path d="M168.4 172h.4a.57 .57 0 0 1 .2 .5 .57 .57 0 0 1-.4 .5 .6 .6 0 0 1-.2-1z" fill="#626262"/>
<path d="M168.4 172h.4a.57 .57 0 0 1 .2 .5 .57 .57 0 0 1-.4 .5 .6 .6 0 0 1-.2-1z" fill="none" stroke="#626262" stroke-width=".26"/>
<path d="M169.3 171.7l.2-.1a.59 .59 0 0 1 .4 .6 .59 .59 0 0 1-.4 .6 .64 .64 0 0 1-.2-1.1z" fill="#626262"/>
<path d="M169.3 171.7l.2-.1a.59 .59 0 0 1 .4 .6 .59 .59 0 0 1-.4 .6 .64 .64 0 0 1-.2-1.1z" fill="none" stroke="#626262" stroke-width=".26"/>
<path d="M170.2 171.6l.2-.1a.64 .64 0 0 1 .4 .5 .64 .64 0 0 1-.4 .6 .6 .6 0 0 1-.4-.4 .6 .6 0 0 1 .2-.6z" fill="#626262"/>
<path d="M170.2 171.6l.2-.1a.64 .64 0 0 1 .4 .5 .64 .64 0 0 1-.4 .6 .6 .6 0 0 1-.4-.4 .6 .6 0 0 1 .2-.6z" fill="none" stroke="#626262" stroke-width=".26"/>
<path d="M171.1 171.6l.2-.1a.64 .64 0 0 1 .4 .5 .64 .64 0 0 1-.4 .6 .6 .6 0 0 1-.5-.4 .6 .6 0 0 1 .3-.6z" fill="#626262"/>
<path d="M171.1 171.6l.2-.1a.64 .64 0 0 1 .4 .5 .64 .64 0 0 1-.4 .6 .6 .6 0 0 1-.5-.4 .6 .6 0 0 1 .3-.6z" fill="none" stroke="#626262" stroke-width=".26"/>
<path d="M172 171.6l.2-.1a.64 .64 0 0 1 .3 .5 .64 .64 0 0 1-.3 .6 .64 .64 0 0 1-.2-1z" fill="#626262"/>
<path d="M172 171.6l.2-.1a.64 .64 0 0 1 .3 .5 .64 .64 0 0 1-.3 .6 .64 .64 0 0 1-.2-1z" fill="none" stroke="#626262" stroke-width=".26"/>
<path d="M172.9 171.4l.2-.1a.59 .59 0 0 1 .4 .6 .59 .59 0 0 1-.4 .5 .64 .64 0 0 1-.2-1z" fill="#626262"/>
<path d="M172.9 171.4l.2-.1a.59 .59 0 0 1 .4 .6 .59 .59 0 0 1-.4 .5 .64 .64 0 0 1-.2-1z" fill="none" stroke="#626262" stroke-width=".26"/>
<path d="M173.8 171.4l.1-.1a.59 .59 0 0 1 .5 .6 .59 .59 0 0 1-.5 .5 .64 .64 0 0 1-.1-1z" fill="#626262"/>
<path d="M173.8 171.4l.1-.1a.59 .59 0 0 1 .5 .6 .59 .59 0 0 1-.5 .5 .64 .64 0 0 1-.1-1z" fill="none" stroke="#626262" stroke-width=".26"/>
<path d="M174.7 171.4l.2-.1a.64 .64 0 0 1 .4 .6 .64 .64 0 0 1-.4 .5 .6 .6 0 0 1-.4-.4 .6 .6 0 0 1 .2-.6z" fill="#626262"/>
<path d="M174.7 171.4l.2-.1a.64 .64 0 0 1 .4 .6 .64 .64 0 0 1-.4 .5 .6 .6 0 0 1-.4-.4 .6 .6 0 0 1 .2-.6z" fill="none" stroke="#626262" stroke-width=".26"/>
<path d="M175.6 171.4l.2-.1a.64 .64 0 0 1 .3 .6 .64 .64 0 0 1-.3 .5 .64 .64 0 0 1-.2-1z" fill="#626262"/>
<path d="M175.6 171.4l.2-.1a.64 .64 0 0 1 .3 .6 .64 .64 0 0 1-.3 .5 .64 .64 0 0 1-.2-1z" fill="none" stroke="#626262" stroke-width=".26"/>
<path d="M176.5 171.4l.2-.1a.59 .59 0 0 1 .4 .6 .59 .59 0 0 1-.4 .5 .64 .64 0 0 1-.2-1z" fill="#626262"/>
<path d="M176.5 171.4l.2-.1a.59 .59 0 0 1 .4 .6 .59 .59 0 0 1-.4 .5 .64 .64 0 0 1-.2-1z" fill="none" stroke="#626262" stroke-width=".26"/>
<path d="M177.4 171.2l.2-.1a.54 .54 0 0 1 .4 .6 .54 .54 0 0 1-.6 .5 .75 .75 0 0 1 0-1z" fill="#626262"/>
<path d="M177.4 171.2l.2-.1a.54 .54 0 0 1 .4 .6 .54 .54 0 0 1-.6 .5 .75 .75 0 0 1 0-1z" fill="none" stroke="#626262" stroke-width=".26"/>
<path d="M178.3 171.2l.2-.1a.64 .64 0 0 1 .4 .6 .64 .64 0 0 1-.4 .6 .61 .61 0 0 1-.4-.5 .61 .61 0 0 1 .2-.6z" fill="#626262"/>
<path d="M178.3 171.2l.2-.1a.64 .64 0 0 1 .4 .6 .64 .64 0 0 1-.4 .6 .61 .61 0 0 1-.4-.5 .61 .61 0 0 1 .2-.6z" fill="none" stroke="#626262" stroke-width=".26"/>
<path d="M179.2 171.2l.2-.1a.64 .64 0 0 1 .4 .6 .64 .64 0 0 1-.4 .6 .61 .61 0 0 1-.4-.5 .61 .61 0 0 1 .2-.6z" fill="#626262"/>
<path d="M179.2 171.2l.2-.1a.64 .64 0 0 1 .4 .6 .64 .64 0 0 1-.4 .6 .61 .61 0 0 1-.4-.5 .61 .61 0 0 1 .2-.6z" fill="none" stroke="#626262" stroke-width=".26"/>
<path d="M180.1 171.2l.2-.1a.64 .64 0 0 1 .3 .6 .64 .64 0 0 1-.3 .6 .66 .66 0 0 1-.2-1.1z" fill="#626262"/>
<path d="M180.1 171.2l.2-.1a.64 .64 0 0 1 .3 .6 .64 .64 0 0 1-.3 .6 .66 .66 0 0 1-.2-1.1z" fill="none" stroke="#626262" stroke-width=".26"/>
<path d="M181 171.2l.2-.1a.54 .54 0 0 1 .4 .6 .54 .54 0 0 1-.6 .5 .75 .75 0 0 1 0-1z" fill="#626262"/>
<path d="M181 171.2l.2-.1a.54 .54 0 0 1 .4 .6 .54 .54 0 0 1-.6 .5 .75 .75 0 0 1 0-1z" fill="none" stroke="#626262" stroke-width=".26"/>
<path d="M181.9 171.2l.2-.1a.64 .64 0 0 1 .4 .6 .64 .64 0 0 1-.4 .6 .61 .61 0 0 1-.4-.5 .61 .61 0 0 1 .2-.6z" fill="#626262"/>
<path d="M181.9 171.2l.2-.1a.64 .64 0 0 1 .4 .6 .64 .64 0 0 1-.4 .6 .61 .61 0 0 1-.4-.5 .61 .61 0 0 1 .2-.6z" fill="none" stroke="#626262" stroke-width=".26"/>
<path d="M182.7 171.2l.1-.1a.54 .54 0 0 1 .5 .6 .54 .54 0 0 1-.6 .5 .75 .75 0 0 1 0-1z" fill="#626262"/>
<path d="M182.7 171.2l.1-.1a.54 .54 0 0 1 .5 .6 .54 .54 0 0 1-.6 .5 .75 .75 0 0 1 0-1z" fill="none" stroke="#626262" stroke-width=".26"/>
<path d="M183.6 171.2l.1-.1a.54 .54 0 0 1 .5 .6 .54 .54 0 0 1-.6 .5 .75 .75 0 0 1 0-1z" fill="#626262"/>
<path d="M183.6 171.2l.1-.1a.54 .54 0 0 1 .5 .6 .54 .54 0 0 1-.6 .5 .75 .75 0 0 1 0-1z" fill="none" stroke="#626262" stroke-width=".26"/>
<path d="M184.5 171.2l.2-.1a.64 .64 0 0 1 .3 .6 .64 .64 0 0 1-.3 .6 .61 .61 0 0 1-.5-.5 .61 .61 0 0 1 .3-.6z" fill="#626262"/>
<path d="M184.5 171.2l.2-.1a.64 .64 0 0 1 .3 .6 .64 .64 0 0 1-.3 .6 .61 .61 0 0 1-.5-.5 .61 .61 0 0 1 .3-.6z" fill="none" stroke="#626262" stroke-width=".26"/>
<path d="M185.4 171.2l.2-.1a.64 .64 0 0 1 .3 .6 .64 .64 0 0 1-.3 .6 .66 .66 0 0 1-.2-1.1z" fill="#626262"/>
<path d="M185.4 171.2l.2-.1a.64 .64 0 0 1 .3 .6 .64 .64 0 0 1-.3 .6 .66 .66 0 0 1-.2-1.1z" fill="none" stroke="#626262" stroke-width=".26"/>
<path d="M186.3 171.2l.2-.1a.54 .54 0 0 1 .4 .6 .54 .54 0 0 1-.6 .5 .75 .75 0 0 1 0-1z" fill="#626262"/>
<path d="M186.3 171.2l.2-.1a.54 .54 0 0 1 .4 .6 .54 .54 0 0 1-.6 .5 .75 .75 0 0 1 0-1z" fill="none" stroke="#626262" stroke-width=".26"/>
<path d="M187.2 171.2l.1-.1a.54 .54 0 0 1 .5 .6 .54 .54 0 0 1-.6 .5 .75 .75 0 0 1 0-1z" fill="#626262"/>
<path d="M187.2 171.2l.1-.1a.54 .54 0 0 1 .5 .6 .54 .54 0 0 1-.6 .5 .75 .75 0 0 1 0-1z" fill="none" stroke="#626262" stroke-width=".26"/>
<path d="M188.1 171.2l.2-.1a.64 .64 0 0 1 .4 .6 .64 .64 0 0 1-.4 .6 .61 .61 0 0 1-.4-.5 .61 .61 0 0 1 .2-.6z" fill="#626262"/>
<path d="M188.1 171.2l.2-.1a.64 .64 0 0 1 .4 .6 .64 .64 0 0 1-.4 .6 .61 .61 0 0 1-.4-.5 .61 .61 0 0 1 .2-.6z" fill="none" stroke="#626262" stroke-width=".26"/>
<path d="M189 171.2l.2-.1a.64 .64 0 0 1 .3 .6 .64 .64 0 0 1-.3 .6 .61 .61 0 0 1-.5-.5 .61 .61 0 0 1 .3-.6z" fill="#626262"/>
<path d="M189 171.2l.2-.1a.64 .64 0 0 1 .3 .6 .64 .64 0 0 1-.3 .6 .61 .61 0 0 1-.5-.5 .61 .61 0 0 1 .3-.6z" fill="none" stroke="#626262" stroke-width=".26"/>
<path d="M189.9 171.2l.2-.1a.64 .64 0 0 1 .3 .6 .64 .64 0 0 1-.3 .6 .66 .66 0 0 1-.2-1.1z" fill="#626262"/>
<path d="M189.9 171.2l.2-.1a.64 .64 0 0 1 .3 .6 .64 .64 0 0 1-.3 .6 .66 .66 0 0 1-.2-1.1z" fill="none" stroke="#626262" stroke-width=".26"/>
<path d="M190.8 171.2l.1-.1a.54 .54 0 0 1 .5 .6 .54 .54 0 0 1-.6 .5 .75 .75 0 0 1 0-1z" fill="#626262"/>
<path d="M190.8 171.2l.1-.1a.54 .54 0 0 1 .5 .6 .54 .54 0 0 1-.6 .5 .75 .75 0 0 1 0-1z" fill="none" stroke="#626262" stroke-width=".26"/>
<path d="M191.7 171.2l.1-.1a.54 .54 0 0 1 .5 .6 .54 .54 0 0 1-.6 .5 .75 .75 0 0 1 0-1z" fill="#626262"/>
<path d="M191.7 171.2l.1-.1a.54 .54 0 0 1 .5 .6 .54 .54 0 0 1-.6 .5 .75 .75 0 0 1 0-1z" fill="none" stroke="#626262" stroke-width=".26"/>
<path d="M192.6 171.2l.2-.1a.64 .64 0 0 1 .4 .6 .64 .64 0 0 1-.4 .6 .61 .61 0 0 1-.4-.5 .61 .61 0 0 1 .2-.6z" fill="#626262"/>
<path d="M192.6 171.2l.2-.1a.64 .64 0 0 1 .4 .6 .64 .64 0 0 1-.4 .6 .61 .61 0 0 1-.4-.5 .61 .61 0 0 1 .2-.6z" fill="none" stroke="#626262" stroke-width=".26"/>
<path d="M192.7 171.7l-17 .1-3.5 .2-4.5 .5a11.2 11.2 0 0 0-8.5 5 77.2 77.2 0 0 0-4.6 11l-1.4 3.8a63.5 63.5 0 0 0-3.3 10.6l-.1 .3a.65 .65 0 0 1-.9 .3h-18.7" fill="none" stroke="#997300" stroke-width=".44"/>
<path d="M192.7 171.7l-17 .1-3.5 .2-4.2 .5a11.1 11.1 0 0 0-7.7 4 32.3 32.3 0 0 0-3.5 7.1l-3.6 9.1a58.7 58.7 0 0 0-3.3 10.2l-.1 .3a.65 .65 0 0 1-.9 .3h-18.7" fill="none" stroke="#264478" stroke-width=".44"/>
<path d="M192.7 171.7l-16.4 .1-5.1 .3-2.6 .3a11.5 11.5 0 0 0-8 4.1 31.2 31.2 0 0 0-4 8.1l-3.4 8.5a48.9 48.9 0 0 0-3.1 9.4 .88 .88 0 0 1-1 .9l-18.9 .1" fill="none" stroke="#43682b" stroke-width=".44"/>
<path d="M129.9 202.9l.2-.1a.59 .59 0 0 1 .4 .6 .59 .59 0 0 1-.4 .5 .64 .64 0 0 1-.2-1z" fill="#43682b"/>
<path d="M129.9 202.9l.2-.1a.59 .59 0 0 1 .4 .6 .59 .59 0 0 1-.4 .5 .64 .64 0 0 1-.2-1z" fill="none" stroke="#43682b" stroke-width=".26"/>
<path d="M130.8 202.9l.2-.1a.64 .64 0 0 1 .4 .6 .64 .64 0 0 1-.4 .5 .6 .6 0 0 1-.4-.4 .6 .6 0 0 1 .2-.6z" fill="#43682b"/>
<path d="M130.8 202.9l.2-.1a.64 .64 0 0 1 .4 .6 .64 .64 0 0 1-.4 .5 .6 .6 0 0 1-.4-.4 .6 .6 0 0 1 .2-.6z" fill="none" stroke="#43682b" stroke-width=".26"/>
<path d="M131.8 202.9l.1-.1a.64 .64 0 0 1 .4 .6 .64 .64 0 0 1-.4 .5 .64 .64 0 0 1-.1-1z" fill="#43682b"/>
<path d="M131.8 202.9l.1-.1a.64 .64 0 0 1 .4 .6 .64 .64 0 0 1-.4 .5 .64 .64 0 0 1-.1-1z" fill="none" stroke="#43682b" stroke-width=".26"/>
<path d="M132.6 202.9l.2-.1a.59 .59 0 0 1 .4 .6 .59 .59 0 0 1-.4 .5 .64 .64 0 0 1-.2-1z" fill="#43682b"/>
<path d="M132.6 202.9l.2-.1a.59 .59 0 0 1 .4 .6 .59 .59 0 0 1-.4 .5 .64 .64 0 0 1-.2-1z" fill="none" stroke="#43682b" stroke-width=".26"/>
<path d="M133.5 202.9l.2-.1a.59 .59 0 0 1 .4 .6 .59 .59 0 0 1-.4 .5 .64 .64 0 0 1-.2-1z" fill="#43682b"/>
<path d="M133.5 202.9l.2-.1a.59 .59 0 0 1 .4 .6 .59 .59 0 0 1-.4 .5 .64 .64 0 0 1-.2-1z" fill="none" stroke="#43682b" stroke-width=".26"/>
<path d="M134.4 202.9l.3-.1a.64 .64 0 0 1 .3 .6 .64 .64 0 0 1-.3 .5 .6 .6 0 0 1-.5-.4 .6 .6 0 0 1 .2-.6z" fill="#43682b"/>
<path d="M134.4 202.9l.3-.1a.64 .64 0 0 1 .3 .6 .64 .64 0 0 1-.3 .5 .6 .6 0 0 1-.5-.4 .6 .6 0 0 1 .2-.6z" fill="none" stroke="#43682b" stroke-width=".26"/>
<path d="M135.3 202.9l.2-.1a.64 .64 0 0 1 .4 .6 .64 .64 0 0 1-.4 .5 .6 .6 0 0 1-.4-.4 .6 .6 0 0 1 .2-.6z" fill="#43682b"/>
<path d="M135.3 202.9l.2-.1a.64 .64 0 0 1 .4 .6 .64 .64 0 0 1-.4 .5 .6 .6 0 0 1-.4-.4 .6 .6 0 0 1 .2-.6z" fill="none" stroke="#43682b" stroke-width=".26"/>
<path d="M136.2 202.9l.2-.1a.64 .64 0 0 1 .4 .6 .64 .64 0 0 1-.4 .5 .64 .64 0 0 1-.2-1z" fill="#43682b"/>
<path d="M136.2 202.9l.2-.1a.64 .64 0 0 1 .4 .6 .64 .64 0 0 1-.4 .5 .64 .64 0 0 1-.2-1z" fill="none" stroke="#43682b" stroke-width=".26"/>
<path d="M137.1 202.9l.2-.1a.59 .59 0 0 1 .4 .6 .59 .59 0 0 1-.4 .5 .64 .64 0 0 1-.2-1z" fill="#43682b"/>
<path d="M137.1 202.9l.2-.1a.59 .59 0 0 1 .4 .6 .59 .59 0 0 1-.4 .5 .64 .64 0 0 1-.2-1z" fill="none" stroke="#43682b" stroke-width=".26"/>
<path d="M138 202.9l.2-.1a.59 .59 0 0 1 .4 .6 .59 .59 0 0 1-.4 .5 .64 .64 0 0 1-.2-1z" fill="#43682b"/>
<path d="M138 202.9l.2-.1a.59 .59 0 0 1 .4 .6 .59 .59 0 0 1-.4 .5 .64 .64 0 0 1-.2-1z" fill="none" stroke="#43682b" stroke-width=".26"/>
<path d="M138.9 202.9l.2-.1a.64 .64 0 0 1 .4 .6 .64 .64 0 0 1-.4 .5 .6 .6 0 0 1-.4-.4 .6 .6 0 0 1 .2-.6z" fill="#43682b"/>
<path d="M138.9 202.9l.2-.1a.64 .64 0 0 1 .4 .6 .64 .64 0 0 1-.4 .5 .6 .6 0 0 1-.4-.4 .6 .6 0 0 1 .2-.6z" fill="none" stroke="#43682b" stroke-width=".26"/>
<path d="M139.9 202.9l.1-.1a.64 .64 0 0 1 .4 .6 .64 .64 0 0 1-.4 .5 .64 .64 0 0 1-.1-1z" fill="#43682b"/>
<path d="M139.9 202.9l.1-.1a.64 .64 0 0 1 .4 .6 .64 .64 0 0 1-.4 .5 .64 .64 0 0 1-.1-1z" fill="none" stroke="#43682b" stroke-width=".26"/>
<path d="M140.7 202.9l.2-.1a.59 .59 0 0 1 .5 .6 .59 .59 0 0 1-.5 .5 .64 .64 0 0 1-.2-1z" fill="#43682b"/>
<path d="M140.7 202.9l.2-.1a.59 .59 0 0 1 .5 .6 .59 .59 0 0 1-.5 .5 .64 .64 0 0 1-.2-1z" fill="none" stroke="#43682b" stroke-width=".26"/>
<path d="M141.6 202.9l.2-.1a.59 .59 0 0 1 .4 .6 .59 .59 0 0 1-.4 .5 .64 .64 0 0 1-.2-1z" fill="#43682b"/>
<path d="M141.6 202.9l.2-.1a.59 .59 0 0 1 .4 .6 .59 .59 0 0 1-.4 .5 .64 .64 0 0 1-.2-1z" fill="none" stroke="#43682b" stroke-width=".26"/>
<path d="M142.5 202.9l.3-.1a.64 .64 0 0 1 .3 .6 .64 .64 0 0 1-.3 .5 .6 .6 0 0 1-.5-.4 .6 .6 0 0 1 .2-.6z" fill="#43682b"/>
<path d="M142.5 202.9l.3-.1a.64 .64 0 0 1 .3 .6 .64 .64 0 0 1-.3 .5 .6 .6 0 0 1-.5-.4 .6 .6 0 0 1 .2-.6z" fill="none" stroke="#43682b" stroke-width=".26"/>
<path d="M143.4 202.9l.2-.1a.64 .64 0 0 1 .4 .6 .64 .64 0 0 1-.4 .5 .6 .6 0 0 1-.4-.4 .6 .6 0 0 1 .2-.6z" fill="#43682b"/>
<path d="M143.4 202.9l.2-.1a.64 .64 0 0 1 .4 .6 .64 .64 0 0 1-.4 .5 .6 .6 0 0 1-.4-.4 .6 .6 0 0 1 .2-.6z" fill="none" stroke="#43682b" stroke-width=".26"/>
<path d="M144.4 202.9l.1-.1a.64 .64 0 0 1 .4 .6 .64 .64 0 0 1-.4 .5 .64 .64 0 0 1-.1-1z" fill="#43682b"/>
<path d="M144.4 202.9l.1-.1a.64 .64 0 0 1 .4 .6 .64 .64 0 0 1-.4 .5 .64 .64 0 0 1-.1-1z" fill="none" stroke="#43682b" stroke-width=".26"/>
<path d="M145.2 202.9l.2-.1a.59 .59 0 0 1 .4 .6 .59 .59 0 0 1-.4 .5 .64 .64 0 0 1-.2-1z" fill="#43682b"/>
<path d="M145.2 202.9l.2-.1a.59 .59 0 0 1 .4 .6 .59 .59 0 0 1-.4 .5 .64 .64 0 0 1-.2-1z" fill="none" stroke="#43682b" stroke-width=".26"/>
<path d="M146.1 202.9l.2-.1a.59 .59 0 0 1 .4 .6 .59 .59 0 0 1-.4 .5 .64 .64 0 0 1-.2-1z" fill="#43682b"/>
<path d="M146.1 202.9l.2-.1a.59 .59 0 0 1 .4 .6 .59 .59 0 0 1-.4 .5 .64 .64 0 0 1-.2-1z" fill="none" stroke="#43682b" stroke-width=".26"/>
<path d="M146.9 202.9l.2-.1a.59 .59 0 0 1 .4 .6 .59 .59 0 0 1-.4 .5 .64 .64 0 0 1-.2-1z" fill="#43682b"/>
<path d="M146.9 202.9l.2-.1a.59 .59 0 0 1 .4 .6 .59 .59 0 0 1-.4 .5 .64 .64 0 0 1-.2-1z" fill="none" stroke="#43682b" stroke-width=".26"/>
<path d="M147.8 202.9l.2-.1a.59 .59 0 0 1 .4 .6 .59 .59 0 0 1-.4 .5 .64 .64 0 0 1-.2-1z" fill="#43682b"/>
<path d="M147.8 202.9l.2-.1a.59 .59 0 0 1 .4 .6 .59 .59 0 0 1-.4 .5 .64 .64 0 0 1-.2-1z" fill="none" stroke="#43682b" stroke-width=".26"/>
<path d="M148.7 202.9l.2-.1a.64 .64 0 0 1 .4 .6 .64 .64 0 0 1-.4 .5 .6 .6 0 0 1-.4-.4 .6 .6 0 0 1 .2-.6z" fill="#43682b"/>
<path d="M148.7 202.9l.2-.1a.64 .64 0 0 1 .4 .6 .64 .64 0 0 1-.4 .5 .6 .6 0 0 1-.4-.4 .6 .6 0 0 1 .2-.6z" fill="none" stroke="#43682b" stroke-width=".26"/>
<path d="M149.6 202.7l.2-.1a.64 .64 0 0 1 .4 .6 .64 .64 0 0 1-.4 .6 .64 .64 0 0 1-.2-1.1z" fill="#43682b"/>
<path d="M149.6 202.7l.2-.1a.64 .64 0 0 1 .4 .6 .64 .64 0 0 1-.4 .6 .64 .64 0 0 1-.2-1.1z" fill="none" stroke="#43682b" stroke-width=".26"/>
<path d="M150.5 200h.2a.59 .59 0 0 1 .4 .5 .59 .59 0 0 1-.4 .6 .64 .64 0 0 1-.2-1.1z" fill="#43682b"/>
<path d="M150.5 200h.2a.59 .59 0 0 1 .4 .5 .59 .59 0 0 1-.4 .6 .64 .64 0 0 1-.2-1.1z" fill="none" stroke="#43682b" stroke-width=".26"/>
<path d="M151.4 196.7l.2-.1a.59 .59 0 0 1 .4 .6 .59 .59 0 0 1-.4 .6 .64 .64 0 0 1-.2-1.1z" fill="#43682b"/>
<path d="M151.4 196.7l.2-.1a.59 .59 0 0 1 .4 .6 .59 .59 0 0 1-.4 .6 .64 .64 0 0 1-.2-1.1z" fill="none" stroke="#43682b" stroke-width=".26"/>
<path d="M152.3 194.7l.2-.1a.64 .64 0 0 1 .4 .6 .64 .64 0 0 1-.4 .5 .61 .61 0 0 1-.4-.4 .61 .61 0 0 1 .2-.6z" fill="#43682b"/>
<path d="M152.3 194.7l.2-.1a.64 .64 0 0 1 .4 .6 .64 .64 0 0 1-.4 .5 .61 .61 0 0 1-.4-.4 .61 .61 0 0 1 .2-.6z" fill="none" stroke="#43682b" stroke-width=".26"/>
<path d="M153.2 192.2l.2-.1a.64 .64 0 0 1 .4 .6 .64 .64 0 0 1-.4 .6 .6 .6 0 0 1-.4-.5 .6 .6 0 0 1 .2-.6z" fill="#43682b"/>
<path d="M153.2 192.2l.2-.1a.64 .64 0 0 1 .4 .6 .64 .64 0 0 1-.4 .6 .6 .6 0 0 1-.4-.5 .6 .6 0 0 1 .2-.6z" fill="none" stroke="#43682b" stroke-width=".26"/>
<path d="M154.1 190l.2-.1a.51 .51 0 0 1 .3 .6 .51 .51 0 0 1-.5 .4 .7 .7 0 0 1 0-.9z" fill="#43682b"/>
<path d="M154.1 190l.2-.1a.51 .51 0 0 1 .3 .6 .51 .51 0 0 1-.5 .4 .7 .7 0 0 1 0-.9z" fill="none" stroke="#43682b" stroke-width=".26"/>
<path d="M155 187.7l.2-.1a.59 .59 0 0 1 .4 .6 .59 .59 0 0 1-.4 .6 .64 .64 0 0 1-.2-1.1z" fill="#43682b"/>
<path d="M155 187.7l.2-.1a.59 .59 0 0 1 .4 .6 .59 .59 0 0 1-.4 .6 .64 .64 0 0 1-.2-1.1z" fill="none" stroke="#43682b" stroke-width=".26"/>
<path d="M155.9 185.5a.49 .49 0 0 1 .6 .4 .49 .49 0 0 1-.6 .5 .7 .7 0 0 1 0-.9z" fill="#43682b"/>
<path d="M155.9 185.5a.49 .49 0 0 1 .6 .4 .49 .49 0 0 1-.6 .5 .7 .7 0 0 1 0-.9z" fill="none" stroke="#43682b" stroke-width=".26"/>
<path d="M156.8 183.2l.2-.1a.64 .64 0 0 1 .4 .6 .64 .64 0 0 1-.4 .6 .61 .61 0 0 1-.4-.5 .61 .61 0 0 1 .2-.6z" fill="#43682b"/>
<path d="M156.8 183.2l.2-.1a.64 .64 0 0 1 .4 .6 .64 .64 0 0 1-.4 .6 .61 .61 0 0 1-.4-.5 .61 .61 0 0 1 .2-.6z" fill="none" stroke="#43682b" stroke-width=".26"/>
<path d="M157.7 181l.2-.1a.51 .51 0 0 1 .4 .6 .51 .51 0 0 1-.6 .4 .7 .7 0 0 1 0-.9z" fill="#43682b"/>
<path d="M157.7 181l.2-.1a.51 .51 0 0 1 .4 .6 .51 .51 0 0 1-.6 .4 .7 .7 0 0 1 0-.9z" fill="none" stroke="#43682b" stroke-width=".26"/>
<path d="M158.6 178.9l.2-.1a.59 .59 0 0 1 .4 .6 .59 .59 0 0 1-.4 .5 .64 .64 0 0 1-.2-1z" fill="#43682b"/>
<path d="M158.6 178.9l.2-.1a.59 .59 0 0 1 .4 .6 .59 .59 0 0 1-.4 .5 .64 .64 0 0 1-.2-1z" fill="none" stroke="#43682b" stroke-width=".26"/>
<path d="M159.5 177.2l.2-.1a.54 .54 0 0 1 .4 .6 .54 .54 0 0 1-.6 .5 .75 .75 0 0 1 0-1z" fill="#43682b"/>
<path d="M159.5 177.2l.2-.1a.54 .54 0 0 1 .4 .6 .54 .54 0 0 1-.6 .5 .75 .75 0 0 1 0-1z" fill="none" stroke="#43682b" stroke-width=".26"/>
<path d="M160.4 175.9l.2-.1a.64 .64 0 0 1 .4 .6 .64 .64 0 0 1-.4 .5 .6 .6 0 0 1-.4-.4 .6 .6 0 0 1 .2-.6z" fill="#43682b"/>
<path d="M160.4 175.9l.2-.1a.64 .64 0 0 1 .4 .6 .64 .64 0 0 1-.4 .5 .6 .6 0 0 1-.4-.4 .6 .6 0 0 1 .2-.6z" fill="none" stroke="#43682b" stroke-width=".26"/>
<path d="M161.3 175l.2-.1a.5 .5 0 0 1 .4 .6 .5 .5 0 0 1-.6 .4 .61 .61 0 0 1 0-.9z" fill="#43682b"/>
<path d="M161.3 175l.2-.1a.5 .5 0 0 1 .4 .6 .5 .5 0 0 1-.6 .4 .61 .61 0 0 1 0-.9z" fill="none" stroke="#43682b" stroke-width=".26"/>
<path d="M162.2 174.2l.2-.1a.64 .64 0 0 1 .4 .6 .64 .64 0 0 1-.4 .6 .66 .66 0 0 1-.2-1.1z" fill="#43682b"/>
<path d="M162.2 174.2l.2-.1a.64 .64 0 0 1 .4 .6 .64 .64 0 0 1-.4 .6 .66 .66 0 0 1-.2-1.1z" fill="none" stroke="#43682b" stroke-width=".26"/>
<path d="M163.1 173.7l.2-.1a.51 .51 0 0 1 .4 .6 .51 .51 0 0 1-.6 .4 .67 .67 0 0 1 0-.9z" fill="#43682b"/>
<path d="M163.1 173.7l.2-.1a.51 .51 0 0 1 .4 .6 .51 .51 0 0 1-.6 .4 .67 .67 0 0 1 0-.9z" fill="none" stroke="#43682b" stroke-width=".26"/>
<path d="M164 173h.3a.64 .64 0 0 1 .3 .5 .64 .64 0 0 1-.3 .6 .6 .6 0 0 1-.5-.4 .6 .6 0 0 1 .2-.7z" fill="#43682b"/>
<path d="M164 173h.3a.64 .64 0 0 1 .3 .5 .64 .64 0 0 1-.3 .6 .6 .6 0 0 1-.5-.4 .6 .6 0 0 1 .2-.7z" fill="none" stroke="#43682b" stroke-width=".26"/>
<path d="M164.8 172.7l.2-.1a.54 .54 0 0 1 .4 .6 .54 .54 0 0 1-.6 .5 .75 .75 0 0 1 0-1z" fill="#43682b"/>
<path d="M164.8 172.7l.2-.1a.54 .54 0 0 1 .4 .6 .54 .54 0 0 1-.6 .5 .75 .75 0 0 1 0-1z" fill="none" stroke="#43682b" stroke-width=".26"/>
<path d="M165.7 172.5l.1-.1a.54 .54 0 0 1 .5 .7 .54 .54 0 0 1-.6 .4 .75 .75 0 0 1 0-1z" fill="#43682b"/>
<path d="M165.7 172.5l.1-.1a.54 .54 0 0 1 .5 .7 .54 .54 0 0 1-.6 .4 .75 .75 0 0 1 0-1z" fill="none" stroke="#43682b" stroke-width=".26"/>
<path d="M166.6 172.3h.2a.64 .64 0 0 1 .4 .5 .64 .64 0 0 1-.4 .6 .61 .61 0 0 1-.4-.5 .61 .61 0 0 1 .2-.6z" fill="#43682b"/>
<path d="M166.6 172.3h.2a.64 .64 0 0 1 .4 .5 .64 .64 0 0 1-.4 .6 .61 .61 0 0 1-.4-.5 .61 .61 0 0 1 .2-.6z" fill="none" stroke="#43682b" stroke-width=".26"/>
<path d="M167.5 172.2l.2-.1a.51 .51 0 0 1 .3 .6 .51 .51 0 0 1-.5 .4 .67 .67 0 0 1 0-.9z" fill="#43682b"/>
<path d="M167.5 172.2l.2-.1a.51 .51 0 0 1 .3 .6 .51 .51 0 0 1-.5 .4 .67 .67 0 0 1 0-.9z" fill="none" stroke="#43682b" stroke-width=".26"/>
<path d="M168.4 172h.4a.57 .57 0 0 1 .2 .5 .57 .57 0 0 1-.4 .5 .6 .6 0 0 1-.2-1z" fill="#43682b"/>
<path d="M168.4 172h.4a.57 .57 0 0 1 .2 .5 .57 .57 0 0 1-.4 .5 .6 .6 0 0 1-.2-1z" fill="none" stroke="#43682b" stroke-width=".26"/>
<path d="M169.3 171.7l.2-.1a.59 .59 0 0 1 .4 .6 .59 .59 0 0 1-.4 .6 .64 .64 0 0 1-.2-1.1z" fill="#43682b"/>
<path d="M169.3 171.7l.2-.1a.59 .59 0 0 1 .4 .6 .59 .59 0 0 1-.4 .6 .64 .64 0 0 1-.2-1.1z" fill="none" stroke="#43682b" stroke-width=".26"/>
<path d="M170.2 171.7l.2-.1a.64 .64 0 0 1 .4 .6 .64 .64 0 0 1-.4 .6 .6 .6 0 0 1-.4-.5 .6 .6 0 0 1 .2-.6z" fill="#43682b"/>
<path d="M170.2 171.7l.2-.1a.64 .64 0 0 1 .4 .6 .64 .64 0 0 1-.4 .6 .6 .6 0 0 1-.4-.5 .6 .6 0 0 1 .2-.6z" fill="none" stroke="#43682b" stroke-width=".26"/>
<path d="M171.1 171.5h.2a.64 .64 0 0 1 .4 .5 .64 .64 0 0 1-.4 .6 .6 .6 0 0 1-.5-.4 .6 .6 0 0 1 .3-.7z" fill="#43682b"/>
<path d="M171.1 171.5h.2a.64 .64 0 0 1 .4 .5 .64 .64 0 0 1-.4 .6 .6 .6 0 0 1-.5-.4 .6 .6 0 0 1 .3-.7z" fill="none" stroke="#43682b" stroke-width=".26"/>
<path d="M172 171.5h.2a.64 .64 0 0 1 .3 .5 .64 .64 0 0 1-.3 .6 .64 .64 0 0 1-.2-1.1z" fill="#43682b"/>
<path d="M172 171.5h.2a.64 .64 0 0 1 .3 .5 .64 .64 0 0 1-.3 .6 .64 .64 0 0 1-.2-1.1z" fill="none" stroke="#43682b" stroke-width=".26"/>
<path d="M172.9 171.4l.2-.1a.59 .59 0 0 1 .4 .6 .59 .59 0 0 1-.4 .5 .64 .64 0 0 1-.2-1z" fill="#43682b"/>
<path d="M172.9 171.4l.2-.1a.59 .59 0 0 1 .4 .6 .59 .59 0 0 1-.4 .5 .64 .64 0 0 1-.2-1z" fill="none" stroke="#43682b" stroke-width=".26"/>
<path d="M173.8 171.4l.1-.1a.59 .59 0 0 1 .5 .6 .59 .59 0 0 1-.5 .5 .64 .64 0 0 1-.1-1z" fill="#43682b"/>
<path d="M173.8 171.4l.1-.1a.59 .59 0 0 1 .5 .6 .59 .59 0 0 1-.5 .5 .64 .64 0 0 1-.1-1z" fill="none" stroke="#43682b" stroke-width=".26"/>
<path d="M174.7 171.4l.2-.1a.64 .64 0 0 1 .4 .6 .64 .64 0 0 1-.4 .5 .6 .6 0 0 1-.4-.4 .6 .6 0 0 1 .2-.6z" fill="#43682b"/>
<path d="M174.7 171.4l.2-.1a.64 .64 0 0 1 .4 .6 .64 .64 0 0 1-.4 .5 .6 .6 0 0 1-.4-.4 .6 .6 0 0 1 .2-.6z" fill="none" stroke="#43682b" stroke-width=".26"/>
<path d="M175.6 171.4l.2-.1a.64 .64 0 0 1 .3 .6 .64 .64 0 0 1-.3 .5 .64 .64 0 0 1-.2-1z" fill="#43682b"/>
<path d="M175.6 171.4l.2-.1a.64 .64 0 0 1 .3 .6 .64 .64 0 0 1-.3 .5 .64 .64 0 0 1-.2-1z" fill="none" stroke="#43682b" stroke-width=".26"/>
<path d="M176.5 171.4l.2-.1a.59 .59 0 0 1 .4 .6 .59 .59 0 0 1-.4 .5 .64 .64 0 0 1-.2-1z" fill="#43682b"/>
<path d="M176.5 171.4l.2-.1a.59 .59 0 0 1 .4 .6 .59 .59 0 0 1-.4 .5 .64 .64 0 0 1-.2-1z" fill="none" stroke="#43682b" stroke-width=".26"/>
<path d="M177.4 171.2l.2-.1a.54 .54 0 0 1 .4 .6 .54 .54 0 0 1-.6 .5 .75 .75 0 0 1 0-1z" fill="#43682b"/>
<path d="M177.4 171.2l.2-.1a.54 .54 0 0 1 .4 .6 .54 .54 0 0 1-.6 .5 .75 .75 0 0 1 0-1z" fill="none" stroke="#43682b" stroke-width=".26"/>
<path d="M178.3 171.2l.2-.1a.64 .64 0 0 1 .4 .6 .64 .64 0 0 1-.4 .6 .61 .61 0 0 1-.4-.5 .61 .61 0 0 1 .2-.6z" fill="#43682b"/>
<path d="M178.3 171.2l.2-.1a.64 .64 0 0 1 .4 .6 .64 .64 0 0 1-.4 .6 .61 .61 0 0 1-.4-.5 .61 .61 0 0 1 .2-.6z" fill="none" stroke="#43682b" stroke-width=".26"/>
<path d="M179.2 171.2l.2-.1a.64 .64 0 0 1 .4 .6 .64 .64 0 0 1-.4 .6 .61 .61 0 0 1-.4-.5 .61 .61 0 0 1 .2-.6z" fill="#43682b"/>
<path d="M179.2 171.2l.2-.1a.64 .64 0 0 1 .4 .6 .64 .64 0 0 1-.4 .6 .61 .61 0 0 1-.4-.5 .61 .61 0 0 1 .2-.6z" fill="none" stroke="#43682b" stroke-width=".26"/>
<path d="M180.1 171.2l.2-.1a.64 .64 0 0 1 .3 .6 .64 .64 0 0 1-.3 .6 .66 .66 0 0 1-.2-1.1z" fill="#43682b"/>
<path d="M180.1 171.2l.2-.1a.64 .64 0 0 1 .3 .6 .64 .64 0 0 1-.3 .6 .66 .66 0 0 1-.2-1.1z" fill="none" stroke="#43682b" stroke-width=".26"/>
<path d="M181 171.2l.2-.1a.54 .54 0 0 1 .4 .6 .54 .54 0 0 1-.6 .5 .75 .75 0 0 1 0-1z" fill="#43682b"/>
<path d="M181 171.2l.2-.1a.54 .54 0 0 1 .4 .6 .54 .54 0 0 1-.6 .5 .75 .75 0 0 1 0-1z" fill="none" stroke="#43682b" stroke-width=".26"/>
<path d="M181.9 171.2l.2-.1a.64 .64 0 0 1 .4 .6 .64 .64 0 0 1-.4 .6 .61 .61 0 0 1-.4-.5 .61 .61 0 0 1 .2-.6z" fill="#43682b"/>
<path d="M181.9 171.2l.2-.1a.64 .64 0 0 1 .4 .6 .64 .64 0 0 1-.4 .6 .61 .61 0 0 1-.4-.5 .61 .61 0 0 1 .2-.6z" fill="none" stroke="#43682b" stroke-width=".26"/>
<path d="M182.7 171.2l.1-.1a.54 .54 0 0 1 .5 .6 .54 .54 0 0 1-.6 .5 .75 .75 0 0 1 0-1z" fill="#43682b"/>
<path d="M182.7 171.2l.1-.1a.54 .54 0 0 1 .5 .6 .54 .54 0 0 1-.6 .5 .75 .75 0 0 1 0-1z" fill="none" stroke="#43682b" stroke-width=".26"/>
<path d="M183.6 171.2l.1-.1a.54 .54 0 0 1 .5 .6 .54 .54 0 0 1-.6 .5 .75 .75 0 0 1 0-1z" fill="#43682b"/>
<path d="M183.6 171.2l.1-.1a.54 .54 0 0 1 .5 .6 .54 .54 0 0 1-.6 .5 .75 .75 0 0 1 0-1z" fill="none" stroke="#43682b" stroke-width=".26"/>
<path d="M184.5 171.2l.2-.1a.64 .64 0 0 1 .3 .6 .64 .64 0 0 1-.3 .6 .61 .61 0 0 1-.5-.5 .61 .61 0 0 1 .3-.6z" fill="#43682b"/>
<path d="M184.5 171.2l.2-.1a.64 .64 0 0 1 .3 .6 .64 .64 0 0 1-.3 .6 .61 .61 0 0 1-.5-.5 .61 .61 0 0 1 .3-.6z" fill="none" stroke="#43682b" stroke-width=".26"/>
<path d="M185.4 171.2l.2-.1a.64 .64 0 0 1 .3 .6 .64 .64 0 0 1-.3 .6 .66 .66 0 0 1-.2-1.1z" fill="#43682b"/>
<path d="M185.4 171.2l.2-.1a.64 .64 0 0 1 .3 .6 .64 .64 0 0 1-.3 .6 .66 .66 0 0 1-.2-1.1z" fill="none" stroke="#43682b" stroke-width=".26"/>
<path d="M186.3 171.2l.2-.1a.54 .54 0 0 1 .4 .6 .54 .54 0 0 1-.6 .5 .75 .75 0 0 1 0-1z" fill="#43682b"/>
<path d="M186.3 171.2l.2-.1a.54 .54 0 0 1 .4 .6 .54 .54 0 0 1-.6 .5 .75 .75 0 0 1 0-1z" fill="none" stroke="#43682b" stroke-width=".26"/>
<path d="M187.2 171.2l.1-.1a.54 .54 0 0 1 .5 .6 .54 .54 0 0 1-.6 .5 .75 .75 0 0 1 0-1z" fill="#43682b"/>
<path d="M187.2 171.2l.1-.1a.54 .54 0 0 1 .5 .6 .54 .54 0 0 1-.6 .5 .75 .75 0 0 1 0-1z" fill="none" stroke="#43682b" stroke-width=".26"/>
<path d="M188.1 171.2l.2-.1a.64 .64 0 0 1 .4 .6 .64 .64 0 0 1-.4 .6 .61 .61 0 0 1-.4-.5 .61 .61 0 0 1 .2-.6z" fill="#43682b"/>
<path d="M188.1 171.2l.2-.1a.64 .64 0 0 1 .4 .6 .64 .64 0 0 1-.4 .6 .61 .61 0 0 1-.4-.5 .61 .61 0 0 1 .2-.6z" fill="none" stroke="#43682b" stroke-width=".26"/>
<path d="M189 171.2l.2-.1a.64 .64 0 0 1 .3 .6 .64 .64 0 0 1-.3 .6 .61 .61 0 0 1-.5-.5 .61 .61 0 0 1 .3-.6z" fill="#43682b"/>
<path d="M189 171.2l.2-.1a.64 .64 0 0 1 .3 .6 .64 .64 0 0 1-.3 .6 .61 .61 0 0 1-.5-.5 .61 .61 0 0 1 .3-.6z" fill="none" stroke="#43682b" stroke-width=".26"/>
<path d="M189.9 171.2l.2-.1a.64 .64 0 0 1 .3 .6 .64 .64 0 0 1-.3 .6 .66 .66 0 0 1-.2-1.1z" fill="#43682b"/>
<path d="M189.9 171.2l.2-.1a.64 .64 0 0 1 .3 .6 .64 .64 0 0 1-.3 .6 .66 .66 0 0 1-.2-1.1z" fill="none" stroke="#43682b" stroke-width=".26"/>
<path d="M190.8 171.2l.1-.1a.54 .54 0 0 1 .5 .6 .54 .54 0 0 1-.6 .5 .75 .75 0 0 1 0-1z" fill="#43682b"/>
<path d="M190.8 171.2l.1-.1a.54 .54 0 0 1 .5 .6 .54 .54 0 0 1-.6 .5 .75 .75 0 0 1 0-1z" fill="none" stroke="#43682b" stroke-width=".26"/>
<path d="M191.7 171.2l.1-.1a.54 .54 0 0 1 .5 .6 .54 .54 0 0 1-.6 .5 .75 .75 0 0 1 0-1z" fill="#43682b"/>
<path d="M191.7 171.2l.1-.1a.54 .54 0 0 1 .5 .6 .54 .54 0 0 1-.6 .5 .75 .75 0 0 1 0-1z" fill="none" stroke="#43682b" stroke-width=".26"/>
<path d="M192.6 171.2l.2-.1a.64 .64 0 0 1 .3 .6 .64 .64 0 0 1-.3 .6 .61 .61 0 0 1-.4-.5 .61 .61 0 0 1 .2-.6z" fill="#43682b"/>
<path d="M192.6 171.2l.2-.1a.64 .64 0 0 1 .3 .6 .64 .64 0 0 1-.3 .6 .61 .61 0 0 1-.4-.5 .61 .61 0 0 1 .2-.6z" fill="none" stroke="#43682b" stroke-width=".26"/>
<path d="M192.7 171.7l-16.4 .1-5.1 .3-3.2 .4a11.5 11.5 0 0 0-9.6 7.7l-1.3 2.8-3.9 10a49.2 49.2 0 0 0-3.1 9.5 .88 .88 0 0 1-1 .9l-18.9 .1" fill="none" stroke="#7cafdd" stroke-width=".44"/>
<path d="M192.7 171.7l-16.4 .1-5.1 .3-2 .3a12 12 0 0 0-9.6 5.5l-1.8 3.7-4.6 11.6a46.4 46.4 0 0 0-2.8 8.3l-.3 1a.94 .94 0 0 1-1 1h-18.9" fill="none" stroke="#f1975a" stroke-width=".44"/>
<path d="M129.9 202.9l.2-.1a.59 .59 0 0 1 .4 .6 .59 .59 0 0 1-.4 .5 .64 .64 0 0 1-.2-1z" fill="#f1975a"/>
<path d="M129.9 202.9l.2-.1a.59 .59 0 0 1 .4 .6 .59 .59 0 0 1-.4 .5 .64 .64 0 0 1-.2-1z" fill="none" stroke="#f1975a" stroke-width=".26"/>
<path d="M130.8 202.9l.2-.1a.64 .64 0 0 1 .4 .6 .64 .64 0 0 1-.4 .5 .6 .6 0 0 1-.4-.4 .6 .6 0 0 1 .2-.6z" fill="#f1975a"/>
<path d="M130.8 202.9l.2-.1a.64 .64 0 0 1 .4 .6 .64 .64 0 0 1-.4 .5 .6 .6 0 0 1-.4-.4 .6 .6 0 0 1 .2-.6z" fill="none" stroke="#f1975a" stroke-width=".26"/>
<path d="M131.8 202.9l.1-.1a.64 .64 0 0 1 .4 .6 .64 .64 0 0 1-.4 .5 .64 .64 0 0 1-.1-1z" fill="#f1975a"/>
<path d="M131.8 202.9l.1-.1a.64 .64 0 0 1 .4 .6 .64 .64 0 0 1-.4 .5 .64 .64 0 0 1-.1-1z" fill="none" stroke="#f1975a" stroke-width=".26"/>
<path d="M132.6 202.9l.2-.1a.59 .59 0 0 1 .4 .6 .59 .59 0 0 1-.4 .5 .64 .64 0 0 1-.2-1z" fill="#f1975a"/>
<path d="M132.6 202.9l.2-.1a.59 .59 0 0 1 .4 .6 .59 .59 0 0 1-.4 .5 .64 .64 0 0 1-.2-1z" fill="none" stroke="#f1975a" stroke-width=".26"/>
<path d="M133.5 202.9l.2-.1a.59 .59 0 0 1 .4 .6 .59 .59 0 0 1-.4 .5 .64 .64 0 0 1-.2-1z" fill="#f1975a"/>
<path d="M133.5 202.9l.2-.1a.59 .59 0 0 1 .4 .6 .59 .59 0 0 1-.4 .5 .64 .64 0 0 1-.2-1z" fill="none" stroke="#f1975a" stroke-width=".26"/>
<path d="M134.4 202.9l.3-.1a.64 .64 0 0 1 .3 .6 .64 .64 0 0 1-.3 .5 .6 .6 0 0 1-.5-.4 .6 .6 0 0 1 .2-.6z" fill="#f1975a"/>
<path d="M134.4 202.9l.3-.1a.64 .64 0 0 1 .3 .6 .64 .64 0 0 1-.3 .5 .6 .6 0 0 1-.5-.4 .6 .6 0 0 1 .2-.6z" fill="none" stroke="#f1975a" stroke-width=".26"/>
<path d="M135.3 202.9l.2-.1a.64 .64 0 0 1 .4 .6 .64 .64 0 0 1-.4 .5 .6 .6 0 0 1-.4-.4 .6 .6 0 0 1 .2-.6z" fill="#f1975a"/>
<path d="M135.3 202.9l.2-.1a.64 .64 0 0 1 .4 .6 .64 .64 0 0 1-.4 .5 .6 .6 0 0 1-.4-.4 .6 .6 0 0 1 .2-.6z" fill="none" stroke="#f1975a" stroke-width=".26"/>
<path d="M136.2 202.9l.2-.1a.64 .64 0 0 1 .4 .6 .64 .64 0 0 1-.4 .5 .64 .64 0 0 1-.2-1z" fill="#f1975a"/>
<path d="M136.2 202.9l.2-.1a.64 .64 0 0 1 .4 .6 .64 .64 0 0 1-.4 .5 .64 .64 0 0 1-.2-1z" fill="none" stroke="#f1975a" stroke-width=".26"/>
<path d="M137.1 202.9l.2-.1a.59 .59 0 0 1 .4 .6 .59 .59 0 0 1-.4 .5 .64 .64 0 0 1-.2-1z" fill="#f1975a"/>
<path d="M137.1 202.9l.2-.1a.59 .59 0 0 1 .4 .6 .59 .59 0 0 1-.4 .5 .64 .64 0 0 1-.2-1z" fill="none" stroke="#f1975a" stroke-width=".26"/>
<path d="M138 202.9l.2-.1a.59 .59 0 0 1 .4 .6 .59 .59 0 0 1-.4 .5 .64 .64 0 0 1-.2-1z" fill="#f1975a"/>
<path d="M138 202.9l.2-.1a.59 .59 0 0 1 .4 .6 .59 .59 0 0 1-.4 .5 .64 .64 0 0 1-.2-1z" fill="none" stroke="#f1975a" stroke-width=".26"/>
<path d="M138.9 202.9l.2-.1a.64 .64 0 0 1 .4 .6 .64 .64 0 0 1-.4 .5 .6 .6 0 0 1-.4-.4 .6 .6 0 0 1 .2-.6z" fill="#f1975a"/>
<path d="M138.9 202.9l.2-.1a.64 .64 0 0 1 .4 .6 .64 .64 0 0 1-.4 .5 .6 .6 0 0 1-.4-.4 .6 .6 0 0 1 .2-.6z" fill="none" stroke="#f1975a" stroke-width=".26"/>
<path d="M139.9 202.9l.1-.1a.64 .64 0 0 1 .4 .6 .64 .64 0 0 1-.4 .5 .64 .64 0 0 1-.1-1z" fill="#f1975a"/>
<path d="M139.9 202.9l.1-.1a.64 .64 0 0 1 .4 .6 .64 .64 0 0 1-.4 .5 .64 .64 0 0 1-.1-1z" fill="none" stroke="#f1975a" stroke-width=".26"/>
<path d="M140.7 202.9l.2-.1a.59 .59 0 0 1 .5 .6 .59 .59 0 0 1-.5 .5 .64 .64 0 0 1-.2-1z" fill="#f1975a"/>
<path d="M140.7 202.9l.2-.1a.59 .59 0 0 1 .5 .6 .59 .59 0 0 1-.5 .5 .64 .64 0 0 1-.2-1z" fill="none" stroke="#f1975a" stroke-width=".26"/>
<path d="M141.6 202.9l.2-.1a.59 .59 0 0 1 .4 .6 .59 .59 0 0 1-.4 .5 .64 .64 0 0 1-.2-1z" fill="#f1975a"/>
<path d="M141.6 202.9l.2-.1a.59 .59 0 0 1 .4 .6 .59 .59 0 0 1-.4 .5 .64 .64 0 0 1-.2-1z" fill="none" stroke="#f1975a" stroke-width=".26"/>
<path d="M142.5 202.9l.3-.1a.64 .64 0 0 1 .3 .6 .64 .64 0 0 1-.3 .5 .6 .6 0 0 1-.5-.4 .6 .6 0 0 1 .2-.6z" fill="#f1975a"/>
<path d="M142.5 202.9l.3-.1a.64 .64 0 0 1 .3 .6 .64 .64 0 0 1-.3 .5 .6 .6 0 0 1-.5-.4 .6 .6 0 0 1 .2-.6z" fill="none" stroke="#f1975a" stroke-width=".26"/>
<path d="M143.4 202.9l.2-.1a.64 .64 0 0 1 .4 .6 .64 .64 0 0 1-.4 .5 .6 .6 0 0 1-.4-.4 .6 .6 0 0 1 .2-.6z" fill="#f1975a"/>
<path d="M143.4 202.9l.2-.1a.64 .64 0 0 1 .4 .6 .64 .64 0 0 1-.4 .5 .6 .6 0 0 1-.4-.4 .6 .6 0 0 1 .2-.6z" fill="none" stroke="#f1975a" stroke-width=".26"/>
<path d="M144.4 202.9l.1-.1a.64 .64 0 0 1 .4 .6 .64 .64 0 0 1-.4 .5 .64 .64 0 0 1-.1-1z" fill="#f1975a"/>
<path d="M144.4 202.9l.1-.1a.64 .64 0 0 1 .4 .6 .64 .64 0 0 1-.4 .5 .64 .64 0 0 1-.1-1z" fill="none" stroke="#f1975a" stroke-width=".26"/>
<path d="M145.2 202.9l.2-.1a.59 .59 0 0 1 .4 .6 .59 .59 0 0 1-.4 .5 .64 .64 0 0 1-.2-1z" fill="#f1975a"/>
<path d="M145.2 202.9l.2-.1a.59 .59 0 0 1 .4 .6 .59 .59 0 0 1-.4 .5 .64 .64 0 0 1-.2-1z" fill="none" stroke="#f1975a" stroke-width=".26"/>
<path d="M146.1 202.9l.2-.1a.59 .59 0 0 1 .4 .6 .59 .59 0 0 1-.4 .5 .64 .64 0 0 1-.2-1z" fill="#f1975a"/>
<path d="M146.1 202.9l.2-.1a.59 .59 0 0 1 .4 .6 .59 .59 0 0 1-.4 .5 .64 .64 0 0 1-.2-1z" fill="none" stroke="#f1975a" stroke-width=".26"/>
<path d="M146.9 202.9l.2-.1a.59 .59 0 0 1 .4 .6 .59 .59 0 0 1-.4 .5 .64 .64 0 0 1-.2-1z" fill="#f1975a"/>
<path d="M146.9 202.9l.2-.1a.59 .59 0 0 1 .4 .6 .59 .59 0 0 1-.4 .5 .64 .64 0 0 1-.2-1z" fill="none" stroke="#f1975a" stroke-width=".26"/>
<path d="M147.8 202.9l.2-.1a.59 .59 0 0 1 .4 .6 .59 .59 0 0 1-.4 .5 .64 .64 0 0 1-.2-1z" fill="#f1975a"/>
<path d="M147.8 202.9l.2-.1a.59 .59 0 0 1 .4 .6 .59 .59 0 0 1-.4 .5 .64 .64 0 0 1-.2-1z" fill="none" stroke="#f1975a" stroke-width=".26"/>
<path d="M148.7 202.9l.2-.1a.64 .64 0 0 1 .4 .6 .64 .64 0 0 1-.4 .5 .6 .6 0 0 1-.4-.4 .6 .6 0 0 1 .2-.6z" fill="#f1975a"/>
<path d="M148.7 202.9l.2-.1a.64 .64 0 0 1 .4 .6 .64 .64 0 0 1-.4 .5 .6 .6 0 0 1-.4-.4 .6 .6 0 0 1 .2-.6z" fill="none" stroke="#f1975a" stroke-width=".26"/>
<path d="M149.6 202.7l.2-.1a.64 .64 0 0 1 .4 .6 .64 .64 0 0 1-.4 .6 .64 .64 0 0 1-.2-1.1z" fill="#f1975a"/>
<path d="M149.6 202.7l.2-.1a.64 .64 0 0 1 .4 .6 .64 .64 0 0 1-.4 .6 .64 .64 0 0 1-.2-1.1z" fill="none" stroke="#f1975a" stroke-width=".26"/>
<path d="M150.5 199.9l.2-.1a.59 .59 0 0 1 .4 .6 .59 .59 0 0 1-.4 .5 .64 .64 0 0 1-.2-1z" fill="#f1975a"/>
<path d="M150.5 199.9l.2-.1a.59 .59 0 0 1 .4 .6 .59 .59 0 0 1-.4 .5 .64 .64 0 0 1-.2-1z" fill="none" stroke="#f1975a" stroke-width=".26"/>
<path d="M151.4 196.7l.2-.1a.59 .59 0 0 1 .4 .6 .59 .59 0 0 1-.4 .6 .64 .64 0 0 1-.2-1.1z" fill="#f1975a"/>
<path d="M151.4 196.7l.2-.1a.59 .59 0 0 1 .4 .6 .59 .59 0 0 1-.4 .6 .64 .64 0 0 1-.2-1.1z" fill="none" stroke="#f1975a" stroke-width=".26"/>
<path d="M152.3 194.7l.2-.1a.64 .64 0 0 1 .4 .6 .64 .64 0 0 1-.4 .5 .61 .61 0 0 1-.4-.4 .61 .61 0 0 1 .2-.6z" fill="#f1975a"/>
<path d="M152.3 194.7l.2-.1a.64 .64 0 0 1 .4 .6 .64 .64 0 0 1-.4 .5 .61 .61 0 0 1-.4-.4 .61 .61 0 0 1 .2-.6z" fill="none" stroke="#f1975a" stroke-width=".26"/>
<path d="M153.2 192.2l.2-.1a.64 .64 0 0 1 .4 .6 .64 .64 0 0 1-.4 .6 .6 .6 0 0 1-.4-.5 .6 .6 0 0 1 .2-.6z" fill="#f1975a"/>
<path d="M153.2 192.2l.2-.1a.64 .64 0 0 1 .4 .6 .64 .64 0 0 1-.4 .6 .6 .6 0 0 1-.4-.5 .6 .6 0 0 1 .2-.6z" fill="none" stroke="#f1975a" stroke-width=".26"/>
<path d="M154.1 190l.2-.1a.51 .51 0 0 1 .3 .6 .51 .51 0 0 1-.5 .4 .7 .7 0 0 1 0-.9z" fill="#f1975a"/>
<path d="M154.1 190l.2-.1a.51 .51 0 0 1 .3 .6 .51 .51 0 0 1-.5 .4 .7 .7 0 0 1 0-.9z" fill="none" stroke="#f1975a" stroke-width=".26"/>
<path d="M155 187.7l.2-.1a.59 .59 0 0 1 .4 .6 .59 .59 0 0 1-.4 .6 .64 .64 0 0 1-.2-1.1z" fill="#f1975a"/>
<path d="M155 187.7l.2-.1a.59 .59 0 0 1 .4 .6 .59 .59 0 0 1-.4 .6 .64 .64 0 0 1-.2-1.1z" fill="none" stroke="#f1975a" stroke-width=".26"/>
<path d="M155.9 185.5a.49 .49 0 0 1 .6 .4 .49 .49 0 0 1-.6 .5 .7 .7 0 0 1 0-.9z" fill="#f1975a"/>
<path d="M155.9 185.5a.49 .49 0 0 1 .6 .4 .49 .49 0 0 1-.6 .5 .7 .7 0 0 1 0-.9z" fill="none" stroke="#f1975a" stroke-width=".26"/>
<path d="M156.8 183.2l.2-.1a.64 .64 0 0 1 .4 .6 .64 .64 0 0 1-.4 .6 .61 .61 0 0 1-.4-.5 .61 .61 0 0 1 .2-.6z" fill="#f1975a"/>
<path d="M156.8 183.2l.2-.1a.64 .64 0 0 1 .4 .6 .64 .64 0 0 1-.4 .6 .61 .61 0 0 1-.4-.5 .61 .61 0 0 1 .2-.6z" fill="none" stroke="#f1975a" stroke-width=".26"/>
<path d="M157.7 181.2l.2-.1a.51 .51 0 0 1 .4 .6 .51 .51 0 0 1-.6 .4 .67 .67 0 0 1 0-.9z" fill="#f1975a"/>
<path d="M157.7 181.2l.2-.1a.51 .51 0 0 1 .4 .6 .51 .51 0 0 1-.6 .4 .67 .67 0 0 1 0-.9z" fill="none" stroke="#f1975a" stroke-width=".26"/>
<path d="M158.6 179h.2a.59 .59 0 0 1 .4 .5 .59 .59 0 0 1-.4 .6 .64 .64 0 0 1-.2-1.1z" fill="#f1975a"/>
<path d="M158.6 179h.2a.59 .59 0 0 1 .4 .5 .59 .59 0 0 1-.4 .6 .64 .64 0 0 1-.2-1.1z" fill="none" stroke="#f1975a" stroke-width=".26"/>
<path d="M159.5 177.4l.2-.1a.59 .59 0 0 1 .4 .6 .59 .59 0 0 1-.4 .5 .64 .64 0 0 1-.2-1z" fill="#f1975a"/>
<path d="M159.5 177.4l.2-.1a.59 .59 0 0 1 .4 .6 .59 .59 0 0 1-.4 .5 .64 .64 0 0 1-.2-1z" fill="none" stroke="#f1975a" stroke-width=".26"/>
<path d="M160.4 176h.2a.64 .64 0 0 1 .4 .5 .64 .64 0 0 1-.4 .6 .6 .6 0 0 1-.4-.4 .6 .6 0 0 1 .2-.7z" fill="#f1975a"/>
<path d="M160.4 176h.2a.64 .64 0 0 1 .4 .5 .64 .64 0 0 1-.4 .6 .6 .6 0 0 1-.4-.4 .6 .6 0 0 1 .2-.7z" fill="none" stroke="#f1975a" stroke-width=".26"/>
<path d="M161.3 175.2l.2-.1a.52 .52 0 0 1 .4 .6 .52 .52 0 0 1-.6 .4 .61 .61 0 0 1 0-.9z" fill="#f1975a"/>
<path d="M161.3 175.2l.2-.1a.52 .52 0 0 1 .4 .6 .52 .52 0 0 1-.6 .4 .61 .61 0 0 1 0-.9z" fill="none" stroke="#f1975a" stroke-width=".26"/>
<path d="M162.2 174.2l.2-.1a.64 .64 0 0 1 .4 .6 .64 .64 0 0 1-.4 .6 .66 .66 0 0 1-.2-1.1z" fill="#f1975a"/>
<path d="M162.2 174.2l.2-.1a.64 .64 0 0 1 .4 .6 .64 .64 0 0 1-.4 .6 .66 .66 0 0 1-.2-1.1z" fill="none" stroke="#f1975a" stroke-width=".26"/>
<path d="M163.1 173.7l.2-.1a.51 .51 0 0 1 .4 .6 .51 .51 0 0 1-.6 .4 .67 .67 0 0 1 0-.9z" fill="#f1975a"/>
<path d="M163.1 173.7l.2-.1a.51 .51 0 0 1 .4 .6 .51 .51 0 0 1-.6 .4 .67 .67 0 0 1 0-.9z" fill="none" stroke="#f1975a" stroke-width=".26"/>
<path d="M164 173.2l.3-.1a.64 .64 0 0 1 .3 .6 .64 .64 0 0 1-.3 .6 .6 .6 0 0 1-.5-.5 .6 .6 0 0 1 .2-.6z" fill="#f1975a"/>
<path d="M164 173.2l.3-.1a.64 .64 0 0 1 .3 .6 .64 .64 0 0 1-.3 .6 .6 .6 0 0 1-.5-.5 .6 .6 0 0 1 .2-.6z" fill="none" stroke="#f1975a" stroke-width=".26"/>
<path d="M164.8 172.9l.2-.1a.59 .59 0 0 1 .4 .6 .59 .59 0 0 1-.4 .5 .64 .64 0 0 1-.2-1z" fill="#f1975a"/>
<path d="M164.8 172.9l.2-.1a.59 .59 0 0 1 .4 .6 .59 .59 0 0 1-.4 .5 .64 .64 0 0 1-.2-1z" fill="none" stroke="#f1975a" stroke-width=".26"/>
<path d="M165.7 172.5l.1-.1a.54 .54 0 0 1 .5 .7 .54 .54 0 0 1-.6 .4 .75 .75 0 0 1 0-1z" fill="#f1975a"/>
<path d="M165.7 172.5l.1-.1a.54 .54 0 0 1 .5 .7 .54 .54 0 0 1-.6 .4 .75 .75 0 0 1 0-1z" fill="none" stroke="#f1975a" stroke-width=".26"/>
<path d="M166.6 172.3h.2a.64 .64 0 0 1 .4 .5 .64 .64 0 0 1-.4 .6 .61 .61 0 0 1-.4-.5 .61 .61 0 0 1 .2-.6z" fill="#f1975a"/>
<path d="M166.6 172.3h.2a.64 .64 0 0 1 .4 .5 .64 .64 0 0 1-.4 .6 .61 .61 0 0 1-.4-.5 .61 .61 0 0 1 .2-.6z" fill="none" stroke="#f1975a" stroke-width=".26"/>
<path d="M167.5 172.2l.2-.1a.51 .51 0 0 1 .3 .6 .51 .51 0 0 1-.5 .4 .67 .67 0 0 1 0-.9z" fill="#f1975a"/>
<path d="M167.5 172.2l.2-.1a.51 .51 0 0 1 .3 .6 .51 .51 0 0 1-.5 .4 .67 .67 0 0 1 0-.9z" fill="none" stroke="#f1975a" stroke-width=".26"/>
<path d="M168.4 172h.4a.57 .57 0 0 1 .2 .5 .57 .57 0 0 1-.4 .5 .6 .6 0 0 1-.2-1z" fill="#f1975a"/>
<path d="M168.4 172h.4a.57 .57 0 0 1 .2 .5 .57 .57 0 0 1-.4 .5 .6 .6 0 0 1-.2-1z" fill="none" stroke="#f1975a" stroke-width=".26"/>
<path d="M169.3 171.7l.2-.1a.59 .59 0 0 1 .4 .6 .59 .59 0 0 1-.4 .6 .64 .64 0 0 1-.2-1.1z" fill="#f1975a"/>
<path d="M169.3 171.7l.2-.1a.59 .59 0 0 1 .4 .6 .59 .59 0 0 1-.4 .6 .64 .64 0 0 1-.2-1.1z" fill="none" stroke="#f1975a" stroke-width=".26"/>
<path d="M170.2 171.5h.2a.64 .64 0 0 1 .4 .5 .64 .64 0 0 1-.4 .6 .6 .6 0 0 1-.4-.4 .6 .6 0 0 1 .2-.7z" fill="#f1975a"/>
<path d="M170.2 171.5h.2a.64 .64 0 0 1 .4 .5 .64 .64 0 0 1-.4 .6 .6 .6 0 0 1-.4-.4 .6 .6 0 0 1 .2-.7z" fill="none" stroke="#f1975a" stroke-width=".26"/>
<path d="M171.1 171.5h.2a.64 .64 0 0 1 .4 .5 .64 .64 0 0 1-.4 .6 .6 .6 0 0 1-.5-.4 .6 .6 0 0 1 .3-.7z" fill="#f1975a"/>
<path d="M171.1 171.5h.2a.64 .64 0 0 1 .4 .5 .64 .64 0 0 1-.4 .6 .6 .6 0 0 1-.5-.4 .6 .6 0 0 1 .3-.7z" fill="none" stroke="#f1975a" stroke-width=".26"/>
<path d="M172 171.5h.2a.64 .64 0 0 1 .3 .5 .64 .64 0 0 1-.3 .6 .64 .64 0 0 1-.2-1.1z" fill="#f1975a"/>
<path d="M172 171.5h.2a.64 .64 0 0 1 .3 .5 .64 .64 0 0 1-.3 .6 .64 .64 0 0 1-.2-1.1z" fill="none" stroke="#f1975a" stroke-width=".26"/>
<path d="M172.9 171.4l.2-.1a.59 .59 0 0 1 .4 .6 .59 .59 0 0 1-.4 .5 .64 .64 0 0 1-.2-1z" fill="#f1975a"/>
<path d="M172.9 171.4l.2-.1a.59 .59 0 0 1 .4 .6 .59 .59 0 0 1-.4 .5 .64 .64 0 0 1-.2-1z" fill="none" stroke="#f1975a" stroke-width=".26"/>
<path d="M173.8 171.4l.1-.1a.59 .59 0 0 1 .5 .6 .59 .59 0 0 1-.5 .5 .64 .64 0 0 1-.1-1z" fill="#f1975a"/>
<path d="M173.8 171.4l.1-.1a.59 .59 0 0 1 .5 .6 .59 .59 0 0 1-.5 .5 .64 .64 0 0 1-.1-1z" fill="none" stroke="#f1975a" stroke-width=".26"/>
<path d="M174.7 171.4l.2-.1a.64 .64 0 0 1 .4 .6 .64 .64 0 0 1-.4 .5 .6 .6 0 0 1-.4-.4 .6 .6 0 0 1 .2-.6z" fill="#f1975a"/>
<path d="M174.7 171.4l.2-.1a.64 .64 0 0 1 .4 .6 .64 .64 0 0 1-.4 .5 .6 .6 0 0 1-.4-.4 .6 .6 0 0 1 .2-.6z" fill="none" stroke="#f1975a" stroke-width=".26"/>
<path d="M175.6 171.4l.2-.1a.64 .64 0 0 1 .3 .6 .64 .64 0 0 1-.3 .5 .64 .64 0 0 1-.2-1z" fill="#f1975a"/>
<path d="M175.6 171.4l.2-.1a.64 .64 0 0 1 .3 .6 .64 .64 0 0 1-.3 .5 .64 .64 0 0 1-.2-1z" fill="none" stroke="#f1975a" stroke-width=".26"/>
<path d="M176.5 171.2l.2-.1a.54 .54 0 0 1 .4 .6 .54 .54 0 0 1-.6 .5 .75 .75 0 0 1 0-1z" fill="#f1975a"/>
<path d="M176.5 171.2l.2-.1a.54 .54 0 0 1 .4 .6 .54 .54 0 0 1-.6 .5 .75 .75 0 0 1 0-1z" fill="none" stroke="#f1975a" stroke-width=".26"/>
<path d="M177.4 171.2l.2-.1a.54 .54 0 0 1 .4 .6 .54 .54 0 0 1-.6 .5 .75 .75 0 0 1 0-1z" fill="#f1975a"/>
<path d="M177.4 171.2l.2-.1a.54 .54 0 0 1 .4 .6 .54 .54 0 0 1-.6 .5 .75 .75 0 0 1 0-1z" fill="none" stroke="#f1975a" stroke-width=".26"/>
<path d="M178.3 171.2l.2-.1a.64 .64 0 0 1 .4 .6 .64 .64 0 0 1-.4 .6 .61 .61 0 0 1-.4-.5 .61 .61 0 0 1 .2-.6z" fill="#f1975a"/>
<path d="M178.3 171.2l.2-.1a.64 .64 0 0 1 .4 .6 .64 .64 0 0 1-.4 .6 .61 .61 0 0 1-.4-.5 .61 .61 0 0 1 .2-.6z" fill="none" stroke="#f1975a" stroke-width=".26"/>
<path d="M179.2 171.2l.2-.1a.64 .64 0 0 1 .4 .6 .64 .64 0 0 1-.4 .6 .61 .61 0 0 1-.4-.5 .61 .61 0 0 1 .2-.6z" fill="#f1975a"/>
<path d="M179.2 171.2l.2-.1a.64 .64 0 0 1 .4 .6 .64 .64 0 0 1-.4 .6 .61 .61 0 0 1-.4-.5 .61 .61 0 0 1 .2-.6z" fill="none" stroke="#f1975a" stroke-width=".26"/>
<path d="M180.1 171.2l.2-.1a.64 .64 0 0 1 .3 .6 .64 .64 0 0 1-.3 .6 .66 .66 0 0 1-.2-1.1z" fill="#f1975a"/>
<path d="M180.1 171.2l.2-.1a.64 .64 0 0 1 .3 .6 .64 .64 0 0 1-.3 .6 .66 .66 0 0 1-.2-1.1z" fill="none" stroke="#f1975a" stroke-width=".26"/>
<path d="M181 171.2l.2-.1a.54 .54 0 0 1 .4 .6 .54 .54 0 0 1-.6 .5 .75 .75 0 0 1 0-1z" fill="#f1975a"/>
<path d="M181 171.2l.2-.1a.54 .54 0 0 1 .4 .6 .54 .54 0 0 1-.6 .5 .75 .75 0 0 1 0-1z" fill="none" stroke="#f1975a" stroke-width=".26"/>
<path d="M181.9 171.2l.2-.1a.64 .64 0 0 1 .4 .6 .64 .64 0 0 1-.4 .6 .61 .61 0 0 1-.4-.5 .61 .61 0 0 1 .2-.6z" fill="#f1975a"/>
<path d="M181.9 171.2l.2-.1a.64 .64 0 0 1 .4 .6 .64 .64 0 0 1-.4 .6 .61 .61 0 0 1-.4-.5 .61 .61 0 0 1 .2-.6z" fill="none" stroke="#f1975a" stroke-width=".26"/>
<path d="M182.7 171.2l.1-.1a.54 .54 0 0 1 .5 .6 .54 .54 0 0 1-.6 .5 .75 .75 0 0 1 0-1z" fill="#f1975a"/>
<path d="M182.7 171.2l.1-.1a.54 .54 0 0 1 .5 .6 .54 .54 0 0 1-.6 .5 .75 .75 0 0 1 0-1z" fill="none" stroke="#f1975a" stroke-width=".26"/>
<path d="M183.6 171.2l.1-.1a.54 .54 0 0 1 .5 .6 .54 .54 0 0 1-.6 .5 .75 .75 0 0 1 0-1z" fill="#f1975a"/>
<path d="M183.6 171.2l.1-.1a.54 .54 0 0 1 .5 .6 .54 .54 0 0 1-.6 .5 .75 .75 0 0 1 0-1z" fill="none" stroke="#f1975a" stroke-width=".26"/>
<path d="M184.5 171.2l.2-.1a.64 .64 0 0 1 .3 .6 .64 .64 0 0 1-.3 .6 .61 .61 0 0 1-.5-.5 .61 .61 0 0 1 .3-.6z" fill="#f1975a"/>
<path d="M184.5 171.2l.2-.1a.64 .64 0 0 1 .3 .6 .64 .64 0 0 1-.3 .6 .61 .61 0 0 1-.5-.5 .61 .61 0 0 1 .3-.6z" fill="none" stroke="#f1975a" stroke-width=".26"/>
<path d="M185.4 171.2l.2-.1a.64 .64 0 0 1 .3 .6 .64 .64 0 0 1-.3 .6 .66 .66 0 0 1-.2-1.1z" fill="#f1975a"/>
<path d="M185.4 171.2l.2-.1a.64 .64 0 0 1 .3 .6 .64 .64 0 0 1-.3 .6 .66 .66 0 0 1-.2-1.1z" fill="none" stroke="#f1975a" stroke-width=".26"/>
<path d="M186.3 171.2l.2-.1a.54 .54 0 0 1 .4 .6 .54 .54 0 0 1-.6 .5 .75 .75 0 0 1 0-1z" fill="#f1975a"/>
<path d="M186.3 171.2l.2-.1a.54 .54 0 0 1 .4 .6 .54 .54 0 0 1-.6 .5 .75 .75 0 0 1 0-1z" fill="none" stroke="#f1975a" stroke-width=".26"/>
<path d="M187.2 171.2l.1-.1a.54 .54 0 0 1 .5 .6 .54 .54 0 0 1-.6 .5 .75 .75 0 0 1 0-1z" fill="#f1975a"/>
<path d="M187.2 171.2l.1-.1a.54 .54 0 0 1 .5 .6 .54 .54 0 0 1-.6 .5 .75 .75 0 0 1 0-1z" fill="none" stroke="#f1975a" stroke-width=".26"/>
<path d="M188.1 171.2l.2-.1a.64 .64 0 0 1 .4 .6 .64 .64 0 0 1-.4 .6 .61 .61 0 0 1-.4-.5 .61 .61 0 0 1 .2-.6z" fill="#f1975a"/>
<path d="M188.1 171.2l.2-.1a.64 .64 0 0 1 .4 .6 .64 .64 0 0 1-.4 .6 .61 .61 0 0 1-.4-.5 .61 .61 0 0 1 .2-.6z" fill="none" stroke="#f1975a" stroke-width=".26"/>
<path d="M189 171.2l.2-.1a.64 .64 0 0 1 .3 .6 .64 .64 0 0 1-.3 .6 .61 .61 0 0 1-.5-.5 .61 .61 0 0 1 .3-.6z" fill="#f1975a"/>
<path d="M189 171.2l.2-.1a.64 .64 0 0 1 .3 .6 .64 .64 0 0 1-.3 .6 .61 .61 0 0 1-.5-.5 .61 .61 0 0 1 .3-.6z" fill="none" stroke="#f1975a" stroke-width=".26"/>
<path d="M189.9 171.2l.2-.1a.64 .64 0 0 1 .3 .6 .64 .64 0 0 1-.3 .6 .66 .66 0 0 1-.2-1.1z" fill="#f1975a"/>
<path d="M189.9 171.2l.2-.1a.64 .64 0 0 1 .3 .6 .64 .64 0 0 1-.3 .6 .66 .66 0 0 1-.2-1.1z" fill="none" stroke="#f1975a" stroke-width=".26"/>
<path d="M190.8 171.2l.1-.1a.54 .54 0 0 1 .5 .6 .54 .54 0 0 1-.6 .5 .75 .75 0 0 1 0-1z" fill="#f1975a"/>
<path d="M190.8 171.2l.1-.1a.54 .54 0 0 1 .5 .6 .54 .54 0 0 1-.6 .5 .75 .75 0 0 1 0-1z" fill="none" stroke="#f1975a" stroke-width=".26"/>
<path d="M191.7 171.2l.1-.1a.54 .54 0 0 1 .5 .6 .54 .54 0 0 1-.6 .5 .75 .75 0 0 1 0-1z" fill="#f1975a"/>
<path d="M191.7 171.2l.1-.1a.54 .54 0 0 1 .5 .6 .54 .54 0 0 1-.6 .5 .75 .75 0 0 1 0-1z" fill="none" stroke="#f1975a" stroke-width=".26"/>
<path d="M192.6 171.2l.2-.1a.64 .64 0 0 1 .3 .6 .64 .64 0 0 1-.3 .6 .61 .61 0 0 1-.5-.5 .61 .61 0 0 1 .3-.6z" fill="#f1975a"/>
<path d="M192.6 171.2l.2-.1a.64 .64 0 0 1 .3 .6 .64 .64 0 0 1-.3 .6 .61 .61 0 0 1-.5-.5 .61 .61 0 0 1 .3-.6z" fill="none" stroke="#f1975a" stroke-width=".26"/>
<path d="M192.7 171.7h-12.5l-9.5 .5a15.2 15.2 0 0 0-7.5 2.4 17.7 17.7 0 0 0-5 7.3l-5 11.7a53.2 53.2 0 0 0-3.3 9.4l-.1 .3-.5 .2-1.3-.1-17.8 .1" fill="none" stroke="#b8b8b8" stroke-width=".44"/>
<path d="M129.9 202.9l.2-.1a.59 .59 0 0 1 .4 .6 .59 .59 0 0 1-.4 .5 .64 .64 0 0 1-.2-1z" fill="#b8b8b8"/>
<path d="M129.9 202.9l.2-.1a.59 .59 0 0 1 .4 .6 .59 .59 0 0 1-.4 .5 .64 .64 0 0 1-.2-1z" fill="none" stroke="#b8b8b8" stroke-width=".26"/>
<path d="M130.8 202.9l.2-.1a.64 .64 0 0 1 .4 .6 .64 .64 0 0 1-.4 .5 .6 .6 0 0 1-.4-.4 .6 .6 0 0 1 .2-.6z" fill="#b8b8b8"/>
<path d="M130.8 202.9l.2-.1a.64 .64 0 0 1 .4 .6 .64 .64 0 0 1-.4 .5 .6 .6 0 0 1-.4-.4 .6 .6 0 0 1 .2-.6z" fill="none" stroke="#b8b8b8" stroke-width=".26"/>
<path d="M131.8 202.9l.1-.1a.64 .64 0 0 1 .4 .6 .64 .64 0 0 1-.4 .5 .64 .64 0 0 1-.1-1z" fill="#b8b8b8"/>
<path d="M131.8 202.9l.1-.1a.64 .64 0 0 1 .4 .6 .64 .64 0 0 1-.4 .5 .64 .64 0 0 1-.1-1z" fill="none" stroke="#b8b8b8" stroke-width=".26"/>
<path d="M132.6 202.9l.2-.1a.59 .59 0 0 1 .4 .6 .59 .59 0 0 1-.4 .5 .64 .64 0 0 1-.2-1z" fill="#b8b8b8"/>
<path d="M132.6 202.9l.2-.1a.59 .59 0 0 1 .4 .6 .59 .59 0 0 1-.4 .5 .64 .64 0 0 1-.2-1z" fill="none" stroke="#b8b8b8" stroke-width=".26"/>
<path d="M133.5 202.9l.2-.1a.59 .59 0 0 1 .4 .6 .59 .59 0 0 1-.4 .5 .64 .64 0 0 1-.2-1z" fill="#b8b8b8"/>
<path d="M133.5 202.9l.2-.1a.59 .59 0 0 1 .4 .6 .59 .59 0 0 1-.4 .5 .64 .64 0 0 1-.2-1z" fill="none" stroke="#b8b8b8" stroke-width=".26"/>
<path d="M134.4 202.9l.3-.1a.64 .64 0 0 1 .3 .6 .64 .64 0 0 1-.3 .5 .6 .6 0 0 1-.5-.4 .6 .6 0 0 1 .2-.6z" fill="#b8b8b8"/>
<path d="M134.4 202.9l.3-.1a.64 .64 0 0 1 .3 .6 .64 .64 0 0 1-.3 .5 .6 .6 0 0 1-.5-.4 .6 .6 0 0 1 .2-.6z" fill="none" stroke="#b8b8b8" stroke-width=".26"/>
<path d="M135.3 202.9l.2-.1a.64 .64 0 0 1 .4 .6 .64 .64 0 0 1-.4 .5 .6 .6 0 0 1-.4-.4 .6 .6 0 0 1 .2-.6z" fill="#b8b8b8"/>
<path d="M135.3 202.9l.2-.1a.64 .64 0 0 1 .4 .6 .64 .64 0 0 1-.4 .5 .6 .6 0 0 1-.4-.4 .6 .6 0 0 1 .2-.6z" fill="none" stroke="#b8b8b8" stroke-width=".26"/>
<path d="M136.2 202.9l.2-.1a.64 .64 0 0 1 .4 .6 .64 .64 0 0 1-.4 .5 .64 .64 0 0 1-.2-1z" fill="#b8b8b8"/>
<path d="M136.2 202.9l.2-.1a.64 .64 0 0 1 .4 .6 .64 .64 0 0 1-.4 .5 .64 .64 0 0 1-.2-1z" fill="none" stroke="#b8b8b8" stroke-width=".26"/>
<path d="M137.1 202.9l.2-.1a.59 .59 0 0 1 .4 .6 .59 .59 0 0 1-.4 .5 .64 .64 0 0 1-.2-1z" fill="#b8b8b8"/>
<path d="M137.1 202.9l.2-.1a.59 .59 0 0 1 .4 .6 .59 .59 0 0 1-.4 .5 .64 .64 0 0 1-.2-1z" fill="none" stroke="#b8b8b8" stroke-width=".26"/>
<path d="M138 202.9l.2-.1a.59 .59 0 0 1 .4 .6 .59 .59 0 0 1-.4 .5 .64 .64 0 0 1-.2-1z" fill="#b8b8b8"/>
<path d="M138 202.9l.2-.1a.59 .59 0 0 1 .4 .6 .59 .59 0 0 1-.4 .5 .64 .64 0 0 1-.2-1z" fill="none" stroke="#b8b8b8" stroke-width=".26"/>
<path d="M138.9 202.9l.2-.1a.64 .64 0 0 1 .4 .6 .64 .64 0 0 1-.4 .5 .6 .6 0 0 1-.4-.4 .6 .6 0 0 1 .2-.6z" fill="#b8b8b8"/>
<path d="M138.9 202.9l.2-.1a.64 .64 0 0 1 .4 .6 .64 .64 0 0 1-.4 .5 .6 .6 0 0 1-.4-.4 .6 .6 0 0 1 .2-.6z" fill="none" stroke="#b8b8b8" stroke-width=".26"/>
<path d="M139.9 202.9l.1-.1a.64 .64 0 0 1 .4 .6 .64 .64 0 0 1-.4 .5 .64 .64 0 0 1-.1-1z" fill="#b8b8b8"/>
<path d="M139.9 202.9l.1-.1a.64 .64 0 0 1 .4 .6 .64 .64 0 0 1-.4 .5 .64 .64 0 0 1-.1-1z" fill="none" stroke="#b8b8b8" stroke-width=".26"/>
<path d="M140.7 202.9l.2-.1a.59 .59 0 0 1 .5 .6 .59 .59 0 0 1-.5 .5 .64 .64 0 0 1-.2-1z" fill="#b8b8b8"/>
<path d="M140.7 202.9l.2-.1a.59 .59 0 0 1 .5 .6 .59 .59 0 0 1-.5 .5 .64 .64 0 0 1-.2-1z" fill="none" stroke="#b8b8b8" stroke-width=".26"/>
<path d="M141.6 202.9l.2-.1a.59 .59 0 0 1 .4 .6 .59 .59 0 0 1-.4 .5 .64 .64 0 0 1-.2-1z" fill="#b8b8b8"/>
<path d="M141.6 202.9l.2-.1a.59 .59 0 0 1 .4 .6 .59 .59 0 0 1-.4 .5 .64 .64 0 0 1-.2-1z" fill="none" stroke="#b8b8b8" stroke-width=".26"/>
<path d="M142.5 202.9l.3-.1a.64 .64 0 0 1 .3 .6 .64 .64 0 0 1-.3 .5 .6 .6 0 0 1-.5-.4 .6 .6 0 0 1 .2-.6z" fill="#b8b8b8"/>
<path d="M142.5 202.9l.3-.1a.64 .64 0 0 1 .3 .6 .64 .64 0 0 1-.3 .5 .6 .6 0 0 1-.5-.4 .6 .6 0 0 1 .2-.6z" fill="none" stroke="#b8b8b8" stroke-width=".26"/>
<path d="M143.4 202.9l.2-.1a.64 .64 0 0 1 .4 .6 .64 .64 0 0 1-.4 .5 .6 .6 0 0 1-.4-.4 .6 .6 0 0 1 .2-.6z" fill="#b8b8b8"/>
<path d="M143.4 202.9l.2-.1a.64 .64 0 0 1 .4 .6 .64 .64 0 0 1-.4 .5 .6 .6 0 0 1-.4-.4 .6 .6 0 0 1 .2-.6z" fill="none" stroke="#b8b8b8" stroke-width=".26"/>
<path d="M144.4 202.9l.1-.1a.64 .64 0 0 1 .4 .6 .64 .64 0 0 1-.4 .5 .64 .64 0 0 1-.1-1z" fill="#b8b8b8"/>
<path d="M144.4 202.9l.1-.1a.64 .64 0 0 1 .4 .6 .64 .64 0 0 1-.4 .5 .64 .64 0 0 1-.1-1z" fill="none" stroke="#b8b8b8" stroke-width=".26"/>
<path d="M145.2 202.9l.2-.1a.59 .59 0 0 1 .4 .6 .59 .59 0 0 1-.4 .5 .64 .64 0 0 1-.2-1z" fill="#b8b8b8"/>
<path d="M145.2 202.9l.2-.1a.59 .59 0 0 1 .4 .6 .59 .59 0 0 1-.4 .5 .64 .64 0 0 1-.2-1z" fill="none" stroke="#b8b8b8" stroke-width=".26"/>
<path d="M146.1 202.9l.2-.1a.59 .59 0 0 1 .4 .6 .59 .59 0 0 1-.4 .5 .64 .64 0 0 1-.2-1z" fill="#b8b8b8"/>
<path d="M146.1 202.9l.2-.1a.59 .59 0 0 1 .4 .6 .59 .59 0 0 1-.4 .5 .64 .64 0 0 1-.2-1z" fill="none" stroke="#b8b8b8" stroke-width=".26"/>
<path d="M146.9 202.9l.2-.1a.59 .59 0 0 1 .4 .6 .59 .59 0 0 1-.4 .5 .64 .64 0 0 1-.2-1z" fill="#b8b8b8"/>
<path d="M146.9 202.9l.2-.1a.59 .59 0 0 1 .4 .6 .59 .59 0 0 1-.4 .5 .64 .64 0 0 1-.2-1z" fill="none" stroke="#b8b8b8" stroke-width=".26"/>
<path d="M147.8 202.9l.2-.1a.59 .59 0 0 1 .4 .6 .59 .59 0 0 1-.4 .5 .64 .64 0 0 1-.2-1z" fill="#b8b8b8"/>
<path d="M147.8 202.9l.2-.1a.59 .59 0 0 1 .4 .6 .59 .59 0 0 1-.4 .5 .64 .64 0 0 1-.2-1z" fill="none" stroke="#b8b8b8" stroke-width=".26"/>
<path d="M148.7 202.9l.2-.1a.64 .64 0 0 1 .4 .6 .64 .64 0 0 1-.4 .5 .6 .6 0 0 1-.4-.4 .6 .6 0 0 1 .2-.6z" fill="#b8b8b8"/>
<path d="M148.7 202.9l.2-.1a.64 .64 0 0 1 .4 .6 .64 .64 0 0 1-.4 .5 .6 .6 0 0 1-.4-.4 .6 .6 0 0 1 .2-.6z" fill="none" stroke="#b8b8b8" stroke-width=".26"/>
<path d="M149.6 202.7l.2-.1a.64 .64 0 0 1 .4 .6 .64 .64 0 0 1-.4 .5 .64 .64 0 0 1-.2-1z" fill="#b8b8b8"/>
<path d="M149.6 202.7l.2-.1a.64 .64 0 0 1 .4 .6 .64 .64 0 0 1-.4 .5 .64 .64 0 0 1-.2-1z" fill="none" stroke="#b8b8b8" stroke-width=".26"/>
<path d="M150.5 200h.2a.59 .59 0 0 1 .4 .5 .59 .59 0 0 1-.4 .6 .64 .64 0 0 1-.2-1.1z" fill="#b8b8b8"/>
<path d="M150.5 200h.2a.59 .59 0 0 1 .4 .5 .59 .59 0 0 1-.4 .6 .64 .64 0 0 1-.2-1.1z" fill="none" stroke="#b8b8b8" stroke-width=".26"/>
<path d="M151.4 197h.2a.59 .59 0 0 1 .4 .5 .59 .59 0 0 1-.4 .6 .64 .64 0 0 1-.2-1.1z" fill="#b8b8b8"/>
<path d="M151.4 197h.2a.59 .59 0 0 1 .4 .5 .59 .59 0 0 1-.4 .6 .64 .64 0 0 1-.2-1.1z" fill="none" stroke="#b8b8b8" stroke-width=".26"/>
<path d="M152.3 195l.2-.1a.64 .64 0 0 1 .4 .6 .64 .64 0 0 1-.4 .6 .61 .61 0 0 1-.4-.5 .61 .61 0 0 1 .2-.6z" fill="#b8b8b8"/>
<path d="M152.3 195l.2-.1a.64 .64 0 0 1 .4 .6 .64 .64 0 0 1-.4 .6 .61 .61 0 0 1-.4-.5 .61 .61 0 0 1 .2-.6z" fill="none" stroke="#b8b8b8" stroke-width=".26"/>
<path d="M153.2 192.5h.2a.64 .64 0 0 1 .4 .5 .64 .64 0 0 1-.4 .6 .6 .6 0 0 1-.4-.5 .6 .6 0 0 1 .2-.6z" fill="#b8b8b8"/>
<path d="M153.2 192.5h.2a.64 .64 0 0 1 .4 .5 .64 .64 0 0 1-.4 .6 .6 .6 0 0 1-.4-.5 .6 .6 0 0 1 .2-.6z" fill="none" stroke="#b8b8b8" stroke-width=".26"/>
<path d="M154.1 190.5l.2-.1a.64 .64 0 0 1 .4 .6 .64 .64 0 0 1-.4 .6 .66 .66 0 0 1-.2-1.1z" fill="#b8b8b8"/>
<path d="M154.1 190.5l.2-.1a.64 .64 0 0 1 .4 .6 .64 .64 0 0 1-.4 .6 .66 .66 0 0 1-.2-1.1z" fill="none" stroke="#b8b8b8" stroke-width=".26"/>
<path d="M155 188.5a.49 .49 0 0 1 .6 .4 .49 .49 0 0 1-.6 .5 .7 .7 0 0 1 0-.9z" fill="#b8b8b8"/>
<path d="M155 188.5a.49 .49 0 0 1 .6 .4 .49 .49 0 0 1-.6 .5 .7 .7 0 0 1 0-.9z" fill="none" stroke="#b8b8b8" stroke-width=".26"/>
<path d="M155.9 186.4l.2-.1a.59 .59 0 0 1 .4 .6 .59 .59 0 0 1-.4 .5 .64 .64 0 0 1-.2-1z" fill="#b8b8b8"/>
<path d="M155.9 186.4l.2-.1a.59 .59 0 0 1 .4 .6 .59 .59 0 0 1-.4 .5 .64 .64 0 0 1-.2-1z" fill="none" stroke="#b8b8b8" stroke-width=".26"/>
<path d="M156.8 184.3h.2a.64 .64 0 0 1 .4 .5 .64 .64 0 0 1-.4 .6 .61 .61 0 0 1-.4-.5 .61 .61 0 0 1 .2-.6z" fill="#b8b8b8"/>
<path d="M156.8 184.3h.2a.64 .64 0 0 1 .4 .5 .64 .64 0 0 1-.4 .6 .61 .61 0 0 1-.4-.5 .61 .61 0 0 1 .2-.6z" fill="none" stroke="#b8b8b8" stroke-width=".26"/>
<path d="M157.7 182.2l.2-.1a.64 .64 0 0 1 .4 .6 .64 .64 0 0 1-.4 .6 .64 .64 0 0 1-.2-1.1z" fill="#b8b8b8"/>
<path d="M157.7 182.2l.2-.1a.64 .64 0 0 1 .4 .6 .64 .64 0 0 1-.4 .6 .64 .64 0 0 1-.2-1.1z" fill="none" stroke="#b8b8b8" stroke-width=".26"/>
<path d="M158.6 180.2l.2-.1a.54 .54 0 0 1 .4 .6 .54 .54 0 0 1-.6 .5 .75 .75 0 0 1 0-1z" fill="#b8b8b8"/>
<path d="M158.6 180.2l.2-.1a.54 .54 0 0 1 .4 .6 .54 .54 0 0 1-.6 .5 .75 .75 0 0 1 0-1z" fill="none" stroke="#b8b8b8" stroke-width=".26"/>
<path d="M159.5 178.5l.2-.1a.54 .54 0 0 1 .4 .6 .54 .54 0 0 1-.6 .5 .75 .75 0 0 1 0-1z" fill="#b8b8b8"/>
<path d="M159.5 178.5l.2-.1a.54 .54 0 0 1 .4 .6 .54 .54 0 0 1-.6 .5 .75 .75 0 0 1 0-1z" fill="none" stroke="#b8b8b8" stroke-width=".26"/>
<path d="M160.4 177l.2-.1a.64 .64 0 0 1 .4 .6 .64 .64 0 0 1-.4 .6 .61 .61 0 0 1-.4-.5 .61 .61 0 0 1 .2-.6z" fill="#b8b8b8"/>
<path d="M160.4 177l.2-.1a.64 .64 0 0 1 .4 .6 .64 .64 0 0 1-.4 .6 .61 .61 0 0 1-.4-.5 .61 .61 0 0 1 .2-.6z" fill="none" stroke="#b8b8b8" stroke-width=".26"/>
<path d="M161.3 175.7l.2-.1a.64 .64 0 0 1 .4 .6 .64 .64 0 0 1-.4 .6 .61 .61 0 0 1-.4-.5 .61 .61 0 0 1 .2-.6z" fill="#b8b8b8"/>
<path d="M161.3 175.7l.2-.1a.64 .64 0 0 1 .4 .6 .64 .64 0 0 1-.4 .6 .61 .61 0 0 1-.4-.5 .61 .61 0 0 1 .2-.6z" fill="none" stroke="#b8b8b8" stroke-width=".26"/>
<path d="M162.2 174.7l.2-.1a.64 .64 0 0 1 .4 .6 .64 .64 0 0 1-.4 .6 .64 .64 0 0 1-.2-1.1z" fill="#b8b8b8"/>
<path d="M162.2 174.7l.2-.1a.64 .64 0 0 1 .4 .6 .64 .64 0 0 1-.4 .6 .64 .64 0 0 1-.2-1.1z" fill="none" stroke="#b8b8b8" stroke-width=".26"/>
<path d="M163.1 174l.2-.1a.54 .54 0 0 1 .4 .6 .54 .54 0 0 1-.6 .5 .75 .75 0 0 1 0-1z" fill="#b8b8b8"/>
<path d="M163.1 174l.2-.1a.54 .54 0 0 1 .4 .6 .54 .54 0 0 1-.6 .5 .75 .75 0 0 1 0-1z" fill="none" stroke="#b8b8b8" stroke-width=".26"/>
<path d="M164 173.5l.3-.1a.5 .5 0 0 1 .3 .6 .5 .5 0 0 1-.6 .4 .61 .61 0 0 1 0-.9z" fill="#b8b8b8"/>
<path d="M164 173.5l.3-.1a.5 .5 0 0 1 .3 .6 .5 .5 0 0 1-.6 .4 .61 .61 0 0 1 0-.9z" fill="none" stroke="#b8b8b8" stroke-width=".26"/>
<path d="M164.8 173h.2a.59 .59 0 0 1 .4 .5 .59 .59 0 0 1-.4 .6 .64 .64 0 0 1-.2-1.1z" fill="#b8b8b8"/>
<path d="M164.8 173h.2a.59 .59 0 0 1 .4 .5 .59 .59 0 0 1-.4 .6 .64 .64 0 0 1-.2-1.1z" fill="none" stroke="#b8b8b8" stroke-width=".26"/>
<path d="M165.7 172.7l.1-.1a.54 .54 0 0 1 .5 .6 .54 .54 0 0 1-.6 .5 .75 .75 0 0 1 0-1z" fill="#b8b8b8"/>
<path d="M165.7 172.7l.1-.1a.54 .54 0 0 1 .5 .6 .54 .54 0 0 1-.6 .5 .75 .75 0 0 1 0-1z" fill="none" stroke="#b8b8b8" stroke-width=".26"/>
<path d="M166.6 172.3h.2a.64 .64 0 0 1 .4 .5 .64 .64 0 0 1-.4 .6 .61 .61 0 0 1-.4-.5 .61 .61 0 0 1 .2-.6z" fill="#b8b8b8"/>
<path d="M166.6 172.3h.2a.64 .64 0 0 1 .4 .5 .64 .64 0 0 1-.4 .6 .61 .61 0 0 1-.4-.5 .61 .61 0 0 1 .2-.6z" fill="none" stroke="#b8b8b8" stroke-width=".26"/>
<path d="M167.5 172.2l.2-.1a.51 .51 0 0 1 .3 .6 .51 .51 0 0 1-.5 .4 .67 .67 0 0 1 0-.9z" fill="#b8b8b8"/>
<path d="M167.5 172.2l.2-.1a.51 .51 0 0 1 .3 .6 .51 .51 0 0 1-.5 .4 .67 .67 0 0 1 0-.9z" fill="none" stroke="#b8b8b8" stroke-width=".26"/>
<path d="M168.4 172h.4a.57 .57 0 0 1 .2 .5 .57 .57 0 0 1-.4 .5 .6 .6 0 0 1-.2-1z" fill="#b8b8b8"/>
<path d="M168.4 172h.4a.57 .57 0 0 1 .2 .5 .57 .57 0 0 1-.4 .5 .6 .6 0 0 1-.2-1z" fill="none" stroke="#b8b8b8" stroke-width=".26"/>
<path d="M169.3 171.7l.1-.1a.59 .59 0 0 1 .5 .6 .59 .59 0 0 1-.5 .6 .64 .64 0 0 1-.1-1.1z" fill="#b8b8b8"/>
<path d="M169.3 171.7l.1-.1a.59 .59 0 0 1 .5 .6 .59 .59 0 0 1-.5 .6 .64 .64 0 0 1-.1-1.1z" fill="none" stroke="#b8b8b8" stroke-width=".26"/>
<path d="M170.2 171.7l.2-.1a.64 .64 0 0 1 .4 .6 .64 .64 0 0 1-.4 .6 .6 .6 0 0 1-.4-.5 .6 .6 0 0 1 .2-.6z" fill="#b8b8b8"/>
<path d="M170.2 171.7l.2-.1a.64 .64 0 0 1 .4 .6 .64 .64 0 0 1-.4 .6 .6 .6 0 0 1-.4-.5 .6 .6 0 0 1 .2-.6z" fill="none" stroke="#b8b8b8" stroke-width=".26"/>
<path d="M171.1 171.5h.2a.64 .64 0 0 1 .4 .5 .64 .64 0 0 1-.4 .6 .6 .6 0 0 1-.5-.4 .6 .6 0 0 1 .3-.7z" fill="#b8b8b8"/>
<path d="M171.1 171.5h.2a.64 .64 0 0 1 .4 .5 .64 .64 0 0 1-.4 .6 .6 .6 0 0 1-.5-.4 .6 .6 0 0 1 .3-.7z" fill="none" stroke="#b8b8b8" stroke-width=".26"/>
<path d="M172 171.5h.2a.64 .64 0 0 1 .3 .5 .64 .64 0 0 1-.3 .6 .64 .64 0 0 1-.2-1.1z" fill="#b8b8b8"/>
<path d="M172 171.5h.2a.64 .64 0 0 1 .3 .5 .64 .64 0 0 1-.3 .6 .64 .64 0 0 1-.2-1.1z" fill="none" stroke="#b8b8b8" stroke-width=".26"/>
<path d="M172.9 171.4l.2-.1a.59 .59 0 0 1 .4 .6 .59 .59 0 0 1-.4 .5 .64 .64 0 0 1-.2-1z" fill="#b8b8b8"/>
<path d="M172.9 171.4l.2-.1a.59 .59 0 0 1 .4 .6 .59 .59 0 0 1-.4 .5 .64 .64 0 0 1-.2-1z" fill="none" stroke="#b8b8b8" stroke-width=".26"/>
<path d="M173.8 171.4l.1-.1a.59 .59 0 0 1 .5 .6 .59 .59 0 0 1-.5 .5 .64 .64 0 0 1-.1-1z" fill="#b8b8b8"/>
<path d="M173.8 171.4l.1-.1a.59 .59 0 0 1 .5 .6 .59 .59 0 0 1-.5 .5 .64 .64 0 0 1-.1-1z" fill="none" stroke="#b8b8b8" stroke-width=".26"/>
<path d="M174.7 171.4l.2-.1a.64 .64 0 0 1 .4 .6 .64 .64 0 0 1-.4 .5 .6 .6 0 0 1-.4-.4 .6 .6 0 0 1 .2-.6z" fill="#b8b8b8"/>
<path d="M174.7 171.4l.2-.1a.64 .64 0 0 1 .4 .6 .64 .64 0 0 1-.4 .5 .6 .6 0 0 1-.4-.4 .6 .6 0 0 1 .2-.6z" fill="none" stroke="#b8b8b8" stroke-width=".26"/>
<path d="M175.6 171.4l.2-.1a.64 .64 0 0 1 .3 .6 .64 .64 0 0 1-.3 .5 .64 .64 0 0 1-.2-1z" fill="#b8b8b8"/>
<path d="M175.6 171.4l.2-.1a.64 .64 0 0 1 .3 .6 .64 .64 0 0 1-.3 .5 .64 .64 0 0 1-.2-1z" fill="none" stroke="#b8b8b8" stroke-width=".26"/>
<path d="M176.5 171.4l.2-.1a.59 .59 0 0 1 .4 .6 .59 .59 0 0 1-.4 .5 .64 .64 0 0 1-.2-1z" fill="#b8b8b8"/>
<path d="M176.5 171.4l.2-.1a.59 .59 0 0 1 .4 .6 .59 .59 0 0 1-.4 .5 .64 .64 0 0 1-.2-1z" fill="none" stroke="#b8b8b8" stroke-width=".26"/>
<path d="M177.4 171.2l.2-.1a.54 .54 0 0 1 .4 .6 .54 .54 0 0 1-.6 .5 .75 .75 0 0 1 0-1z" fill="#b8b8b8"/>
<path d="M177.4 171.2l.2-.1a.54 .54 0 0 1 .4 .6 .54 .54 0 0 1-.6 .5 .75 .75 0 0 1 0-1z" fill="none" stroke="#b8b8b8" stroke-width=".26"/>
<path d="M178.3 171.2l.2-.1a.64 .64 0 0 1 .4 .6 .64 .64 0 0 1-.4 .6 .61 .61 0 0 1-.4-.5 .61 .61 0 0 1 .2-.6z" fill="#b8b8b8"/>
<path d="M178.3 171.2l.2-.1a.64 .64 0 0 1 .4 .6 .64 .64 0 0 1-.4 .6 .61 .61 0 0 1-.4-.5 .61 .61 0 0 1 .2-.6z" fill="none" stroke="#b8b8b8" stroke-width=".26"/>
<path d="M179.2 171.2l.2-.1a.64 .64 0 0 1 .4 .6 .64 .64 0 0 1-.4 .6 .61 .61 0 0 1-.4-.5 .61 .61 0 0 1 .2-.6z" fill="#b8b8b8"/>
<path d="M179.2 171.2l.2-.1a.64 .64 0 0 1 .4 .6 .64 .64 0 0 1-.4 .6 .61 .61 0 0 1-.4-.5 .61 .61 0 0 1 .2-.6z" fill="none" stroke="#b8b8b8" stroke-width=".26"/>
<path d="M180.1 171.2l.2-.1a.64 .64 0 0 1 .3 .6 .64 .64 0 0 1-.3 .6 .66 .66 0 0 1-.2-1.1z" fill="#b8b8b8"/>
<path d="M180.1 171.2l.2-.1a.64 .64 0 0 1 .3 .6 .64 .64 0 0 1-.3 .6 .66 .66 0 0 1-.2-1.1z" fill="none" stroke="#b8b8b8" stroke-width=".26"/>
<path d="M181 171.2l.2-.1a.54 .54 0 0 1 .4 .6 .54 .54 0 0 1-.6 .5 .75 .75 0 0 1 0-1z" fill="#b8b8b8"/>
<path d="M181 171.2l.2-.1a.54 .54 0 0 1 .4 .6 .54 .54 0 0 1-.6 .5 .75 .75 0 0 1 0-1z" fill="none" stroke="#b8b8b8" stroke-width=".26"/>
<path d="M181.9 171.2l.2-.1a.64 .64 0 0 1 .4 .6 .64 .64 0 0 1-.4 .6 .61 .61 0 0 1-.4-.5 .61 .61 0 0 1 .2-.6z" fill="#b8b8b8"/>
<path d="M181.9 171.2l.2-.1a.64 .64 0 0 1 .4 .6 .64 .64 0 0 1-.4 .6 .61 .61 0 0 1-.4-.5 .61 .61 0 0 1 .2-.6z" fill="none" stroke="#b8b8b8" stroke-width=".26"/>
<path d="M182.7 171.2l.1-.1a.54 .54 0 0 1 .5 .6 .54 .54 0 0 1-.6 .5 .75 .75 0 0 1 0-1z" fill="#b8b8b8"/>
<path d="M182.7 171.2l.1-.1a.54 .54 0 0 1 .5 .6 .54 .54 0 0 1-.6 .5 .75 .75 0 0 1 0-1z" fill="none" stroke="#b8b8b8" stroke-width=".26"/>
<path d="M183.6 171.2l.1-.1a.54 .54 0 0 1 .5 .6 .54 .54 0 0 1-.6 .5 .75 .75 0 0 1 0-1z" fill="#b8b8b8"/>
<path d="M183.6 171.2l.1-.1a.54 .54 0 0 1 .5 .6 .54 .54 0 0 1-.6 .5 .75 .75 0 0 1 0-1z" fill="none" stroke="#b8b8b8" stroke-width=".26"/>
<path d="M184.5 171.2l.2-.1a.64 .64 0 0 1 .3 .6 .64 .64 0 0 1-.3 .6 .61 .61 0 0 1-.5-.5 .61 .61 0 0 1 .3-.6z" fill="#b8b8b8"/>
<path d="M184.5 171.2l.2-.1a.64 .64 0 0 1 .3 .6 .64 .64 0 0 1-.3 .6 .61 .61 0 0 1-.5-.5 .61 .61 0 0 1 .3-.6z" fill="none" stroke="#b8b8b8" stroke-width=".26"/>
<path d="M185.4 171.2l.2-.1a.64 .64 0 0 1 .3 .6 .64 .64 0 0 1-.3 .6 .66 .66 0 0 1-.2-1.1z" fill="#b8b8b8"/>
<path d="M185.4 171.2l.2-.1a.64 .64 0 0 1 .3 .6 .64 .64 0 0 1-.3 .6 .66 .66 0 0 1-.2-1.1z" fill="none" stroke="#b8b8b8" stroke-width=".26"/>
<path d="M186.3 171.2l.2-.1a.54 .54 0 0 1 .4 .6 .54 .54 0 0 1-.6 .5 .75 .75 0 0 1 0-1z" fill="#b8b8b8"/>
<path d="M186.3 171.2l.2-.1a.54 .54 0 0 1 .4 .6 .54 .54 0 0 1-.6 .5 .75 .75 0 0 1 0-1z" fill="none" stroke="#b8b8b8" stroke-width=".26"/>
<path d="M187.2 171.2l.1-.1a.54 .54 0 0 1 .5 .6 .54 .54 0 0 1-.6 .5 .75 .75 0 0 1 0-1z" fill="#b8b8b8"/>
<path d="M187.2 171.2l.1-.1a.54 .54 0 0 1 .5 .6 .54 .54 0 0 1-.6 .5 .75 .75 0 0 1 0-1z" fill="none" stroke="#b8b8b8" stroke-width=".26"/>
<path d="M188.1 171.2l.2-.1a.64 .64 0 0 1 .4 .6 .64 .64 0 0 1-.4 .6 .61 .61 0 0 1-.4-.5 .61 .61 0 0 1 .2-.6z" fill="#b8b8b8"/>
<path d="M188.1 171.2l.2-.1a.64 .64 0 0 1 .4 .6 .64 .64 0 0 1-.4 .6 .61 .61 0 0 1-.4-.5 .61 .61 0 0 1 .2-.6z" fill="none" stroke="#b8b8b8" stroke-width=".26"/>
<path d="M189 171.2l.2-.1a.64 .64 0 0 1 .3 .6 .64 .64 0 0 1-.3 .6 .61 .61 0 0 1-.5-.5 .61 .61 0 0 1 .3-.6z" fill="#b8b8b8"/>
<path d="M189 171.2l.2-.1a.64 .64 0 0 1 .3 .6 .64 .64 0 0 1-.3 .6 .61 .61 0 0 1-.5-.5 .61 .61 0 0 1 .3-.6z" fill="none" stroke="#b8b8b8" stroke-width=".26"/>
<path d="M189.9 171.2l.2-.1a.64 .64 0 0 1 .3 .6 .64 .64 0 0 1-.3 .6 .66 .66 0 0 1-.2-1.1z" fill="#b8b8b8"/>
<path d="M189.9 171.2l.2-.1a.64 .64 0 0 1 .3 .6 .64 .64 0 0 1-.3 .6 .66 .66 0 0 1-.2-1.1z" fill="none" stroke="#b8b8b8" stroke-width=".26"/>
<path d="M190.8 171.2l.1-.1a.54 .54 0 0 1 .5 .6 .54 .54 0 0 1-.6 .5 .75 .75 0 0 1 0-1z" fill="#b8b8b8"/>
<path d="M190.8 171.2l.1-.1a.54 .54 0 0 1 .5 .6 .54 .54 0 0 1-.6 .5 .75 .75 0 0 1 0-1z" fill="none" stroke="#b8b8b8" stroke-width=".26"/>
<path d="M191.7 171.2l.1-.1a.54 .54 0 0 1 .5 .6 .54 .54 0 0 1-.6 .5 .75 .75 0 0 1 0-1z" fill="#b8b8b8"/>
<path d="M191.7 171.2l.1-.1a.54 .54 0 0 1 .5 .6 .54 .54 0 0 1-.6 .5 .75 .75 0 0 1 0-1z" fill="none" stroke="#b8b8b8" stroke-width=".26"/>
<path d="M192.6 171.2l.2-.1a.64 .64 0 0 1 .3 .6 .64 .64 0 0 1-.3 .6 .61 .61 0 0 1-.5-.5 .61 .61 0 0 1 .3-.6z" fill="#b8b8b8"/>
<path d="M192.6 171.2l.2-.1a.64 .64 0 0 1 .3 .6 .64 .64 0 0 1-.3 .6 .61 .61 0 0 1-.5-.5 .61 .61 0 0 1 .3-.6z" fill="none" stroke="#b8b8b8" stroke-width=".26"/>
<path d="M192.7 171.7l-16.4 .1-6.5 .5a17.7 17.7 0 0 0-7.3 2.2 13.3 13.3 0 0 0-4.5 6.3l-4.8 12a49.3 49.3 0 0 0-2.8 8.6l-.3 1.1a.94 .94 0 0 1-1 1h-18.9" fill="none" stroke="#ffcd33" stroke-width=".44"/>
<path d="M129.7 168.5h63.4v50.8h-63.4z" fill="none" stroke="#000" stroke-width=".26"/>
<path d="M169.8 197.7h21.1v21h-21.1z" fill-rule="evenodd" fill="#fff"/>
<path d="M170.9 199.9h2.7" fill="none" stroke="#5b9bd5" stroke-width=".44"/>
<path d="M170.9 202.3h2.7" fill="none" stroke="#ed7d31" stroke-width=".44"/>
<path d="M170.9 204.8h2.7" fill="none" stroke="#a6a6a6" stroke-width=".44"/>
<path d="M170.9 207.4h2.7" fill="none" stroke="#ffc000" stroke-width=".44"/>
<path d="M170.9 209.8h2.7" fill="none" stroke="#4472c4" stroke-width=".44"/>
<path d="M170.9 212.2h2.7" fill="none" stroke="#70ad47" stroke-width=".44"/>
<path d="M170.9 214.7h2.7" fill="none" stroke="#255e91" stroke-width=".44"/>
<path d="M170.9 217.2h2.7" fill="none" stroke="#9e480e" stroke-width=".44"/>
<path d="M180.6 199.9h2.6" fill="none" stroke="#626262" stroke-width=".44"/>
<path d="M180.6 202.2h2.6" fill="none" stroke="#997300" stroke-width=".44"/>
<path d="M180.6 204.8h2.6" fill="none" stroke="#264478" stroke-width=".44"/>
<path d="M180.6 207.3h2.6" fill="none" stroke="#43682b" stroke-width=".44"/>
<path d="M180.6 209.7h2.6" fill="none" stroke="#7cafdd" stroke-width=".44"/>
<path d="M180.6 212.1h2.6" fill="none" stroke="#f1975a" stroke-width=".44"/>
<path d="M180.6 214.7h2.6" fill="none" stroke="#b8b8b8" stroke-width=".44"/>
<path d="M180.6 217.2h2.6" fill="none" stroke="#ffcd33" stroke-width=".44"/>
<use href="#words"/>
</svg>
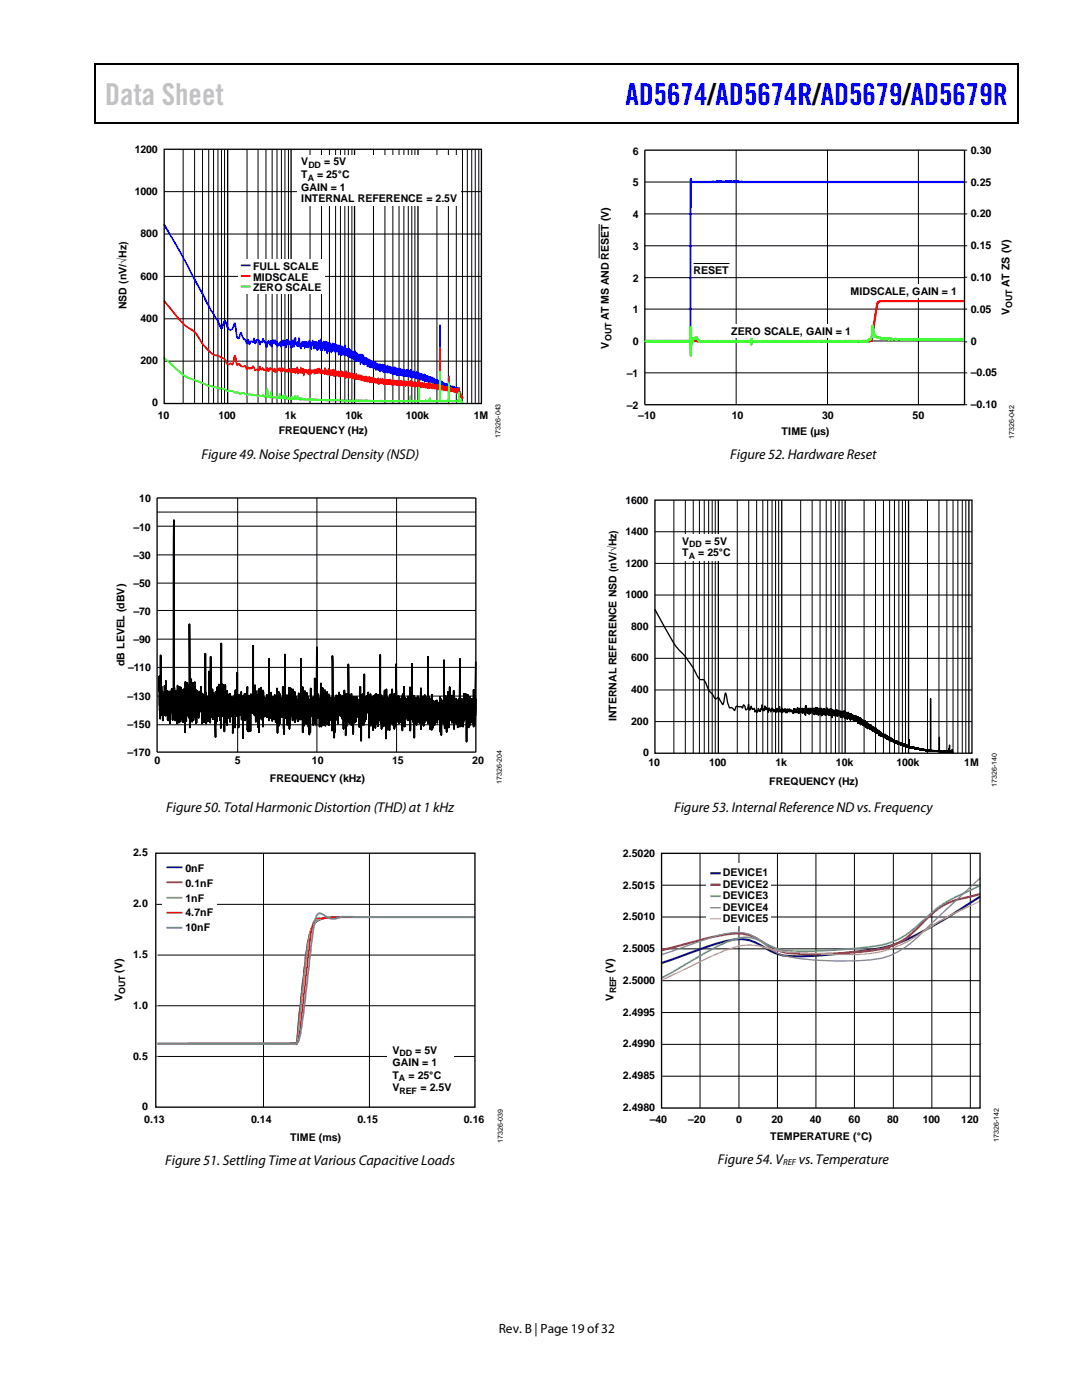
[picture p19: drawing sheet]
<svg xmlns="http://www.w3.org/2000/svg" width="216mm" height="279mm" viewBox="0 0 216 279" stroke-linecap="round" stroke-linejoin="round" font-family="sans-serif">
<defs><g id="words">
<text font-size="6" fill="#c1c1c1" x="21" y="21">Data Sheet</text>
<text font-size="6" fill="#00f" x="124.8" y="21">AD5674/AD5674R/AD5679/AD5679R</text>
<g font-size="2.8">
<text x="40.2" y="91.5">Figure 49. Noise Spectral Density (NSD)</text>
<text x="145.7" y="91.7">Figure 52. Hardware Reset</text>
<text x="33.2" y="162.1">Figure 50. Total Harmonic Distortion (THD) at 1 kHz</text>
<text x="134.5" y="162">Figure 53. Internal Reference ND vs. Frequency</text>
<text x="33" y="232.4">Figure 51. Settling Time at Various Capacitive Loads</text>
<text x="143.3" y="232.3">Figure 54. V</text>
<text x="159.4" y="232.3">vs. Temperature</text>
</g>
<text font-size="2.7" x="99.5" y="266">Rev. B | Page 19 of32</text>
<g font-size="2.1">
<text x="26.9" y="30.5">1200</text>
<text x="60.1" y="35.5">T</text>
<text x="60.1" y="32.9">V</text>
<text x="63.3" y="35.5">= 2</text>
<text x="64.7" y="32.9">= 5V</text>
<text x="66.2" y="35.5">5°C</text>
<text x="126.3" y="30.8">6</text>
<text x="193.7" y="30.7">0.30</text>
<text x="26.9" y="38.9">1000</text>
<text x="60.1" y="38.2">GAIN</text>
<text x="60.1" y="40.3">IN</text>
<text x="62.2" y="40.3">TERNAL REFEREN</text>
<text x="66" y="38.2">=</text>
<text x="67.8" y="38.2">1</text>
<text x="81.5" y="40.3">CE = 2.5V</text>
<text x="126.3" y="37.2">5</text>
<text x="193.7" y="37.1">0.25</text>
<text x="28" y="47.4">800</text>
<text x="126.3" y="43.5">4</text>
<text x="193.7" y="43.4">0.20</text>
<text x="50.5" y="53.8">FU</text>
<text x="53.3" y="53.8">LL</text>
<text x="56.5" y="53.8">S</text>
<text x="57.9" y="53.8">CALE</text>
<text x="126.3" y="49.9">3</text>
<text x="193.7" y="49.8">0.15</text>
<text x="28" y="55.8">600</text>
<text x="50.5" y="56">MIDSCALE</text>
<text x="50.5" y="58">ZERO</text>
<text x="57" y="58">S</text>
<text x="58.4" y="58">CALE</text>
<text x="126.3" y="56.2">2</text>
<text x="138.4" y="54.6">RESET</text>
<text x="169.7" y="58.9">MIDSCALE, GAIN = 1</text>
<text x="193.7" y="56.1">0.10</text>
<text x="201.4" y="57.2" transform="rotate(-90 201.4 57.2)">AT ZS (V)</text>
<text x="25.2" y="61.7" transform="rotate(-90 25.2 61.7)">NSD (nV/√Hz)</text>
<text x="28" y="64.2">400</text>
<text x="121.5" y="63.9" transform="rotate(-90 121.5 63.9)">AT MS AND RESET (V)</text>
<text x="126.3" y="62.6">1</text>
<text x="193.7" y="62.5">0.05</text>
<text x="201.4" y="62.9" transform="rotate(-90 201.4 62.9)">V</text>
<text x="121.5" y="69.6" transform="rotate(-90 121.5 69.6)">V</text>
<text x="126.3" y="68.9">0</text>
<text x="145.9" y="66.8">ZERO SCALE, GAIN = 1</text>
<text x="193.7" y="68.9">0</text>
<text x="28" y="72.7">200</text>
<text x="125.1" y="75.3">–1</text>
<text x="193.7" y="75.1">–0.05</text>
<text x="30.4" y="81.1">0</text>
<text x="31.5" y="83.6">10</text>
<text x="43.6" y="83.6">100</text>
<text x="56.8" y="83.6">1k</text>
<text x="68.9" y="83.6">10k</text>
<text x="81" y="83.6">100k</text>
<text x="94.5" y="83.6">1M</text>
<text x="125.1" y="81.6">–2</text>
<text x="127.4" y="83.6">–10</text>
<text x="146" y="83.6">10</text>
<text x="164" y="83.6">30</text>
<text x="182.1" y="83.6">50</text>
<text x="193.7" y="81.4">–0.10</text>
<text x="55.6" y="86.6">FREQUENCY (Hz)</text>
<text x="156" y="86.8">TIME (µs)</text>
<text x="27.8" y="100.3">10</text>
<text x="124.8" y="100.5">1600</text>
<text x="26.6" y="105.9">–10</text>
<text x="124.8" y="106.8">1400</text>
<text x="26.6" y="111.5">–30</text>
<text x="124.8" y="113.1">1200</text>
<text x="136.1" y="110.9">T</text>
<text x="136.1" y="108.7">V</text>
<text x="139.3" y="110.9">= 25°C</text>
<text x="140.7" y="108.7">= 5V</text>
<text x="26.6" y="117.1">–50</text>
<text x="124.8" y="119.4">1000</text>
<text x="26.6" y="122.8">–70</text>
<text x="126" y="125.7">800</text>
<text x="26.6" y="128.4">–90</text>
<text x="24.8" y="133" transform="rotate(-90 24.8 133)">dB LEVEL (dBV)</text>
<text x="25.6" y="134">–110</text>
<text x="126" y="132">600</text>
<text x="25.4" y="139.6">–130</text>
<text x="123" y="143.9" transform="rotate(-90 123 143.9)">INTERNAL REFERENCE NSD (nV/√Hz)</text>
<text x="126" y="138.3">400</text>
<text x="25.4" y="145.2">–150</text>
<text x="126" y="144.6">200</text>
<text x="25.4" y="150.9">–170</text>
<text x="30.8" y="152.5">0</text>
<text x="46.8" y="152.5">5</text>
<text x="53.8" y="156">FREQUENCY (kHz)</text>
<text x="62.2" y="152.5">10</text>
<text x="78.2" y="152.5">15</text>
<text x="94.2" y="152.5">20</text>
<text x="128.3" y="150.9">0</text>
<text x="129.4" y="152.8">10</text>
<text x="141.5" y="152.8">100</text>
<text x="154.7" y="152.8">1k</text>
<text x="166.8" y="152.8">10k</text>
<text x="178.9" y="152.8">100k</text>
<text x="192.4" y="152.8">1M</text>
<text x="153.5" y="156.6">FREQUENCY (Hz)</text>
<text x="26.6" y="170.9">2.5</text>
<text x="37" y="174">0nF</text>
<text x="124.3" y="171">2.5020</text>
<text x="37" y="177">0.1nF</text>
<text x="37" y="180">1nF</text>
<text x="124.3" y="177.4">2.5015</text>
<text x="144.2" y="174.9">DEVICE1</text>
<text x="144.2" y="177.2">DEVICE2</text>
<text x="144.2" y="179.5">DEVICE3</text>
<text x="26.6" y="181">2.0</text>
<text x="37" y="182.9">4.7nF</text>
<text x="37" y="185.9">10nF</text>
<text x="124.3" y="183.7">2.5010</text>
<text x="144.2" y="181.7">DEVICE4</text>
<text x="144.2" y="184">DEVICE5</text>
<text x="26.6" y="191.2">1.5</text>
<text x="124.3" y="190">2.5005</text>
<text x="24.5" y="194.1" transform="rotate(-90 24.5 194.1)">(V)</text>
<text x="122.4" y="194.1" transform="rotate(-90 122.4 194.1)">(V)</text>
<text x="124.3" y="196.4">2.5000</text>
<text x="24.5" y="199.8" transform="rotate(-90 24.5 199.8)">V</text>
<text x="26.6" y="201.3">1.0</text>
<text x="122.4" y="199.7" transform="rotate(-90 122.4 199.7)">V</text>
<text x="124.3" y="202.7">2.4995</text>
<text x="124.3" y="209">2.4990</text>
<text x="26.6" y="211.5">0.5</text>
<text x="78.3" y="210.3">V</text>
<text x="78.3" y="212.8">GAIN = 1</text>
<text x="78.3" y="215.2">T</text>
<text x="81.5" y="215.2">= 25°C</text>
<text x="82.8" y="210.3">= 5V</text>
<text x="124.3" y="215.4">2.4985</text>
<text x="28.3" y="221.6">0</text>
<text x="78.3" y="217.7">V</text>
<text x="83.9" y="217.7">= 2.5V</text>
<text x="124.3" y="221.7">2.4980</text>
<text x="28.8" y="224">0.13</text>
<text x="50.1" y="224">0.14</text>
<text x="57.9" y="227.7">TIME (ms)</text>
<text x="71.3" y="224">0.15</text>
<text x="92.6" y="224">0.16</text>
<text x="129.6" y="224.1">–40</text>
<text x="137.3" y="224.1">–20</text>
<text x="146.9" y="224.1">0</text>
<text x="153.7" y="227.5">TEMPERATURE (°C)</text>
<text x="153.9" y="224.1">20</text>
<text x="161.6" y="224.1">40</text>
<text x="169.3" y="224.1">60</text>
<text x="177" y="224.1">80</text>
<text x="184.1" y="224.1">100</text>
<text x="191.8" y="224.1">120</text>
</g>
<g font-size="1.8">
<text x="61.5" y="33.4">DD</text>
<text x="61.4" y="36.1">A</text>
<text x="202" y="61.5" transform="rotate(-90 202 61.5)">OUT</text>
<text x="122" y="68.1" transform="rotate(-90 122 68.1)">OUT</text>
<text x="137.4" y="111.5">A</text>
<text x="137.5" y="109.3">DD</text>
<text x="25" y="198.4" transform="rotate(-90 25 198.4)">OUT</text>
<text x="122.9" y="198.3" transform="rotate(-90 122.9 198.3)">REF</text>
<text x="79.6" y="215.8">A</text>
<text x="79.7" y="210.8">DD</text>
<text x="79.7" y="218.2">REF</text>
<text x="156.3" y="232.5">REF</text>
</g>
<g font-size="1.4">
<text x="99.9" y="87.3" transform="rotate(-90 99.9 87.3)">17326-043</text>
<text x="202.4" y="87.5" transform="rotate(-90 202.4 87.5)">17326-042</text>
<text x="100.2" y="156.4" transform="rotate(-90 100.2 156.4)">17326-204</text>
<text x="198.9" y="157" transform="rotate(-90 198.9 157)">17326-140</text>
<text x="199.3" y="227.9" transform="rotate(-90 199.3 227.9)">17326-142</text>
<text x="100.3" y="228.1" transform="rotate(-90 100.3 228.1)">17326-039</text>
</g>
</g></defs>
<path d="M18.9 12.7h.3v1h-.3zM18.9 12.7h.3v.3h-.3zM83.1 12.7h.3v.3h-.3zM202.9 12.7h.3v1h-.3zM202.9 12.7h.3v.3h-.3zM18.9 24.4h.3v.2h-.3zM82.9 24.4h.2v.2h-.2zM202.9 24.4h.3v.2h-.3z" fill="#000"/>
<path d="M19 13.7v10.7M19.2 12.8h63.9M83.4 12.8h119.5M203 13.7v10.7M19.2 24.5h183.7" fill="none" stroke="#000" stroke-width=".25"/>
<g fill="none" stroke="#000" stroke-width=".2">
<path d="M32.8 38.2h63.3M36.5 29.8v50.7M38.8 29.8v50.7M40.4 29.8v50.7M41.6 29.8v50.7M42.6 29.8v50.7M43.5 29.8v50.7M44.2 29.8v50.7M44.8 29.8v50.7M49.3 29.8v50.7M51.5 29.8v50.7M53.1 29.8v50.7"/>
<path d="M54.3 29.8v50.7M55.3 29.8v50.7M56.1 29.8v50.7M56.9 29.8v50.7M57.6 29.8v50.7M61.9 29.8v50.7M64.1 29.8v50.7M65.7 29.8v50.7M67 29.8v50.7M67.9 29.8v50.7M68.8 29.8v50.7M69.5 29.8v50.7"/>
<path d="M70.2 29.8v50.7M74.5 29.8v50.7M76.8 29.8v50.7M78.4 29.8v50.7M79.6 29.8v50.7M80.6 29.8v50.7M81.5 29.8v50.7M82.2 29.8v50.7M82.8 29.8v50.7M87.2 29.8v50.7M89.5 29.8v50.7M91.1 29.8v50.7"/>
<path d="M92.3 29.8v50.7M93.2 29.8v50.7M94.1 29.8v50.7M94.8 29.8v50.7M95.5 29.8v50.7M32.8 46.7h63.3M32.8 55.2h63.3M32.8 63.6h63.3M32.8 72.1h63.3"/>
</g>
<path d="M45.4 29.8v50.7M58.1 29.8v50.7M70.7 29.8v50.7M83.4 29.8v50.7" fill="none" stroke="#000" stroke-width=".26"/>
<path d="M32.7 44.7l.2 .1 3.2 5.4 4.5 8.3 .9 1.9 2.2 3.6 .5 1.3 .4-1.2 .2-.2a1.75 1.75 0 0 1 .8 1.4 .41 .41 0 0 0 .5 .3 .41 .41 0 0 0 .3-.5l.3-.7 .2-.1 .2 .6 .4 2.4 .3-.9 .3-.1 .6 1.1 .5 .6 .3-.4 .2 .1 .1 .4 .3-.2 .2 .1 .2-.5 .3-.1 .2 .6 .1-.3 .3-.1 .4 .2v.3h.4l.2-.6h.2l.2 .5 .1-.1 .2 .2 .1 .4 .3-.6 .4 .2 .1-.3 .3 .2 .2-.3 .2 .2 .1-.2 .3 .1v.3l.3-.1 .2 .5 .4-.5 .3 .2 .1-.4 .5 .1 .1-.1a.49 .49 0 0 1 .7 .1l.4 .2v-.3h.5v-.3l.4-.2 .1 .2 .1 .9 .3-.4v-.6l.3-.1 .1 1.2 .2-.1a.43 .43 0 0 1 .5-.4l.7 .1 .2 .3 .2-.6 .4 .6v-.4l.3-.2 .3 .5 .1-.3 .6 .2 .1-.3 .3 .1 .1-.4h.1l.1 .2v.5l.5-.3 .2 .2 .1-.2 .2 .2 .2-.1 .1 .2a.48 .48 0 0 1 .6 .3l.2 .1a.33 .33 0 0 1 .2-.3 .33 .33 0 0 1 .4 .2l1 .3 .1-.2 .2 .3h.3l.2 .3 .3-.5 .2 .2v.4l.3 .1 .1-.1h.2l.1 .4h.3l.1 .3 .2-.1 .2 .2 .2-.3 .2 .4 .3 .1 .1 .2h.2v.2l.1-.2 .4 .2 .1-.2 .2 .2h.2l.1 .2a.29 .29 0 0 0 .1 .3 .29 .29 0 0 0 .3 0l.7 .3 .5 .5h.3l.2 .2 .3-.2v.3l.5 .2a.27 .27 0 0 1 .3-.1 .27 .27 0 0 1 .2 .3 .35 .35 0 0 1 .6 0l.1-.1 .2 .3 .3-.2 .2 .2h.3l.5 .2h.6v.1l.5 .2 .4-.1 .2 .3h1.4l.2 .2 .4-.2 .3 .3a.31 .31 0 0 1 .3-.1 .31 .31 0 0 1 .2 .3l.5-.1v.2l.9 .2 .2 .1 .3-.1 .4 .4 .1-.1 .4 .3h.4l.1 .1h.1l.3 .2h.2v.2h.5l.3 .3 .1-.1v-10.9l.1-.1h.2l.1 11.1 .5 .4 .9 .2v.2v-1.6l.3-.1v1.7l1.6 .6 .1 .2 .1-.2h.2l.1 .7 .5 1a.3 .3 0 0 1 .1 .4 .3 .3 0 0 1-.4 .2l-.3-.7a1.39 1.39 0 0 0-1.3-.8l-3.5-1.2a1.27 1.27 0 0 0-1.3-.3 .33 .33 0 0 0-.5-.3l-.1-.2-.4 .1-.1-.2-.7-.1-.2-.2h-.6l-.4-.3-.6 .1-.1-.2-.4-.1h-.8l-.2-.1h-.3l-.2-.2-.2 .2-.1-.2-.7 .1v-.1l-.7-.1-.6-.3h-.4l-.6-.2-.2 .2-.3-.4-.4 .2-.4-.4a.31 .31 0 0 1-.4 .1 .31 .31 0 0 1-.1-.3h-.5l-.1-.3-.3 .1-.9-.3-.1-.4-.4 .1v-.1l-.5-.3-.1 .3-.2-.1-.2-.5h-.4l-.2-.1-.2 .2-.3-.6-.8-.2-.1-.3-.2 .1-.2-.3a.38 .38 0 0 1-.6-.2l-.5 .2-.3-.2-.3 .1-.2-.6-.5 .1-.1-.4-.3 .2-.1-.1-.2 .4-.2-.4h-.4l-.1 .5h-.2l-.1-.6-.5 .1-.1-.5-.1 .4-.4 .1-.2-.5-.1 .1a.32 .32 0 0 1-.3 .3 .32 .32 0 0 1-.3-.2v-.5v.3l-.4 .1-.3-.6-.3 .8-.3-.6-.3 .2-.4-.2-.3 .3-.2-.4h-.3v.3l-.2 .2-.2-.2-.1-.2h-.1a.41 .41 0 0 1-.6-.4l-.2-.1a.5 .5 0 0 1-.6 .6l-.4 .1-.2-.9v.3h-.4v.4l-.3 .1-.2-.5-.7 .4-.2-.3h-.3l-.2 .3-.2-.1v-.4h-.3a.26 .26 0 0 0-.2-.2 .26 .26 0 0 0-.3 .1l-.1 .6h-.1l-.6-.7-.2 .7-.2 .1-.2-.2-.1-.6h-.2l-.2-.4-.1 .2-.3 .1-.2 .4-.2-.1-.2-.8-.3 .2-.2 .5-.2-.1-.1-.3-.3 .2-.3-.2-.2 .5-.1 .1-.3-.5-.1 .3h-.3l-.2-.8-.4-.1-.4-1-.3 .9-.6-.2-.4-2.6a.86 .86 0 0 1-.8 1.1 .86 .86 0 0 1-.9-.9l-.2-.8-.5 1.4h-.4l-.1-.2-.7-1.6-1.7-2.7-5-9.6-3.9-6.7z" fill="#0600ff"/>
<path d="M59.4 30.9h32.5v10.1h-32.5z" fill-rule="evenodd" fill="#fff"/>
<path d="M32.7 60l.2 .5 1.5 1.9a12.8 12.8 0 0 0 4.3 4l.5 .7a9.9 9.9 0 0 0 3.8 4h.4l.6 .4a1.44 1.44 0 0 1 1.2 1.2 .43 .43 0 0 0 .8 0l.4 .2 .3-.3 .1-1 .3 1.3 .3 .1 .3-.1 .2 .2a.8 .8 0 0 0 1 .1l.3 .6 .4-.2 .1 .2 .5-.1 .3-.3 .3 .7 .5-.2 .4 .2 .1-.3 .5 .1 .1-.1 .1 .2 .3-.1 .4 .3 .6-.1 .2-.3h.3l.2 .4h.2a.44 .44 0 0 0 .5 .1 .44 .44 0 0 0 .2-.5l.2 .2h.3l.1 .3h.3a.39 .39 0 0 1 .4-.2 .39 .39 0 0 1 .3 .3l.8-.1 .2 .2 .7-.1 .3 .2 .1-.2h.2v.2l.2 .1 .3-.2v-.1l.5 .2 .2-.1v.6l.3-.1v-.5l.2-.2 .2 .4 .5 .2 .2-.3 .2 .1 .4-.3a.33 .33 0 0 0 .2 .3 .33 .33 0 0 0 .4-.2h1.1l.6 .3h.5l.2 .2 .1-.4 .2 .4h.2a.4 .4 0 0 1 .7 .2l.4-.2 .7 .3h.2v-.1h.6l.4 .4 .2-.3h.1a.27 .27 0 0 0 .3 .3 .27 .27 0 0 0 .3-.2l.3 .3 .5-.1 .2 .3a3.1 3.1 0 0 1 2 .3h.7l.2 .3h.3l.1-.2 .7 .3 .2-.1 .5 .3 .2-.2h.4a.54 .54 0 0 0 .8 .1l1 .1 .3 .3 .4-.3 1.2 .3 .8-.1 .2 .2 .2-.2 1.1 .3 .7-.1 .1 .2 .1-.2 .7 .2h.7l.8 .2 .8-.1 .2 .2h.9l.2 .2 .5-.1 .8 .3h.8l1.1 .2a1.69 1.69 0 0 1 1.4 1.4 .3 .3 0 0 0 .5-.2 .3 .3 0 0 0-.2-.4l-.5-1-.1-.7-.2-.1-.1 .3-.3-.1h-.6l-.8-.3v-2.1h-.2l-.1 .1v2l-.6-.1-.4-.4-.3 .2-.1-.1-.1-7.4-.2-.1-.1 .2v7.2h-.9l-.2-.2-.5 .1-.2-.5-.2 .1v.3l-.8-.2-.3 .1-.1-.2a.45 .45 0 0 1-.7-.3v-.2h-.2l-.1 .5h-.3l-1-.2-.2-.1-.2 .2-.1-.1h-1.4l-.1-.2a.62 .62 0 0 1-.9 0l-1 .1a.31 .31 0 0 0-.5-.1l-.5-.2-.5 .1-.3-.3-.4 .2-.1-.2-.2 .2-.2-.3-.4 .2-.9-.3h-.3l-.2-.1-.5 .1-.2-.2h-.7l-.2-.2-.1 .1-.1-.2-.5 .1-.3-.3-.4 .1-.9-.3-.3 .1-.3-.2v-.3l-.2 .1-.2 .3-.3-.2-.1 .1-.2-.3-.4 .2-.3-.2-.4 .1-.2-.2-.1 .1-.2-.3-.4 .1a.42 .42 0 0 1-.6-.2l-.2 .3h-.3l-.2-.5-.2 .2v.4l-.3-.1a1.05 1.05 0 0 0-1.4-.1l-.2-.1-.6 .2-.4-.2-.1 .2-.7-.2-.3 .2-.1-.3-.1-.1-.3 .2-.1-.4h-.2l-.1 .6-.5-.7-.2 .5-.2-.2-.3 .2-.1-.1a.36 .36 0 0 1-.3 .2 .36 .36 0 0 1-.3-.3l-.5 .4-.5-.1-.2-.3-.5-.2-.1 .3-.2-.2-.2 .1a.47 .47 0 0 0-.6 .4l-.2-.4-.3 .1v.2a.62 .62 0 0 0-.9-.3l-.1 .4-.1-.5-.3-.1a.38 .38 0 0 1-.2 .5 .38 .38 0 0 1-.5-.3l-.2-.1-.2 .2-.1-.4-.2-.1-.3 .7-.5-.1a.44 .44 0 0 0-.3-.5 .44 .44 0 0 0-.5 .1l-.4 .2-.3-.3-.2 .2-.2-.3-.3-.1a.75 .75 0 0 1-1-.4l-.1-.1-.3 .2-.3-1.5-.2-.3a1.9 1.9 0 0 0-.5 1.6l-.1 .2-.3-.3-.5 .3a2.8 2.8 0 0 0-2.2-1.8 2.68 2.68 0 0 1-2-1.4l-.8-.9-.7-1.2a4.6 4.6 0 0 0-2.4-2.2l-1.4-1.4-3.1-3.7zM53.6 73.8v.2z" fill="#f00"/>
<path d="M32.7 71.3h.2l1.4 1.2a12.7 12.7 0 0 0 6.2 3.8 3.5 3.5 0 0 0 2 .6l1.3 .5a2.38 2.38 0 0 1 1.7 .5 2.18 2.18 0 0 1 1.6 .3h.4l.6 .2a1.12 1.12 0 0 1 1.2 .2l.7-.1 2 .4 .5-.2 .2 .2h.4v-1.1l.2-.3 .2 .4 .1 1.1h.2l.1-.7 .2-.1 .2 .9 1.2 .1 .1-.7 .3-.1 .2 .8 .1-.3 .3 .1v.2v-.3l.3-.3 .1 .2v.4l.2-.3 .3 .3 .2-.1 .1 .3h.3l.2-.4h.1l.1 .4 .2-.1 .1-.4h.1h.2l.1 .5 .1-.5h.2l.3 .6 .1-.2 .2 .2 .3-.2 .7 .3h.7l.1-.2 .2 .2 .5-.1 1 .2h3.7l14.5 .1v-.7l.2-.2 .2 .2v.7h1.3v-2.5l.2-.2 .2 .2v2.5h1.2a.28 .28 0 0 0 .3 0 .28 .28 0 0 0 .2-.2l.3-.3 .2 .2v.3h1.6v-5.6l.2-.2 .2 .2v5.5l1.1 .1 .3-.1v-3.3l.2-.2 .1 .2v3.4h1.3a.28 .28 0 0 0 .3 0 .28 .28 0 0 0 .1-.2v-1.4l.2-.1 .2 .1v1.7l.1 .1 .1-.4h.3v.5l.2 .3-.3 .1-.5-.2h-17l-9.8-.3-1.5 .1-.7-.2-1.1 .1-.7-.2h-3.3l-.2-.1h-1.9l-.2-.2-1.2 .1-.8-.3h-.6l-.2-.2-.6 .1-3.1-.4a.53 .53 0 0 0-.8 0l-.5-.3-.8-.1a1.22 1.22 0 0 0-1.3-.2l-1-.5h-.8l-1.1-.4-.9-.1-1.3-.6-1.6-.6a7.9 7.9 0 0 1-3.8-2.4l-2.2-2.1z" fill="#26ff00"/>
<path d="M47.4 51.7h17.4v7h-17.4z" fill-rule="evenodd" fill="#fff"/>
<path d="M48.1 53h1.9M94.8 183l-28.7 .1a3.7 3.7 0 0 0-4 2.3l-.7 2.7-.4 2.9-1.3 11.7-.4 5.3-.2 .4-.2-.3-.2 .2h-21.2" fill="none" stroke="#0a347d" stroke-width=".35"/>
<path d="M48.1 55.1h1.9" fill="none" stroke="#f00" stroke-width=".35"/>
<path d="M48.1 57.2h1.9" fill="none" stroke="#00ff1e" stroke-width=".35"/>
<path d="M32.8 29.8h63.3v50.7h-63.3zM31.3 99.4h63.6v50.7h-63.6zM31.1 170.3h63.7v50.7h-63.7z" fill="none" stroke="#000" stroke-width=".26"/>
<g fill="none" stroke="#000" stroke-width=".2">
<path d="M47.4 99.4v50.7M63.2 99.4v50.7M79.1 99.4v50.7M31.3 116.4h63.6M31.3 110.7h63.6M31.3 105h63.6M31.3 102.2h63.6M31.3 138.9h63.6M31.3 133.2h63.6M31.3 127.6h63.6M31.3 121.8h63.6M31.3 144.6h63.6"/>
<path d="M52.6 170.3v50.7M73.7 170.3v50.7M31.2 180.5h63.6M31.4 190.6h63.4M31.4 210.8h63.4M31.4 200.7h63.4"/>
</g>
<path d="M94.9 132.1l-.1 12.5v-4.1v-.1l-.2 3.5v-3.7l-.1 4.8v-7.3l-.1 6.5v-3.9l-.1 4.1v-4l-.1 3.8v-4.7v3.4l-.1-3.3-.2 1.8v-.8v2.4v-3.6v4.1l-.1-4.4v4.4l-.1-4.2v5.5l-.1-5.1-.1 5.5v-4.1v1.6l-.1-2v2.4v-4.4l-.1 4.6-.1-3v.2v3.6l-.1-4.4v8.3v-8.1v-.1l-.1 3.3-.1-4.6v3.9v-1.7l-.1 2.1v-3l-.1 3.8v-3.3v2.8v-2.5l-.1 1.8v-3.9l-.2 6.3v-3.7v3.9l-.1-5v4v-3.4l-.1-.2v2l-.1-3v5.5v-4.4l-.1 3-.1-3.6v3.2v-2.5v2.2l-.1-1.2v3.4v-13.5l-.1 12.5-.1-4.5v4.3l-.2-4.1-.1 5.5v-5l-.1 3.1-.1-2.6v3.8v-4.6l-.1 4v-4.5l-.1 4.9-.1-4.9v3.5v-3.4v2.5l-.1-.3v.4v-1.9l-.1 3.6v-2.9v4.6l-.1-7.6v5.8l-.1-3.5v3.3v-.3l-.1-3.8-.1 4.9v-5.5v3.6l-.1 .7v-3.5l-.1 4.2v-2.7l-.1 2.6-.1-3.7v2.2v-1.1l-.1-3.9v5.5l-.1-1.5v2.6v-3.4v4.8v-4.9l-.1 4.3v-4.2l-.1 4.1v-6.4l-.1 6.1-.1-4.7v2.1l-.1-.7v5.2v-5.9l-.1 4.7-.1-6v4.9l-.1-3.9v5.5l-.1-5.7-.1 3.4v-11.3l-.1 12.6v-3.9l-.1 2.5-.1-1.1v2.1l-.1-4.2-.1 3.8v-2.9v2.6v-1.6v5v-6.1l-.1 .5v-.8v4.5v-5.4l-.1 6.7-.1-7v3.4l-.1-1v1.1v-2.4l-.1 3.4v-3.4l-.1 2.9v-1.8l-.1 .8v-1.8v2.1l-.1-1.6v3.5l-.1-4.5-.2 4v-3.9l-.1 2.8v-2.5l-.1 .1-.1 4.3-.1-4.6v4.6v-4.4l-.1 3v-3.3l-.1 5.2-.1-4.6v4.9l-.1-6.7-.1 7v-5.5l-.1-.5-.1 1.9v-1l-.1 .2v4.7v-6.1v2.5l-.1-1v1.6v-2.1l-.1 3.4v-4.7l-.1 3.3-.1-2.4v4.4v-13.3v11.8l-.1-3.5v3.6l-.2-3.6v4.3l-.1-4.6-.1 4.9-.1-5.3-.1 5.2-.1-4.9v5.7l-.1-4v4.1l-.1-5.8v4v-2.9l-.1 3v-2.5v3.3l-.1-4.5-.2 6.1v-8.2l-.1 7.1-.1-5v4.2l-.1-3v3.6l-.1-4.1v3.6l-.1-2.5v3l-.1-5.3v4.4l-.1-4-.1 4.7v-3.8l-.1 2.6v-2.1v3.9l-.1-5.3-.1 4.2v-3.3l-.1 2.9v-3.7l-.1 7.8-.1-8.4v3.2l-.1-2.3-.1 4.4v-3.2v2.4l-.1-2.7v2.8l-.1-3.4v2.4v-9.9v9.7v-2.5l-.1 2.9v-2.9v3.8l-.1-3.9-.1 6.2-.1-8.6v6.8l-.1-4.4-.1 4.2-.2-4.8-.1 4.8v-3.6v1.7v-1.6l-.1 2.4-.1-2.8-.1 2.8-.1-3.4v4.2v-4.1l-.1 3.5v-2.9v2.5l-.1-2v4.5l-.1-7.9v6v-1.9l-.1 2.1v-2.8v2.9v-4.8v4.7l-.1-4.8-.1 7.3v-6.9l-.2 3.3v-2.6l-.1 1.5v-1.3v4.3l-.1-4.3-.1 4v-4.4l-.1 4.4v-4.8v5.4l-.1-5-.1 3.6v-4.1l-.2 3.8v-3.2l-.1 2.1v-1.9v4.4l-.2-6.7v3.3v-8.1v11.2l-.1-4.2-.1 5.4-.1-6.5v6.9v-6.3l-.2 5.7-.1-5-.1 3.5v-5.7l-.1 6.4-.1-3v3.4v-5l-.1 3.3v-2.7l-.1 1.3v-1.2v3.4v-4.9l-.1 6v-4.5l-.1 .5v5.1v-6v2.1l-.1-2v2.6l-.1-2.4v2.8v-3v2.6l-.1-1.8v5v-6.4l-.1 5-.1-4.8-.1 3.9v-5.7l-.1 9.8v-7.2l-.1 2.2-.1-3.4-.1 4.8v-6v4.7v-3.1l-.1 2.6v-2.3v5.2v-5v3.5l-.1-3.7v2.9l-.1-3.2v2.5l-.1-2.5v5.7v-5.6l-.1 4.1-.1-4.9v6.7v-5.6l-.1 3v-3.9v5.3l-.1-13.5v10.9l-.1-1.5v1.9v-2.6l-.1 4.1-.1-4v-.2v2.9l-.1-2.9v4.5v-5.1l-.1 6.2v-4.8l-.1 4.5v-5.8v3.2l-.1-2.4v4.8l-.1-5.9v3.9v-1.7l-.1 3.5v-4.3l-.1 5.4v-6.6v3.8l-.1-2.7-.1 4.1-.1-5v3.1l-.1-2.2v5.9v-6.7l-.1 3.3v.1l-.1-3-.1 3.8-.1-3.4-.1 5-.1-6.2v3.9v-3.2v-.3l-.2 1.9v-2.1v4v-3.1v2.3v-.9v6.1v-8.3l-.1 3.4-.1-4.1v2.9l-.1-1.3-.1 2.4v-3.3l-.1 3.3-.1-3.2v3.2l-.1-2.6v3.9v-4.3v3v-2.8l-.2 4.6-.1-9.4v8.5l-.1-2.8v4.3v-5.2l-.1 3.1-.1-3.1v2l-.1-.8v.4v-2.4l-.1 6v-5.4v2.9v-2.1l-.1 .6v7.2v-6.6l-.1-2.1v5.2l-.1-7.2v6.5l-.1-5.7-.1 7.2v-5.4l-.1 1.8v-1.8v1.2v-1.1l-.1 .4v2.3v-2.5v1.7l-.1-1.6v3.1v-3.3l-.1 2.7-.1-3.5v3.2l-.2-2.8v4.4v-4l-.1 .5v3.6l-.1-4.9-.1 5.1v-4.8v.8v-1.1v4.6v-4.1l-.1 3.3-.1-3.7v7.3l-.1-7.1-.1 3.7-.1-3.2-.1 4.8v-6.2v4.4l-.1 .2v-2.8l-.1 2.9v-4v4v-3.3l-.1 2.5v-2.4v2.1l-.1-1.3v3.5l-.2-11.7v10.6v-4.5v3l-.1-2.3v3.6l-.1-3.4-.1 4.3v-4.3v3v-1.5v3.8v-6.4l-.2 8.3v-7v2.7l-.1-3.3-.1 4.4-.1-5.8-.1 3.8-.1-2v5.8v-5.5v2.7l-.1-3v2v-2.7l-.1 4.5-.2-3.3v1.9v-2.7l-.1 3.6-.1-4.2-.2 4.1v-4.6l-.1 4.1-.1-3.1v5.3l-.1-4.3v2.2l-.1-2.5v3.9l-.2-5.1-.1 3.3-.1-2.2v6.3l-.1-6.7-.1 7.8-.1-7.9-.1 4.7-.1-4.6v2.8l-.1-11.3-.1 14.9-.1-6.5v3.2l-.1-3.2v3.5l-.1-3.4v4.4l-.1-4.5-.2 4.5v-3.9v4.8v-6v-.1l-.2 4.6v-3.8v2.5v-2v4.7l-.1-6.5v6.3l-.1-5.7v5.7l-.2-4.4v2.7v-.2l-.1-2.8v5.1l-.1-7.1-.2 5.5v-2.6v1.1v-2.3v3.1l-.1-3.1v5.3l-.1-7.4-.1 7.2v-5.6l-.1 4.6-.1-4.7v6.2l-.1-8.6-.1 8.2v-5.1l-.1 5.5v-4.8l-.1 2.3-.1-3.2v3.6l-.1-4.3-.1 4.6-.2-3v2.2v-13.3l-.1 15.6-.1-6v5.8l-.2-9.1v5.2v-1.1l-.1 2.2-.1-2.6-.1 5.6v-5.1l-.1 3.5v-2.6l-.1 1.2-.1-2.1v2.1v-2.6l-.1 2.8-.1-4.5-.1 8.7v-4.9v.4l-.1-.9v3.6l-.1-4.2v6.5l-.1-7v5.5v-5.6l-.1 3.3-.1-2.2v3.2v-4.9l-.1 5.1-.1-5.7-.1 6.2-.1-4.6-.1 3.8v-3l-.1 2.3v-5.1v4v-2.4l-.1 2.4v-1.3v4.2l-.1-6.6-.1 6.1-.1-7.1v8.9l-.1-6.7v3.2l-.1-3.1-.1 3.8v-2.6v.5v-.4v.1v2.7v-12.1l-.1 11.6-.1-4.3-.1 4.8-.2-5.2v4.2v-3.8l-.2 5.1v-3.3v1l-.1-1.7v2.3v-1.8l-.1 1.2-.1-1.6v3.4v-3.4l-.1 2.4-.1-3.4v5l-.1-5.9v5.9v-3.6l-.1 .8v-1l-.1 2.2v-4.4v4.8v-2.8l-.1 2.5v-4.9l-.1 6.2-.1-5.7-.1 4.7-.1-3.2-.1 2.3v-4.5l-.1 5.1v-2.5v2.5v-1.6l-.1 1v-4.6v8.1l-.1-8.2v4.3l-.1 .6-.1-3.4-.1 4.3-.1-4.1v.1v5.6l-.1-5.5v2.4l-.1 .2v-1.5v2.6l-.1-4.2-.1 4.7v-12.7v9.1l-.1 2.5v-2.9l-.1 7.2-.1-7.5v6.4l-.2-8.3v5.7l-.1-2.1v2.4v-3.6v3.6l-.2-3.4v2.9v-3.3l-.1 2.9-.1-2.6v3.4l-.1-1.9v3.3v-5.9l-.1 4.4-.1-4.8v6.7l-.1-5.1v3.4l-.1-2.9v6l-.1-8.8-.1 6.8-.1-5.2-.1 5.1v-4.2l-.1 1.4v-2.4v-.1l-.1 2.6v-2.7v3.3v-2.5l-.1 4.1v-4.1l-.1 3.8-.2-4.2-.1 3.3v-3.1v4.5v-2.8v.6l-.1-2.2-.1 2.5-.1-3.7v5.1v-4.3l-.1 4.1-.1-3.2-.1 .7v3.2v-12.3v11.1l-.1-2.8-.1 3.1v-3.5l-.1 3.7v-2.9l-.1-.3v1.7v-2.9v4.4l-.1-3.8-.1 3.6v-3l-.1 2.2-.1-2.7-.1 3.6-.1-3.6-.1 3.3v-3.6l-.1 4v-5.3v7.2v-5.2l-.1 2.5v-3.7l-.1 4.3v-2.8v.7l-.1-.6v3.4l-.1-6.4v5.1l-.1-3.2-.1 4.2v-3.1v1l-.1-1.6v2.2l-.1-4.3v8.6l-.1-8.3-.1 7.4v-5.3v2.5l-.1-3.5v5l-.1-5.2v2.7v-1.7l-.1 2.8v-3.3l-.1 3.4v-2.7v3.1l-.1-3.5v4.5v-6.1v3.7l-.1-4.9v6.1l-.1-4.4-.1 4.2v-3.7l-.1 2v-1.5v1.2v-1.2l-.1 .9v-11.4v13.5v-2.5l-.1 1.5-.1-1.4v1.6l-.1-1.8v1.8v-2.9v3v-2.6v2.5v-1.5l-.1 1v-2.5l-.1 7.3v-5.1l-.1 1.5v-1.8v3.8v-4.5l-.1 5.3-.1-6v4.8l-.1-4.5v6.6v-7.2l-.1 7.1v-5.7l-.1 5.5v-8.6l-.2 6.3v-2.9v2.7l-.2-4.4v3.3l-.1-3.3v1.9v-2.2v5.3l-.1-5.2-.1 3.6v-1.6v1.3l-.1-1.2v1.9l-.1-3.7v8.4v-6.9l-.1 1v-1.8v4.1l-.2-4.3v4.2v-3.6l-.1 2.4v-4.3v4.6l-.1-2.9v2.4l-.1-2.8-.1 3.3-.1-4-.1 6.5v-4.2l-.1-.5v1.9l-.1-2.3v1.5v-1.5l-.1 1.2v-7.1v7v-1.9l-.1 3.2v-3.4l-.1 3.8-.1-3.9v4v-5.2l-.1 7.4-.1-6.5v2.3l-.1-1.7-.1 3.4v-3.1v4l-.1-3.5v6.2v-5.6v1.8l-.2-3.4-.1 3.9v-3.1l-.1-.4v2.7l-.1-2.8v3.4l-.1-1v-3.3v5.6l-.1-5.4v2.9l-.1-2.9v4.6v-3.4l-.2 3.3v-4.6l-.1 3.2-.1-3.9v6.8l-.2-5.8-.1 5.2-.1-7.4v6.9v-4.2v2.9l-.1-2.3v6v-7.5l-.1 6.5-.1-8.3-.1 6.3-.1-3.4-.2 1v1.9v-6v3.8v-11.9l-.1 16.9v-5.1l-.1 3.5v-4.1l-.1 4.1-.1-4.6-.1 3.6v-6.1v4.8l-.1-3.1-.1 4.6-.1-5.7v5.4l-.1 1.3v-4.5l-.1 1.8v-2.1v4.3l-.1-4.4-.1 5.5v-6.4v9l-.1-6.9-.1 2.2v-3v2.6v-2.5l-.1 .3v-.7v1.9v-1.9v4.3l-.1-5-.1 5.1-.1-5.9-.1 5.2-.1-4.1-.1 4.4v-4.4v3.8l-.1-.6v-10.8l-.1 13.1-.1-5.2v3.9l-.1-8.9v9.1l-.1-2.9v3v-4.3l-.1 5v-4.2l-.1-.6v4.5v-4.1v3.9l-.1-4v3.8l-.1-2.9v2.7v-4.1v5.5l-.1-6.1-.1 4.8v-.2v-12.4v10.8v-2.3l-.1 2.9-.1-1.9-.1 4.1v-4.5l-.1 1v-1.2l-.1 3v-3l-.1 1v-1.8v3.1v-3.3v6v-4.6l-.1 .7-.1-2v3.6l-.1-5v4l-.1-2.8-.1 3.5-.1-3.8v2.7l-.1-1.6v1.8v-2.2l-.1 2.5v-2.2v4.2v-4v3.5v-4l-.1 4.4-.1-5.2-.1 4.4-.1-3.5v5.4v-5.5l-.1 3.2v-3.1v5.5l-.1-6.7-.1 4.5v-6v4.9v-2.3l-.1 3.6-.1-3.3-.1 4.8-.1-7.5v7.5l-.1-6.1v5.5l-.1-5v5.8l-.1-5.7-.1 4.5v-7.2v6.6l-.1-3.6-.1 6.6-.1-20.6v17.9v-5.8l-.1 6.5v-3.8l-.1 .6v-1.2v2.7l-.1-2.8-.1 3.6v-6v5l-.1-2v3.6v-4.1l-.1 5.1-.2-7.8-.1 10v-7.4l-.1 3.4-.1-2.7v3.1l-.1-5v6.6l-.1-5.4-.2 4.8-.1-5.9-.1 4.6v-5l-.1 6.8-.2-6.9v5.3v-2.8v1.8l-.1-1.6v4.4v-4.7l-.1 1.1v-1.3l-.1 2.2-.1-4.7-.1 7.6-.1-6-.1 4.5v-4.3v4v-4.7l-.2 5.9-.1-6.6-.1 3.9v-37.3l-.1 38.4-.1-2.1v3.2l-.1-5.4v5.8l-.1-6.2v2.7v-.8l-.1 1-.1-.9v2.6l-.1-3.7v2.1v-1.3l-.1 .3v4.9v-6.5l-.1 5.3-.1-3.4v3.5l-.1-4.9v5.4v-5.5l-.1 4.1v-4.5v5.8v-4.8l-.1 3.2v-2.9l-.1 1.4v-1.5v2.9l-.1-3.3v2.6l-.1-.1v-5.3l-.1 7v-2.7v1.3l-.2-2.4v2.6v-4.8v5.2v-3.1l-.2 3.8-.1-2.6v3.6v-4v.9l-.1-2.7v3.8v-2.6l-.1 1.2v-.5l-.1 .3v-3.2v5.7l-.1-4.6v4.3v-11.6l-.1 12.6-.2-8.4v2.9" fill="none" stroke="#000" stroke-width=".35"/>
<path d="M31.1 210.8h.3M31.1 200.7h.3" fill="none" stroke="#868686" stroke-width=".26"/>
<path d="M94.8 183l-28.7 .1a3.7 3.7 0 0 0-4 2.3l-.7 2.7-.4 2.9-1.3 11.7-.4 5.3-.2 .4-.2-.3-.2 .2h-21.2M31.4 208.3h6.4" fill="none" stroke="#be4b48" stroke-width=".35"/>
<path d="M94.8 183l-28.7 .1a4.4 4.4 0 0 0-3.3 1 9.6 9.6 0 0 0-1.4 4.6l-1.8 16.9a5.4 5.4 0 0 1-.5 2.7h-21.6M31.4 208.3h6.4" fill="none" stroke="#98b954" stroke-width=".35"/>
<path d="M94.8 183h-28.7l-1.9 .3a1.31 1.31 0 0 0-1.8 1.2l-.7 4-1.5 14.5a23.2 23.2 0 0 1-.9 5.2l-21.8 .1M31.4 208.3h6.4" fill="none" stroke="#fe660d" stroke-width=".35"/>
<path d="M94.8 183l-24.4-.1a5.9 5.9 0 0 0-3.2 .4 3.5 3.5 0 0 1-3-1 .87 .87 0 0 0-1.2 .9l-.5 2.5-.5 3.2-1.6 14.5a13.4 13.4 0 0 1-1 4.6 1.6 1.6 0 0 1-1.5 .3h-20.4M31.4 208.3h6.4" fill="none" stroke="#6c85b1" stroke-width=".35"/>
<path d="M77.3 208.2h13.2v10.7h-13.2z" fill="#fff"/>
<path d="M32.3 171.8h11v14.7h-11z" fill-rule="evenodd" fill="#fff"/>
<path d="M33.2 173.1h3.2" fill="none" stroke="#0a347d" stroke-width=".35"/>
<path d="M33.2 176.1h3.2" fill="none" stroke="#be4b48" stroke-width=".35"/>
<path d="M33.2 179.2h3.2" fill="none" stroke="#98b954" stroke-width=".35"/>
<path d="M33.2 182.2h3.2" fill="none" stroke="#fe660d" stroke-width=".35"/>
<path d="M33.2 185.1h3.2" fill="none" stroke="#6c85b1" stroke-width=".35"/>
<path d="M128.7 30h63.8v50.8h-63.8z" fill="none" stroke="#000" stroke-width=".27"/>
<g fill="none" stroke="#000" stroke-width=".2">
<path d="M128.7 36.3h64.3M146.9 29.9v50.9M165.1 29.9v50.9M183.3 29.9v50.9M192.5 30h.5M128.7 42.7h64.3M128.7 49.1h64.3M128.7 55.4h63.8M192.5 55.3h.5M128.7 68h63.8M128.7 61.7h64.3M128.7 74.4h64.3"/>
<path d="M192.5 68.2h.5M192.5 80.8h.5"/>
</g>
<g fill="#fff">
<path d="M145.3 64.6h24.3v2.7h-24.3z"/>
<path d="M137.6 52.9h8.1v2.1h-8.1z"/>
</g>
<path d="M138.4 52.6h7.2" fill="none" stroke="#000" stroke-width=".2"/>
<path d="M169.1 56.7h22v2.8h-22z" fill="#fff"/>
<path d="M192.2 60.1h-16.6l-.4 .3h-.1l-.2 .7-.9 6.9-.5 .1h-35.5l-.1-.1v.3l-.1-.3v.1h-9" fill="none" stroke="#f00" stroke-width=".44"/>
<path d="M192.2 36.3h-54.1l-.2-.1v-.5l-.1 32.3h-9" fill="none" stroke="#00f" stroke-width=".44"/>
<path d="M192.2 67.8h-12.4l-1.1-.2-1.5 .1-.3-.2-.8 .1-.6-.3-.3 .1-.2-.1a.78 .78 0 0 1-.7-.8l-.2-1.5-.1 2.3-.9 .8h-.4v-.1l-.1 .1-10-.1v.2v-.2h-7.1l-.1 .2-.3-.2h-5l-.1 .4v-.7l-.1 1.1v-.9l-.1 .2-.8-.1-.2 .2-.2-.2-.2 .2-.1-.2-.5 .2-.1-.2h-5.9l-.1 .2v-.2l-2.1 .1-.1-.1-.3-.1-.3-.6-.3 .3-.2-.1-.2 .4v-.4l-.1 .7v-.8l-.1 1v-.9v1.3l-.1-3.5v5.7l-.1-5.6v2.7h-9" fill="none" stroke="#0f0" stroke-width=".44"/>
<g fill="none" stroke="#000" stroke-width=".2">
<path d="M119.6 44.7v6.8M134.5 99.8v50.5M136.7 99.8v50.5M138.3 99.8v50.5M139.6 99.8v50.5M140.5 99.8v50.5M141.4 99.8v50.5M142.1 99.8v50.5M142.7 99.8v50.5M147.1 99.8v50.5M149.4 99.8v50.5M151 99.8v50.5"/>
<path d="M152.2 99.8v50.5M153.2 99.8v50.5M154.1 99.8v50.5M154.8 99.8v50.5M155.4 99.8v50.5M159.8 99.8v50.5M162.1 99.8v50.5M163.6 99.8v50.5M164.9 99.8v50.5M165.8 99.8v50.5M166.7 99.8v50.5M167.4 99.8v50.5"/>
<path d="M168 99.8v50.5M172.4 99.8v50.5M174.7 99.8v50.5M176.3 99.8v50.5M177.5 99.8v50.5M178.5 99.8v50.5M179.4 99.8v50.5M180.1 99.8v50.5M180.7 99.8v50.5M185.1 99.8v50.5M187.4 99.8v50.5M188.9 99.8v50.5"/>
<path d="M190.2 99.8v50.5M191.1 99.8v50.5M192 99.8v50.5M192.7 99.8v50.5M130.7 118.8h63.2M130.7 112.4h63.2M130.7 106.1h63.2M130.7 137.7h63.2M130.7 131.4h63.2M130.7 125.1h63.2M130.7 144h63.2"/>
</g>
<g fill="none" stroke="#000" stroke-width=".26">
<path d="M130.7 99.8h63.2v50.5h-63.2zM143.3 99.8v50.5M156 99.8v50.5M168.6 99.8v50.5M181.3 99.8v50.5M193.3 99.8v50.5M130.7 121.6l1.7 3.2a19 19 0 0 0 4.3 6.2l1.6 2.3 1 1.9a.8 .8 0 0 0 1 .4l.4 .5a5.4 5.4 0 0 0 1.6 2.7l.4 .6 .6-.2 .9 1.4 .5-2.3 .2 .5a4.6 4.6 0 0 0 .8 2.5h.4l.5 .5 .3-.8h1l.3 .3 .1-.6 .6 1 .3-.3 .2-.8 .2 1.1 .3-.8 .2 .7 .4-.2 .1 .7 .2-.4 .3 .5 .2-.8 .2 .6 .1-.3 .1 .3 .2-.6v.2l.1-.9 .2 1 .1-.2 .2 .3 .1-.9 .2 .7 .1-.4 .1 .4 .2-.1 .1 .7 .1-.9 .2 .4 .1-.1 .1 .5 .1-.5 .1 .2 .1-.5v.4l.2-.1 .1 .5 .2-.5 .2 .7 .1-.8 .1 .6 .1-.7 .2 .7 .1-.5 .1 .5v-1.1l.2 1.1 .2-.6 .1 .8 .1-.9 .1 .7v-.5l.2 .5v-.5l.2 .4 .1-.5 .1 .8 .1-.7h.1v.7l.1-.7 .1 .5v-.5l.2 .2 .1-.3 .1 .6 .1-.3v.2l.1-.4v.4l.2-.2 .2 .5 .2-.7v.7v-.8l.3 .8 .1-.8 .3 .8 .1-1.1v1.1l.1-.7 .1 .7 .1-.7 .1 .5 .1-.1v-.7l.1 .8v-.6l.1 .7v-.6v.2l.1-.1v.4v-.5l.1 .5v-.7v.9l.1-.7v.7v-.7l.1-.1 .1 .7 .1-.7 .1 1 .1-1.6v1.9l.1-1.9v1.2l.1-.4 .1 .5 .1-.3v.4l.1-.9 .1 .8 .1-.8v1.1l.1-1.1 .1 .8 .1-.8v.9l.1-.8 .1 .4 .1-.3v.5l.1-.7v.9v-.9l.1 .9v-.6l.1 .1v.7v-1.1v.6l.1-.1v.3v-.6l.1 .7v-.8v1.1v-1.1l.2 .9v-1.1l.1 1.1v-1v.9v-.9v.4l.1-.2v.9v-1.3l.1 1.3 .1-1.3 .1 .9 .1-.5v1.1v-1.1l.1 .7 .1-.8v1.1l.1-1.3 .2 1.2 .1-1.1v1.5l.1-1.4 .1 1.2v-1.1l.1 .8v-.6v.3v-.3l.1 .2v.6v-1.1l.1 .7 .1-.6v.8v-.9v1v-.5v.4l.2-.8v1.2l.1-1.2v.8l.1-.8v.7v-1.1v1.5l.2-1v.7l.1-.9 .1 1.2 .1-1v.9v-.8l.1 .8v-.6l.1 .3v-.7l.1 1.2v-1.3v1.3l.1-1.3 .1 1.3v-1.3l.1 1.7v-1.5l.1 .9v-.8v.6l.1-.4 .1 .8 .1-1.1v1v-.5M166.4 142.7v-.6v.7v-1v.5l.1-.5v.6l.1-.5 .1 .6v-.9v1.4l.1-1.4v1.2l.1-.8 .1 .5v-.6l.1 1.1v-.9v.8v-1.2v1.2l.1-1.1 .1 .8v-.7l.1 .7v-.4v.6l.2-.9 .1 1.1v-1l.1 .9v-.7v.9v-1.1v1v-.9v.8l.1-.6v.7v-1l.1 1.2 .1-1.2v1v-.8l.1 .7v-.9v.9l.1-.8v.9v-.8l.1 .4v-.5v.9l.1-.8v.8v-1.2l.1 1.5v-1v.9l.1-.9v.6v-.8l.1 1.2 .1-1 .1 1 .1-1v1.3l.1-1.2 .1 .6v-.8v1.1v-1v.9v-.6v.6l.1-.7 .1 .7 .1-.8v1.1v-1.1l.1 .9v-.6v1v-1.1v1.1v-.9l.1 .6v-1v1.2l.1-1.2v1.2v-1l.1 1v-.9v.9v-.7v.7l.1-.8v.8l.1-.9v.9M170.2 143.1v.5v-.6v.7v-.8l.1 .8v-.7v.7v-.7l.1 .6 .1-.6v.6v-.7l.1 .9v-.8l.1 .9v-1v.9v-.8v.8l.1-.8v.8v-.6v.6l.1-.6v.6v-.8l.1 .9 .1-.9 .1 1.4 .1-1.3 .1 1.2v-1v.8l.1-.7v.7v-.8v.9l.1-.6 .1 1v-1.3l.1 1.1v-.9l.1 1 .1-.9 .1 1 .1-.9v1v-.9v1v-.8l.1 .8 .1-.7v.6v-.9v.7M172.4 144.4v.1v-.6v.7l.1-.8v1v-.9l.1 .9v-.8l.1 .8v-.7v.8v-1l.1 1.2 .1-.8v.8v-.7l.1 .7v-.7v.9l.1-.8v.9v-1v.7l.1-.7 .1 .9v-.9v.9v-.8l.1 .7 .1-.6v.7l.1-.5v.8v-1v.8v-.7v.7l.1-.5 .1 .6v-.8l.1 1.1v-.9l.1 .7v-.6v.1M174 145v.8v-.7l.1 .7v-.7v.6l.1-.5v.6v-.7v.8v-.7l.1 .7 .1-.6v.5v-.7v.8v-.8v.8v-.6v.6v-.6v.6v-.5v.5l.1-.5v.6v-.6v.6v-.2l.1 .1v-.6l.1 .8 .1-.8 .1 1v-.7l.1 .6v-.6v.6v-.6l.1 .6v-.3v.5v-.7v.7v-.5l.1 .5v-.4v.4v-.4v.2M175.2 146.3l.1-.4v.6v-.6l.1 .8v-.8v.6v-.6v.6v-.6l.1 .8 .1-.7 .1 .8 .1-.7v.7v-.6v.6v-.5l.1 .5v-.4v.4v-.4v.4v-.4v.4v-.3v.2v-.2v.2v-.2l.1 .1v.3v-.5v.5l.1-.4 .1 .5"/>
<path d="M176.2 146.7v.3l.1-.4v.5l.1-.5 .1 .6v-.6l.1 .6v-.6v.7l.1-.5v.5v-.6l.1 .6v-.6v.6l.1-.5v.6v-.6v.5v-.4l.1 .5v-.5l.1 .6 .1-.5 .1 .5v-.5v.6v-.4v.4v-.4l.1 .3v-.4l.1 .7 .1-.5v.6l.1-.6v.5v-.5v.4l.1-.2v.3v-.5l.1 .5v-.5v.6l.1-.5v.5v-.3v.3v-.4v.5v-.5v.5v-.4l.1 .4 .1-.4v.4l.1-.4v.5l.1-.4v.4v-.4v.3l.1-.2v.3v-.3l.1 .4v-.4v.4l.1-.3v.4v-.4v.3v-.2v.2v-.3v.3v-.3v.3v-.3l.1 .2v-.1v.3v-.4v.4v-.3v.1l.1-.1v.3l.1-.3 .1 .5 .1-.5 .1 .5v-.4v.3v-.3v.3v-.3v.3v-.3v.3l.1-.2v.4v-.5v.5l.1-.4v.4v-.3v.3v-.3l.1 .3 .1-.3 .1 .4v-.4l.1 .4v-.4l.1 .4v-.3l.1 .3v-.2v.3v-.2l.1 .2v-.2l.1 .2v-.2v.2v-.2v.2v-.2v.1v-.1v.1v-.1v.1l.1-.1v.2v-.2v.2v-.2v.2l.1-.2v.1M180.5 148.8v-.2v.3v-.2v.2v-.2l.1 .2v-.2v.2v-.2v.2v-.2l.1 .2 .1-.2v.3v-.3v.3v-.3v.2v-.2v.2v-.2v.2v-.2v.2v-.2v.2v-.2v.2v-.2v.2l.1-.1M180.9 148.9v-.2v.3l.1-.2 .1 .3v-.3v.3v-.3l.1 .3v-.3v.3v-.3v.3l.1-.2M181.3 149v-.2l.1 .3v-1.5v1.6l.1-.3v.3v-.3v.3v-.2v.2v-.2v.2v-.2l.1 .2v-.2v.2l.1-.2v.3l.1-.3 .1 .3v-.3l.1 .3M182 149.2l.1 .1v-.2v.3v-.2l.1 .2v-.3v.3l.1-.2M182.3 149.3v-.1v.2v-.3v.3v-.2v.2v-.2v.2v-.2v.2v-.2v.2v-.2v.2v-.2v.2l.1-.2 .1 .2v-.2l.1 .2v-.1v.1v-.1v.1v-.1v.1v-.1v.1v-.1v.1v-.1v.1v-.1v.1v-.1l.1 .1 .1-.1 .1 .2v-.1v.1l.1-.1v.1v-.1v.1v-.1v.1v-.1v.1v-.1v.1v-.1v.1v-.1v.1v-.1v.1v-.1v.1v-.1v.1l.1-.1 .1 .1v-.1v.1v-.1v.1v-.1v.1v-.1l.2 .2v-.2l.1 .2v-.2v.2v-.2v.2l.1-.2 .1 .2v-.2v.2v-.2v.2l.2-.1v.2v-.2v.2v-.2v.2v-.2l.1 .2v-.2v.2v-.2v.2v-.2v.2v-.2l.1 .2v-.2v.2v-.2v.2v-.2v.2l.1-.2v.2v-.2v.2v-.2v.2h.2v-.2v.2l.1-.1M184.5 149.7h.6M185.2 149.8l.4-.1v.2v-.2l.1 .2v-10.5v10.5h.2v-.2v.2h.3M185.2 149.7l-.1 .1M186.2 149.8l.2 .1M186.4 149.8h.4l.1 .2 .1-.2 .1 .2v-.2l.1 .2v-.2v.2h.2v-2.8v2.8h.2M187.6 149.9l.3 .1"/>
<path d="M187.9 149.9h.2M188.5 149.9l-.4 .1M188.8 150h-.3M188.8 149.9h.2M189 150h.1M189.1 149.9l.2 .1v-.2l.1 .2v-.6l.1 .6v-1.3v1.3l.5 .1M190 150.1v-.5l.1 .5M190.1 150.1h.1"/>
</g>
<path d="M135.6 106.7h10.4v5.2h-10.4z" fill-rule="evenodd" fill="#fff"/>
<g fill="none" stroke="#000" stroke-width=".2">
<path d="M132 176.7h63.6M139.7 170.3v50.8M147.5 170.3v50.8M155.1 170.3v50.8M162.8 170.3v50.8M170.5 170.3v50.8M178.3 170.3v50.8M185.9 170.3v50.8M193.6 170.3v50.8M132 195.7h63.6M132 189.4h63.6M132 183h63.6"/>
<path d="M132 214.8h63.6M132 208.4h63.6M132 202.1h63.6"/>
</g>
<path d="M141 172.2h12.9v12.6h-12.9z" fill="#fff"/>
<path d="M141.7 174.3h2.1M195.6 179a100.6 100.6 0 0 1-16.3 9.2 31.9 31.9 0 0 1-9.1 1.8 76.2 76.2 0 0 1-13.1 .8 11.5 11.5 0 0 1-5.3-2.1 8.4 8.4 0 0 0-7.6-.7l-3.5 1.1-8.7 3.1" fill="none" stroke="#0a347d" stroke-width=".44"/>
<path d="M141.7 176.6h2.1M195.6 178.4a40.6 40.6 0 0 0-6.9 2 27.6 27.6 0 0 0-6.3 5.4 13.7 13.7 0 0 1-8.8 4l-4.6 .4a57.5 57.5 0 0 1-13-.3 20.9 20.9 0 0 1-4.9-2.6 8.3 8.3 0 0 0-6-.9l-3.7 .8-9.4 2.4" fill="none" stroke="#e23354" stroke-width=".44"/>
<path d="M141.7 178.9h2.1M195.6 176.7l-.9 .5a31.4 31.4 0 0 0-9.1 5.3 25.9 25.9 0 0 1-7 5.3 31.2 31.2 0 0 1-9.6 1.6 69.7 69.7 0 0 1-13 .2l-2.6-1a7.7 7.7 0 0 0-8.1-.7 129.7 129.7 0 0 0-12.1 6.6l-1.2 .7" fill="none" stroke="#66b48c" stroke-width=".35"/>
<path d="M195.6 175.2l-9.3 8.7a28.1 28.1 0 0 1-8.5 6.7 27.8 27.8 0 0 1-10.2 1.2 47.1 47.1 0 0 1-11.6-1.2 22.4 22.4 0 0 1-4.9-3.3 7.1 7.1 0 0 0-5.8-1 96.1 96.1 0 0 0-12.1 3.8l-1.2 .4M141.7 181.2h2.1" fill="none" stroke="#8366b0" stroke-width=".26"/>
<path d="M195.6 179.8a76.2 76.2 0 0 0-13.9 7.8 22.3 22.3 0 0 1-12.7 2.9l-5.6-.2a56.4 56.4 0 0 1-9.5-.8 11.6 11.6 0 0 0-9.7 .4l-12.2 5.7M141.7 183.4h2.1" fill="none" stroke="#fea36e" stroke-width=".26"/>
<path d="M132 170.3h63.6v50.8h-63.6z" fill="none" stroke="#000" stroke-width=".26"/>
<use href="#words"/>
</svg>
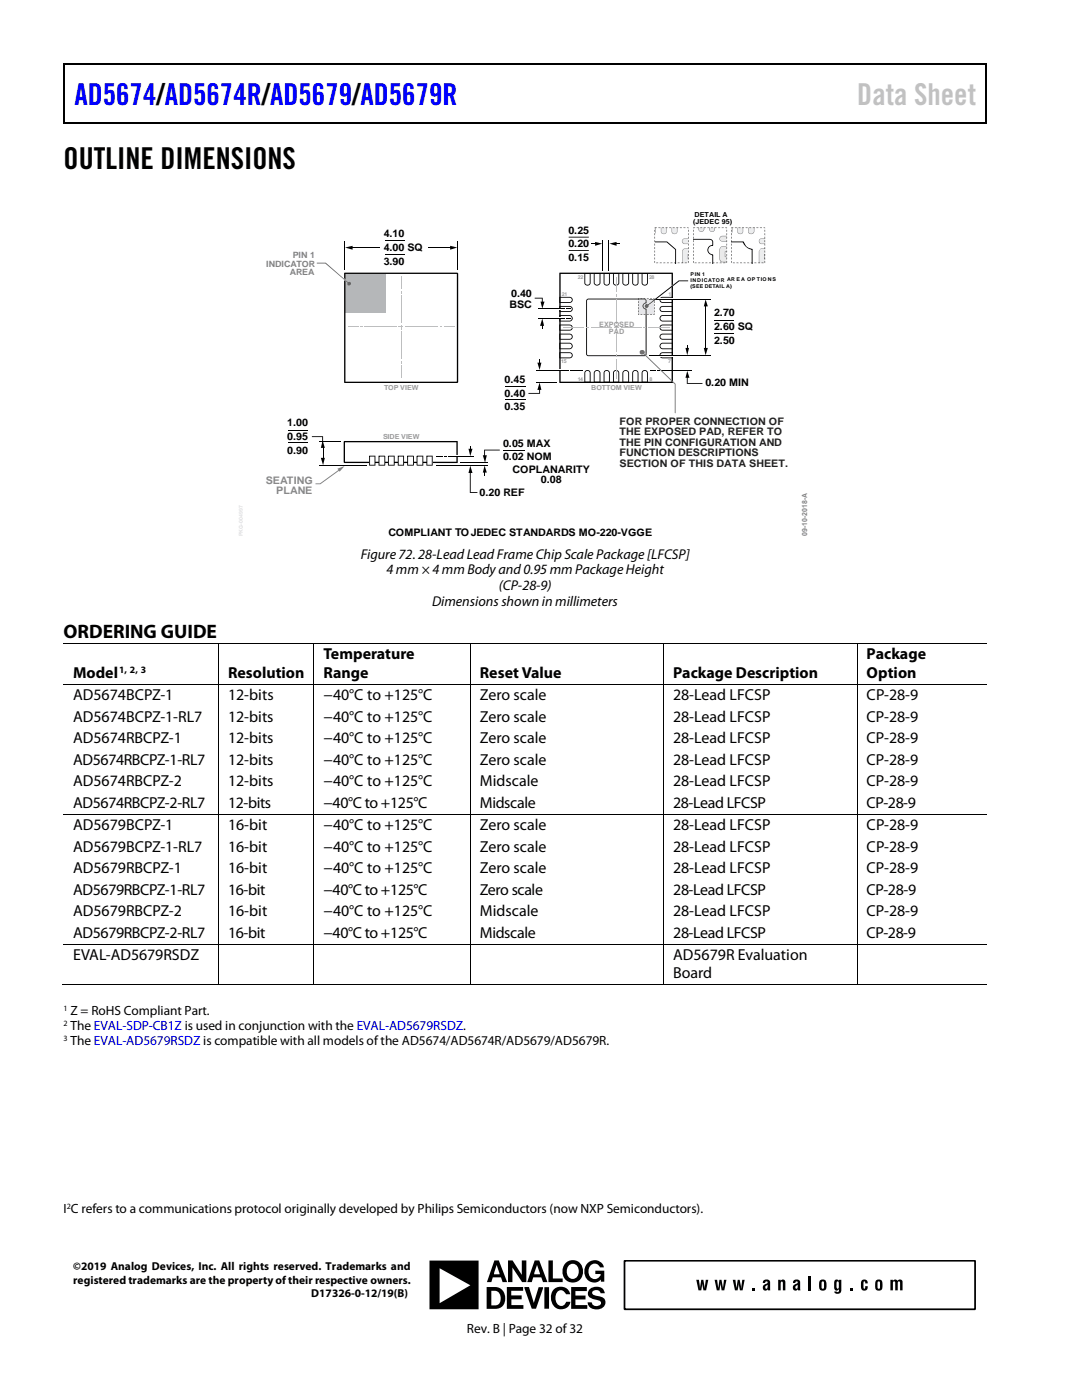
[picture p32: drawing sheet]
<svg xmlns="http://www.w3.org/2000/svg" width="216mm" height="279mm" viewBox="0 0 216 279" stroke-linecap="round" stroke-linejoin="round" font-family="sans-serif">
<defs><g id="words">
<text font-size="6" fill="#00f" x="14.9" y="21">AD5674/AD5674R/AD5679/AD5679R</text>
<text font-size="6" fill="#c1c1c1" x="171.1" y="21">Data Sheet</text>
<text font-size="6" x="12.7" y="33.7">OUTLINE DIMENSIONS</text>
<text font-size="3.9" x="12.7" y="127.3">ORDERING GUIDE</text>
<g font-size="3.2">
<text x="64.6" y="131.6">Temperature</text>
<text x="172.9" y="131.6">Package</text>
<text x="14.6" y="135.3">Model</text>
<text x="45.5" y="135.3">Resolution</text>
<text x="64.6" y="135.3">Range</text>
<text x="95.8" y="135.3">Reset Value</text>
<text x="134.3" y="135.3">Package Description</text>
<text x="172.9" y="135.3">Option</text>
<text x="14.6" y="139.7">AD5674BCPZ-1</text>
<text x="45.5" y="139.7">12-bits</text>
<text x="64.6" y="139.7">−40°C to +125°C</text>
<text x="95.8" y="139.7">Zero scale</text>
<text x="134.3" y="139.7">28-Lead LFCSP</text>
<text x="172.9" y="139.7">CP-28-9</text>
<text x="14.6" y="144">AD5674BCPZ-1-RL7</text>
<text x="14.6" y="148.3">AD5674RBCPZ-1</text>
<text x="45.5" y="144">12-bits</text>
<text x="45.5" y="148.3">12-bits</text>
<text x="64.6" y="144">−40°C to +125°C</text>
<text x="64.6" y="148.3">−40°C to +125°C</text>
<text x="95.8" y="144">Zero scale</text>
<text x="95.8" y="148.3">Zero scale</text>
<text x="134.3" y="144">28-Lead LFCSP</text>
<text x="134.3" y="148.3">28-Lead LFCSP</text>
<text x="172.9" y="144">CP-28-9</text>
<text x="172.9" y="148.3">CP-28-9</text>
<text x="14.6" y="152.6">AD5674RBCPZ-1-RL7</text>
<text x="45.5" y="152.6">12-bits</text>
<text x="64.6" y="152.6">−40°C to +125°C</text>
<text x="95.8" y="152.6">Zero scale</text>
<text x="134.3" y="152.6">28-Lead LFCSP</text>
<text x="172.9" y="152.6">CP-28-9</text>
<text x="14.6" y="156.9">AD5674RBCPZ-2</text>
<text x="14.6" y="161.2">AD5674RBCPZ-2-RL7</text>
<text x="45.5" y="156.9">12-bits</text>
<text x="45.5" y="161.2">12-bits</text>
<text x="64.6" y="161.2">−40°C to +125°C</text>
<text x="64.6" y="156.9">−40°C to +125°C</text>
<text x="95.8" y="161.2">Midscale</text>
<text x="95.8" y="156.9">Midscale</text>
<text x="134.3" y="161.2">28-Lead LFCSP</text>
<text x="134.3" y="156.9">28-Lead LFCSP</text>
<text x="172.9" y="161.2">CP-28-9</text>
<text x="172.9" y="156.9">CP-28-9</text>
<text x="14.6" y="165.7">AD5679BCPZ-1</text>
<text x="45.5" y="165.7">16-bit</text>
<text x="64.6" y="165.7">−40°C to +125°C</text>
<text x="95.8" y="165.7">Zero scale</text>
<text x="134.3" y="165.7">28-Lead LFCSP</text>
<text x="172.9" y="165.7">CP-28-9</text>
<text x="14.6" y="170">AD5679BCPZ-1-RL7</text>
<text x="45.5" y="170">16-bit</text>
<text x="64.6" y="170">−40°C to +125°C</text>
<text x="95.8" y="170">Zero scale</text>
<text x="134.3" y="170">28-Lead LFCSP</text>
<text x="172.9" y="170">CP-28-9</text>
<text x="14.6" y="174.3">AD5679RBCPZ-1</text>
<text x="14.6" y="178.6">AD5679RBCPZ-1-RL7</text>
<text x="45.5" y="174.3">16-bit</text>
<text x="45.5" y="178.6">16-bit</text>
<text x="64.6" y="178.6">−40°C to +125°C</text>
<text x="64.6" y="174.3">−40°C to +125°C</text>
<text x="95.8" y="174.3">Zero scale</text>
<text x="95.8" y="178.6">Zero scale</text>
<text x="134.3" y="174.3">28-Lead LFCSP</text>
<text x="134.3" y="178.6">28-Lead LFCSP</text>
<text x="172.9" y="178.6">CP-28-9</text>
<text x="172.9" y="174.3">CP-28-9</text>
<text x="14.6" y="182.9">AD5679RBCPZ-2</text>
<text x="45.5" y="182.9">16-bit</text>
<text x="64.6" y="182.9">−40°C to +125°C</text>
<text x="95.8" y="182.9">Midscale</text>
<text x="134.3" y="182.9">28-Lead LFCSP</text>
<text x="172.9" y="182.9">CP-28-9</text>
<text x="14.6" y="187.2">AD5679RBCPZ-2-RL7</text>
<text x="14.6" y="191.6">EVAL-AD5679RSDZ</text>
<text x="45.5" y="187.2">16-bit</text>
<text x="64.6" y="187.2">−40°C to +125°C</text>
<text x="95.8" y="187.2">Midscale</text>
<text x="134.3" y="187.2">28-Lead LFCSP</text>
<text x="134.3" y="191.6">AD5679R Evaluation</text>
<text x="172.9" y="187.2">CP-28-9</text>
<text x="134.3" y="195.2">Board</text>
</g>
<g font-size="2.8">
<text x="72" y="111.5">Figure 72. 28-Lead LeadFrame Chip Scale Package [LFCSP]</text>
<text x="77.1" y="114.6">4 mm × 4 mm Bodyand 0.95 mm Package Height</text>
<text x="99.5" y="117.8">(CP-28-9)</text>
<text x="86.2" y="121">Dimensions shown in millimeters</text>
</g>
<g font-size="2.7">
<text x="14.1" y="202.6">Z = RoHS Compliant Part.</text>
<text x="14.1" y="205.6">The EVAL-SDP-CB1Z is used in conjunction with the EVAL-AD5679RSDZ.</text>
<text x="14.1" y="208.6">The EVAL-AD5679RSDZ is compatible with all models of the AD5674/AD5674R/AD5679/AD5679R.</text>
<text x="12.7" y="242.1">I C refers to a communications protocol originally developed by Philips Semiconductors (now NXP Semiconductors).</text>
<text x="93.2" y="266">Rev. B | Page 32 of32</text>
</g>
<g font-size="2.3">
<text x="14.6" y="253.5">©2019 Analog Devices, Inc. All rights reserved. Trademarks and</text>
<text x="14.6" y="256.2">registered trademarks are the property of their respective owners.</text>
<text x="62.1" y="258.8">D17326-0-12/19(B)</text>
</g>
<g font-size="2.1">
<text x="76.6" y="47.3">4.10</text>
<text x="113.4" y="46.6">0.25</text>
<text x="76.6" y="50.1">4.00 SQ</text>
<text x="76.6" y="52.9">3.90</text>
<text x="113.4" y="49.4">0.20</text>
<text x="113.4" y="52.1">0.15</text>
<text x="102" y="59.3">0.40</text>
<text x="101.7" y="61.4">BSC</text>
<text x="142.5" y="63.1">2.70</text>
<text x="142.5" y="65.9">2.60 SQ</text>
<text x="142.5" y="68.7">2.50</text>
<text x="100.7" y="76.4">0.45</text>
<text x="140.8" y="76.9">0.20 MIN</text>
<text x="100.7" y="79.2">0.40</text>
<text x="100.7" y="81.9">0.35</text>
<text x="57.3" y="85">1.00</text>
<text x="57.3" y="87.8">0.95</text>
<text x="100.4" y="89.1">0.05 MAX</text>
<text x="57.3" y="90.6">0.90</text>
<text x="100.4" y="91.9">0.02 NOM</text>
<text x="102.3" y="94.4">COPLANARITY</text>
<text x="95.7" y="99">0.20 REF</text>
<text x="107.9" y="96.4">0.08</text>
<text x="77.5" y="106.9">COMPLIANT TOJEDEC STANDARDS MO-220-VGGE</text>
</g>
<g font-size="2.1" fill="#231f20">
<text x="123.6" y="84.8">FOR PROPER CONNECTION OF</text>
<text x="123.6" y="86.9">THE EXPOSED PAD, REFER TO</text>
<text x="123.6" y="89">THE PIN CONFIGURATION AND</text>
<text x="123.6" y="91.1">FUNCTION DESCRIPTIONS</text>
<text x="123.6" y="93.1">SECTION OF THIS DATA SHEET.</text>
</g>
<g font-size="2.1" fill="#86888b">
<text x="53" y="96.6">SEATING</text>
<text x="55.1" y="98.6">PLANE</text>
</g>
<text font-size="1.9" x="23.7" y="134.2">1, 2, 3</text>
<g font-size="1.7" fill="#808285">
<text x="53.1" y="53.2">INDICATOR</text>
<text x="58.4" y="51.5">PIN 1</text>
<text x="57.8" y="54.9">AREA</text>
</g>
<g font-size="1.6">
<text x="12.7" y="201.8">1</text>
<text x="12.7" y="204.7">2</text>
<text x="12.7" y="207.7">3</text>
<text x="13.3" y="241.3">2</text>
</g>
<g font-size="1.5" fill="#9a9a9a">
<text x="119.6" y="65.3">EXPOSED</text>
<text x="121.5" y="66.7">PAD</text>
</g>
<g font-size="1.4">
<text x="138.3" y="44.6">(JEDEC 95)</text>
<text x="138.6" y="43.2">DETAIL A</text>
</g>
<g font-size="1.4" fill="#9a9a9a">
<text x="76.6" y="77.9">TOP VIEW</text>
<text x="117.9" y="77.9">BOTTOM VIEW</text>
<text x="76.5" y="87.7">SIDE VIEW</text>
</g>
<text font-size="1.4" fill="#808285" x="161.1" y="106.9" transform="rotate(-90 161.1 106.9)">09-10-2018-A</text>
<g font-size="1" fill="#9a9a9a">
<text x="112.1" y="59">21</text>
<text x="115.3" y="55.7">22</text>
<text x="129.5" y="55.6">28</text>
<text x="133.4" y="59">1</text>
<text x="112" y="72.5">15</text>
<text x="115.3" y="76">14</text>
<text x="129.6" y="76">8</text>
<text x="133.3" y="72.5">7</text>
</g>
<g font-size="1">
<text x="137.8" y="55">PIN 1</text>
<text x="137.8" y="56.2">INDICATOR AR EA OP TIONS</text>
<text x="137.8" y="57.4">(SEE DETAIL A)</text>
</g>
</g></defs>
<g fill="#000">
<path d="M12.7 12.7h.3v1h-.3zM12.7 12.7h.3v.3h-.3zM132.7 12.7h.2v.3h-.2zM196.6 12.7h.2v1h-.2zM196.6 12.7h.2v.3h-.2zM12.7 24.4h.3v.2h-.3zM132.4 24.4h.3v.2h-.3zM196.6 24.4h.2v.2h-.2zM43.5 128.3h.2v.1h-.2zM43.5 136.4h.2v.2h-.2zM62.6 128.3h.1v.1h-.1zM62.6 136.4h.1v.2h-.1z"/>
<path d="M93.8 128.3h.1v.1h-.1zM93.8 136.4h.1v.2h-.1zM132.3 128.3h.2v.1h-.2zM132.3 136.4h.2v.2h-.2zM170.9 128.3h.2v.1h-.2zM170.9 136.4h.2v.2h-.2zM43.5 162.4h.2v.2h-.2zM62.6 162.4h.1v.2h-.1zM93.8 162.4h.1v.2h-.1zM132.3 162.4h.2v.2h-.2zM170.9 162.4h.2v.2h-.2zM43.5 188.3h.2v.2h-.2z"/>
<path d="M43.5 196.4h.2v.2h-.2zM62.6 188.3h.1v.2h-.1zM62.6 196.4h.1v.2h-.1zM93.8 188.3h.1v.2h-.1zM93.8 196.4h.1v.2h-.1zM132.3 188.3h.2v.2h-.2zM132.3 196.4h.2v.2h-.2zM170.9 188.3h.2v.2h-.2zM170.9 196.4h.2v.2h-.2z"/>
</g>
<path d="M12.8 13.7v10.7M13 12.8h119.7M132.9 12.8h63.7M196.7 13.7v10.7M13 24.5h183.6" fill="none" stroke="#000" stroke-width=".25"/>
<g fill="none" stroke="#000" stroke-width=".2">
<path d="M12.7 128.4h30.8M12.7 136.5h30.8M43.6 128.4v8M43.6 136.6v25.8M43.7 128.4h18.9M43.7 136.5h18.9M62.7 128.4v8M62.7 136.6v25.8M62.7 128.4h31.1M62.7 136.5h31.1M93.9 128.4v8M93.9 136.6v25.8"/>
<path d="M93.9 128.4h38.4M93.9 136.5h38.4M132.4 128.4v8M132.4 136.6v25.8M132.5 128.4h38.4M132.5 136.5h38.4M171 128.4v8M171 136.6v25.8M171.1 128.4h25.7M171.1 136.5h25.7M12.7 162.5h30.8M43.6 162.6v25.7"/>
<path d="M43.7 162.5h18.9M62.7 162.6v25.7M62.7 162.5h31.1M93.9 162.6v25.7M93.9 162.5h38.4M132.4 162.6v25.7M132.5 162.5h38.4M171 162.6v25.7M171.1 162.5h25.7M12.4 196.5h31.1M12.7 188.4h30.8M43.6 188.5v7.9"/>
<path d="M43.7 188.4h18.9M43.7 196.5h18.9M62.7 188.5v7.9M62.7 188.4h31.1M62.7 196.5h31.1M93.9 188.5v7.9M93.9 188.4h38.4M93.9 196.5h38.4M132.4 188.5v7.9M132.5 188.4h38.4M132.5 196.5h38.4M171 188.5v7.9"/>
<path d="M171.1 188.4h25.7M171.1 196.5h25.7"/>
</g>
<path d="M68.9 54.7h8.1v7.7h-8.1z" fill="#b5b7b9"/>
<g fill="none" stroke="#000" stroke-width=".2">
<path d="M68.8 48.2v5.7M70.1 49.4h5.7M85.4 49.4h4.7M91.3 48.2v5.7M100.9 79.7h4M100.9 77.1h4M107 76.3h4M140.8 60.9v8.8M142.6 66.6h3.9M142.6 63.9h3.9M57.5 88.4h3.8M57.5 85.8h3.8"/>
<path d="M63.7 92.8h9.4M64.5 89.1v2.5M87.1 92.8h10.2M91.8 92.3h5.5M100.4 89.8h4.2"/>
</g>
<g fill="#000">
<path d="M68.8 49.4l1.6-.3v.7zM89.8 49.1l1.4 .3-1.4 .4zM68.7 54.5l22.6-.1 .1 .2v21.7h-.2v-21.6h-22.3v21.5h22.3l.2 .1-22.6 .1zM107.2 72.4h.8l-.3 1.4zM105.4 78.4h2.2v-.8h.2v1h-2.4zM107.6 71.8h.2v.8h-.2zM107.9 60.2h.8l-.5 1.4zM107.7 76.3l.3 1.5h-.8zM108.1 64.8h.2v.8h-.2zM106.7 59.4h1.6v1.1h-.2v-.9h-1.4zM108.2 63.6l.4 1.4h-.8zM111.6 54.4h22.6l.1 21.9h-.3v-21.6h-22.1v21.5h22.3v.2h-22.6z"/>
<path d="M140.4 69.4h.8l-.4 1.5zM140.8 59.8l.4 1.3h-.8zM64 91.4h.8l-.3 1.4zM62.2 87.1h2.3v2.1h-.2v-2h-2.1zM64.4 87.9l.4 1.5h-.8zM68.6 88.1l22.6-.1 .1 4.3-22.6 .1-.1-4.2h.2v4h22.3v-3.9h-22.3zM93.5 89.6h.8l-.5 1.4zM93.7 89h.2v.9h-.2zM93.8 92.9l.5 1.5h-.8zM93.7 94.1h.2v4.1h1.4v.2h-1.6zM96.3 90.9h.8l-.3 1.4zM96.6 94h.2v.9h-.2z"/>
<path d="M96.7 92.9l.4 1.4h-.8zM96.6 89.7h3.1v.2h-2.9v1.2h-.2z"/>
</g>
<path d="M68.6 55.4l.5 .6-.2 .1-.5-.4z" fill="#fff"/>
<g fill="#000">
<path d="M111.6 59.2h2.1v.2h-1.9v.9h1.9a.48 .48 0 0 0 .4-.5 .48 .48 0 0 0-.4-.5 .57 .57 0 0 1 .6 .6 .57 .57 0 0 1-.6 .6h-2.1zM116.6 54.5h1.3v2a.64 .64 0 0 1-.7 .5 .64 .64 0 0 1-.6-.5h.2a.46 .46 0 0 0 .4 .3 .46 .46 0 0 0 .5-.3v-1.8h-.9v1.8h-.2zM118.5 54.5h1.3v2a.69 .69 0 0 1-.7 .5 .69 .69 0 0 1-.6-.5h.2a.52 .52 0 0 0 .4 .3 .52 .52 0 0 0 .5-.3v-1.8h-.9v1.8h-.2zM120.4 54.5h1.3v2a.64 .64 0 0 1-.6 .5 .64 .64 0 0 1-.7-.5h.2a.46 .46 0 0 0 .5 .3 .46 .46 0 0 0 .4-.3v-1.8h-.9v1.8h-.2zM122.3 54.5h1.3v2a.64 .64 0 0 1-.7 .5 .64 .64 0 0 1-.6-.5h.2a.46 .46 0 0 0 .4 .3 .46 .46 0 0 0 .5-.3v-1.8h-.9v1.8h-.2zM124.2 54.5h1.3v2a.69 .69 0 0 1-.6 .5 .69 .69 0 0 1-.7-.5h.2a.52 .52 0 0 0 .5 .3 .52 .52 0 0 0 .4-.3v-1.8h-.9v1.8h-.2zM126.2 54.5h1.2v2a.64 .64 0 0 1-.6 .5 .64 .64 0 0 1-.6-.5h.1a.46 .46 0 0 0 .5 .3 .46 .46 0 0 0 .4-.3v-1.8h-.9v1.8h-.1zM128 54.5h1.3v2a.64 .64 0 0 1-.6 .5 .64 .64 0 0 1-.7-.5h.2a.46 .46 0 0 0 .5 .3 .46 .46 0 0 0 .4-.3v-1.8h-.9v1.8h-.2zM131.8 59.4l.4-.2v.2a.43 .43 0 0 0-.4 .5 .43 .43 0 0 0 .4 .4h1.9v-.9h-1.9v-.2h2.1v1.3h-2.1a.61 .61 0 0 1-.6-.4 .61 .61 0 0 1 .2-.7zM111.6 66.6h2.1v.2h-1.9v.8h1.9a.48 .48 0 0 0 .4-.5 .48 .48 0 0 0-.4-.4 .57 .57 0 0 1 .6 .5 .57 .57 0 0 1-.6 .6h-2.1zM111.6 68.4h2.1v.2h-1.9v.9h1.9a.52 .52 0 0 0 .4-.5 .52 .52 0 0 0-.4-.5 .61 .61 0 0 1 .6 .6 .61 .61 0 0 1-.6 .6h-2.1zM111.6 70.3h2.1v.2h-1.9v.8h1.9a.48 .48 0 0 0 .4-.4 .48 .48 0 0 0-.4-.5 .57 .57 0 0 1 .6 .5 .57 .57 0 0 1-.6 .6h-2.1z"/>
<path d="M111.6 61.1h2.1v.1h-1.9v.9h1.9a.48 .48 0 0 0 .4-.5 .48 .48 0 0 0-.4-.5 .57 .57 0 0 1 .6 .6 .57 .57 0 0 1-.6 .6h-2.1zM111.6 62.9h2.1v.1h-1.9v1h1.9a.52 .52 0 0 0 .4-.5 .52 .52 0 0 0-.4-.5 .61 .61 0 0 1 .6 .6 .61 .61 0 0 1-.6 .6h-2.1zM111.6 64.8h2.1v.1h-1.9v.9h1.9a.48 .48 0 0 0 .4-.5 .48 .48 0 0 0-.4-.4 .57 .57 0 0 1 .6 .5 .57 .57 0 0 1-.6 .6h-2.1zM116.8 74a.63 .63 0 0 1 .7-.1 .63 .63 0 0 1 .4 .5v1.9h-1.3v-1.9h.2v1.8h.9v-1.8a.49 .49 0 0 0-.5-.4 .49 .49 0 0 0-.5 .4zM118.7 74a.69 .69 0 0 1 1.1 .4v1.9h-1.3v-1.9h.2v1.8h.9v-1.8a.55 .55 0 0 0-.5-.4 .55 .55 0 0 0-.5 .4zM120.6 74a.63 .63 0 0 1 .7-.1 .63 .63 0 0 1 .4 .5v1.9h-1.3v-1.9h.2v1.8h.9v-1.8a.49 .49 0 0 0-.5-.4 .49 .49 0 0 0-.5 .4zM122.5 74a.63 .63 0 0 1 .7-.1 .63 .63 0 0 1 .4 .5v1.9h-1.3v-1.9h.2v1.8h.9v-1.8a.49 .49 0 0 0-.5-.4 .49 .49 0 0 0-.5 .4zM124.4 74a.69 .69 0 0 1 1.1 .4v1.9h-1.3v-1.9h.2v1.8h.9v-1.8a.55 .55 0 0 0-.5-.4 .55 .55 0 0 0-.5 .4zM126.3 74a.63 .63 0 0 1 .7-.1 .63 .63 0 0 1 .4 .5v1.9h-1.2v-1.9h.1v1.8h.9v-1.8a.49 .49 0 0 0-.5-.4 .49 .49 0 0 0-.5 .4zM128.2 74a.63 .63 0 0 1 .7-.1 .63 .63 0 0 1 .4 .5v1.9h-1.3v-1.9h.2v1.8h.9v-1.8a.49 .49 0 0 0-.5-.4 .49 .49 0 0 0-.5 .4zM131.8 66.8l.4-.2v.2a.43 .43 0 0 0-.4 .4 .43 .43 0 0 0 .4 .4h1.9v-.8h-1.9v-.2h2.1v1.2h-2.1a.61 .61 0 0 1-.6-.4 .61 .61 0 0 1 .2-.6zM131.8 68.6l.4-.2v.2a.48 .48 0 0 0-.4 .4 .48 .48 0 0 0 .4 .5h1.9v-.9h-1.9v-.2h2.1v1.3h-2.1a.64 .64 0 0 1-.6-.4 .64 .64 0 0 1 .2-.7z"/>
<path d="M131.8 70.5l.4-.2v.2a.43 .43 0 0 0-.4 .4 .43 .43 0 0 0 .4 .4h1.9v-.8h-1.9v-.2h2.1v1.2h-2.1a.61 .61 0 0 1-.6-.4 .61 .61 0 0 1 .2-.6zM131.8 61.2l.4-.1v.1a.43 .43 0 0 0-.4 .5 .43 .43 0 0 0 .4 .4h1.9v-.9h-1.9v-.1h2.1v1.2h-2.1a.61 .61 0 0 1-.6-.4 .61 .61 0 0 1 .2-.7zM131.8 63.1l.4-.2v.1a.48 .48 0 0 0-.4 .5 .48 .48 0 0 0 .4 .5h1.9v-1h-1.9v-.1h2.1v1.3h-2.1a.64 .64 0 0 1-.6-.4 .64 .64 0 0 1 .2-.7zM131.8 64.9l.4-.1v.1a.43 .43 0 0 0-.4 .5 .43 .43 0 0 0 .4 .4h1.9v-.9h-1.9v-.1h2.1v1.2h-2.1a.61 .61 0 0 1-.6-.4 .61 .61 0 0 1 .2-.7z"/>
</g>
<path d="M111.5 63.4h.5v.3h-.5z" fill="#fff"/>
<path d="M112.2 63.5h.5v.2h-.5zM112.9 63.5h.8v.2h-.8z" fill="#000"/>
<path d="M107.4 63.6h4.6" fill="none" stroke="#000" stroke-width=".2"/>
<path d="M111.5 61.6h.5v.2h-.5z" fill="#fff"/>
<path d="M112.2 61.6h.5v.2h-.5zM112.9 61.6h.8v.2h-.8z" fill="#000"/>
<path d="M107.4 61.7h4.6" fill="none" stroke="#000" stroke-width=".2"/>
<g fill="#fff">
<path d="M131.1 59.7h3.6z"/>
<path d="M131.1 59.6h3.6v.3h-3.6z"/>
</g>
<path d="M129.5 59.7h12.3" fill="none" stroke="#000" stroke-width=".2"/>
<g fill="#fff">
<path d="M131.1 71h3.6z"/>
<path d="M131.1 70.9h3.6v.3h-3.6z"/>
</g>
<path d="M129.5 71h12.3" fill="none" stroke="#000" stroke-width=".2"/>
<path d="M111.5 73.8h.5v.2h-.5z" fill="#fff"/>
<path d="M120.3 47.9v6.1M121.5 47.9v6.1M107 73.9h6.5" fill="none" stroke="#000" stroke-width=".2"/>
<g fill="#000">
<path d="M118.7 48.3l1.5 .3-1.5 .5zM118 48.5h1v.2h-1zM122.8 48.5h.9v.2h-.9zM121.6 48.6l1.4-.3v.8zM113.7 73.8h.7v.2h-.7zM114.6 73.8h1.6v.2h-1.6z"/>
<path d="M113.5 47.2v.2h4v-.2zM113.5 49.9v.2h4v-.2z"/>
</g>
<path d="M73.8 91h1v1.8h-1z" fill="#fff"/>
<path d="M73.7 90.9h1.2v2h-1.2v-1.9h.1v1.8h.9v-1.7h-.9z" fill="#000"/>
<path d="M75.6 91h1.2v1.8h-1.2z" fill="#fff"/>
<path d="M75.5 90.9l1.4 .1-.1 1.9h-1.3v-1.9h.2v1.8h1v-1.7h-1.1z" fill="#000"/>
<path d="M77.5 91h1.2v1.8h-1.2z" fill="#fff"/>
<path d="M77.4 91l1.3-.1v2l-1.3-.1v-1.8h.2v1.8h1v-1.7z" fill="#000"/>
<path d="M79.5 91h1v1.8h-1z" fill="#fff"/>
<path d="M79.4 90.9h1.2v2h-1.2v-1.9h.2v1.8h.8v-1.7h-.9z" fill="#000"/>
<path d="M81.3 91h1.2v1.8h-1.2z" fill="#fff"/>
<path d="M81.2 90.9l1.4 .1-.1 1.9h-1.3v-1.9h.2v1.8h1v-1.7h-1.1z" fill="#000"/>
<path d="M83.2 91h1.2v1.8h-1.2z" fill="#fff"/>
<path d="M83.1 91l1.4-.1v2l-1.4-.1v-1.8h.2v1.8h1v-1.7z" fill="#000"/>
<path d="M85.2 91h1v1.8h-1z" fill="#fff"/>
<path d="M85.1 90.9h1.2v2h-1.2v-1.9h.2v1.8h.9v-1.7h-1z" fill="#000"/>
<g fill="#bcbec0">
<path d="M80 64.9l.1 .8z"/>
<path d="M79.6 65.2l.8 .1z"/>
<path d="M80 72.1l.1 .5z"/>
</g>
<path d="M80 73v2.5" fill="none" stroke="#bcbec0" stroke-width=".2"/>
<path d="M80 58l.1 .6z" fill="#bcbec0"/>
<path d="M80 55v2.6M72.8 65.2h6.4" fill="none" stroke="#bcbec0" stroke-width=".2"/>
<path d="M72 65.2l.4 .1z" fill="#bcbec0"/>
<path d="M69.5 65.2h2M80.9 65.2h6.4" fill="none" stroke="#bcbec0" stroke-width=".2"/>
<path d="M87.8 65.2l.3 .1z" fill="#bcbec0"/>
<path d="M80 59v5.4M80 66.2v5.5M88.7 65.2h2" fill="none" stroke="#bcbec0" stroke-width=".2"/>
<path d="M117.2 59.7l11.4-.1 .4 .2v.7a.59 .59 0 0 0-.6 .6h-.2a.61 .61 0 0 1 .7-.6l-.1-.6-.2-.1h-11.3l-.2 .2 .1 10.8 .2 .1h11.3l.1-.3v-8.9l.1 .1a.57 .57 0 0 1-.6-.7h.1a.62 .62 0 0 0 .6 .5v9l-.2 .4-11.4 .1-.4-.2v-.3v-10.6z" fill="#000"/>
<g fill="#bcbec0">
<path d="M122.9 64.9l.1 1z"/>
<path d="M122.5 65.4l.9 .1z"/>
<path d="M122.9 70.6l.1 .6z"/>
</g>
<path d="M123 71.6v4" fill="none" stroke="#bcbec0" stroke-width=".2"/>
<path d="M122.9 58.6l.1 .6z" fill="#bcbec0"/>
<path d="M123 55.4v2.8M117.9 65.4h4.1" fill="none" stroke="#bcbec0" stroke-width=".2"/>
<path d="M117 65.4l.5 .1z" fill="#bcbec0"/>
<path d="M112.4 65.4h4.1M123.9 65.4h4.1" fill="none" stroke="#bcbec0" stroke-width=".2"/>
<path d="M128.5 65.4l.4 .1z" fill="#bcbec0"/>
<path d="M123 66.3v3.9M129.4 65.4h4.2" fill="none" stroke="#bcbec0" stroke-width=".2"/>
<path d="M122.9 59.9l.1 .5z" fill="#bcbec0"/>
<path d="M123 59.7v4.8" fill="none" stroke="#bcbec0" stroke-width=".2"/>
<path d="M63.6 88.1h4.3" fill="none" stroke="#000" stroke-width=".2"/>
<path d="M91 90.9h.5v.3h-.5z" fill="#fff"/>
<path d="M76.8 50.8h3.9M76.8 47.9h3.9M89.5 91h5" fill="none" stroke="#000" stroke-width=".2"/>
<path d="M136.8 69.4h.7l-.4 1.5zM137 68.8h.2v1h-.2zM137.1 74l.5 1.4h-.8zM137 75.1h.2v1.3h3v.2h-3.2zM87.1 90.9h1.2v.2h-1.2zM88.7 90.9h.5v.2h-.5z" fill="#000"/>
<path d="M133 73.8h.5v.2h-.5z" fill="#fff"/>
<path d="M132 73.9h6" fill="none" stroke="#000" stroke-width=".2"/>
<path d="M129.6 73.8h1.2v.2h-1.2zM131.2 73.8h.5v.2h-.5z" fill="#000"/>
<g fill="#808285">
<path d="M62.9 96.5h.9l4-2.9 .1 .2-4 2.8h-1z"/>
<path d="M67.3 93.5l1.5-.5-1 1.1z"/>
</g>
<path d="M129.9 60.2l4.6-3.5v.1l-4.4 3.6z" fill="#fff"/>
<g fill="#000">
<path d="M129 61l6.4-5h1.9v.1h-1.8l-6.4 5z"/>
<circle cx="129" cy="61.1" r=".37"/>
</g>
<path d="M127.3 59.8h1.4l.1 .6a.57 .57 0 0 0-.5 .7h.1a.59 .59 0 0 1 .6-.6v-.6l-.3-.2 1.7 .1-1.1 1a.38 .38 0 0 0-.6 .2 .38 .38 0 0 0 .4 .5 .38 .38 0 0 0 .3-.6l1.1-.9v2.8h-1.5v-1.2a.62 .62 0 0 1-.6-.5h-.1a.49 .49 0 0 0 .5 .7v1h-1.5z" fill="#e5e6e7"/>
<g fill="#616365">
<path d="M129.5 59.7h1z"/>
<path d="M128.2 61.1a.68 .68 0 0 0 .6 .7v1h.2v-1.2a.62 .62 0 0 1-.6-.5zM127.3 59.7l1.4 .1 .1 .6a.57 .57 0 0 0-.5 .7h.1a.59 .59 0 0 1 .6-.6l-.1-.8z"/>
</g>
<path d="M130.1 60.4l.4-.4zM129.9 60.2l.1 .1 .5-.6z" fill="#e5e6e7"/>
<g fill="#616365">
<path d="M129.3 60.8l1.2-1v.2l-1.1 .9z"/>
<circle cx="129" cy="61.1" r=".37"/>
</g>
<g fill="#000">
<path d="M127.3 59.6l.3 .1-.3 .2zM130.3 59.6h.3v.3zM127.3 62.5l.3 .3h-.3zM130.3 62.7h.2v-.2l.1 .1v.2z"/>
<path d="M129.7 59.6l.4 .1zM129 59.7l.5-.1zM128.4 59.7h.4zM127.8 59.7h.4z"/>
<path d="M127.3 60.1l.1 .4zM127.3 60.7l.1 .4zM127.3 61.3v.5zM127.3 61.9v.5z"/>
<path d="M127.8 62.8h.4zM128.4 62.8h.4zM129 62.8l.5-.1zM129.7 62.7l.4 .1z"/>
<path d="M130.5 61.9v.5zM130.5 61.3v.5zM130.5 60.7l.1 .4zM130.5 60.1l.1 .4z"/>
</g>
<path d="M151.6 47.9l.4-.2h.7v.9h-.7a.51 .51 0 0 1-.4-.7z" fill="#eceded"/>
<path d="M151.7 47.7l1-.1-.7 .1a.48 .48 0 0 0-.5 .4 .48 .48 0 0 0 .5 .5h.7l-.7 .1a.58 .58 0 0 1-.6-.4 .58 .58 0 0 1 .3-.6z" fill="#717375"/>
<path d="M149.4 45.4h1v.8a.55 .55 0 0 1-.5 .4 .55 .55 0 0 1-.5-.4z" fill="#eceded"/>
<path d="M149.3 45.4l.1 .8a.55 .55 0 0 0 .5 .4 .55 .55 0 0 0 .5-.4v-.8l.1 .8a.64 .64 0 0 1-.6 .5 .64 .64 0 0 1-.6-.5z" fill="#717375"/>
<path d="M147.2 45.4h1v.8a.49 .49 0 0 1-.5 .4 .49 .49 0 0 1-.5-.4z" fill="#eceded"/>
<path d="M147.1 45.4l.1 .8a.49 .49 0 0 0 .5 .4 .49 .49 0 0 0 .5-.4v-.8l.1 .8a.58 .58 0 0 1-.6 .5 .58 .58 0 0 1-.6-.5z" fill="#717375"/>
<path d="M146 45.4v1.2z" fill="#eceded"/>
<path d="M146.1 45.4v.8l-.1 .4z" fill="#717375"/>
<path d="M151.6 49.8l.3-.1h.8v1h-.2v1h.2v.8h-1.1l-.1-.1z" fill="#eceded"/>
<path d="M152.5 50.7v1h.2v-1zM151.7 49.7l-.3 .4 .1 2.4 .1-2.7 1.1-.2z" fill="#717375"/>
<g fill="#000">
<path d="M145.9 48.2l2.5 .1a2.15 2.15 0 0 0 1.8 1.4v2.9h-.2l.1-2.9a1.85 1.85 0 0 1-1.9-1.4l.1 .1h-2.4z"/>
<path d="M145.9 45.4l.1 .2 .3-.1zM145.9 45.9l.1 .4zM145.9 46.6l.1 .4zM145.9 47.2l.1 .5zM145.9 47.9l.1 .5zM145.9 48.6l.1 .5zM145.9 49.3l.1 .4zM145.9 50l.1 .4zM145.9 50.7l.1 .4zM145.9 51.4l.1 .4zM145.9 52.1l.1 .4zM146.2 52.4l.5 .1zM147 52.4l.4 .1zM147.7 52.4l.4 .1zM148.4 52.4l.4 .1zM149.1 52.4l.4 .1zM149.8 52.4l.5 .1zM150.5 52.4l.5 .1zM151.2 52.4l.5 .1zM152 52.4l.4 .1zM152.6 52.1l.1 .4zM152.6 51.4l.1 .4zM152.6 50.7l.1 .4zM152.6 50l.1 .4zM152.6 49.3l.1 .4zM152.6 48.6l.1 .5zM152.6 47.9l.1 .5zM152.6 47.2l.1 .5zM152.6 46.6l.1 .4zM152.6 45.9l.1 .4zM152.3 45.4l.4 .2v-.2zM151.6 45.4l.4 .1zM150.9 45.4l.4 .1zM150.2 45.4l.4 .1zM149.5 45.4l.4 .1zM148.7 45.4l.5 .1zM148 45.4l.5 .1zM147.3 45.4l.5 .1zM146.6 45.4l.4 .1z"/>
</g>
<path d="M136.2 47.9l.4-.2h.7v.9h-.7a.51 .51 0 0 1-.4-.7z" fill="#eceded"/>
<path d="M136.1 47.9l.5-.3h.7l-.7 .1a.48 .48 0 0 0-.5 .4 .48 .48 0 0 0 .5 .5h.7l-.7 .1a.58 .58 0 0 1-.5-.8z" fill="#717375"/>
<path d="M134.1 45.4h1v.8a.49 .49 0 0 1-.5 .4 .49 .49 0 0 1-.5-.4z" fill="#eceded"/>
<path d="M134 45.4l.1 .8a.49 .49 0 0 0 .5 .4 .49 .49 0 0 0 .5-.4v-.8l.1 .8a.58 .58 0 0 1-.6 .5 .58 .58 0 0 1-.6-.5z" fill="#717375"/>
<path d="M132 45.4h.9v1a.52 .52 0 0 1-.6 .2 .52 .52 0 0 1-.3-.4z" fill="#eceded"/>
<path d="M131.9 45.4l.1 1a.51 .51 0 0 0 .6 .2 .51 .51 0 0 0 .3-.4v-.8l.1 .8a.58 .58 0 0 1-.6 .5 .58 .58 0 0 1-.5-.5z" fill="#717375"/>
<path d="M130.7 45.4v1.2z" fill="#eceded"/>
<path d="M130.8 45.4l.1 .8-.2 .4z" fill="#717375"/>
<path d="M136.3 49.8l.3-.1h.7v2.8h-1v-.1z" fill="#eceded"/>
<path d="M137.2 50.7l.1 1zM136.4 49.7l-.2 .4v2.4h.1v-2.7l1-.2z" fill="#717375"/>
<g fill="#000">
<path d="M130.7 48.2h2.4l1.8 1.5v2.9h-.2v-2.8l-1.7-1.4h-2.3zM138.2 47.7h3.4a.68 .68 0 0 1 .7 .6v.7a.95 .95 0 0 0-1 .9 .95 .95 0 0 0 1 1v1.7h-.2l.1-1.7a.96 .96 0 0 1-1-1 .96 .96 0 0 1 1-.9l-.1-.7-.2-.4-3.7-.1z"/>
<path d="M130.6 45.4l.1 .2 .4-.1zM130.6 45.9l.1 .4zM130.6 46.6l.1 .4zM130.6 47.2l.1 .5zM130.6 47.9l.1 .5zM130.6 48.6l.1 .5zM130.6 49.3l.1 .4zM130.6 50l.1 .4zM130.6 50.7l.1 .4zM130.6 51.4l.1 .4zM130.6 52.1l.1 .4zM130.9 52.5l.4-.1zM131.6 52.5l.4-.1zM132.3 52.5l.5-.1zM133 52.5l.5-.1zM133.7 52.5l.5-.1zM134.5 52.5l.4-.1zM135.2 52.5l.4-.1zM135.9 52.5l.4-.1zM136.6 52.5l.4-.1zM137.3 52.1v.4zM137.3 51.4v.4zM137.3 50.7v.4zM137.3 50v.4zM137.3 49.3v.4zM137.3 48.6v.5zM137.3 47.9v.5zM137.3 47.2v.5zM137.3 46.6v.4zM137.3 45.9v.4zM137 45.4l.3 .2 .1-.1zM136.3 45.4l.5 .1zM135.6 45.4l.5 .1zM134.9 45.4l.4 .1zM134.2 45.4l.4 .1zM133.5 45.4l.4 .1zM132.8 45.4l.4 .1zM132 45.4l.5 .1zM131.3 45.4l.5 .1z"/>
</g>
<path d="M143.9 47.2h1.1v.9h-.9a.47 .47 0 0 1-.5-.3 .47 .47 0 0 1 .3-.6z" fill="#eaeaeb"/>
<path d="M143.8 47.1h1.2l-.9 .1a.48 .48 0 0 0-.5 .4 .48 .48 0 0 0 .5 .5h.9l-.9 .1a.56 .56 0 0 1-.5-.4 .56 .56 0 0 1 .2-.7z" fill="#5c5d60"/>
<path d="M141.6 45.4h1v.4a.49 .49 0 0 1-.5 .4 .49 .49 0 0 1-.5-.4z" fill="#eaeaeb"/>
<path d="M141.5 45.4l.1 .4a.49 .49 0 0 0 .5 .4 .49 .49 0 0 0 .5-.4v-.4a.58 .58 0 0 1-.3 .9 .58 .58 0 0 1-.8-.5z" fill="#5c5d60"/>
<path d="M139.5 45.4h.9v.4a.49 .49 0 0 1-.5 .4 .49 .49 0 0 1-.4-.4z" fill="#eaeaeb"/>
<path d="M139.4 45.4l.1 .4a.49 .49 0 0 0 .4 .4 .49 .49 0 0 0 .5-.4v-.4a.58 .58 0 0 1-.3 .9 .58 .58 0 0 1-.7-.5z" fill="#5c5d60"/>
<path d="M143.9 49.3l1.1-.1v1h-.4v1.1h.4v1l-1-.1-.3-.4v-2z" fill="#eaeaeb"/>
<path d="M144.6 50.2v1.1h.4l-.3-.1v-.9l.3-.1zM143.9 49.3l-.3 .5v2l.1 .4 .3 .1h1l-1.1-.1-.2-.6v-2.1l.3-.2 1-.2z" fill="#5c5d60"/>
<path d="M138.3 45.4v.2l.4-.2zM138.3 45.9v.4zM138.3 46.6v.4zM138.3 47.2v.5zM138.3 47.9v.5zM138.3 48.6v.5zM138.3 49.3v.4zM138.3 50v.4zM138.3 50.7v.4zM138.3 51.4v.4zM138.3 52.1v.4zM138.6 52.5l.4-.1zM139.3 52.5l.4-.1zM140 52.5l.4-.1zM140.7 52.5l.5-.1zM141.4 52.5l.5-.1zM142.1 52.5l.5-.1zM142.8 52.5l.5-.1zM143.6 52.5l.4-.1zM144.3 52.5l.4-.1zM145 52.1v.4zM145 51.4v.4zM145 50.7v.4zM145 50v.4zM145 49.3v.4zM145 48.6v.5zM145 47.9v.5zM145 47.2v.5zM145 46.6v.4zM145 45.9v.4zM144.7 45.4l.3 .2 .1-.1zM144 45.4h.5zM143.3 45.4h.4zM142.6 45.4h.4zM141.9 45.4h.4zM141.2 45.4h.4zM140.4 45.4h.5zM139.7 45.4h.5zM139 45.4h.5z" fill="#000"/>
<g fill="#727476">
<path d="M128.1 70.2l6.7 6.4-.1 5.9-.1-5.8-6.5-6.3z"/>
<circle cx="128.1" cy="70.3" r=".49"/>
</g>
<g fill="#636466">
<path d="M63.2 52.4h1.8l4.7 4.2-.1 .1-4.7-4.1h-1.7z"/>
<circle cx="69.7" cy="56.6" r=".38"/>
</g>
<g fill="#000">
<path d="M138.9 255.4h.6l.2 1.7 .2-1.7h.4l.3 1.7 .2-1.7h.5l-.4 2.1h-.5l-.3-1.4-.2 1.4h-.5zM142.6 255.4h.5l.2 1.7 .3-1.7h.4l.3 1.7 .2-1.7h.5l-.5 2.1h-.5l-.2-1.4-.2 1.4h-.6zM146.2 255.4h.5l.2 1.7 .3-1.7h.4l.3 1.7 .2-1.7h.5l-.4 2.1h-.6l-.2-1.4-.2 1.4h-.5zM150 257h.5v.5h-.5zM155.3 255.4h.5v.2a.49 .49 0 0 1 .4-.3 .49 .49 0 0 1 .4 .3l.1 1.9h-.5v-1.6l-.2-.1-.2 .2v1.5h-.5zM161.3 254.7h.5v2.8h-.5zM169.6 257h.5v.5h-.5zM172 255.5a.69 .69 0 0 1 .8-.1 .69 .69 0 0 1 .3 .7h-.5v-.3h-.3l.1 1.3 .2 .1v-.5h.5a.7 .7 0 0 1-.6 .9 .7 .7 0 0 1-.7-.8v-1.1zM177.7 255.4h.5v.2l.3-.2h.3l.3 .2a.55 .55 0 0 1 .5-.2 .55 .55 0 0 1 .5 .4v1.7h-.5v-1.6l-.2-.2-.3 .2v1.6h-.5v-1.6l-.2-.2-.2 .2v1.6h-.5z"/>
<path d="M101.4 251.5h.9l1.8 2.9v-2.9h.9v4.4h-.8l-2-2.9v2.9h-.8zM109.4 251.5h.9v3.7h2v.7h-2.9zM106.7 251.5h.9l1.6 4.4h-.8l-.4-1h-1.6l-.3 1h-.9zM98.7 251.5h.8l1.7 4.4h-.9l-.3-1h-1.7l-.3 1h-.8zM113 251.9a2.12 2.12 0 0 1 2.6 0 2.12 2.12 0 0 1 .7 2.5 2.09 2.09 0 0 1-2.7 1.4 2.09 2.09 0 0 1-1.3-2.7zM117.4 252a1.88 1.88 0 0 1 3.1 .9h-.8a1.22 1.22 0 0 0-1.5-.7 1.22 1.22 0 0 0-.8 1.5 1.25 1.25 0 0 0 1 1.5 1.25 1.25 0 0 0 1.4-.9h-1v-.7h1.8v2.2h-.7v-.4a1.93 1.93 0 0 1-2.3 .4 1.93 1.93 0 0 1-1-2.1l.3-1.2zM85.7 251.6h9.8v9.7h-9.8zM104.6 256.9h1l.9 3.1 1-3.1h.9l-1.4 4.3h-.9zM114 256.9h3.1v.8h-2.3v.9h2v.7h-2v1.2h2.4v.7h-3.2zM101.1 256.9h3.3v.7h-2.4v.9h2.1v.8h-2.1v1.2h2.4v.7h-3.3zM97.1 256.9h1.7a2.23 2.23 0 0 1 2 1.9 2.23 2.23 0 0 1-1.4 2.3l-2.3 .1zM108.6 256.9h1v4.3h-1zM110.6 257.3a1.94 1.94 0 0 1 3.2 1h-.9l-.1-.2a.99 .99 0 0 0-1.1-.6 .99 .99 0 0 0-.8 .9 1.68 1.68 0 0 0 1.1 2.2 1.11 1.11 0 0 0 1-.8h.8a1.93 1.93 0 0 1-1.9 1.5 1.93 1.93 0 0 1-1.9-1.6 2.48 2.48 0 0 1 .6-2.4zM117.7 257.2a1.74 1.74 0 0 1 3 .9h-.9a.91 .91 0 0 0-.8-.6 .91 .91 0 0 0-.8 .5 1.11 1.11 0 0 0 1.2 .7 1.3 1.3 0 0 1 1.4 1.1 1.3 1.3 0 0 1-1.1 1.5 1.71 1.71 0 0 1-2.5-1.4h.9a.97 .97 0 0 0 .9 .8 .97 .97 0 0 0 .9-.6 1.06 1.06 0 0 0-1.2-.8 1.21 1.21 0 0 1-1.3-.7 1.21 1.21 0 0 1 .3-1.4zM107.2 252.4l-.6 1.9h1.1zM99.1 252.4l-.5 1.9h1.1zM113.4 252.7a1.6 1.6 0 0 0 .9 2.5 1.55 1.55 0 0 0 1.2-1.5 1.55 1.55 0 0 0-1.2-1.5l-.5 .1zM87.7 253.1v7l6.2-3.6zM98 257.6v2.9a1.33 1.33 0 0 0 1.9-1 1.51 1.51 0 0 0-1.9-1.9z"/>
<path d="M152.4 255.5a.74 .74 0 0 1 .8-.2 .74 .74 0 0 1 .5 .7v1.5h-.5v-.2a.57 .57 0 0 1-.8 .2 .57 .57 0 0 1-.1-.9l.9-.6-.3-.3-.1 .1-.1 .2h-.5zM152.8 256.7l-.1 .4 .2 .1 .2-.1 .1-.7z"/>
<path d="M158.4 255.5a.73 .73 0 0 1 .8-.2 .73 .73 0 0 1 .5 .7v1.5h-.4l-.1-.2a.6 .6 0 0 1-.9 .1 .6 .6 0 0 1 .1-1l.8-.4-.2-.3-.2 .1-.1 .2h-.5zM158.8 256.7l-.1 .4 .2 .1 .2-.1 .1-.7z"/>
<path d="M163.6 255.6a.75 .75 0 0 1 .9-.2 .75 .75 0 0 1 .4 .7 1.04 1.04 0 0 1-.7 1.5l-.4-.1a1.95 1.95 0 0 1-.2-1.9zM164 255.8l-.1 1.2 .3 .2 .2-.2v-1.1v-.1z"/>
<path d="M166.6 255.5l.1-.1a.47 .47 0 0 1 .7 .2v-.2h.5l-.1 2.3a.73 .73 0 0 1-.6 .5 .73 .73 0 0 1-.7-.5l.8 .1 .1-.5a.53 .53 0 0 1-.7 .2 .53 .53 0 0 1-.3-.6zM167 255.8l-.1 1 .2 .4 .3-.2v-1l-.1-.2z"/>
<path d="M174.8 255.6a.74 .74 0 0 1 .8-.2 .74 .74 0 0 1 .5 .7 1.05 1.05 0 0 1-.7 1.5l-.4-.1a1.53 1.53 0 0 1-.3-1.7zM175.2 255.8l-.1 1.2 .3 .2 .2-.2v-1.1l-.1-.1z"/>
</g>
<path d="M124.6 251.6h70v9.7h-70z" fill="none" stroke="#000" stroke-width=".35"/>
<use href="#words"/>
</svg>
